VERSION 5.8 ;
BUSBITCHARS "[]" ;
DIVIDERCHAR "/" ;
UNITS
    DATABASE MICRONS 1000 ;
END UNITS

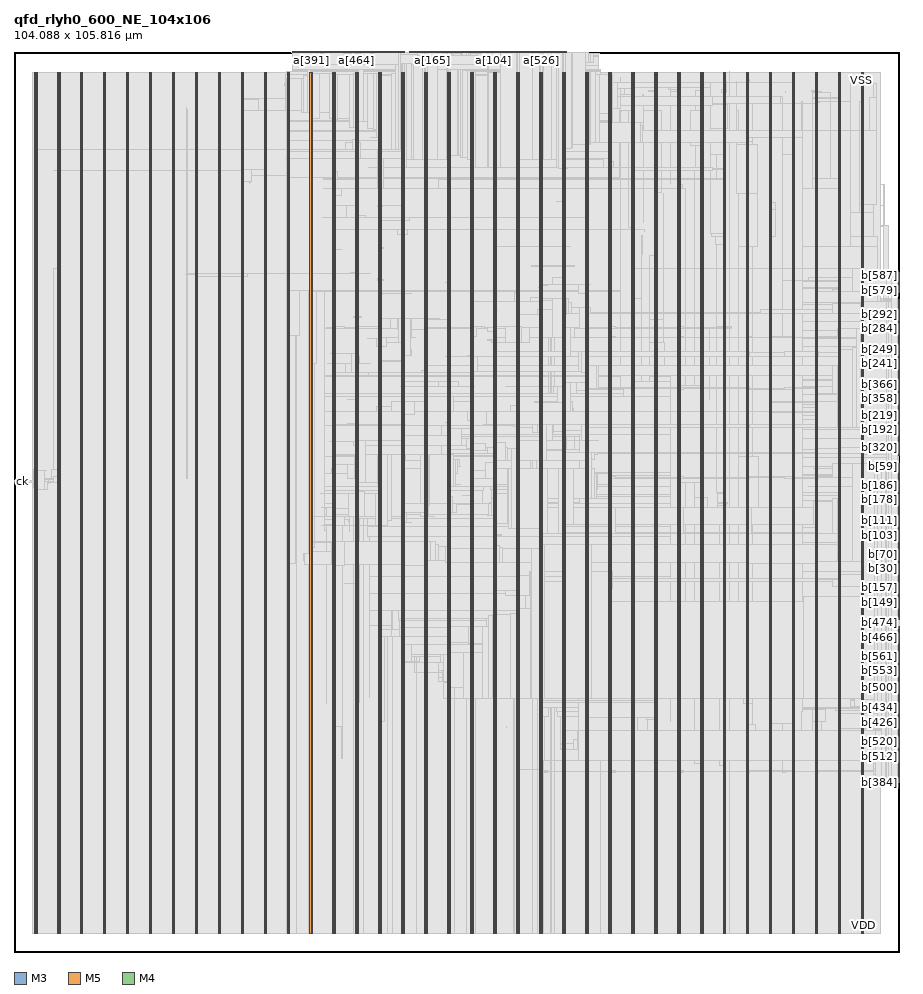
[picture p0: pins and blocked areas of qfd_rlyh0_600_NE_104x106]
MACRO qfd_rlyh0_600_NE_104x106
  FOREIGN qfd_rlyh0_600_NE_104x106 0 0 ;
  CLASS BLOCK ;
  SIZE 104.088 BY 105.816 ;
  PIN a[0]
    DIRECTION INPUT ;
    USE SIGNAL ;
    PORT
      LAYER M3 ;
        RECT  58.068 105.779 58.086 105.816 ;
    END
  END a[0]
  PIN a[100]
    DIRECTION INPUT ;
    USE SIGNAL ;
    PORT
      LAYER M3 ;
        RECT  56.052 105.779 56.07 105.816 ;
    END
  END a[100]
  PIN a[101]
    DIRECTION INPUT ;
    USE SIGNAL ;
    PORT
      LAYER M3 ;
        RECT  56.124 105.779 56.142 105.816 ;
    END
  END a[101]
  PIN a[102]
    DIRECTION INPUT ;
    USE SIGNAL ;
    PORT
      LAYER M3 ;
        RECT  56.196 105.779 56.214 105.816 ;
    END
  END a[102]
  PIN a[103]
    DIRECTION INPUT ;
    USE SIGNAL ;
    PORT
      LAYER M3 ;
        RECT  56.268 105.779 56.286 105.816 ;
    END
  END a[103]
  PIN a[104]
    DIRECTION INPUT ;
    USE SIGNAL ;
    PORT
      LAYER M3 ;
        RECT  56.34 105.779 56.358 105.816 ;
    END
  END a[104]
  PIN a[105]
    DIRECTION INPUT ;
    USE SIGNAL ;
    PORT
      LAYER M3 ;
        RECT  56.412 105.779 56.43 105.816 ;
    END
  END a[105]
  PIN a[106]
    DIRECTION INPUT ;
    USE SIGNAL ;
    PORT
      LAYER M3 ;
        RECT  56.484 105.779 56.502 105.816 ;
    END
  END a[106]
  PIN a[107]
    DIRECTION INPUT ;
    USE SIGNAL ;
    PORT
      LAYER M3 ;
        RECT  56.556 105.779 56.574 105.816 ;
    END
  END a[107]
  PIN a[108]
    DIRECTION INPUT ;
    USE SIGNAL ;
    PORT
      LAYER M3 ;
        RECT  56.628 105.779 56.646 105.816 ;
    END
  END a[108]
  PIN a[109]
    DIRECTION INPUT ;
    USE SIGNAL ;
    PORT
      LAYER M3 ;
        RECT  56.7 105.779 56.718 105.816 ;
    END
  END a[109]
  PIN a[10]
    DIRECTION INPUT ;
    USE SIGNAL ;
    PORT
      LAYER M3 ;
        RECT  58.788 105.779 58.806 105.816 ;
    END
  END a[10]
  PIN a[110]
    DIRECTION INPUT ;
    USE SIGNAL ;
    PORT
      LAYER M3 ;
        RECT  56.772 105.779 56.79 105.816 ;
    END
  END a[110]
  PIN a[111]
    DIRECTION INPUT ;
    USE SIGNAL ;
    PORT
      LAYER M3 ;
        RECT  56.844 105.779 56.862 105.816 ;
    END
  END a[111]
  PIN a[112]
    DIRECTION INPUT ;
    USE SIGNAL ;
    PORT
      LAYER M3 ;
        RECT  56.916 105.779 56.934 105.816 ;
    END
  END a[112]
  PIN a[113]
    DIRECTION INPUT ;
    USE SIGNAL ;
    PORT
      LAYER M3 ;
        RECT  56.988 105.779 57.006 105.816 ;
    END
  END a[113]
  PIN a[114]
    DIRECTION INPUT ;
    USE SIGNAL ;
    PORT
      LAYER M3 ;
        RECT  57.06 105.779 57.078 105.816 ;
    END
  END a[114]
  PIN a[115]
    DIRECTION INPUT ;
    USE SIGNAL ;
    PORT
      LAYER M3 ;
        RECT  57.132 105.779 57.15 105.816 ;
    END
  END a[115]
  PIN a[116]
    DIRECTION INPUT ;
    USE SIGNAL ;
    PORT
      LAYER M3 ;
        RECT  57.204 105.779 57.222 105.816 ;
    END
  END a[116]
  PIN a[117]
    DIRECTION INPUT ;
    USE SIGNAL ;
    PORT
      LAYER M3 ;
        RECT  57.276 105.779 57.294 105.816 ;
    END
  END a[117]
  PIN a[118]
    DIRECTION INPUT ;
    USE SIGNAL ;
    PORT
      LAYER M3 ;
        RECT  57.348 105.779 57.366 105.816 ;
    END
  END a[118]
  PIN a[119]
    DIRECTION INPUT ;
    USE SIGNAL ;
    PORT
      LAYER M3 ;
        RECT  57.42 105.779 57.438 105.816 ;
    END
  END a[119]
  PIN a[11]
    DIRECTION INPUT ;
    USE SIGNAL ;
    PORT
      LAYER M3 ;
        RECT  58.86 105.779 58.878 105.816 ;
    END
  END a[11]
  PIN a[120]
    DIRECTION INPUT ;
    USE SIGNAL ;
    PORT
      LAYER M3 ;
        RECT  57.492 105.779 57.51 105.816 ;
    END
  END a[120]
  PIN a[121]
    DIRECTION INPUT ;
    USE SIGNAL ;
    PORT
      LAYER M3 ;
        RECT  57.564 105.779 57.582 105.816 ;
    END
  END a[121]
  PIN a[122]
    DIRECTION INPUT ;
    USE SIGNAL ;
    PORT
      LAYER M3 ;
        RECT  57.636 105.779 57.654 105.816 ;
    END
  END a[122]
  PIN a[123]
    DIRECTION INPUT ;
    USE SIGNAL ;
    PORT
      LAYER M3 ;
        RECT  57.708 105.779 57.726 105.816 ;
    END
  END a[123]
  PIN a[124]
    DIRECTION INPUT ;
    USE SIGNAL ;
    PORT
      LAYER M3 ;
        RECT  57.78 105.779 57.798 105.816 ;
    END
  END a[124]
  PIN a[125]
    DIRECTION INPUT ;
    USE SIGNAL ;
    PORT
      LAYER M3 ;
        RECT  57.852 105.779 57.87 105.816 ;
    END
  END a[125]
  PIN a[126]
    DIRECTION INPUT ;
    USE SIGNAL ;
    PORT
      LAYER M3 ;
        RECT  57.924 105.779 57.942 105.816 ;
    END
  END a[126]
  PIN a[127]
    DIRECTION INPUT ;
    USE SIGNAL ;
    PORT
      LAYER M3 ;
        RECT  57.996 105.779 58.014 105.816 ;
    END
  END a[127]
  PIN a[128]
    DIRECTION INPUT ;
    USE SIGNAL ;
    PORT
      LAYER M3 ;
        RECT  53.46 105.779 53.478 105.816 ;
    END
  END a[128]
  PIN a[129]
    DIRECTION INPUT ;
    USE SIGNAL ;
    PORT
      LAYER M3 ;
        RECT  53.532 105.779 53.55 105.816 ;
    END
  END a[129]
  PIN a[12]
    DIRECTION INPUT ;
    USE SIGNAL ;
    PORT
      LAYER M3 ;
        RECT  58.932 105.779 58.95 105.816 ;
    END
  END a[12]
  PIN a[130]
    DIRECTION INPUT ;
    USE SIGNAL ;
    PORT
      LAYER M3 ;
        RECT  53.604 105.779 53.622 105.816 ;
    END
  END a[130]
  PIN a[131]
    DIRECTION INPUT ;
    USE SIGNAL ;
    PORT
      LAYER M3 ;
        RECT  53.676 105.779 53.694 105.816 ;
    END
  END a[131]
  PIN a[132]
    DIRECTION INPUT ;
    USE SIGNAL ;
    PORT
      LAYER M3 ;
        RECT  53.748 105.779 53.766 105.816 ;
    END
  END a[132]
  PIN a[133]
    DIRECTION INPUT ;
    USE SIGNAL ;
    PORT
      LAYER M3 ;
        RECT  53.82 105.779 53.838 105.816 ;
    END
  END a[133]
  PIN a[134]
    DIRECTION INPUT ;
    USE SIGNAL ;
    PORT
      LAYER M3 ;
        RECT  53.892 105.779 53.91 105.816 ;
    END
  END a[134]
  PIN a[135]
    DIRECTION INPUT ;
    USE SIGNAL ;
    PORT
      LAYER M3 ;
        RECT  53.964 105.779 53.982 105.816 ;
    END
  END a[135]
  PIN a[136]
    DIRECTION INPUT ;
    USE SIGNAL ;
    PORT
      LAYER M3 ;
        RECT  54.036 105.779 54.054 105.816 ;
    END
  END a[136]
  PIN a[137]
    DIRECTION INPUT ;
    USE SIGNAL ;
    PORT
      LAYER M3 ;
        RECT  54.108 105.779 54.126 105.816 ;
    END
  END a[137]
  PIN a[138]
    DIRECTION INPUT ;
    USE SIGNAL ;
    PORT
      LAYER M3 ;
        RECT  54.18 105.779 54.198 105.816 ;
    END
  END a[138]
  PIN a[139]
    DIRECTION INPUT ;
    USE SIGNAL ;
    PORT
      LAYER M3 ;
        RECT  54.252 105.779 54.27 105.816 ;
    END
  END a[139]
  PIN a[13]
    DIRECTION INPUT ;
    USE SIGNAL ;
    PORT
      LAYER M3 ;
        RECT  59.004 105.779 59.022 105.816 ;
    END
  END a[13]
  PIN a[140]
    DIRECTION INPUT ;
    USE SIGNAL ;
    PORT
      LAYER M3 ;
        RECT  54.324 105.779 54.342 105.816 ;
    END
  END a[140]
  PIN a[141]
    DIRECTION INPUT ;
    USE SIGNAL ;
    PORT
      LAYER M3 ;
        RECT  54.396 105.779 54.414 105.816 ;
    END
  END a[141]
  PIN a[142]
    DIRECTION INPUT ;
    USE SIGNAL ;
    PORT
      LAYER M3 ;
        RECT  54.468 105.779 54.486 105.816 ;
    END
  END a[142]
  PIN a[143]
    DIRECTION INPUT ;
    USE SIGNAL ;
    PORT
      LAYER M3 ;
        RECT  54.54 105.779 54.558 105.816 ;
    END
  END a[143]
  PIN a[144]
    DIRECTION INPUT ;
    USE SIGNAL ;
    PORT
      LAYER M3 ;
        RECT  54.612 105.779 54.63 105.816 ;
    END
  END a[144]
  PIN a[145]
    DIRECTION INPUT ;
    USE SIGNAL ;
    PORT
      LAYER M3 ;
        RECT  54.684 105.779 54.702 105.816 ;
    END
  END a[145]
  PIN a[146]
    DIRECTION INPUT ;
    USE SIGNAL ;
    PORT
      LAYER M3 ;
        RECT  54.756 105.779 54.774 105.816 ;
    END
  END a[146]
  PIN a[147]
    DIRECTION INPUT ;
    USE SIGNAL ;
    PORT
      LAYER M3 ;
        RECT  54.828 105.779 54.846 105.816 ;
    END
  END a[147]
  PIN a[148]
    DIRECTION INPUT ;
    USE SIGNAL ;
    PORT
      LAYER M3 ;
        RECT  54.9 105.779 54.918 105.816 ;
    END
  END a[148]
  PIN a[149]
    DIRECTION INPUT ;
    USE SIGNAL ;
    PORT
      LAYER M3 ;
        RECT  54.972 105.779 54.99 105.816 ;
    END
  END a[149]
  PIN a[14]
    DIRECTION INPUT ;
    USE SIGNAL ;
    PORT
      LAYER M3 ;
        RECT  59.076 105.779 59.094 105.816 ;
    END
  END a[14]
  PIN a[150]
    DIRECTION INPUT ;
    USE SIGNAL ;
    PORT
      LAYER M3 ;
        RECT  55.044 105.779 55.062 105.816 ;
    END
  END a[150]
  PIN a[151]
    DIRECTION INPUT ;
    USE SIGNAL ;
    PORT
      LAYER M3 ;
        RECT  55.116 105.779 55.134 105.816 ;
    END
  END a[151]
  PIN a[152]
    DIRECTION INPUT ;
    USE SIGNAL ;
    PORT
      LAYER M3 ;
        RECT  55.188 105.779 55.206 105.816 ;
    END
  END a[152]
  PIN a[153]
    DIRECTION INPUT ;
    USE SIGNAL ;
    PORT
      LAYER M3 ;
        RECT  55.26 105.779 55.278 105.816 ;
    END
  END a[153]
  PIN a[154]
    DIRECTION INPUT ;
    USE SIGNAL ;
    PORT
      LAYER M3 ;
        RECT  55.332 105.779 55.35 105.816 ;
    END
  END a[154]
  PIN a[155]
    DIRECTION INPUT ;
    USE SIGNAL ;
    PORT
      LAYER M3 ;
        RECT  55.404 105.779 55.422 105.816 ;
    END
  END a[155]
  PIN a[156]
    DIRECTION INPUT ;
    USE SIGNAL ;
    PORT
      LAYER M3 ;
        RECT  55.476 105.779 55.494 105.816 ;
    END
  END a[156]
  PIN a[157]
    DIRECTION INPUT ;
    USE SIGNAL ;
    PORT
      LAYER M3 ;
        RECT  55.548 105.779 55.566 105.816 ;
    END
  END a[157]
  PIN a[158]
    DIRECTION INPUT ;
    USE SIGNAL ;
    PORT
      LAYER M3 ;
        RECT  55.62 105.779 55.638 105.816 ;
    END
  END a[158]
  PIN a[159]
    DIRECTION INPUT ;
    USE SIGNAL ;
    PORT
      LAYER M3 ;
        RECT  55.692 105.779 55.71 105.816 ;
    END
  END a[159]
  PIN a[15]
    DIRECTION INPUT ;
    USE SIGNAL ;
    PORT
      LAYER M3 ;
        RECT  59.148 105.779 59.166 105.816 ;
    END
  END a[15]
  PIN a[160]
    DIRECTION INPUT ;
    USE SIGNAL ;
    PORT
      LAYER M3 ;
        RECT  48.852 105.779 48.87 105.816 ;
    END
  END a[160]
  PIN a[161]
    DIRECTION INPUT ;
    USE SIGNAL ;
    PORT
      LAYER M3 ;
        RECT  48.924 105.779 48.942 105.816 ;
    END
  END a[161]
  PIN a[162]
    DIRECTION INPUT ;
    USE SIGNAL ;
    PORT
      LAYER M3 ;
        RECT  48.996 105.779 49.014 105.816 ;
    END
  END a[162]
  PIN a[163]
    DIRECTION INPUT ;
    USE SIGNAL ;
    PORT
      LAYER M3 ;
        RECT  49.068 105.779 49.086 105.816 ;
    END
  END a[163]
  PIN a[164]
    DIRECTION INPUT ;
    USE SIGNAL ;
    PORT
      LAYER M3 ;
        RECT  49.14 105.779 49.158 105.816 ;
    END
  END a[164]
  PIN a[165]
    DIRECTION INPUT ;
    USE SIGNAL ;
    PORT
      LAYER M3 ;
        RECT  49.212 105.779 49.23 105.816 ;
    END
  END a[165]
  PIN a[166]
    DIRECTION INPUT ;
    USE SIGNAL ;
    PORT
      LAYER M3 ;
        RECT  49.284 105.779 49.302 105.816 ;
    END
  END a[166]
  PIN a[167]
    DIRECTION INPUT ;
    USE SIGNAL ;
    PORT
      LAYER M3 ;
        RECT  49.356 105.779 49.374 105.816 ;
    END
  END a[167]
  PIN a[168]
    DIRECTION INPUT ;
    USE SIGNAL ;
    PORT
      LAYER M3 ;
        RECT  49.428 105.779 49.446 105.816 ;
    END
  END a[168]
  PIN a[169]
    DIRECTION INPUT ;
    USE SIGNAL ;
    PORT
      LAYER M3 ;
        RECT  49.5 105.779 49.518 105.816 ;
    END
  END a[169]
  PIN a[16]
    DIRECTION INPUT ;
    USE SIGNAL ;
    PORT
      LAYER M3 ;
        RECT  59.22 105.779 59.238 105.816 ;
    END
  END a[16]
  PIN a[170]
    DIRECTION INPUT ;
    USE SIGNAL ;
    PORT
      LAYER M3 ;
        RECT  49.572 105.779 49.59 105.816 ;
    END
  END a[170]
  PIN a[171]
    DIRECTION INPUT ;
    USE SIGNAL ;
    PORT
      LAYER M3 ;
        RECT  49.644 105.779 49.662 105.816 ;
    END
  END a[171]
  PIN a[172]
    DIRECTION INPUT ;
    USE SIGNAL ;
    PORT
      LAYER M3 ;
        RECT  49.716 105.779 49.734 105.816 ;
    END
  END a[172]
  PIN a[173]
    DIRECTION INPUT ;
    USE SIGNAL ;
    PORT
      LAYER M3 ;
        RECT  49.788 105.779 49.806 105.816 ;
    END
  END a[173]
  PIN a[174]
    DIRECTION INPUT ;
    USE SIGNAL ;
    PORT
      LAYER M3 ;
        RECT  49.86 105.779 49.878 105.816 ;
    END
  END a[174]
  PIN a[175]
    DIRECTION INPUT ;
    USE SIGNAL ;
    PORT
      LAYER M3 ;
        RECT  49.932 105.779 49.95 105.816 ;
    END
  END a[175]
  PIN a[176]
    DIRECTION INPUT ;
    USE SIGNAL ;
    PORT
      LAYER M3 ;
        RECT  50.004 105.779 50.022 105.816 ;
    END
  END a[176]
  PIN a[177]
    DIRECTION INPUT ;
    USE SIGNAL ;
    PORT
      LAYER M3 ;
        RECT  50.076 105.779 50.094 105.816 ;
    END
  END a[177]
  PIN a[178]
    DIRECTION INPUT ;
    USE SIGNAL ;
    PORT
      LAYER M3 ;
        RECT  50.148 105.779 50.166 105.816 ;
    END
  END a[178]
  PIN a[179]
    DIRECTION INPUT ;
    USE SIGNAL ;
    PORT
      LAYER M3 ;
        RECT  50.22 105.779 50.238 105.816 ;
    END
  END a[179]
  PIN a[17]
    DIRECTION INPUT ;
    USE SIGNAL ;
    PORT
      LAYER M3 ;
        RECT  59.292 105.779 59.31 105.816 ;
    END
  END a[17]
  PIN a[180]
    DIRECTION INPUT ;
    USE SIGNAL ;
    PORT
      LAYER M3 ;
        RECT  50.292 105.779 50.31 105.816 ;
    END
  END a[180]
  PIN a[181]
    DIRECTION INPUT ;
    USE SIGNAL ;
    PORT
      LAYER M3 ;
        RECT  50.364 105.779 50.382 105.816 ;
    END
  END a[181]
  PIN a[182]
    DIRECTION INPUT ;
    USE SIGNAL ;
    PORT
      LAYER M3 ;
        RECT  50.436 105.779 50.454 105.816 ;
    END
  END a[182]
  PIN a[183]
    DIRECTION INPUT ;
    USE SIGNAL ;
    PORT
      LAYER M3 ;
        RECT  50.508 105.779 50.526 105.816 ;
    END
  END a[183]
  PIN a[184]
    DIRECTION INPUT ;
    USE SIGNAL ;
    PORT
      LAYER M3 ;
        RECT  50.58 105.779 50.598 105.816 ;
    END
  END a[184]
  PIN a[185]
    DIRECTION INPUT ;
    USE SIGNAL ;
    PORT
      LAYER M3 ;
        RECT  50.652 105.779 50.67 105.816 ;
    END
  END a[185]
  PIN a[186]
    DIRECTION INPUT ;
    USE SIGNAL ;
    PORT
      LAYER M3 ;
        RECT  50.724 105.779 50.742 105.816 ;
    END
  END a[186]
  PIN a[187]
    DIRECTION INPUT ;
    USE SIGNAL ;
    PORT
      LAYER M3 ;
        RECT  50.796 105.779 50.814 105.816 ;
    END
  END a[187]
  PIN a[188]
    DIRECTION INPUT ;
    USE SIGNAL ;
    PORT
      LAYER M3 ;
        RECT  50.868 105.779 50.886 105.816 ;
    END
  END a[188]
  PIN a[189]
    DIRECTION INPUT ;
    USE SIGNAL ;
    PORT
      LAYER M3 ;
        RECT  50.94 105.779 50.958 105.816 ;
    END
  END a[189]
  PIN a[18]
    DIRECTION INPUT ;
    USE SIGNAL ;
    PORT
      LAYER M3 ;
        RECT  59.364 105.779 59.382 105.816 ;
    END
  END a[18]
  PIN a[190]
    DIRECTION INPUT ;
    USE SIGNAL ;
    PORT
      LAYER M3 ;
        RECT  51.012 105.779 51.03 105.816 ;
    END
  END a[190]
  PIN a[191]
    DIRECTION INPUT ;
    USE SIGNAL ;
    PORT
      LAYER M3 ;
        RECT  51.084 105.779 51.102 105.816 ;
    END
  END a[191]
  PIN a[192]
    DIRECTION INPUT ;
    USE SIGNAL ;
    PORT
      LAYER M5 ;
        RECT  49.68 105.732 49.704 105.816 ;
    END
  END a[192]
  PIN a[193]
    DIRECTION INPUT ;
    USE SIGNAL ;
    PORT
      LAYER M5 ;
        RECT  49.776 105.732 49.8 105.816 ;
    END
  END a[193]
  PIN a[194]
    DIRECTION INPUT ;
    USE SIGNAL ;
    PORT
      LAYER M5 ;
        RECT  49.872 105.732 49.896 105.816 ;
    END
  END a[194]
  PIN a[195]
    DIRECTION INPUT ;
    USE SIGNAL ;
    PORT
      LAYER M5 ;
        RECT  49.968 105.732 49.992 105.816 ;
    END
  END a[195]
  PIN a[196]
    DIRECTION INPUT ;
    USE SIGNAL ;
    PORT
      LAYER M5 ;
        RECT  50.064 105.732 50.088 105.816 ;
    END
  END a[196]
  PIN a[197]
    DIRECTION INPUT ;
    USE SIGNAL ;
    PORT
      LAYER M5 ;
        RECT  50.16 105.732 50.184 105.816 ;
    END
  END a[197]
  PIN a[198]
    DIRECTION INPUT ;
    USE SIGNAL ;
    PORT
      LAYER M5 ;
        RECT  50.256 105.732 50.28 105.816 ;
    END
  END a[198]
  PIN a[199]
    DIRECTION INPUT ;
    USE SIGNAL ;
    PORT
      LAYER M5 ;
        RECT  50.352 105.732 50.376 105.816 ;
    END
  END a[199]
  PIN a[19]
    DIRECTION INPUT ;
    USE SIGNAL ;
    PORT
      LAYER M3 ;
        RECT  59.436 105.779 59.454 105.816 ;
    END
  END a[19]
  PIN a[1]
    DIRECTION INPUT ;
    USE SIGNAL ;
    PORT
      LAYER M3 ;
        RECT  58.14 105.779 58.158 105.816 ;
    END
  END a[1]
  PIN a[200]
    DIRECTION INPUT ;
    USE SIGNAL ;
    PORT
      LAYER M5 ;
        RECT  50.448 105.732 50.472 105.816 ;
    END
  END a[200]
  PIN a[201]
    DIRECTION INPUT ;
    USE SIGNAL ;
    PORT
      LAYER M5 ;
        RECT  50.544 105.732 50.568 105.816 ;
    END
  END a[201]
  PIN a[202]
    DIRECTION INPUT ;
    USE SIGNAL ;
    PORT
      LAYER M5 ;
        RECT  50.64 105.732 50.664 105.816 ;
    END
  END a[202]
  PIN a[203]
    DIRECTION INPUT ;
    USE SIGNAL ;
    PORT
      LAYER M5 ;
        RECT  50.736 105.732 50.76 105.816 ;
    END
  END a[203]
  PIN a[204]
    DIRECTION INPUT ;
    USE SIGNAL ;
    PORT
      LAYER M5 ;
        RECT  50.832 105.732 50.856 105.816 ;
    END
  END a[204]
  PIN a[205]
    DIRECTION INPUT ;
    USE SIGNAL ;
    PORT
      LAYER M5 ;
        RECT  50.928 105.732 50.952 105.816 ;
    END
  END a[205]
  PIN a[206]
    DIRECTION INPUT ;
    USE SIGNAL ;
    PORT
      LAYER M5 ;
        RECT  51.024 105.732 51.048 105.816 ;
    END
  END a[206]
  PIN a[207]
    DIRECTION INPUT ;
    USE SIGNAL ;
    PORT
      LAYER M5 ;
        RECT  51.12 105.732 51.144 105.816 ;
    END
  END a[207]
  PIN a[208]
    DIRECTION INPUT ;
    USE SIGNAL ;
    PORT
      LAYER M5 ;
        RECT  51.216 105.732 51.24 105.816 ;
    END
  END a[208]
  PIN a[209]
    DIRECTION INPUT ;
    USE SIGNAL ;
    PORT
      LAYER M5 ;
        RECT  51.312 105.732 51.336 105.816 ;
    END
  END a[209]
  PIN a[20]
    DIRECTION INPUT ;
    USE SIGNAL ;
    PORT
      LAYER M3 ;
        RECT  59.508 105.779 59.526 105.816 ;
    END
  END a[20]
  PIN a[210]
    DIRECTION INPUT ;
    USE SIGNAL ;
    PORT
      LAYER M5 ;
        RECT  51.408 105.732 51.432 105.816 ;
    END
  END a[210]
  PIN a[211]
    DIRECTION INPUT ;
    USE SIGNAL ;
    PORT
      LAYER M5 ;
        RECT  51.504 105.732 51.528 105.816 ;
    END
  END a[211]
  PIN a[212]
    DIRECTION INPUT ;
    USE SIGNAL ;
    PORT
      LAYER M5 ;
        RECT  51.6 105.732 51.624 105.816 ;
    END
  END a[212]
  PIN a[213]
    DIRECTION INPUT ;
    USE SIGNAL ;
    PORT
      LAYER M5 ;
        RECT  51.696 105.732 51.72 105.816 ;
    END
  END a[213]
  PIN a[214]
    DIRECTION INPUT ;
    USE SIGNAL ;
    PORT
      LAYER M5 ;
        RECT  51.792 105.732 51.816 105.816 ;
    END
  END a[214]
  PIN a[215]
    DIRECTION INPUT ;
    USE SIGNAL ;
    PORT
      LAYER M5 ;
        RECT  51.888 105.732 51.912 105.816 ;
    END
  END a[215]
  PIN a[216]
    DIRECTION INPUT ;
    USE SIGNAL ;
    PORT
      LAYER M5 ;
        RECT  51.984 105.732 52.008 105.816 ;
    END
  END a[216]
  PIN a[217]
    DIRECTION INPUT ;
    USE SIGNAL ;
    PORT
      LAYER M5 ;
        RECT  52.08 105.732 52.104 105.816 ;
    END
  END a[217]
  PIN a[218]
    DIRECTION INPUT ;
    USE SIGNAL ;
    PORT
      LAYER M5 ;
        RECT  52.176 105.732 52.2 105.816 ;
    END
  END a[218]
  PIN a[219]
    DIRECTION INPUT ;
    USE SIGNAL ;
    PORT
      LAYER M5 ;
        RECT  52.272 105.732 52.296 105.816 ;
    END
  END a[219]
  PIN a[21]
    DIRECTION INPUT ;
    USE SIGNAL ;
    PORT
      LAYER M3 ;
        RECT  59.58 105.779 59.598 105.816 ;
    END
  END a[21]
  PIN a[220]
    DIRECTION INPUT ;
    USE SIGNAL ;
    PORT
      LAYER M5 ;
        RECT  52.368 105.732 52.392 105.816 ;
    END
  END a[220]
  PIN a[221]
    DIRECTION INPUT ;
    USE SIGNAL ;
    PORT
      LAYER M5 ;
        RECT  52.464 105.732 52.488 105.816 ;
    END
  END a[221]
  PIN a[222]
    DIRECTION INPUT ;
    USE SIGNAL ;
    PORT
      LAYER M5 ;
        RECT  52.56 105.732 52.584 105.816 ;
    END
  END a[222]
  PIN a[223]
    DIRECTION INPUT ;
    USE SIGNAL ;
    PORT
      LAYER M5 ;
        RECT  52.656 105.732 52.68 105.816 ;
    END
  END a[223]
  PIN a[224]
    DIRECTION INPUT ;
    USE SIGNAL ;
    PORT
      LAYER M5 ;
        RECT  46.608 105.732 46.632 105.816 ;
    END
  END a[224]
  PIN a[225]
    DIRECTION INPUT ;
    USE SIGNAL ;
    PORT
      LAYER M5 ;
        RECT  46.704 105.732 46.728 105.816 ;
    END
  END a[225]
  PIN a[226]
    DIRECTION INPUT ;
    USE SIGNAL ;
    PORT
      LAYER M5 ;
        RECT  46.8 105.732 46.824 105.816 ;
    END
  END a[226]
  PIN a[227]
    DIRECTION INPUT ;
    USE SIGNAL ;
    PORT
      LAYER M5 ;
        RECT  46.896 105.732 46.92 105.816 ;
    END
  END a[227]
  PIN a[228]
    DIRECTION INPUT ;
    USE SIGNAL ;
    PORT
      LAYER M5 ;
        RECT  46.992 105.732 47.016 105.816 ;
    END
  END a[228]
  PIN a[229]
    DIRECTION INPUT ;
    USE SIGNAL ;
    PORT
      LAYER M5 ;
        RECT  47.088 105.732 47.112 105.816 ;
    END
  END a[229]
  PIN a[22]
    DIRECTION INPUT ;
    USE SIGNAL ;
    PORT
      LAYER M3 ;
        RECT  59.652 105.779 59.67 105.816 ;
    END
  END a[22]
  PIN a[230]
    DIRECTION INPUT ;
    USE SIGNAL ;
    PORT
      LAYER M5 ;
        RECT  47.184 105.732 47.208 105.816 ;
    END
  END a[230]
  PIN a[231]
    DIRECTION INPUT ;
    USE SIGNAL ;
    PORT
      LAYER M5 ;
        RECT  47.28 105.732 47.304 105.816 ;
    END
  END a[231]
  PIN a[232]
    DIRECTION INPUT ;
    USE SIGNAL ;
    PORT
      LAYER M5 ;
        RECT  47.376 105.732 47.4 105.816 ;
    END
  END a[232]
  PIN a[233]
    DIRECTION INPUT ;
    USE SIGNAL ;
    PORT
      LAYER M5 ;
        RECT  47.472 105.732 47.496 105.816 ;
    END
  END a[233]
  PIN a[234]
    DIRECTION INPUT ;
    USE SIGNAL ;
    PORT
      LAYER M5 ;
        RECT  47.568 105.732 47.592 105.816 ;
    END
  END a[234]
  PIN a[235]
    DIRECTION INPUT ;
    USE SIGNAL ;
    PORT
      LAYER M5 ;
        RECT  47.664 105.732 47.688 105.816 ;
    END
  END a[235]
  PIN a[236]
    DIRECTION INPUT ;
    USE SIGNAL ;
    PORT
      LAYER M5 ;
        RECT  47.76 105.732 47.784 105.816 ;
    END
  END a[236]
  PIN a[237]
    DIRECTION INPUT ;
    USE SIGNAL ;
    PORT
      LAYER M5 ;
        RECT  47.856 105.732 47.88 105.816 ;
    END
  END a[237]
  PIN a[238]
    DIRECTION INPUT ;
    USE SIGNAL ;
    PORT
      LAYER M5 ;
        RECT  47.952 105.732 47.976 105.816 ;
    END
  END a[238]
  PIN a[239]
    DIRECTION INPUT ;
    USE SIGNAL ;
    PORT
      LAYER M5 ;
        RECT  48.048 105.732 48.072 105.816 ;
    END
  END a[239]
  PIN a[23]
    DIRECTION INPUT ;
    USE SIGNAL ;
    PORT
      LAYER M3 ;
        RECT  59.724 105.779 59.742 105.816 ;
    END
  END a[23]
  PIN a[240]
    DIRECTION INPUT ;
    USE SIGNAL ;
    PORT
      LAYER M5 ;
        RECT  48.144 105.732 48.168 105.816 ;
    END
  END a[240]
  PIN a[241]
    DIRECTION INPUT ;
    USE SIGNAL ;
    PORT
      LAYER M5 ;
        RECT  48.24 105.732 48.264 105.816 ;
    END
  END a[241]
  PIN a[242]
    DIRECTION INPUT ;
    USE SIGNAL ;
    PORT
      LAYER M5 ;
        RECT  48.336 105.732 48.36 105.816 ;
    END
  END a[242]
  PIN a[243]
    DIRECTION INPUT ;
    USE SIGNAL ;
    PORT
      LAYER M5 ;
        RECT  48.432 105.732 48.456 105.816 ;
    END
  END a[243]
  PIN a[244]
    DIRECTION INPUT ;
    USE SIGNAL ;
    PORT
      LAYER M5 ;
        RECT  48.528 105.732 48.552 105.816 ;
    END
  END a[244]
  PIN a[245]
    DIRECTION INPUT ;
    USE SIGNAL ;
    PORT
      LAYER M5 ;
        RECT  48.624 105.732 48.648 105.816 ;
    END
  END a[245]
  PIN a[246]
    DIRECTION INPUT ;
    USE SIGNAL ;
    PORT
      LAYER M5 ;
        RECT  48.72 105.732 48.744 105.816 ;
    END
  END a[246]
  PIN a[247]
    DIRECTION INPUT ;
    USE SIGNAL ;
    PORT
      LAYER M5 ;
        RECT  48.816 105.732 48.84 105.816 ;
    END
  END a[247]
  PIN a[248]
    DIRECTION INPUT ;
    USE SIGNAL ;
    PORT
      LAYER M5 ;
        RECT  48.912 105.732 48.936 105.816 ;
    END
  END a[248]
  PIN a[249]
    DIRECTION INPUT ;
    USE SIGNAL ;
    PORT
      LAYER M5 ;
        RECT  49.008 105.732 49.032 105.816 ;
    END
  END a[249]
  PIN a[24]
    DIRECTION INPUT ;
    USE SIGNAL ;
    PORT
      LAYER M3 ;
        RECT  59.796 105.779 59.814 105.816 ;
    END
  END a[24]
  PIN a[250]
    DIRECTION INPUT ;
    USE SIGNAL ;
    PORT
      LAYER M5 ;
        RECT  49.104 105.732 49.128 105.816 ;
    END
  END a[250]
  PIN a[251]
    DIRECTION INPUT ;
    USE SIGNAL ;
    PORT
      LAYER M5 ;
        RECT  49.2 105.732 49.224 105.816 ;
    END
  END a[251]
  PIN a[252]
    DIRECTION INPUT ;
    USE SIGNAL ;
    PORT
      LAYER M5 ;
        RECT  49.296 105.732 49.32 105.816 ;
    END
  END a[252]
  PIN a[253]
    DIRECTION INPUT ;
    USE SIGNAL ;
    PORT
      LAYER M5 ;
        RECT  49.392 105.732 49.416 105.816 ;
    END
  END a[253]
  PIN a[254]
    DIRECTION INPUT ;
    USE SIGNAL ;
    PORT
      LAYER M5 ;
        RECT  49.488 105.732 49.512 105.816 ;
    END
  END a[254]
  PIN a[255]
    DIRECTION INPUT ;
    USE SIGNAL ;
    PORT
      LAYER M5 ;
        RECT  49.584 105.732 49.608 105.816 ;
    END
  END a[255]
  PIN a[256]
    DIRECTION INPUT ;
    USE SIGNAL ;
    PORT
      LAYER M5 ;
        RECT  52.752 105.732 52.776 105.816 ;
    END
  END a[256]
  PIN a[257]
    DIRECTION INPUT ;
    USE SIGNAL ;
    PORT
      LAYER M5 ;
        RECT  52.848 105.732 52.872 105.816 ;
    END
  END a[257]
  PIN a[258]
    DIRECTION INPUT ;
    USE SIGNAL ;
    PORT
      LAYER M5 ;
        RECT  52.944 105.732 52.968 105.816 ;
    END
  END a[258]
  PIN a[259]
    DIRECTION INPUT ;
    USE SIGNAL ;
    PORT
      LAYER M5 ;
        RECT  53.04 105.732 53.064 105.816 ;
    END
  END a[259]
  PIN a[25]
    DIRECTION INPUT ;
    USE SIGNAL ;
    PORT
      LAYER M3 ;
        RECT  59.868 105.779 59.886 105.816 ;
    END
  END a[25]
  PIN a[260]
    DIRECTION INPUT ;
    USE SIGNAL ;
    PORT
      LAYER M5 ;
        RECT  53.136 105.732 53.16 105.816 ;
    END
  END a[260]
  PIN a[261]
    DIRECTION INPUT ;
    USE SIGNAL ;
    PORT
      LAYER M5 ;
        RECT  53.232 105.732 53.256 105.816 ;
    END
  END a[261]
  PIN a[262]
    DIRECTION INPUT ;
    USE SIGNAL ;
    PORT
      LAYER M5 ;
        RECT  53.328 105.732 53.352 105.816 ;
    END
  END a[262]
  PIN a[263]
    DIRECTION INPUT ;
    USE SIGNAL ;
    PORT
      LAYER M5 ;
        RECT  53.424 105.732 53.448 105.816 ;
    END
  END a[263]
  PIN a[264]
    DIRECTION INPUT ;
    USE SIGNAL ;
    PORT
      LAYER M5 ;
        RECT  53.52 105.732 53.544 105.816 ;
    END
  END a[264]
  PIN a[265]
    DIRECTION INPUT ;
    USE SIGNAL ;
    PORT
      LAYER M5 ;
        RECT  53.616 105.732 53.64 105.816 ;
    END
  END a[265]
  PIN a[266]
    DIRECTION INPUT ;
    USE SIGNAL ;
    PORT
      LAYER M5 ;
        RECT  53.712 105.732 53.736 105.816 ;
    END
  END a[266]
  PIN a[267]
    DIRECTION INPUT ;
    USE SIGNAL ;
    PORT
      LAYER M5 ;
        RECT  53.808 105.732 53.832 105.816 ;
    END
  END a[267]
  PIN a[268]
    DIRECTION INPUT ;
    USE SIGNAL ;
    PORT
      LAYER M5 ;
        RECT  53.904 105.732 53.928 105.816 ;
    END
  END a[268]
  PIN a[269]
    DIRECTION INPUT ;
    USE SIGNAL ;
    PORT
      LAYER M5 ;
        RECT  54 105.732 54.024 105.816 ;
    END
  END a[269]
  PIN a[26]
    DIRECTION INPUT ;
    USE SIGNAL ;
    PORT
      LAYER M3 ;
        RECT  59.94 105.779 59.958 105.816 ;
    END
  END a[26]
  PIN a[270]
    DIRECTION INPUT ;
    USE SIGNAL ;
    PORT
      LAYER M5 ;
        RECT  54.096 105.732 54.12 105.816 ;
    END
  END a[270]
  PIN a[271]
    DIRECTION INPUT ;
    USE SIGNAL ;
    PORT
      LAYER M5 ;
        RECT  54.192 105.732 54.216 105.816 ;
    END
  END a[271]
  PIN a[272]
    DIRECTION INPUT ;
    USE SIGNAL ;
    PORT
      LAYER M5 ;
        RECT  54.288 105.732 54.312 105.816 ;
    END
  END a[272]
  PIN a[273]
    DIRECTION INPUT ;
    USE SIGNAL ;
    PORT
      LAYER M5 ;
        RECT  54.384 105.732 54.408 105.816 ;
    END
  END a[273]
  PIN a[274]
    DIRECTION INPUT ;
    USE SIGNAL ;
    PORT
      LAYER M5 ;
        RECT  54.48 105.732 54.504 105.816 ;
    END
  END a[274]
  PIN a[275]
    DIRECTION INPUT ;
    USE SIGNAL ;
    PORT
      LAYER M5 ;
        RECT  54.576 105.732 54.6 105.816 ;
    END
  END a[275]
  PIN a[276]
    DIRECTION INPUT ;
    USE SIGNAL ;
    PORT
      LAYER M5 ;
        RECT  54.672 105.732 54.696 105.816 ;
    END
  END a[276]
  PIN a[277]
    DIRECTION INPUT ;
    USE SIGNAL ;
    PORT
      LAYER M5 ;
        RECT  54.768 105.732 54.792 105.816 ;
    END
  END a[277]
  PIN a[278]
    DIRECTION INPUT ;
    USE SIGNAL ;
    PORT
      LAYER M5 ;
        RECT  54.864 105.732 54.888 105.816 ;
    END
  END a[278]
  PIN a[279]
    DIRECTION INPUT ;
    USE SIGNAL ;
    PORT
      LAYER M5 ;
        RECT  54.96 105.732 54.984 105.816 ;
    END
  END a[279]
  PIN a[27]
    DIRECTION INPUT ;
    USE SIGNAL ;
    PORT
      LAYER M3 ;
        RECT  60.012 105.779 60.03 105.816 ;
    END
  END a[27]
  PIN a[280]
    DIRECTION INPUT ;
    USE SIGNAL ;
    PORT
      LAYER M5 ;
        RECT  55.056 105.732 55.08 105.816 ;
    END
  END a[280]
  PIN a[281]
    DIRECTION INPUT ;
    USE SIGNAL ;
    PORT
      LAYER M5 ;
        RECT  55.152 105.732 55.176 105.816 ;
    END
  END a[281]
  PIN a[282]
    DIRECTION INPUT ;
    USE SIGNAL ;
    PORT
      LAYER M5 ;
        RECT  55.248 105.732 55.272 105.816 ;
    END
  END a[282]
  PIN a[283]
    DIRECTION INPUT ;
    USE SIGNAL ;
    PORT
      LAYER M5 ;
        RECT  55.344 105.732 55.368 105.816 ;
    END
  END a[283]
  PIN a[284]
    DIRECTION INPUT ;
    USE SIGNAL ;
    PORT
      LAYER M5 ;
        RECT  55.44 105.732 55.464 105.816 ;
    END
  END a[284]
  PIN a[285]
    DIRECTION INPUT ;
    USE SIGNAL ;
    PORT
      LAYER M5 ;
        RECT  55.536 105.732 55.56 105.816 ;
    END
  END a[285]
  PIN a[286]
    DIRECTION INPUT ;
    USE SIGNAL ;
    PORT
      LAYER M5 ;
        RECT  55.632 105.732 55.656 105.816 ;
    END
  END a[286]
  PIN a[287]
    DIRECTION INPUT ;
    USE SIGNAL ;
    PORT
      LAYER M5 ;
        RECT  55.728 105.732 55.752 105.816 ;
    END
  END a[287]
  PIN a[288]
    DIRECTION INPUT ;
    USE SIGNAL ;
    PORT
      LAYER M5 ;
        RECT  58.896 105.732 58.92 105.816 ;
    END
  END a[288]
  PIN a[289]
    DIRECTION INPUT ;
    USE SIGNAL ;
    PORT
      LAYER M5 ;
        RECT  58.992 105.732 59.016 105.816 ;
    END
  END a[289]
  PIN a[28]
    DIRECTION INPUT ;
    USE SIGNAL ;
    PORT
      LAYER M3 ;
        RECT  60.084 105.779 60.102 105.816 ;
    END
  END a[28]
  PIN a[290]
    DIRECTION INPUT ;
    USE SIGNAL ;
    PORT
      LAYER M5 ;
        RECT  59.088 105.732 59.112 105.816 ;
    END
  END a[290]
  PIN a[291]
    DIRECTION INPUT ;
    USE SIGNAL ;
    PORT
      LAYER M5 ;
        RECT  59.184 105.732 59.208 105.816 ;
    END
  END a[291]
  PIN a[292]
    DIRECTION INPUT ;
    USE SIGNAL ;
    PORT
      LAYER M5 ;
        RECT  59.28 105.732 59.304 105.816 ;
    END
  END a[292]
  PIN a[293]
    DIRECTION INPUT ;
    USE SIGNAL ;
    PORT
      LAYER M5 ;
        RECT  59.376 105.732 59.4 105.816 ;
    END
  END a[293]
  PIN a[294]
    DIRECTION INPUT ;
    USE SIGNAL ;
    PORT
      LAYER M5 ;
        RECT  59.472 105.732 59.496 105.816 ;
    END
  END a[294]
  PIN a[295]
    DIRECTION INPUT ;
    USE SIGNAL ;
    PORT
      LAYER M5 ;
        RECT  59.568 105.732 59.592 105.816 ;
    END
  END a[295]
  PIN a[296]
    DIRECTION INPUT ;
    USE SIGNAL ;
    PORT
      LAYER M5 ;
        RECT  59.664 105.732 59.688 105.816 ;
    END
  END a[296]
  PIN a[297]
    DIRECTION INPUT ;
    USE SIGNAL ;
    PORT
      LAYER M5 ;
        RECT  59.76 105.732 59.784 105.816 ;
    END
  END a[297]
  PIN a[298]
    DIRECTION INPUT ;
    USE SIGNAL ;
    PORT
      LAYER M5 ;
        RECT  59.856 105.732 59.88 105.816 ;
    END
  END a[298]
  PIN a[299]
    DIRECTION INPUT ;
    USE SIGNAL ;
    PORT
      LAYER M5 ;
        RECT  59.952 105.732 59.976 105.816 ;
    END
  END a[299]
  PIN a[29]
    DIRECTION INPUT ;
    USE SIGNAL ;
    PORT
      LAYER M3 ;
        RECT  60.156 105.779 60.174 105.816 ;
    END
  END a[29]
  PIN a[2]
    DIRECTION INPUT ;
    USE SIGNAL ;
    PORT
      LAYER M3 ;
        RECT  58.212 105.779 58.23 105.816 ;
    END
  END a[2]
  PIN a[300]
    DIRECTION INPUT ;
    USE SIGNAL ;
    PORT
      LAYER M5 ;
        RECT  60.048 105.732 60.072 105.816 ;
    END
  END a[300]
  PIN a[301]
    DIRECTION INPUT ;
    USE SIGNAL ;
    PORT
      LAYER M5 ;
        RECT  60.144 105.732 60.168 105.816 ;
    END
  END a[301]
  PIN a[302]
    DIRECTION INPUT ;
    USE SIGNAL ;
    PORT
      LAYER M5 ;
        RECT  60.24 105.732 60.264 105.816 ;
    END
  END a[302]
  PIN a[303]
    DIRECTION INPUT ;
    USE SIGNAL ;
    PORT
      LAYER M5 ;
        RECT  60.336 105.732 60.36 105.816 ;
    END
  END a[303]
  PIN a[304]
    DIRECTION INPUT ;
    USE SIGNAL ;
    PORT
      LAYER M5 ;
        RECT  60.432 105.732 60.456 105.816 ;
    END
  END a[304]
  PIN a[305]
    DIRECTION INPUT ;
    USE SIGNAL ;
    PORT
      LAYER M5 ;
        RECT  60.528 105.732 60.552 105.816 ;
    END
  END a[305]
  PIN a[306]
    DIRECTION INPUT ;
    USE SIGNAL ;
    PORT
      LAYER M5 ;
        RECT  60.624 105.732 60.648 105.816 ;
    END
  END a[306]
  PIN a[307]
    DIRECTION INPUT ;
    USE SIGNAL ;
    PORT
      LAYER M5 ;
        RECT  60.72 105.732 60.744 105.816 ;
    END
  END a[307]
  PIN a[308]
    DIRECTION INPUT ;
    USE SIGNAL ;
    PORT
      LAYER M5 ;
        RECT  60.816 105.732 60.84 105.816 ;
    END
  END a[308]
  PIN a[309]
    DIRECTION INPUT ;
    USE SIGNAL ;
    PORT
      LAYER M5 ;
        RECT  60.912 105.732 60.936 105.816 ;
    END
  END a[309]
  PIN a[30]
    DIRECTION INPUT ;
    USE SIGNAL ;
    PORT
      LAYER M3 ;
        RECT  60.228 105.779 60.246 105.816 ;
    END
  END a[30]
  PIN a[310]
    DIRECTION INPUT ;
    USE SIGNAL ;
    PORT
      LAYER M5 ;
        RECT  61.008 105.732 61.032 105.816 ;
    END
  END a[310]
  PIN a[311]
    DIRECTION INPUT ;
    USE SIGNAL ;
    PORT
      LAYER M5 ;
        RECT  61.104 105.732 61.128 105.816 ;
    END
  END a[311]
  PIN a[312]
    DIRECTION INPUT ;
    USE SIGNAL ;
    PORT
      LAYER M5 ;
        RECT  61.2 105.732 61.224 105.816 ;
    END
  END a[312]
  PIN a[313]
    DIRECTION INPUT ;
    USE SIGNAL ;
    PORT
      LAYER M5 ;
        RECT  61.296 105.732 61.32 105.816 ;
    END
  END a[313]
  PIN a[314]
    DIRECTION INPUT ;
    USE SIGNAL ;
    PORT
      LAYER M5 ;
        RECT  61.392 105.732 61.416 105.816 ;
    END
  END a[314]
  PIN a[315]
    DIRECTION INPUT ;
    USE SIGNAL ;
    PORT
      LAYER M5 ;
        RECT  61.488 105.732 61.512 105.816 ;
    END
  END a[315]
  PIN a[316]
    DIRECTION INPUT ;
    USE SIGNAL ;
    PORT
      LAYER M5 ;
        RECT  61.584 105.732 61.608 105.816 ;
    END
  END a[316]
  PIN a[317]
    DIRECTION INPUT ;
    USE SIGNAL ;
    PORT
      LAYER M5 ;
        RECT  61.68 105.732 61.704 105.816 ;
    END
  END a[317]
  PIN a[318]
    DIRECTION INPUT ;
    USE SIGNAL ;
    PORT
      LAYER M5 ;
        RECT  61.776 105.732 61.8 105.816 ;
    END
  END a[318]
  PIN a[319]
    DIRECTION INPUT ;
    USE SIGNAL ;
    PORT
      LAYER M5 ;
        RECT  61.872 105.732 61.896 105.816 ;
    END
  END a[319]
  PIN a[31]
    DIRECTION INPUT ;
    USE SIGNAL ;
    PORT
      LAYER M3 ;
        RECT  60.3 105.779 60.318 105.816 ;
    END
  END a[31]
  PIN a[320]
    DIRECTION INPUT ;
    USE SIGNAL ;
    PORT
      LAYER M5 ;
        RECT  55.824 105.732 55.848 105.816 ;
    END
  END a[320]
  PIN a[321]
    DIRECTION INPUT ;
    USE SIGNAL ;
    PORT
      LAYER M5 ;
        RECT  55.92 105.732 55.944 105.816 ;
    END
  END a[321]
  PIN a[322]
    DIRECTION INPUT ;
    USE SIGNAL ;
    PORT
      LAYER M5 ;
        RECT  56.016 105.732 56.04 105.816 ;
    END
  END a[322]
  PIN a[323]
    DIRECTION INPUT ;
    USE SIGNAL ;
    PORT
      LAYER M5 ;
        RECT  56.112 105.732 56.136 105.816 ;
    END
  END a[323]
  PIN a[324]
    DIRECTION INPUT ;
    USE SIGNAL ;
    PORT
      LAYER M5 ;
        RECT  56.208 105.732 56.232 105.816 ;
    END
  END a[324]
  PIN a[325]
    DIRECTION INPUT ;
    USE SIGNAL ;
    PORT
      LAYER M5 ;
        RECT  56.304 105.732 56.328 105.816 ;
    END
  END a[325]
  PIN a[326]
    DIRECTION INPUT ;
    USE SIGNAL ;
    PORT
      LAYER M5 ;
        RECT  56.4 105.732 56.424 105.816 ;
    END
  END a[326]
  PIN a[327]
    DIRECTION INPUT ;
    USE SIGNAL ;
    PORT
      LAYER M5 ;
        RECT  56.496 105.732 56.52 105.816 ;
    END
  END a[327]
  PIN a[328]
    DIRECTION INPUT ;
    USE SIGNAL ;
    PORT
      LAYER M5 ;
        RECT  56.592 105.732 56.616 105.816 ;
    END
  END a[328]
  PIN a[329]
    DIRECTION INPUT ;
    USE SIGNAL ;
    PORT
      LAYER M5 ;
        RECT  56.688 105.732 56.712 105.816 ;
    END
  END a[329]
  PIN a[32]
    DIRECTION INPUT ;
    USE SIGNAL ;
    PORT
      LAYER M3 ;
        RECT  51.156 105.779 51.174 105.816 ;
    END
  END a[32]
  PIN a[330]
    DIRECTION INPUT ;
    USE SIGNAL ;
    PORT
      LAYER M5 ;
        RECT  56.784 105.732 56.808 105.816 ;
    END
  END a[330]
  PIN a[331]
    DIRECTION INPUT ;
    USE SIGNAL ;
    PORT
      LAYER M5 ;
        RECT  56.88 105.732 56.904 105.816 ;
    END
  END a[331]
  PIN a[332]
    DIRECTION INPUT ;
    USE SIGNAL ;
    PORT
      LAYER M5 ;
        RECT  56.976 105.732 57 105.816 ;
    END
  END a[332]
  PIN a[333]
    DIRECTION INPUT ;
    USE SIGNAL ;
    PORT
      LAYER M5 ;
        RECT  57.072 105.732 57.096 105.816 ;
    END
  END a[333]
  PIN a[334]
    DIRECTION INPUT ;
    USE SIGNAL ;
    PORT
      LAYER M5 ;
        RECT  57.168 105.732 57.192 105.816 ;
    END
  END a[334]
  PIN a[335]
    DIRECTION INPUT ;
    USE SIGNAL ;
    PORT
      LAYER M5 ;
        RECT  57.264 105.732 57.288 105.816 ;
    END
  END a[335]
  PIN a[336]
    DIRECTION INPUT ;
    USE SIGNAL ;
    PORT
      LAYER M5 ;
        RECT  57.36 105.732 57.384 105.816 ;
    END
  END a[336]
  PIN a[337]
    DIRECTION INPUT ;
    USE SIGNAL ;
    PORT
      LAYER M5 ;
        RECT  57.456 105.732 57.48 105.816 ;
    END
  END a[337]
  PIN a[338]
    DIRECTION INPUT ;
    USE SIGNAL ;
    PORT
      LAYER M5 ;
        RECT  57.552 105.732 57.576 105.816 ;
    END
  END a[338]
  PIN a[339]
    DIRECTION INPUT ;
    USE SIGNAL ;
    PORT
      LAYER M5 ;
        RECT  57.648 105.732 57.672 105.816 ;
    END
  END a[339]
  PIN a[33]
    DIRECTION INPUT ;
    USE SIGNAL ;
    PORT
      LAYER M3 ;
        RECT  51.228 105.779 51.246 105.816 ;
    END
  END a[33]
  PIN a[340]
    DIRECTION INPUT ;
    USE SIGNAL ;
    PORT
      LAYER M5 ;
        RECT  57.744 105.732 57.768 105.816 ;
    END
  END a[340]
  PIN a[341]
    DIRECTION INPUT ;
    USE SIGNAL ;
    PORT
      LAYER M5 ;
        RECT  57.84 105.732 57.864 105.816 ;
    END
  END a[341]
  PIN a[342]
    DIRECTION INPUT ;
    USE SIGNAL ;
    PORT
      LAYER M5 ;
        RECT  57.936 105.732 57.96 105.816 ;
    END
  END a[342]
  PIN a[343]
    DIRECTION INPUT ;
    USE SIGNAL ;
    PORT
      LAYER M5 ;
        RECT  58.032 105.732 58.056 105.816 ;
    END
  END a[343]
  PIN a[344]
    DIRECTION INPUT ;
    USE SIGNAL ;
    PORT
      LAYER M5 ;
        RECT  58.128 105.732 58.152 105.816 ;
    END
  END a[344]
  PIN a[345]
    DIRECTION INPUT ;
    USE SIGNAL ;
    PORT
      LAYER M5 ;
        RECT  58.224 105.732 58.248 105.816 ;
    END
  END a[345]
  PIN a[346]
    DIRECTION INPUT ;
    USE SIGNAL ;
    PORT
      LAYER M5 ;
        RECT  58.32 105.732 58.344 105.816 ;
    END
  END a[346]
  PIN a[347]
    DIRECTION INPUT ;
    USE SIGNAL ;
    PORT
      LAYER M5 ;
        RECT  58.416 105.732 58.44 105.816 ;
    END
  END a[347]
  PIN a[348]
    DIRECTION INPUT ;
    USE SIGNAL ;
    PORT
      LAYER M5 ;
        RECT  58.512 105.732 58.536 105.816 ;
    END
  END a[348]
  PIN a[349]
    DIRECTION INPUT ;
    USE SIGNAL ;
    PORT
      LAYER M5 ;
        RECT  58.608 105.732 58.632 105.816 ;
    END
  END a[349]
  PIN a[34]
    DIRECTION INPUT ;
    USE SIGNAL ;
    PORT
      LAYER M3 ;
        RECT  51.3 105.779 51.318 105.816 ;
    END
  END a[34]
  PIN a[350]
    DIRECTION INPUT ;
    USE SIGNAL ;
    PORT
      LAYER M5 ;
        RECT  58.704 105.732 58.728 105.816 ;
    END
  END a[350]
  PIN a[351]
    DIRECTION INPUT ;
    USE SIGNAL ;
    PORT
      LAYER M5 ;
        RECT  58.8 105.732 58.824 105.816 ;
    END
  END a[351]
  PIN a[352]
    DIRECTION INPUT ;
    USE SIGNAL ;
    PORT
      LAYER M5 ;
        RECT  61.968 105.732 61.992 105.816 ;
    END
  END a[352]
  PIN a[353]
    DIRECTION INPUT ;
    USE SIGNAL ;
    PORT
      LAYER M5 ;
        RECT  62.064 105.732 62.088 105.816 ;
    END
  END a[353]
  PIN a[354]
    DIRECTION INPUT ;
    USE SIGNAL ;
    PORT
      LAYER M5 ;
        RECT  62.16 105.732 62.184 105.816 ;
    END
  END a[354]
  PIN a[355]
    DIRECTION INPUT ;
    USE SIGNAL ;
    PORT
      LAYER M5 ;
        RECT  62.256 105.732 62.28 105.816 ;
    END
  END a[355]
  PIN a[356]
    DIRECTION INPUT ;
    USE SIGNAL ;
    PORT
      LAYER M5 ;
        RECT  62.352 105.732 62.376 105.816 ;
    END
  END a[356]
  PIN a[357]
    DIRECTION INPUT ;
    USE SIGNAL ;
    PORT
      LAYER M5 ;
        RECT  62.448 105.732 62.472 105.816 ;
    END
  END a[357]
  PIN a[358]
    DIRECTION INPUT ;
    USE SIGNAL ;
    PORT
      LAYER M5 ;
        RECT  62.544 105.732 62.568 105.816 ;
    END
  END a[358]
  PIN a[359]
    DIRECTION INPUT ;
    USE SIGNAL ;
    PORT
      LAYER M5 ;
        RECT  62.64 105.732 62.664 105.816 ;
    END
  END a[359]
  PIN a[35]
    DIRECTION INPUT ;
    USE SIGNAL ;
    PORT
      LAYER M3 ;
        RECT  51.372 105.779 51.39 105.816 ;
    END
  END a[35]
  PIN a[360]
    DIRECTION INPUT ;
    USE SIGNAL ;
    PORT
      LAYER M5 ;
        RECT  62.736 105.732 62.76 105.816 ;
    END
  END a[360]
  PIN a[361]
    DIRECTION INPUT ;
    USE SIGNAL ;
    PORT
      LAYER M5 ;
        RECT  62.832 105.732 62.856 105.816 ;
    END
  END a[361]
  PIN a[362]
    DIRECTION INPUT ;
    USE SIGNAL ;
    PORT
      LAYER M5 ;
        RECT  62.928 105.732 62.952 105.816 ;
    END
  END a[362]
  PIN a[363]
    DIRECTION INPUT ;
    USE SIGNAL ;
    PORT
      LAYER M5 ;
        RECT  63.024 105.732 63.048 105.816 ;
    END
  END a[363]
  PIN a[364]
    DIRECTION INPUT ;
    USE SIGNAL ;
    PORT
      LAYER M5 ;
        RECT  63.12 105.732 63.144 105.816 ;
    END
  END a[364]
  PIN a[365]
    DIRECTION INPUT ;
    USE SIGNAL ;
    PORT
      LAYER M5 ;
        RECT  63.216 105.732 63.24 105.816 ;
    END
  END a[365]
  PIN a[366]
    DIRECTION INPUT ;
    USE SIGNAL ;
    PORT
      LAYER M5 ;
        RECT  63.312 105.732 63.336 105.816 ;
    END
  END a[366]
  PIN a[367]
    DIRECTION INPUT ;
    USE SIGNAL ;
    PORT
      LAYER M5 ;
        RECT  63.408 105.732 63.432 105.816 ;
    END
  END a[367]
  PIN a[368]
    DIRECTION INPUT ;
    USE SIGNAL ;
    PORT
      LAYER M5 ;
        RECT  63.504 105.732 63.528 105.816 ;
    END
  END a[368]
  PIN a[369]
    DIRECTION INPUT ;
    USE SIGNAL ;
    PORT
      LAYER M5 ;
        RECT  63.6 105.732 63.624 105.816 ;
    END
  END a[369]
  PIN a[36]
    DIRECTION INPUT ;
    USE SIGNAL ;
    PORT
      LAYER M3 ;
        RECT  51.444 105.779 51.462 105.816 ;
    END
  END a[36]
  PIN a[370]
    DIRECTION INPUT ;
    USE SIGNAL ;
    PORT
      LAYER M5 ;
        RECT  63.696 105.732 63.72 105.816 ;
    END
  END a[370]
  PIN a[371]
    DIRECTION INPUT ;
    USE SIGNAL ;
    PORT
      LAYER M5 ;
        RECT  63.792 105.732 63.816 105.816 ;
    END
  END a[371]
  PIN a[372]
    DIRECTION INPUT ;
    USE SIGNAL ;
    PORT
      LAYER M5 ;
        RECT  63.888 105.732 63.912 105.816 ;
    END
  END a[372]
  PIN a[373]
    DIRECTION INPUT ;
    USE SIGNAL ;
    PORT
      LAYER M5 ;
        RECT  63.984 105.732 64.008 105.816 ;
    END
  END a[373]
  PIN a[374]
    DIRECTION INPUT ;
    USE SIGNAL ;
    PORT
      LAYER M5 ;
        RECT  64.08 105.732 64.104 105.816 ;
    END
  END a[374]
  PIN a[375]
    DIRECTION INPUT ;
    USE SIGNAL ;
    PORT
      LAYER M5 ;
        RECT  64.176 105.732 64.2 105.816 ;
    END
  END a[375]
  PIN a[376]
    DIRECTION INPUT ;
    USE SIGNAL ;
    PORT
      LAYER M5 ;
        RECT  64.272 105.732 64.296 105.816 ;
    END
  END a[376]
  PIN a[377]
    DIRECTION INPUT ;
    USE SIGNAL ;
    PORT
      LAYER M5 ;
        RECT  64.368 105.732 64.392 105.816 ;
    END
  END a[377]
  PIN a[378]
    DIRECTION INPUT ;
    USE SIGNAL ;
    PORT
      LAYER M5 ;
        RECT  64.464 105.732 64.488 105.816 ;
    END
  END a[378]
  PIN a[379]
    DIRECTION INPUT ;
    USE SIGNAL ;
    PORT
      LAYER M5 ;
        RECT  64.56 105.732 64.584 105.816 ;
    END
  END a[379]
  PIN a[37]
    DIRECTION INPUT ;
    USE SIGNAL ;
    PORT
      LAYER M3 ;
        RECT  51.516 105.779 51.534 105.816 ;
    END
  END a[37]
  PIN a[380]
    DIRECTION INPUT ;
    USE SIGNAL ;
    PORT
      LAYER M5 ;
        RECT  64.656 105.732 64.68 105.816 ;
    END
  END a[380]
  PIN a[381]
    DIRECTION INPUT ;
    USE SIGNAL ;
    PORT
      LAYER M5 ;
        RECT  64.752 105.732 64.776 105.816 ;
    END
  END a[381]
  PIN a[382]
    DIRECTION INPUT ;
    USE SIGNAL ;
    PORT
      LAYER M5 ;
        RECT  64.848 105.732 64.872 105.816 ;
    END
  END a[382]
  PIN a[383]
    DIRECTION INPUT ;
    USE SIGNAL ;
    PORT
      LAYER M5 ;
        RECT  64.944 105.732 64.968 105.816 ;
    END
  END a[383]
  PIN a[384]
    DIRECTION INPUT ;
    USE SIGNAL ;
    PORT
      LAYER M3 ;
        RECT  34.452 105.779 34.47 105.816 ;
    END
  END a[384]
  PIN a[385]
    DIRECTION INPUT ;
    USE SIGNAL ;
    PORT
      LAYER M3 ;
        RECT  34.524 105.779 34.542 105.816 ;
    END
  END a[385]
  PIN a[386]
    DIRECTION INPUT ;
    USE SIGNAL ;
    PORT
      LAYER M3 ;
        RECT  34.596 105.779 34.614 105.816 ;
    END
  END a[386]
  PIN a[387]
    DIRECTION INPUT ;
    USE SIGNAL ;
    PORT
      LAYER M3 ;
        RECT  34.668 105.779 34.686 105.816 ;
    END
  END a[387]
  PIN a[388]
    DIRECTION INPUT ;
    USE SIGNAL ;
    PORT
      LAYER M3 ;
        RECT  34.74 105.779 34.758 105.816 ;
    END
  END a[388]
  PIN a[389]
    DIRECTION INPUT ;
    USE SIGNAL ;
    PORT
      LAYER M3 ;
        RECT  34.812 105.779 34.83 105.816 ;
    END
  END a[389]
  PIN a[38]
    DIRECTION INPUT ;
    USE SIGNAL ;
    PORT
      LAYER M3 ;
        RECT  51.588 105.779 51.606 105.816 ;
    END
  END a[38]
  PIN a[390]
    DIRECTION INPUT ;
    USE SIGNAL ;
    PORT
      LAYER M3 ;
        RECT  34.884 105.779 34.902 105.816 ;
    END
  END a[390]
  PIN a[391]
    DIRECTION INPUT ;
    USE SIGNAL ;
    PORT
      LAYER M3 ;
        RECT  34.956 105.779 34.974 105.816 ;
    END
  END a[391]
  PIN a[392]
    DIRECTION INPUT ;
    USE SIGNAL ;
    PORT
      LAYER M3 ;
        RECT  35.028 105.779 35.046 105.816 ;
    END
  END a[392]
  PIN a[393]
    DIRECTION INPUT ;
    USE SIGNAL ;
    PORT
      LAYER M3 ;
        RECT  35.1 105.779 35.118 105.816 ;
    END
  END a[393]
  PIN a[394]
    DIRECTION INPUT ;
    USE SIGNAL ;
    PORT
      LAYER M3 ;
        RECT  35.172 105.779 35.19 105.816 ;
    END
  END a[394]
  PIN a[395]
    DIRECTION INPUT ;
    USE SIGNAL ;
    PORT
      LAYER M3 ;
        RECT  35.244 105.779 35.262 105.816 ;
    END
  END a[395]
  PIN a[396]
    DIRECTION INPUT ;
    USE SIGNAL ;
    PORT
      LAYER M3 ;
        RECT  35.316 105.779 35.334 105.816 ;
    END
  END a[396]
  PIN a[397]
    DIRECTION INPUT ;
    USE SIGNAL ;
    PORT
      LAYER M3 ;
        RECT  35.388 105.779 35.406 105.816 ;
    END
  END a[397]
  PIN a[398]
    DIRECTION INPUT ;
    USE SIGNAL ;
    PORT
      LAYER M3 ;
        RECT  35.46 105.779 35.478 105.816 ;
    END
  END a[398]
  PIN a[399]
    DIRECTION INPUT ;
    USE SIGNAL ;
    PORT
      LAYER M3 ;
        RECT  35.532 105.779 35.55 105.816 ;
    END
  END a[399]
  PIN a[39]
    DIRECTION INPUT ;
    USE SIGNAL ;
    PORT
      LAYER M3 ;
        RECT  51.66 105.779 51.678 105.816 ;
    END
  END a[39]
  PIN a[3]
    DIRECTION INPUT ;
    USE SIGNAL ;
    PORT
      LAYER M3 ;
        RECT  58.284 105.779 58.302 105.816 ;
    END
  END a[3]
  PIN a[400]
    DIRECTION INPUT ;
    USE SIGNAL ;
    PORT
      LAYER M3 ;
        RECT  35.604 105.779 35.622 105.816 ;
    END
  END a[400]
  PIN a[401]
    DIRECTION INPUT ;
    USE SIGNAL ;
    PORT
      LAYER M3 ;
        RECT  35.676 105.779 35.694 105.816 ;
    END
  END a[401]
  PIN a[402]
    DIRECTION INPUT ;
    USE SIGNAL ;
    PORT
      LAYER M3 ;
        RECT  35.748 105.779 35.766 105.816 ;
    END
  END a[402]
  PIN a[403]
    DIRECTION INPUT ;
    USE SIGNAL ;
    PORT
      LAYER M3 ;
        RECT  35.82 105.779 35.838 105.816 ;
    END
  END a[403]
  PIN a[404]
    DIRECTION INPUT ;
    USE SIGNAL ;
    PORT
      LAYER M3 ;
        RECT  35.892 105.779 35.91 105.816 ;
    END
  END a[404]
  PIN a[405]
    DIRECTION INPUT ;
    USE SIGNAL ;
    PORT
      LAYER M3 ;
        RECT  35.964 105.779 35.982 105.816 ;
    END
  END a[405]
  PIN a[406]
    DIRECTION INPUT ;
    USE SIGNAL ;
    PORT
      LAYER M3 ;
        RECT  36.036 105.779 36.054 105.816 ;
    END
  END a[406]
  PIN a[407]
    DIRECTION INPUT ;
    USE SIGNAL ;
    PORT
      LAYER M3 ;
        RECT  36.108 105.779 36.126 105.816 ;
    END
  END a[407]
  PIN a[408]
    DIRECTION INPUT ;
    USE SIGNAL ;
    PORT
      LAYER M3 ;
        RECT  36.18 105.779 36.198 105.816 ;
    END
  END a[408]
  PIN a[409]
    DIRECTION INPUT ;
    USE SIGNAL ;
    PORT
      LAYER M3 ;
        RECT  36.252 105.779 36.27 105.816 ;
    END
  END a[409]
  PIN a[40]
    DIRECTION INPUT ;
    USE SIGNAL ;
    PORT
      LAYER M3 ;
        RECT  51.732 105.779 51.75 105.816 ;
    END
  END a[40]
  PIN a[410]
    DIRECTION INPUT ;
    USE SIGNAL ;
    PORT
      LAYER M3 ;
        RECT  36.324 105.779 36.342 105.816 ;
    END
  END a[410]
  PIN a[411]
    DIRECTION INPUT ;
    USE SIGNAL ;
    PORT
      LAYER M3 ;
        RECT  36.396 105.779 36.414 105.816 ;
    END
  END a[411]
  PIN a[412]
    DIRECTION INPUT ;
    USE SIGNAL ;
    PORT
      LAYER M3 ;
        RECT  36.468 105.779 36.486 105.816 ;
    END
  END a[412]
  PIN a[413]
    DIRECTION INPUT ;
    USE SIGNAL ;
    PORT
      LAYER M3 ;
        RECT  36.54 105.779 36.558 105.816 ;
    END
  END a[413]
  PIN a[414]
    DIRECTION INPUT ;
    USE SIGNAL ;
    PORT
      LAYER M3 ;
        RECT  36.612 105.779 36.63 105.816 ;
    END
  END a[414]
  PIN a[415]
    DIRECTION INPUT ;
    USE SIGNAL ;
    PORT
      LAYER M3 ;
        RECT  36.684 105.779 36.702 105.816 ;
    END
  END a[415]
  PIN a[416]
    DIRECTION INPUT ;
    USE SIGNAL ;
    PORT
      LAYER M3 ;
        RECT  36.756 105.779 36.774 105.816 ;
    END
  END a[416]
  PIN a[417]
    DIRECTION INPUT ;
    USE SIGNAL ;
    PORT
      LAYER M3 ;
        RECT  36.828 105.779 36.846 105.816 ;
    END
  END a[417]
  PIN a[418]
    DIRECTION INPUT ;
    USE SIGNAL ;
    PORT
      LAYER M3 ;
        RECT  36.9 105.779 36.918 105.816 ;
    END
  END a[418]
  PIN a[419]
    DIRECTION INPUT ;
    USE SIGNAL ;
    PORT
      LAYER M3 ;
        RECT  36.972 105.779 36.99 105.816 ;
    END
  END a[419]
  PIN a[41]
    DIRECTION INPUT ;
    USE SIGNAL ;
    PORT
      LAYER M3 ;
        RECT  51.804 105.779 51.822 105.816 ;
    END
  END a[41]
  PIN a[420]
    DIRECTION INPUT ;
    USE SIGNAL ;
    PORT
      LAYER M3 ;
        RECT  37.044 105.779 37.062 105.816 ;
    END
  END a[420]
  PIN a[421]
    DIRECTION INPUT ;
    USE SIGNAL ;
    PORT
      LAYER M3 ;
        RECT  37.116 105.779 37.134 105.816 ;
    END
  END a[421]
  PIN a[422]
    DIRECTION INPUT ;
    USE SIGNAL ;
    PORT
      LAYER M3 ;
        RECT  37.188 105.779 37.206 105.816 ;
    END
  END a[422]
  PIN a[423]
    DIRECTION INPUT ;
    USE SIGNAL ;
    PORT
      LAYER M3 ;
        RECT  37.26 105.779 37.278 105.816 ;
    END
  END a[423]
  PIN a[424]
    DIRECTION INPUT ;
    USE SIGNAL ;
    PORT
      LAYER M3 ;
        RECT  37.332 105.779 37.35 105.816 ;
    END
  END a[424]
  PIN a[425]
    DIRECTION INPUT ;
    USE SIGNAL ;
    PORT
      LAYER M3 ;
        RECT  37.404 105.779 37.422 105.816 ;
    END
  END a[425]
  PIN a[426]
    DIRECTION INPUT ;
    USE SIGNAL ;
    PORT
      LAYER M3 ;
        RECT  37.476 105.779 37.494 105.816 ;
    END
  END a[426]
  PIN a[427]
    DIRECTION INPUT ;
    USE SIGNAL ;
    PORT
      LAYER M3 ;
        RECT  37.548 105.779 37.566 105.816 ;
    END
  END a[427]
  PIN a[428]
    DIRECTION INPUT ;
    USE SIGNAL ;
    PORT
      LAYER M3 ;
        RECT  37.62 105.779 37.638 105.816 ;
    END
  END a[428]
  PIN a[429]
    DIRECTION INPUT ;
    USE SIGNAL ;
    PORT
      LAYER M3 ;
        RECT  37.692 105.779 37.71 105.816 ;
    END
  END a[429]
  PIN a[42]
    DIRECTION INPUT ;
    USE SIGNAL ;
    PORT
      LAYER M3 ;
        RECT  51.876 105.779 51.894 105.816 ;
    END
  END a[42]
  PIN a[430]
    DIRECTION INPUT ;
    USE SIGNAL ;
    PORT
      LAYER M3 ;
        RECT  37.764 105.779 37.782 105.816 ;
    END
  END a[430]
  PIN a[431]
    DIRECTION INPUT ;
    USE SIGNAL ;
    PORT
      LAYER M3 ;
        RECT  37.836 105.779 37.854 105.816 ;
    END
  END a[431]
  PIN a[432]
    DIRECTION INPUT ;
    USE SIGNAL ;
    PORT
      LAYER M3 ;
        RECT  37.908 105.779 37.926 105.816 ;
    END
  END a[432]
  PIN a[433]
    DIRECTION INPUT ;
    USE SIGNAL ;
    PORT
      LAYER M3 ;
        RECT  37.98 105.779 37.998 105.816 ;
    END
  END a[433]
  PIN a[434]
    DIRECTION INPUT ;
    USE SIGNAL ;
    PORT
      LAYER M3 ;
        RECT  38.052 105.779 38.07 105.816 ;
    END
  END a[434]
  PIN a[435]
    DIRECTION INPUT ;
    USE SIGNAL ;
    PORT
      LAYER M3 ;
        RECT  38.124 105.779 38.142 105.816 ;
    END
  END a[435]
  PIN a[436]
    DIRECTION INPUT ;
    USE SIGNAL ;
    PORT
      LAYER M3 ;
        RECT  38.196 105.779 38.214 105.816 ;
    END
  END a[436]
  PIN a[437]
    DIRECTION INPUT ;
    USE SIGNAL ;
    PORT
      LAYER M3 ;
        RECT  38.268 105.779 38.286 105.816 ;
    END
  END a[437]
  PIN a[438]
    DIRECTION INPUT ;
    USE SIGNAL ;
    PORT
      LAYER M3 ;
        RECT  38.34 105.779 38.358 105.816 ;
    END
  END a[438]
  PIN a[439]
    DIRECTION INPUT ;
    USE SIGNAL ;
    PORT
      LAYER M3 ;
        RECT  38.412 105.779 38.43 105.816 ;
    END
  END a[439]
  PIN a[43]
    DIRECTION INPUT ;
    USE SIGNAL ;
    PORT
      LAYER M3 ;
        RECT  51.948 105.779 51.966 105.816 ;
    END
  END a[43]
  PIN a[440]
    DIRECTION INPUT ;
    USE SIGNAL ;
    PORT
      LAYER M3 ;
        RECT  38.484 105.779 38.502 105.816 ;
    END
  END a[440]
  PIN a[441]
    DIRECTION INPUT ;
    USE SIGNAL ;
    PORT
      LAYER M3 ;
        RECT  38.556 105.779 38.574 105.816 ;
    END
  END a[441]
  PIN a[442]
    DIRECTION INPUT ;
    USE SIGNAL ;
    PORT
      LAYER M3 ;
        RECT  38.628 105.779 38.646 105.816 ;
    END
  END a[442]
  PIN a[443]
    DIRECTION INPUT ;
    USE SIGNAL ;
    PORT
      LAYER M3 ;
        RECT  38.7 105.779 38.718 105.816 ;
    END
  END a[443]
  PIN a[444]
    DIRECTION INPUT ;
    USE SIGNAL ;
    PORT
      LAYER M3 ;
        RECT  38.772 105.779 38.79 105.816 ;
    END
  END a[444]
  PIN a[445]
    DIRECTION INPUT ;
    USE SIGNAL ;
    PORT
      LAYER M3 ;
        RECT  38.844 105.779 38.862 105.816 ;
    END
  END a[445]
  PIN a[446]
    DIRECTION INPUT ;
    USE SIGNAL ;
    PORT
      LAYER M3 ;
        RECT  38.916 105.779 38.934 105.816 ;
    END
  END a[446]
  PIN a[447]
    DIRECTION INPUT ;
    USE SIGNAL ;
    PORT
      LAYER M3 ;
        RECT  38.988 105.779 39.006 105.816 ;
    END
  END a[447]
  PIN a[448]
    DIRECTION INPUT ;
    USE SIGNAL ;
    PORT
      LAYER M3 ;
        RECT  39.06 105.779 39.078 105.816 ;
    END
  END a[448]
  PIN a[449]
    DIRECTION INPUT ;
    USE SIGNAL ;
    PORT
      LAYER M3 ;
        RECT  39.132 105.779 39.15 105.816 ;
    END
  END a[449]
  PIN a[44]
    DIRECTION INPUT ;
    USE SIGNAL ;
    PORT
      LAYER M3 ;
        RECT  52.02 105.779 52.038 105.816 ;
    END
  END a[44]
  PIN a[450]
    DIRECTION INPUT ;
    USE SIGNAL ;
    PORT
      LAYER M3 ;
        RECT  39.204 105.779 39.222 105.816 ;
    END
  END a[450]
  PIN a[451]
    DIRECTION INPUT ;
    USE SIGNAL ;
    PORT
      LAYER M3 ;
        RECT  39.276 105.779 39.294 105.816 ;
    END
  END a[451]
  PIN a[452]
    DIRECTION INPUT ;
    USE SIGNAL ;
    PORT
      LAYER M3 ;
        RECT  39.348 105.779 39.366 105.816 ;
    END
  END a[452]
  PIN a[453]
    DIRECTION INPUT ;
    USE SIGNAL ;
    PORT
      LAYER M3 ;
        RECT  39.42 105.779 39.438 105.816 ;
    END
  END a[453]
  PIN a[454]
    DIRECTION INPUT ;
    USE SIGNAL ;
    PORT
      LAYER M3 ;
        RECT  39.492 105.779 39.51 105.816 ;
    END
  END a[454]
  PIN a[455]
    DIRECTION INPUT ;
    USE SIGNAL ;
    PORT
      LAYER M3 ;
        RECT  39.564 105.779 39.582 105.816 ;
    END
  END a[455]
  PIN a[456]
    DIRECTION INPUT ;
    USE SIGNAL ;
    PORT
      LAYER M3 ;
        RECT  39.636 105.779 39.654 105.816 ;
    END
  END a[456]
  PIN a[457]
    DIRECTION INPUT ;
    USE SIGNAL ;
    PORT
      LAYER M3 ;
        RECT  39.708 105.779 39.726 105.816 ;
    END
  END a[457]
  PIN a[458]
    DIRECTION INPUT ;
    USE SIGNAL ;
    PORT
      LAYER M3 ;
        RECT  39.78 105.779 39.798 105.816 ;
    END
  END a[458]
  PIN a[459]
    DIRECTION INPUT ;
    USE SIGNAL ;
    PORT
      LAYER M3 ;
        RECT  39.852 105.779 39.87 105.816 ;
    END
  END a[459]
  PIN a[45]
    DIRECTION INPUT ;
    USE SIGNAL ;
    PORT
      LAYER M3 ;
        RECT  52.092 105.779 52.11 105.816 ;
    END
  END a[45]
  PIN a[460]
    DIRECTION INPUT ;
    USE SIGNAL ;
    PORT
      LAYER M3 ;
        RECT  39.924 105.779 39.942 105.816 ;
    END
  END a[460]
  PIN a[461]
    DIRECTION INPUT ;
    USE SIGNAL ;
    PORT
      LAYER M3 ;
        RECT  39.996 105.779 40.014 105.816 ;
    END
  END a[461]
  PIN a[462]
    DIRECTION INPUT ;
    USE SIGNAL ;
    PORT
      LAYER M3 ;
        RECT  40.068 105.779 40.086 105.816 ;
    END
  END a[462]
  PIN a[463]
    DIRECTION INPUT ;
    USE SIGNAL ;
    PORT
      LAYER M3 ;
        RECT  40.14 105.779 40.158 105.816 ;
    END
  END a[463]
  PIN a[464]
    DIRECTION INPUT ;
    USE SIGNAL ;
    PORT
      LAYER M3 ;
        RECT  40.212 105.779 40.23 105.816 ;
    END
  END a[464]
  PIN a[465]
    DIRECTION INPUT ;
    USE SIGNAL ;
    PORT
      LAYER M3 ;
        RECT  40.284 105.779 40.302 105.816 ;
    END
  END a[465]
  PIN a[466]
    DIRECTION INPUT ;
    USE SIGNAL ;
    PORT
      LAYER M3 ;
        RECT  40.356 105.779 40.374 105.816 ;
    END
  END a[466]
  PIN a[467]
    DIRECTION INPUT ;
    USE SIGNAL ;
    PORT
      LAYER M3 ;
        RECT  40.428 105.779 40.446 105.816 ;
    END
  END a[467]
  PIN a[468]
    DIRECTION INPUT ;
    USE SIGNAL ;
    PORT
      LAYER M3 ;
        RECT  40.5 105.779 40.518 105.816 ;
    END
  END a[468]
  PIN a[469]
    DIRECTION INPUT ;
    USE SIGNAL ;
    PORT
      LAYER M3 ;
        RECT  40.572 105.779 40.59 105.816 ;
    END
  END a[469]
  PIN a[46]
    DIRECTION INPUT ;
    USE SIGNAL ;
    PORT
      LAYER M3 ;
        RECT  52.164 105.779 52.182 105.816 ;
    END
  END a[46]
  PIN a[470]
    DIRECTION INPUT ;
    USE SIGNAL ;
    PORT
      LAYER M3 ;
        RECT  40.644 105.779 40.662 105.816 ;
    END
  END a[470]
  PIN a[471]
    DIRECTION INPUT ;
    USE SIGNAL ;
    PORT
      LAYER M3 ;
        RECT  40.716 105.779 40.734 105.816 ;
    END
  END a[471]
  PIN a[472]
    DIRECTION INPUT ;
    USE SIGNAL ;
    PORT
      LAYER M3 ;
        RECT  40.788 105.779 40.806 105.816 ;
    END
  END a[472]
  PIN a[473]
    DIRECTION INPUT ;
    USE SIGNAL ;
    PORT
      LAYER M3 ;
        RECT  40.86 105.779 40.878 105.816 ;
    END
  END a[473]
  PIN a[474]
    DIRECTION INPUT ;
    USE SIGNAL ;
    PORT
      LAYER M3 ;
        RECT  40.932 105.779 40.95 105.816 ;
    END
  END a[474]
  PIN a[475]
    DIRECTION INPUT ;
    USE SIGNAL ;
    PORT
      LAYER M3 ;
        RECT  41.004 105.779 41.022 105.816 ;
    END
  END a[475]
  PIN a[476]
    DIRECTION INPUT ;
    USE SIGNAL ;
    PORT
      LAYER M3 ;
        RECT  41.076 105.779 41.094 105.816 ;
    END
  END a[476]
  PIN a[477]
    DIRECTION INPUT ;
    USE SIGNAL ;
    PORT
      LAYER M3 ;
        RECT  41.148 105.779 41.166 105.816 ;
    END
  END a[477]
  PIN a[478]
    DIRECTION INPUT ;
    USE SIGNAL ;
    PORT
      LAYER M3 ;
        RECT  41.22 105.779 41.238 105.816 ;
    END
  END a[478]
  PIN a[479]
    DIRECTION INPUT ;
    USE SIGNAL ;
    PORT
      LAYER M3 ;
        RECT  41.292 105.779 41.31 105.816 ;
    END
  END a[479]
  PIN a[47]
    DIRECTION INPUT ;
    USE SIGNAL ;
    PORT
      LAYER M3 ;
        RECT  52.236 105.779 52.254 105.816 ;
    END
  END a[47]
  PIN a[480]
    DIRECTION INPUT ;
    USE SIGNAL ;
    PORT
      LAYER M3 ;
        RECT  41.364 105.779 41.382 105.816 ;
    END
  END a[480]
  PIN a[481]
    DIRECTION INPUT ;
    USE SIGNAL ;
    PORT
      LAYER M3 ;
        RECT  41.436 105.779 41.454 105.816 ;
    END
  END a[481]
  PIN a[482]
    DIRECTION INPUT ;
    USE SIGNAL ;
    PORT
      LAYER M3 ;
        RECT  41.508 105.779 41.526 105.816 ;
    END
  END a[482]
  PIN a[483]
    DIRECTION INPUT ;
    USE SIGNAL ;
    PORT
      LAYER M3 ;
        RECT  41.58 105.779 41.598 105.816 ;
    END
  END a[483]
  PIN a[484]
    DIRECTION INPUT ;
    USE SIGNAL ;
    PORT
      LAYER M3 ;
        RECT  41.652 105.779 41.67 105.816 ;
    END
  END a[484]
  PIN a[485]
    DIRECTION INPUT ;
    USE SIGNAL ;
    PORT
      LAYER M3 ;
        RECT  41.724 105.779 41.742 105.816 ;
    END
  END a[485]
  PIN a[486]
    DIRECTION INPUT ;
    USE SIGNAL ;
    PORT
      LAYER M3 ;
        RECT  41.796 105.779 41.814 105.816 ;
    END
  END a[486]
  PIN a[487]
    DIRECTION INPUT ;
    USE SIGNAL ;
    PORT
      LAYER M3 ;
        RECT  41.868 105.779 41.886 105.816 ;
    END
  END a[487]
  PIN a[488]
    DIRECTION INPUT ;
    USE SIGNAL ;
    PORT
      LAYER M3 ;
        RECT  41.94 105.779 41.958 105.816 ;
    END
  END a[488]
  PIN a[489]
    DIRECTION INPUT ;
    USE SIGNAL ;
    PORT
      LAYER M3 ;
        RECT  42.012 105.779 42.03 105.816 ;
    END
  END a[489]
  PIN a[48]
    DIRECTION INPUT ;
    USE SIGNAL ;
    PORT
      LAYER M3 ;
        RECT  52.308 105.779 52.326 105.816 ;
    END
  END a[48]
  PIN a[490]
    DIRECTION INPUT ;
    USE SIGNAL ;
    PORT
      LAYER M3 ;
        RECT  42.084 105.779 42.102 105.816 ;
    END
  END a[490]
  PIN a[491]
    DIRECTION INPUT ;
    USE SIGNAL ;
    PORT
      LAYER M3 ;
        RECT  42.156 105.779 42.174 105.816 ;
    END
  END a[491]
  PIN a[492]
    DIRECTION INPUT ;
    USE SIGNAL ;
    PORT
      LAYER M3 ;
        RECT  42.228 105.779 42.246 105.816 ;
    END
  END a[492]
  PIN a[493]
    DIRECTION INPUT ;
    USE SIGNAL ;
    PORT
      LAYER M3 ;
        RECT  42.3 105.779 42.318 105.816 ;
    END
  END a[493]
  PIN a[494]
    DIRECTION INPUT ;
    USE SIGNAL ;
    PORT
      LAYER M3 ;
        RECT  42.372 105.779 42.39 105.816 ;
    END
  END a[494]
  PIN a[495]
    DIRECTION INPUT ;
    USE SIGNAL ;
    PORT
      LAYER M3 ;
        RECT  42.444 105.779 42.462 105.816 ;
    END
  END a[495]
  PIN a[496]
    DIRECTION INPUT ;
    USE SIGNAL ;
    PORT
      LAYER M3 ;
        RECT  42.516 105.779 42.534 105.816 ;
    END
  END a[496]
  PIN a[497]
    DIRECTION INPUT ;
    USE SIGNAL ;
    PORT
      LAYER M3 ;
        RECT  42.588 105.779 42.606 105.816 ;
    END
  END a[497]
  PIN a[498]
    DIRECTION INPUT ;
    USE SIGNAL ;
    PORT
      LAYER M3 ;
        RECT  42.66 105.779 42.678 105.816 ;
    END
  END a[498]
  PIN a[499]
    DIRECTION INPUT ;
    USE SIGNAL ;
    PORT
      LAYER M3 ;
        RECT  42.732 105.779 42.75 105.816 ;
    END
  END a[499]
  PIN a[49]
    DIRECTION INPUT ;
    USE SIGNAL ;
    PORT
      LAYER M3 ;
        RECT  52.38 105.779 52.398 105.816 ;
    END
  END a[49]
  PIN a[4]
    DIRECTION INPUT ;
    USE SIGNAL ;
    PORT
      LAYER M3 ;
        RECT  58.356 105.779 58.374 105.816 ;
    END
  END a[4]
  PIN a[500]
    DIRECTION INPUT ;
    USE SIGNAL ;
    PORT
      LAYER M3 ;
        RECT  42.804 105.779 42.822 105.816 ;
    END
  END a[500]
  PIN a[501]
    DIRECTION INPUT ;
    USE SIGNAL ;
    PORT
      LAYER M3 ;
        RECT  42.876 105.779 42.894 105.816 ;
    END
  END a[501]
  PIN a[502]
    DIRECTION INPUT ;
    USE SIGNAL ;
    PORT
      LAYER M3 ;
        RECT  42.948 105.779 42.966 105.816 ;
    END
  END a[502]
  PIN a[503]
    DIRECTION INPUT ;
    USE SIGNAL ;
    PORT
      LAYER M3 ;
        RECT  43.02 105.779 43.038 105.816 ;
    END
  END a[503]
  PIN a[504]
    DIRECTION INPUT ;
    USE SIGNAL ;
    PORT
      LAYER M3 ;
        RECT  43.092 105.779 43.11 105.816 ;
    END
  END a[504]
  PIN a[505]
    DIRECTION INPUT ;
    USE SIGNAL ;
    PORT
      LAYER M3 ;
        RECT  43.164 105.779 43.182 105.816 ;
    END
  END a[505]
  PIN a[506]
    DIRECTION INPUT ;
    USE SIGNAL ;
    PORT
      LAYER M3 ;
        RECT  43.236 105.779 43.254 105.816 ;
    END
  END a[506]
  PIN a[507]
    DIRECTION INPUT ;
    USE SIGNAL ;
    PORT
      LAYER M3 ;
        RECT  43.308 105.779 43.326 105.816 ;
    END
  END a[507]
  PIN a[508]
    DIRECTION INPUT ;
    USE SIGNAL ;
    PORT
      LAYER M3 ;
        RECT  43.38 105.779 43.398 105.816 ;
    END
  END a[508]
  PIN a[509]
    DIRECTION INPUT ;
    USE SIGNAL ;
    PORT
      LAYER M3 ;
        RECT  43.452 105.779 43.47 105.816 ;
    END
  END a[509]
  PIN a[50]
    DIRECTION INPUT ;
    USE SIGNAL ;
    PORT
      LAYER M3 ;
        RECT  52.452 105.779 52.47 105.816 ;
    END
  END a[50]
  PIN a[510]
    DIRECTION INPUT ;
    USE SIGNAL ;
    PORT
      LAYER M3 ;
        RECT  43.524 105.779 43.542 105.816 ;
    END
  END a[510]
  PIN a[511]
    DIRECTION INPUT ;
    USE SIGNAL ;
    PORT
      LAYER M3 ;
        RECT  43.596 105.779 43.614 105.816 ;
    END
  END a[511]
  PIN a[512]
    DIRECTION INPUT ;
    USE SIGNAL ;
    PORT
      LAYER M3 ;
        RECT  60.948 105.779 60.966 105.816 ;
    END
  END a[512]
  PIN a[513]
    DIRECTION INPUT ;
    USE SIGNAL ;
    PORT
      LAYER M3 ;
        RECT  61.02 105.779 61.038 105.816 ;
    END
  END a[513]
  PIN a[514]
    DIRECTION INPUT ;
    USE SIGNAL ;
    PORT
      LAYER M3 ;
        RECT  61.092 105.779 61.11 105.816 ;
    END
  END a[514]
  PIN a[515]
    DIRECTION INPUT ;
    USE SIGNAL ;
    PORT
      LAYER M3 ;
        RECT  61.164 105.779 61.182 105.816 ;
    END
  END a[515]
  PIN a[516]
    DIRECTION INPUT ;
    USE SIGNAL ;
    PORT
      LAYER M3 ;
        RECT  61.236 105.779 61.254 105.816 ;
    END
  END a[516]
  PIN a[517]
    DIRECTION INPUT ;
    USE SIGNAL ;
    PORT
      LAYER M3 ;
        RECT  61.308 105.779 61.326 105.816 ;
    END
  END a[517]
  PIN a[518]
    DIRECTION INPUT ;
    USE SIGNAL ;
    PORT
      LAYER M3 ;
        RECT  61.38 105.779 61.398 105.816 ;
    END
  END a[518]
  PIN a[519]
    DIRECTION INPUT ;
    USE SIGNAL ;
    PORT
      LAYER M3 ;
        RECT  61.452 105.779 61.47 105.816 ;
    END
  END a[519]
  PIN a[51]
    DIRECTION INPUT ;
    USE SIGNAL ;
    PORT
      LAYER M3 ;
        RECT  52.524 105.779 52.542 105.816 ;
    END
  END a[51]
  PIN a[520]
    DIRECTION INPUT ;
    USE SIGNAL ;
    PORT
      LAYER M3 ;
        RECT  61.524 105.779 61.542 105.816 ;
    END
  END a[520]
  PIN a[521]
    DIRECTION INPUT ;
    USE SIGNAL ;
    PORT
      LAYER M3 ;
        RECT  61.596 105.779 61.614 105.816 ;
    END
  END a[521]
  PIN a[522]
    DIRECTION INPUT ;
    USE SIGNAL ;
    PORT
      LAYER M3 ;
        RECT  61.668 105.779 61.686 105.816 ;
    END
  END a[522]
  PIN a[523]
    DIRECTION INPUT ;
    USE SIGNAL ;
    PORT
      LAYER M3 ;
        RECT  61.74 105.779 61.758 105.816 ;
    END
  END a[523]
  PIN a[524]
    DIRECTION INPUT ;
    USE SIGNAL ;
    PORT
      LAYER M3 ;
        RECT  61.812 105.779 61.83 105.816 ;
    END
  END a[524]
  PIN a[525]
    DIRECTION INPUT ;
    USE SIGNAL ;
    PORT
      LAYER M3 ;
        RECT  61.884 105.779 61.902 105.816 ;
    END
  END a[525]
  PIN a[526]
    DIRECTION INPUT ;
    USE SIGNAL ;
    PORT
      LAYER M3 ;
        RECT  61.956 105.779 61.974 105.816 ;
    END
  END a[526]
  PIN a[527]
    DIRECTION INPUT ;
    USE SIGNAL ;
    PORT
      LAYER M3 ;
        RECT  62.028 105.779 62.046 105.816 ;
    END
  END a[527]
  PIN a[528]
    DIRECTION INPUT ;
    USE SIGNAL ;
    PORT
      LAYER M3 ;
        RECT  62.1 105.779 62.118 105.816 ;
    END
  END a[528]
  PIN a[529]
    DIRECTION INPUT ;
    USE SIGNAL ;
    PORT
      LAYER M3 ;
        RECT  62.172 105.779 62.19 105.816 ;
    END
  END a[529]
  PIN a[52]
    DIRECTION INPUT ;
    USE SIGNAL ;
    PORT
      LAYER M3 ;
        RECT  52.596 105.779 52.614 105.816 ;
    END
  END a[52]
  PIN a[530]
    DIRECTION INPUT ;
    USE SIGNAL ;
    PORT
      LAYER M3 ;
        RECT  62.244 105.779 62.262 105.816 ;
    END
  END a[530]
  PIN a[531]
    DIRECTION INPUT ;
    USE SIGNAL ;
    PORT
      LAYER M3 ;
        RECT  62.316 105.779 62.334 105.816 ;
    END
  END a[531]
  PIN a[532]
    DIRECTION INPUT ;
    USE SIGNAL ;
    PORT
      LAYER M3 ;
        RECT  62.388 105.779 62.406 105.816 ;
    END
  END a[532]
  PIN a[533]
    DIRECTION INPUT ;
    USE SIGNAL ;
    PORT
      LAYER M3 ;
        RECT  62.46 105.779 62.478 105.816 ;
    END
  END a[533]
  PIN a[534]
    DIRECTION INPUT ;
    USE SIGNAL ;
    PORT
      LAYER M3 ;
        RECT  62.532 105.779 62.55 105.816 ;
    END
  END a[534]
  PIN a[535]
    DIRECTION INPUT ;
    USE SIGNAL ;
    PORT
      LAYER M3 ;
        RECT  62.604 105.779 62.622 105.816 ;
    END
  END a[535]
  PIN a[536]
    DIRECTION INPUT ;
    USE SIGNAL ;
    PORT
      LAYER M3 ;
        RECT  62.676 105.779 62.694 105.816 ;
    END
  END a[536]
  PIN a[537]
    DIRECTION INPUT ;
    USE SIGNAL ;
    PORT
      LAYER M3 ;
        RECT  62.748 105.779 62.766 105.816 ;
    END
  END a[537]
  PIN a[538]
    DIRECTION INPUT ;
    USE SIGNAL ;
    PORT
      LAYER M3 ;
        RECT  62.82 105.779 62.838 105.816 ;
    END
  END a[538]
  PIN a[539]
    DIRECTION INPUT ;
    USE SIGNAL ;
    PORT
      LAYER M3 ;
        RECT  62.892 105.779 62.91 105.816 ;
    END
  END a[539]
  PIN a[53]
    DIRECTION INPUT ;
    USE SIGNAL ;
    PORT
      LAYER M3 ;
        RECT  52.668 105.779 52.686 105.816 ;
    END
  END a[53]
  PIN a[540]
    DIRECTION INPUT ;
    USE SIGNAL ;
    PORT
      LAYER M3 ;
        RECT  62.964 105.779 62.982 105.816 ;
    END
  END a[540]
  PIN a[541]
    DIRECTION INPUT ;
    USE SIGNAL ;
    PORT
      LAYER M3 ;
        RECT  63.036 105.779 63.054 105.816 ;
    END
  END a[541]
  PIN a[542]
    DIRECTION INPUT ;
    USE SIGNAL ;
    PORT
      LAYER M3 ;
        RECT  63.108 105.779 63.126 105.816 ;
    END
  END a[542]
  PIN a[543]
    DIRECTION INPUT ;
    USE SIGNAL ;
    PORT
      LAYER M3 ;
        RECT  63.18 105.779 63.198 105.816 ;
    END
  END a[543]
  PIN a[544]
    DIRECTION INPUT ;
    USE SIGNAL ;
    PORT
      LAYER M3 ;
        RECT  43.668 105.779 43.686 105.816 ;
    END
  END a[544]
  PIN a[545]
    DIRECTION INPUT ;
    USE SIGNAL ;
    PORT
      LAYER M3 ;
        RECT  43.74 105.779 43.758 105.816 ;
    END
  END a[545]
  PIN a[546]
    DIRECTION INPUT ;
    USE SIGNAL ;
    PORT
      LAYER M3 ;
        RECT  43.812 105.779 43.83 105.816 ;
    END
  END a[546]
  PIN a[547]
    DIRECTION INPUT ;
    USE SIGNAL ;
    PORT
      LAYER M3 ;
        RECT  43.884 105.779 43.902 105.816 ;
    END
  END a[547]
  PIN a[548]
    DIRECTION INPUT ;
    USE SIGNAL ;
    PORT
      LAYER M3 ;
        RECT  43.956 105.779 43.974 105.816 ;
    END
  END a[548]
  PIN a[549]
    DIRECTION INPUT ;
    USE SIGNAL ;
    PORT
      LAYER M3 ;
        RECT  44.028 105.779 44.046 105.816 ;
    END
  END a[549]
  PIN a[54]
    DIRECTION INPUT ;
    USE SIGNAL ;
    PORT
      LAYER M3 ;
        RECT  52.74 105.779 52.758 105.816 ;
    END
  END a[54]
  PIN a[550]
    DIRECTION INPUT ;
    USE SIGNAL ;
    PORT
      LAYER M3 ;
        RECT  44.1 105.779 44.118 105.816 ;
    END
  END a[550]
  PIN a[551]
    DIRECTION INPUT ;
    USE SIGNAL ;
    PORT
      LAYER M3 ;
        RECT  44.172 105.779 44.19 105.816 ;
    END
  END a[551]
  PIN a[552]
    DIRECTION INPUT ;
    USE SIGNAL ;
    PORT
      LAYER M3 ;
        RECT  44.244 105.779 44.262 105.816 ;
    END
  END a[552]
  PIN a[553]
    DIRECTION INPUT ;
    USE SIGNAL ;
    PORT
      LAYER M3 ;
        RECT  44.316 105.779 44.334 105.816 ;
    END
  END a[553]
  PIN a[554]
    DIRECTION INPUT ;
    USE SIGNAL ;
    PORT
      LAYER M3 ;
        RECT  44.388 105.779 44.406 105.816 ;
    END
  END a[554]
  PIN a[555]
    DIRECTION INPUT ;
    USE SIGNAL ;
    PORT
      LAYER M3 ;
        RECT  44.46 105.779 44.478 105.816 ;
    END
  END a[555]
  PIN a[556]
    DIRECTION INPUT ;
    USE SIGNAL ;
    PORT
      LAYER M3 ;
        RECT  44.532 105.779 44.55 105.816 ;
    END
  END a[556]
  PIN a[557]
    DIRECTION INPUT ;
    USE SIGNAL ;
    PORT
      LAYER M3 ;
        RECT  44.604 105.779 44.622 105.816 ;
    END
  END a[557]
  PIN a[558]
    DIRECTION INPUT ;
    USE SIGNAL ;
    PORT
      LAYER M3 ;
        RECT  44.676 105.779 44.694 105.816 ;
    END
  END a[558]
  PIN a[559]
    DIRECTION INPUT ;
    USE SIGNAL ;
    PORT
      LAYER M3 ;
        RECT  44.748 105.779 44.766 105.816 ;
    END
  END a[559]
  PIN a[55]
    DIRECTION INPUT ;
    USE SIGNAL ;
    PORT
      LAYER M3 ;
        RECT  52.812 105.779 52.83 105.816 ;
    END
  END a[55]
  PIN a[560]
    DIRECTION INPUT ;
    USE SIGNAL ;
    PORT
      LAYER M3 ;
        RECT  44.82 105.779 44.838 105.816 ;
    END
  END a[560]
  PIN a[561]
    DIRECTION INPUT ;
    USE SIGNAL ;
    PORT
      LAYER M3 ;
        RECT  44.892 105.779 44.91 105.816 ;
    END
  END a[561]
  PIN a[562]
    DIRECTION INPUT ;
    USE SIGNAL ;
    PORT
      LAYER M3 ;
        RECT  44.964 105.779 44.982 105.816 ;
    END
  END a[562]
  PIN a[563]
    DIRECTION INPUT ;
    USE SIGNAL ;
    PORT
      LAYER M3 ;
        RECT  45.036 105.779 45.054 105.816 ;
    END
  END a[563]
  PIN a[564]
    DIRECTION INPUT ;
    USE SIGNAL ;
    PORT
      LAYER M3 ;
        RECT  45.108 105.779 45.126 105.816 ;
    END
  END a[564]
  PIN a[565]
    DIRECTION INPUT ;
    USE SIGNAL ;
    PORT
      LAYER M3 ;
        RECT  45.18 105.779 45.198 105.816 ;
    END
  END a[565]
  PIN a[566]
    DIRECTION INPUT ;
    USE SIGNAL ;
    PORT
      LAYER M3 ;
        RECT  45.252 105.779 45.27 105.816 ;
    END
  END a[566]
  PIN a[567]
    DIRECTION INPUT ;
    USE SIGNAL ;
    PORT
      LAYER M3 ;
        RECT  45.324 105.779 45.342 105.816 ;
    END
  END a[567]
  PIN a[568]
    DIRECTION INPUT ;
    USE SIGNAL ;
    PORT
      LAYER M3 ;
        RECT  45.396 105.779 45.414 105.816 ;
    END
  END a[568]
  PIN a[569]
    DIRECTION INPUT ;
    USE SIGNAL ;
    PORT
      LAYER M3 ;
        RECT  45.468 105.779 45.486 105.816 ;
    END
  END a[569]
  PIN a[56]
    DIRECTION INPUT ;
    USE SIGNAL ;
    PORT
      LAYER M3 ;
        RECT  52.884 105.779 52.902 105.816 ;
    END
  END a[56]
  PIN a[570]
    DIRECTION INPUT ;
    USE SIGNAL ;
    PORT
      LAYER M3 ;
        RECT  45.54 105.779 45.558 105.816 ;
    END
  END a[570]
  PIN a[571]
    DIRECTION INPUT ;
    USE SIGNAL ;
    PORT
      LAYER M3 ;
        RECT  45.612 105.779 45.63 105.816 ;
    END
  END a[571]
  PIN a[572]
    DIRECTION INPUT ;
    USE SIGNAL ;
    PORT
      LAYER M3 ;
        RECT  45.684 105.779 45.702 105.816 ;
    END
  END a[572]
  PIN a[573]
    DIRECTION INPUT ;
    USE SIGNAL ;
    PORT
      LAYER M3 ;
        RECT  45.756 105.779 45.774 105.816 ;
    END
  END a[573]
  PIN a[574]
    DIRECTION INPUT ;
    USE SIGNAL ;
    PORT
      LAYER M3 ;
        RECT  45.828 105.779 45.846 105.816 ;
    END
  END a[574]
  PIN a[575]
    DIRECTION INPUT ;
    USE SIGNAL ;
    PORT
      LAYER M3 ;
        RECT  45.9 105.779 45.918 105.816 ;
    END
  END a[575]
  PIN a[576]
    DIRECTION INPUT ;
    USE SIGNAL ;
    PORT
      LAYER M3 ;
        RECT  32.724 105.779 32.742 105.816 ;
    END
  END a[576]
  PIN a[577]
    DIRECTION INPUT ;
    USE SIGNAL ;
    PORT
      LAYER M3 ;
        RECT  32.796 105.779 32.814 105.816 ;
    END
  END a[577]
  PIN a[578]
    DIRECTION INPUT ;
    USE SIGNAL ;
    PORT
      LAYER M3 ;
        RECT  32.868 105.779 32.886 105.816 ;
    END
  END a[578]
  PIN a[579]
    DIRECTION INPUT ;
    USE SIGNAL ;
    PORT
      LAYER M3 ;
        RECT  32.94 105.779 32.958 105.816 ;
    END
  END a[579]
  PIN a[57]
    DIRECTION INPUT ;
    USE SIGNAL ;
    PORT
      LAYER M3 ;
        RECT  52.956 105.779 52.974 105.816 ;
    END
  END a[57]
  PIN a[580]
    DIRECTION INPUT ;
    USE SIGNAL ;
    PORT
      LAYER M3 ;
        RECT  33.012 105.779 33.03 105.816 ;
    END
  END a[580]
  PIN a[581]
    DIRECTION INPUT ;
    USE SIGNAL ;
    PORT
      LAYER M3 ;
        RECT  33.084 105.779 33.102 105.816 ;
    END
  END a[581]
  PIN a[582]
    DIRECTION INPUT ;
    USE SIGNAL ;
    PORT
      LAYER M3 ;
        RECT  33.156 105.779 33.174 105.816 ;
    END
  END a[582]
  PIN a[583]
    DIRECTION INPUT ;
    USE SIGNAL ;
    PORT
      LAYER M3 ;
        RECT  33.228 105.779 33.246 105.816 ;
    END
  END a[583]
  PIN a[584]
    DIRECTION INPUT ;
    USE SIGNAL ;
    PORT
      LAYER M3 ;
        RECT  33.3 105.779 33.318 105.816 ;
    END
  END a[584]
  PIN a[585]
    DIRECTION INPUT ;
    USE SIGNAL ;
    PORT
      LAYER M3 ;
        RECT  33.372 105.779 33.39 105.816 ;
    END
  END a[585]
  PIN a[586]
    DIRECTION INPUT ;
    USE SIGNAL ;
    PORT
      LAYER M3 ;
        RECT  33.444 105.779 33.462 105.816 ;
    END
  END a[586]
  PIN a[587]
    DIRECTION INPUT ;
    USE SIGNAL ;
    PORT
      LAYER M3 ;
        RECT  33.516 105.779 33.534 105.816 ;
    END
  END a[587]
  PIN a[588]
    DIRECTION INPUT ;
    USE SIGNAL ;
    PORT
      LAYER M3 ;
        RECT  33.588 105.779 33.606 105.816 ;
    END
  END a[588]
  PIN a[589]
    DIRECTION INPUT ;
    USE SIGNAL ;
    PORT
      LAYER M3 ;
        RECT  33.66 105.779 33.678 105.816 ;
    END
  END a[589]
  PIN a[58]
    DIRECTION INPUT ;
    USE SIGNAL ;
    PORT
      LAYER M3 ;
        RECT  53.028 105.779 53.046 105.816 ;
    END
  END a[58]
  PIN a[590]
    DIRECTION INPUT ;
    USE SIGNAL ;
    PORT
      LAYER M3 ;
        RECT  33.732 105.779 33.75 105.816 ;
    END
  END a[590]
  PIN a[591]
    DIRECTION INPUT ;
    USE SIGNAL ;
    PORT
      LAYER M3 ;
        RECT  33.804 105.779 33.822 105.816 ;
    END
  END a[591]
  PIN a[592]
    DIRECTION INPUT ;
    USE SIGNAL ;
    PORT
      LAYER M3 ;
        RECT  33.876 105.779 33.894 105.816 ;
    END
  END a[592]
  PIN a[593]
    DIRECTION INPUT ;
    USE SIGNAL ;
    PORT
      LAYER M3 ;
        RECT  33.948 105.779 33.966 105.816 ;
    END
  END a[593]
  PIN a[594]
    DIRECTION INPUT ;
    USE SIGNAL ;
    PORT
      LAYER M3 ;
        RECT  34.02 105.779 34.038 105.816 ;
    END
  END a[594]
  PIN a[595]
    DIRECTION INPUT ;
    USE SIGNAL ;
    PORT
      LAYER M3 ;
        RECT  34.092 105.779 34.11 105.816 ;
    END
  END a[595]
  PIN a[596]
    DIRECTION INPUT ;
    USE SIGNAL ;
    PORT
      LAYER M3 ;
        RECT  34.164 105.779 34.182 105.816 ;
    END
  END a[596]
  PIN a[597]
    DIRECTION INPUT ;
    USE SIGNAL ;
    PORT
      LAYER M3 ;
        RECT  34.236 105.779 34.254 105.816 ;
    END
  END a[597]
  PIN a[598]
    DIRECTION INPUT ;
    USE SIGNAL ;
    PORT
      LAYER M3 ;
        RECT  34.308 105.779 34.326 105.816 ;
    END
  END a[598]
  PIN a[599]
    DIRECTION INPUT ;
    USE SIGNAL ;
    PORT
      LAYER M3 ;
        RECT  34.38 105.779 34.398 105.816 ;
    END
  END a[599]
  PIN a[59]
    DIRECTION INPUT ;
    USE SIGNAL ;
    PORT
      LAYER M3 ;
        RECT  53.1 105.779 53.118 105.816 ;
    END
  END a[59]
  PIN a[5]
    DIRECTION INPUT ;
    USE SIGNAL ;
    PORT
      LAYER M3 ;
        RECT  58.428 105.779 58.446 105.816 ;
    END
  END a[5]
  PIN a[60]
    DIRECTION INPUT ;
    USE SIGNAL ;
    PORT
      LAYER M3 ;
        RECT  53.172 105.779 53.19 105.816 ;
    END
  END a[60]
  PIN a[61]
    DIRECTION INPUT ;
    USE SIGNAL ;
    PORT
      LAYER M3 ;
        RECT  53.244 105.779 53.262 105.816 ;
    END
  END a[61]
  PIN a[62]
    DIRECTION INPUT ;
    USE SIGNAL ;
    PORT
      LAYER M3 ;
        RECT  53.316 105.779 53.334 105.816 ;
    END
  END a[62]
  PIN a[63]
    DIRECTION INPUT ;
    USE SIGNAL ;
    PORT
      LAYER M3 ;
        RECT  53.388 105.779 53.406 105.816 ;
    END
  END a[63]
  PIN a[64]
    DIRECTION INPUT ;
    USE SIGNAL ;
    PORT
      LAYER M3 ;
        RECT  46.548 105.779 46.566 105.816 ;
    END
  END a[64]
  PIN a[65]
    DIRECTION INPUT ;
    USE SIGNAL ;
    PORT
      LAYER M3 ;
        RECT  46.62 105.779 46.638 105.816 ;
    END
  END a[65]
  PIN a[66]
    DIRECTION INPUT ;
    USE SIGNAL ;
    PORT
      LAYER M3 ;
        RECT  46.692 105.779 46.71 105.816 ;
    END
  END a[66]
  PIN a[67]
    DIRECTION INPUT ;
    USE SIGNAL ;
    PORT
      LAYER M3 ;
        RECT  46.764 105.779 46.782 105.816 ;
    END
  END a[67]
  PIN a[68]
    DIRECTION INPUT ;
    USE SIGNAL ;
    PORT
      LAYER M3 ;
        RECT  46.836 105.779 46.854 105.816 ;
    END
  END a[68]
  PIN a[69]
    DIRECTION INPUT ;
    USE SIGNAL ;
    PORT
      LAYER M3 ;
        RECT  46.908 105.779 46.926 105.816 ;
    END
  END a[69]
  PIN a[6]
    DIRECTION INPUT ;
    USE SIGNAL ;
    PORT
      LAYER M3 ;
        RECT  58.5 105.779 58.518 105.816 ;
    END
  END a[6]
  PIN a[70]
    DIRECTION INPUT ;
    USE SIGNAL ;
    PORT
      LAYER M3 ;
        RECT  46.98 105.779 46.998 105.816 ;
    END
  END a[70]
  PIN a[71]
    DIRECTION INPUT ;
    USE SIGNAL ;
    PORT
      LAYER M3 ;
        RECT  47.052 105.779 47.07 105.816 ;
    END
  END a[71]
  PIN a[72]
    DIRECTION INPUT ;
    USE SIGNAL ;
    PORT
      LAYER M3 ;
        RECT  47.124 105.779 47.142 105.816 ;
    END
  END a[72]
  PIN a[73]
    DIRECTION INPUT ;
    USE SIGNAL ;
    PORT
      LAYER M3 ;
        RECT  47.196 105.779 47.214 105.816 ;
    END
  END a[73]
  PIN a[74]
    DIRECTION INPUT ;
    USE SIGNAL ;
    PORT
      LAYER M3 ;
        RECT  47.268 105.779 47.286 105.816 ;
    END
  END a[74]
  PIN a[75]
    DIRECTION INPUT ;
    USE SIGNAL ;
    PORT
      LAYER M3 ;
        RECT  47.34 105.779 47.358 105.816 ;
    END
  END a[75]
  PIN a[76]
    DIRECTION INPUT ;
    USE SIGNAL ;
    PORT
      LAYER M3 ;
        RECT  47.412 105.779 47.43 105.816 ;
    END
  END a[76]
  PIN a[77]
    DIRECTION INPUT ;
    USE SIGNAL ;
    PORT
      LAYER M3 ;
        RECT  47.484 105.779 47.502 105.816 ;
    END
  END a[77]
  PIN a[78]
    DIRECTION INPUT ;
    USE SIGNAL ;
    PORT
      LAYER M3 ;
        RECT  47.556 105.779 47.574 105.816 ;
    END
  END a[78]
  PIN a[79]
    DIRECTION INPUT ;
    USE SIGNAL ;
    PORT
      LAYER M3 ;
        RECT  47.628 105.779 47.646 105.816 ;
    END
  END a[79]
  PIN a[7]
    DIRECTION INPUT ;
    USE SIGNAL ;
    PORT
      LAYER M3 ;
        RECT  58.572 105.779 58.59 105.816 ;
    END
  END a[7]
  PIN a[80]
    DIRECTION INPUT ;
    USE SIGNAL ;
    PORT
      LAYER M3 ;
        RECT  47.7 105.779 47.718 105.816 ;
    END
  END a[80]
  PIN a[81]
    DIRECTION INPUT ;
    USE SIGNAL ;
    PORT
      LAYER M3 ;
        RECT  47.772 105.779 47.79 105.816 ;
    END
  END a[81]
  PIN a[82]
    DIRECTION INPUT ;
    USE SIGNAL ;
    PORT
      LAYER M3 ;
        RECT  47.844 105.779 47.862 105.816 ;
    END
  END a[82]
  PIN a[83]
    DIRECTION INPUT ;
    USE SIGNAL ;
    PORT
      LAYER M3 ;
        RECT  47.916 105.779 47.934 105.816 ;
    END
  END a[83]
  PIN a[84]
    DIRECTION INPUT ;
    USE SIGNAL ;
    PORT
      LAYER M3 ;
        RECT  47.988 105.779 48.006 105.816 ;
    END
  END a[84]
  PIN a[85]
    DIRECTION INPUT ;
    USE SIGNAL ;
    PORT
      LAYER M3 ;
        RECT  48.06 105.779 48.078 105.816 ;
    END
  END a[85]
  PIN a[86]
    DIRECTION INPUT ;
    USE SIGNAL ;
    PORT
      LAYER M3 ;
        RECT  48.132 105.779 48.15 105.816 ;
    END
  END a[86]
  PIN a[87]
    DIRECTION INPUT ;
    USE SIGNAL ;
    PORT
      LAYER M3 ;
        RECT  48.204 105.779 48.222 105.816 ;
    END
  END a[87]
  PIN a[88]
    DIRECTION INPUT ;
    USE SIGNAL ;
    PORT
      LAYER M3 ;
        RECT  48.276 105.779 48.294 105.816 ;
    END
  END a[88]
  PIN a[89]
    DIRECTION INPUT ;
    USE SIGNAL ;
    PORT
      LAYER M3 ;
        RECT  48.348 105.779 48.366 105.816 ;
    END
  END a[89]
  PIN a[8]
    DIRECTION INPUT ;
    USE SIGNAL ;
    PORT
      LAYER M3 ;
        RECT  58.644 105.779 58.662 105.816 ;
    END
  END a[8]
  PIN a[90]
    DIRECTION INPUT ;
    USE SIGNAL ;
    PORT
      LAYER M3 ;
        RECT  48.42 105.779 48.438 105.816 ;
    END
  END a[90]
  PIN a[91]
    DIRECTION INPUT ;
    USE SIGNAL ;
    PORT
      LAYER M3 ;
        RECT  48.492 105.779 48.51 105.816 ;
    END
  END a[91]
  PIN a[92]
    DIRECTION INPUT ;
    USE SIGNAL ;
    PORT
      LAYER M3 ;
        RECT  48.564 105.779 48.582 105.816 ;
    END
  END a[92]
  PIN a[93]
    DIRECTION INPUT ;
    USE SIGNAL ;
    PORT
      LAYER M3 ;
        RECT  48.636 105.779 48.654 105.816 ;
    END
  END a[93]
  PIN a[94]
    DIRECTION INPUT ;
    USE SIGNAL ;
    PORT
      LAYER M3 ;
        RECT  48.708 105.779 48.726 105.816 ;
    END
  END a[94]
  PIN a[95]
    DIRECTION INPUT ;
    USE SIGNAL ;
    PORT
      LAYER M3 ;
        RECT  48.78 105.779 48.798 105.816 ;
    END
  END a[95]
  PIN a[96]
    DIRECTION INPUT ;
    USE SIGNAL ;
    PORT
      LAYER M3 ;
        RECT  55.764 105.779 55.782 105.816 ;
    END
  END a[96]
  PIN a[97]
    DIRECTION INPUT ;
    USE SIGNAL ;
    PORT
      LAYER M3 ;
        RECT  55.836 105.779 55.854 105.816 ;
    END
  END a[97]
  PIN a[98]
    DIRECTION INPUT ;
    USE SIGNAL ;
    PORT
      LAYER M3 ;
        RECT  55.908 105.779 55.926 105.816 ;
    END
  END a[98]
  PIN a[99]
    DIRECTION INPUT ;
    USE SIGNAL ;
    PORT
      LAYER M3 ;
        RECT  55.98 105.779 55.998 105.816 ;
    END
  END a[99]
  PIN a[9]
    DIRECTION INPUT ;
    USE SIGNAL ;
    PORT
      LAYER M3 ;
        RECT  58.716 105.779 58.734 105.816 ;
    END
  END a[9]
  PIN b[0]
    DIRECTION OUTPUT ;
    USE SIGNAL ;
    PORT
      LAYER M4 ;
        RECT  104.004 42.192 104.088 42.216 ;
    END
  END b[0]
  PIN b[100]
    DIRECTION OUTPUT ;
    USE SIGNAL ;
    PORT
      LAYER M4 ;
        RECT  104.004 48.72 104.088 48.744 ;
    END
  END b[100]
  PIN b[101]
    DIRECTION OUTPUT ;
    USE SIGNAL ;
    PORT
      LAYER M4 ;
        RECT  104.004 48.816 104.088 48.84 ;
    END
  END b[101]
  PIN b[102]
    DIRECTION OUTPUT ;
    USE SIGNAL ;
    PORT
      LAYER M4 ;
        RECT  104.004 48.912 104.088 48.936 ;
    END
  END b[102]
  PIN b[103]
    DIRECTION OUTPUT ;
    USE SIGNAL ;
    PORT
      LAYER M4 ;
        RECT  104.004 49.008 104.088 49.032 ;
    END
  END b[103]
  PIN b[104]
    DIRECTION OUTPUT ;
    USE SIGNAL ;
    PORT
      LAYER M4 ;
        RECT  104.004 49.104 104.088 49.128 ;
    END
  END b[104]
  PIN b[105]
    DIRECTION OUTPUT ;
    USE SIGNAL ;
    PORT
      LAYER M4 ;
        RECT  104.004 49.2 104.088 49.224 ;
    END
  END b[105]
  PIN b[106]
    DIRECTION OUTPUT ;
    USE SIGNAL ;
    PORT
      LAYER M4 ;
        RECT  104.004 49.296 104.088 49.32 ;
    END
  END b[106]
  PIN b[107]
    DIRECTION OUTPUT ;
    USE SIGNAL ;
    PORT
      LAYER M4 ;
        RECT  104.004 49.392 104.088 49.416 ;
    END
  END b[107]
  PIN b[108]
    DIRECTION OUTPUT ;
    USE SIGNAL ;
    PORT
      LAYER M4 ;
        RECT  104.004 49.488 104.088 49.512 ;
    END
  END b[108]
  PIN b[109]
    DIRECTION OUTPUT ;
    USE SIGNAL ;
    PORT
      LAYER M4 ;
        RECT  104.004 49.584 104.088 49.608 ;
    END
  END b[109]
  PIN b[10]
    DIRECTION OUTPUT ;
    USE SIGNAL ;
    PORT
      LAYER M4 ;
        RECT  104.004 43.152 104.088 43.176 ;
    END
  END b[10]
  PIN b[110]
    DIRECTION OUTPUT ;
    USE SIGNAL ;
    PORT
      LAYER M4 ;
        RECT  104.004 49.68 104.088 49.704 ;
    END
  END b[110]
  PIN b[111]
    DIRECTION OUTPUT ;
    USE SIGNAL ;
    PORT
      LAYER M4 ;
        RECT  104.004 49.776 104.088 49.8 ;
    END
  END b[111]
  PIN b[112]
    DIRECTION OUTPUT ;
    USE SIGNAL ;
    PORT
      LAYER M4 ;
        RECT  104.004 49.872 104.088 49.896 ;
    END
  END b[112]
  PIN b[113]
    DIRECTION OUTPUT ;
    USE SIGNAL ;
    PORT
      LAYER M4 ;
        RECT  104.004 49.968 104.088 49.992 ;
    END
  END b[113]
  PIN b[114]
    DIRECTION OUTPUT ;
    USE SIGNAL ;
    PORT
      LAYER M4 ;
        RECT  104.004 50.064 104.088 50.088 ;
    END
  END b[114]
  PIN b[115]
    DIRECTION OUTPUT ;
    USE SIGNAL ;
    PORT
      LAYER M4 ;
        RECT  104.004 50.16 104.088 50.184 ;
    END
  END b[115]
  PIN b[116]
    DIRECTION OUTPUT ;
    USE SIGNAL ;
    PORT
      LAYER M4 ;
        RECT  104.004 50.256 104.088 50.28 ;
    END
  END b[116]
  PIN b[117]
    DIRECTION OUTPUT ;
    USE SIGNAL ;
    PORT
      LAYER M4 ;
        RECT  104.004 50.352 104.088 50.376 ;
    END
  END b[117]
  PIN b[118]
    DIRECTION OUTPUT ;
    USE SIGNAL ;
    PORT
      LAYER M4 ;
        RECT  104.004 50.448 104.088 50.472 ;
    END
  END b[118]
  PIN b[119]
    DIRECTION OUTPUT ;
    USE SIGNAL ;
    PORT
      LAYER M4 ;
        RECT  104.004 50.544 104.088 50.568 ;
    END
  END b[119]
  PIN b[11]
    DIRECTION OUTPUT ;
    USE SIGNAL ;
    PORT
      LAYER M4 ;
        RECT  104.004 43.248 104.088 43.272 ;
    END
  END b[11]
  PIN b[120]
    DIRECTION OUTPUT ;
    USE SIGNAL ;
    PORT
      LAYER M4 ;
        RECT  104.004 50.64 104.088 50.664 ;
    END
  END b[120]
  PIN b[121]
    DIRECTION OUTPUT ;
    USE SIGNAL ;
    PORT
      LAYER M4 ;
        RECT  104.004 50.736 104.088 50.76 ;
    END
  END b[121]
  PIN b[122]
    DIRECTION OUTPUT ;
    USE SIGNAL ;
    PORT
      LAYER M4 ;
        RECT  104.004 50.832 104.088 50.856 ;
    END
  END b[122]
  PIN b[123]
    DIRECTION OUTPUT ;
    USE SIGNAL ;
    PORT
      LAYER M4 ;
        RECT  104.004 50.928 104.088 50.952 ;
    END
  END b[123]
  PIN b[124]
    DIRECTION OUTPUT ;
    USE SIGNAL ;
    PORT
      LAYER M4 ;
        RECT  104.004 51.024 104.088 51.048 ;
    END
  END b[124]
  PIN b[125]
    DIRECTION OUTPUT ;
    USE SIGNAL ;
    PORT
      LAYER M4 ;
        RECT  104.004 51.12 104.088 51.144 ;
    END
  END b[125]
  PIN b[126]
    DIRECTION OUTPUT ;
    USE SIGNAL ;
    PORT
      LAYER M4 ;
        RECT  104.004 51.216 104.088 51.24 ;
    END
  END b[126]
  PIN b[127]
    DIRECTION OUTPUT ;
    USE SIGNAL ;
    PORT
      LAYER M4 ;
        RECT  104.004 51.312 104.088 51.336 ;
    END
  END b[127]
  PIN b[128]
    DIRECTION OUTPUT ;
    USE SIGNAL ;
    PORT
      LAYER M4 ;
        RECT  104.004 39.12 104.088 39.144 ;
    END
  END b[128]
  PIN b[129]
    DIRECTION OUTPUT ;
    USE SIGNAL ;
    PORT
      LAYER M4 ;
        RECT  104.004 39.216 104.088 39.24 ;
    END
  END b[129]
  PIN b[12]
    DIRECTION OUTPUT ;
    USE SIGNAL ;
    PORT
      LAYER M4 ;
        RECT  104.004 43.344 104.088 43.368 ;
    END
  END b[12]
  PIN b[130]
    DIRECTION OUTPUT ;
    USE SIGNAL ;
    PORT
      LAYER M4 ;
        RECT  104.004 39.312 104.088 39.336 ;
    END
  END b[130]
  PIN b[131]
    DIRECTION OUTPUT ;
    USE SIGNAL ;
    PORT
      LAYER M4 ;
        RECT  104.004 39.408 104.088 39.432 ;
    END
  END b[131]
  PIN b[132]
    DIRECTION OUTPUT ;
    USE SIGNAL ;
    PORT
      LAYER M4 ;
        RECT  104.004 39.504 104.088 39.528 ;
    END
  END b[132]
  PIN b[133]
    DIRECTION OUTPUT ;
    USE SIGNAL ;
    PORT
      LAYER M4 ;
        RECT  104.004 39.6 104.088 39.624 ;
    END
  END b[133]
  PIN b[134]
    DIRECTION OUTPUT ;
    USE SIGNAL ;
    PORT
      LAYER M4 ;
        RECT  104.004 39.696 104.088 39.72 ;
    END
  END b[134]
  PIN b[135]
    DIRECTION OUTPUT ;
    USE SIGNAL ;
    PORT
      LAYER M4 ;
        RECT  104.004 39.792 104.088 39.816 ;
    END
  END b[135]
  PIN b[136]
    DIRECTION OUTPUT ;
    USE SIGNAL ;
    PORT
      LAYER M4 ;
        RECT  104.004 39.888 104.088 39.912 ;
    END
  END b[136]
  PIN b[137]
    DIRECTION OUTPUT ;
    USE SIGNAL ;
    PORT
      LAYER M4 ;
        RECT  104.004 39.984 104.088 40.008 ;
    END
  END b[137]
  PIN b[138]
    DIRECTION OUTPUT ;
    USE SIGNAL ;
    PORT
      LAYER M4 ;
        RECT  104.004 40.08 104.088 40.104 ;
    END
  END b[138]
  PIN b[139]
    DIRECTION OUTPUT ;
    USE SIGNAL ;
    PORT
      LAYER M4 ;
        RECT  104.004 40.176 104.088 40.2 ;
    END
  END b[139]
  PIN b[13]
    DIRECTION OUTPUT ;
    USE SIGNAL ;
    PORT
      LAYER M4 ;
        RECT  104.004 43.44 104.088 43.464 ;
    END
  END b[13]
  PIN b[140]
    DIRECTION OUTPUT ;
    USE SIGNAL ;
    PORT
      LAYER M4 ;
        RECT  104.004 40.272 104.088 40.296 ;
    END
  END b[140]
  PIN b[141]
    DIRECTION OUTPUT ;
    USE SIGNAL ;
    PORT
      LAYER M4 ;
        RECT  104.004 40.368 104.088 40.392 ;
    END
  END b[141]
  PIN b[142]
    DIRECTION OUTPUT ;
    USE SIGNAL ;
    PORT
      LAYER M4 ;
        RECT  104.004 40.464 104.088 40.488 ;
    END
  END b[142]
  PIN b[143]
    DIRECTION OUTPUT ;
    USE SIGNAL ;
    PORT
      LAYER M4 ;
        RECT  104.004 40.56 104.088 40.584 ;
    END
  END b[143]
  PIN b[144]
    DIRECTION OUTPUT ;
    USE SIGNAL ;
    PORT
      LAYER M4 ;
        RECT  104.004 40.656 104.088 40.68 ;
    END
  END b[144]
  PIN b[145]
    DIRECTION OUTPUT ;
    USE SIGNAL ;
    PORT
      LAYER M4 ;
        RECT  104.004 40.752 104.088 40.776 ;
    END
  END b[145]
  PIN b[146]
    DIRECTION OUTPUT ;
    USE SIGNAL ;
    PORT
      LAYER M4 ;
        RECT  104.004 40.848 104.088 40.872 ;
    END
  END b[146]
  PIN b[147]
    DIRECTION OUTPUT ;
    USE SIGNAL ;
    PORT
      LAYER M4 ;
        RECT  104.004 40.944 104.088 40.968 ;
    END
  END b[147]
  PIN b[148]
    DIRECTION OUTPUT ;
    USE SIGNAL ;
    PORT
      LAYER M4 ;
        RECT  104.004 41.04 104.088 41.064 ;
    END
  END b[148]
  PIN b[149]
    DIRECTION OUTPUT ;
    USE SIGNAL ;
    PORT
      LAYER M4 ;
        RECT  104.004 41.136 104.088 41.16 ;
    END
  END b[149]
  PIN b[14]
    DIRECTION OUTPUT ;
    USE SIGNAL ;
    PORT
      LAYER M4 ;
        RECT  104.004 43.536 104.088 43.56 ;
    END
  END b[14]
  PIN b[150]
    DIRECTION OUTPUT ;
    USE SIGNAL ;
    PORT
      LAYER M4 ;
        RECT  104.004 41.232 104.088 41.256 ;
    END
  END b[150]
  PIN b[151]
    DIRECTION OUTPUT ;
    USE SIGNAL ;
    PORT
      LAYER M4 ;
        RECT  104.004 41.328 104.088 41.352 ;
    END
  END b[151]
  PIN b[152]
    DIRECTION OUTPUT ;
    USE SIGNAL ;
    PORT
      LAYER M4 ;
        RECT  104.004 41.424 104.088 41.448 ;
    END
  END b[152]
  PIN b[153]
    DIRECTION OUTPUT ;
    USE SIGNAL ;
    PORT
      LAYER M4 ;
        RECT  104.004 41.52 104.088 41.544 ;
    END
  END b[153]
  PIN b[154]
    DIRECTION OUTPUT ;
    USE SIGNAL ;
    PORT
      LAYER M4 ;
        RECT  104.004 41.616 104.088 41.64 ;
    END
  END b[154]
  PIN b[155]
    DIRECTION OUTPUT ;
    USE SIGNAL ;
    PORT
      LAYER M4 ;
        RECT  104.004 41.712 104.088 41.736 ;
    END
  END b[155]
  PIN b[156]
    DIRECTION OUTPUT ;
    USE SIGNAL ;
    PORT
      LAYER M4 ;
        RECT  104.004 41.808 104.088 41.832 ;
    END
  END b[156]
  PIN b[157]
    DIRECTION OUTPUT ;
    USE SIGNAL ;
    PORT
      LAYER M4 ;
        RECT  104.004 41.904 104.088 41.928 ;
    END
  END b[157]
  PIN b[158]
    DIRECTION OUTPUT ;
    USE SIGNAL ;
    PORT
      LAYER M4 ;
        RECT  104.004 42 104.088 42.024 ;
    END
  END b[158]
  PIN b[159]
    DIRECTION OUTPUT ;
    USE SIGNAL ;
    PORT
      LAYER M4 ;
        RECT  104.004 42.096 104.088 42.12 ;
    END
  END b[159]
  PIN b[15]
    DIRECTION OUTPUT ;
    USE SIGNAL ;
    PORT
      LAYER M4 ;
        RECT  104.004 43.632 104.088 43.656 ;
    END
  END b[15]
  PIN b[160]
    DIRECTION OUTPUT ;
    USE SIGNAL ;
    PORT
      LAYER M4 ;
        RECT  104.004 51.408 104.088 51.432 ;
    END
  END b[160]
  PIN b[161]
    DIRECTION OUTPUT ;
    USE SIGNAL ;
    PORT
      LAYER M4 ;
        RECT  104.004 51.504 104.088 51.528 ;
    END
  END b[161]
  PIN b[162]
    DIRECTION OUTPUT ;
    USE SIGNAL ;
    PORT
      LAYER M4 ;
        RECT  104.004 51.6 104.088 51.624 ;
    END
  END b[162]
  PIN b[163]
    DIRECTION OUTPUT ;
    USE SIGNAL ;
    PORT
      LAYER M4 ;
        RECT  104.004 51.696 104.088 51.72 ;
    END
  END b[163]
  PIN b[164]
    DIRECTION OUTPUT ;
    USE SIGNAL ;
    PORT
      LAYER M4 ;
        RECT  104.004 51.792 104.088 51.816 ;
    END
  END b[164]
  PIN b[165]
    DIRECTION OUTPUT ;
    USE SIGNAL ;
    PORT
      LAYER M4 ;
        RECT  104.004 51.888 104.088 51.912 ;
    END
  END b[165]
  PIN b[166]
    DIRECTION OUTPUT ;
    USE SIGNAL ;
    PORT
      LAYER M4 ;
        RECT  104.004 51.984 104.088 52.008 ;
    END
  END b[166]
  PIN b[167]
    DIRECTION OUTPUT ;
    USE SIGNAL ;
    PORT
      LAYER M4 ;
        RECT  104.004 52.08 104.088 52.104 ;
    END
  END b[167]
  PIN b[168]
    DIRECTION OUTPUT ;
    USE SIGNAL ;
    PORT
      LAYER M4 ;
        RECT  104.004 52.176 104.088 52.2 ;
    END
  END b[168]
  PIN b[169]
    DIRECTION OUTPUT ;
    USE SIGNAL ;
    PORT
      LAYER M4 ;
        RECT  104.004 52.272 104.088 52.296 ;
    END
  END b[169]
  PIN b[16]
    DIRECTION OUTPUT ;
    USE SIGNAL ;
    PORT
      LAYER M4 ;
        RECT  104.004 43.728 104.088 43.752 ;
    END
  END b[16]
  PIN b[170]
    DIRECTION OUTPUT ;
    USE SIGNAL ;
    PORT
      LAYER M4 ;
        RECT  104.004 52.368 104.088 52.392 ;
    END
  END b[170]
  PIN b[171]
    DIRECTION OUTPUT ;
    USE SIGNAL ;
    PORT
      LAYER M4 ;
        RECT  104.004 52.464 104.088 52.488 ;
    END
  END b[171]
  PIN b[172]
    DIRECTION OUTPUT ;
    USE SIGNAL ;
    PORT
      LAYER M4 ;
        RECT  104.004 52.56 104.088 52.584 ;
    END
  END b[172]
  PIN b[173]
    DIRECTION OUTPUT ;
    USE SIGNAL ;
    PORT
      LAYER M4 ;
        RECT  104.004 52.656 104.088 52.68 ;
    END
  END b[173]
  PIN b[174]
    DIRECTION OUTPUT ;
    USE SIGNAL ;
    PORT
      LAYER M4 ;
        RECT  104.004 52.752 104.088 52.776 ;
    END
  END b[174]
  PIN b[175]
    DIRECTION OUTPUT ;
    USE SIGNAL ;
    PORT
      LAYER M4 ;
        RECT  104.004 52.848 104.088 52.872 ;
    END
  END b[175]
  PIN b[176]
    DIRECTION OUTPUT ;
    USE SIGNAL ;
    PORT
      LAYER M4 ;
        RECT  104.004 52.944 104.088 52.968 ;
    END
  END b[176]
  PIN b[177]
    DIRECTION OUTPUT ;
    USE SIGNAL ;
    PORT
      LAYER M4 ;
        RECT  104.004 53.04 104.088 53.064 ;
    END
  END b[177]
  PIN b[178]
    DIRECTION OUTPUT ;
    USE SIGNAL ;
    PORT
      LAYER M4 ;
        RECT  104.004 53.136 104.088 53.16 ;
    END
  END b[178]
  PIN b[179]
    DIRECTION OUTPUT ;
    USE SIGNAL ;
    PORT
      LAYER M4 ;
        RECT  104.004 53.232 104.088 53.256 ;
    END
  END b[179]
  PIN b[17]
    DIRECTION OUTPUT ;
    USE SIGNAL ;
    PORT
      LAYER M4 ;
        RECT  104.004 43.824 104.088 43.848 ;
    END
  END b[17]
  PIN b[180]
    DIRECTION OUTPUT ;
    USE SIGNAL ;
    PORT
      LAYER M4 ;
        RECT  104.004 53.328 104.088 53.352 ;
    END
  END b[180]
  PIN b[181]
    DIRECTION OUTPUT ;
    USE SIGNAL ;
    PORT
      LAYER M4 ;
        RECT  104.004 53.424 104.088 53.448 ;
    END
  END b[181]
  PIN b[182]
    DIRECTION OUTPUT ;
    USE SIGNAL ;
    PORT
      LAYER M4 ;
        RECT  104.004 53.52 104.088 53.544 ;
    END
  END b[182]
  PIN b[183]
    DIRECTION OUTPUT ;
    USE SIGNAL ;
    PORT
      LAYER M4 ;
        RECT  104.004 53.616 104.088 53.64 ;
    END
  END b[183]
  PIN b[184]
    DIRECTION OUTPUT ;
    USE SIGNAL ;
    PORT
      LAYER M4 ;
        RECT  104.004 53.712 104.088 53.736 ;
    END
  END b[184]
  PIN b[185]
    DIRECTION OUTPUT ;
    USE SIGNAL ;
    PORT
      LAYER M4 ;
        RECT  104.004 53.808 104.088 53.832 ;
    END
  END b[185]
  PIN b[186]
    DIRECTION OUTPUT ;
    USE SIGNAL ;
    PORT
      LAYER M4 ;
        RECT  104.004 53.904 104.088 53.928 ;
    END
  END b[186]
  PIN b[187]
    DIRECTION OUTPUT ;
    USE SIGNAL ;
    PORT
      LAYER M4 ;
        RECT  104.004 54 104.088 54.024 ;
    END
  END b[187]
  PIN b[188]
    DIRECTION OUTPUT ;
    USE SIGNAL ;
    PORT
      LAYER M4 ;
        RECT  104.004 54.096 104.088 54.12 ;
    END
  END b[188]
  PIN b[189]
    DIRECTION OUTPUT ;
    USE SIGNAL ;
    PORT
      LAYER M4 ;
        RECT  104.004 54.192 104.088 54.216 ;
    END
  END b[189]
  PIN b[18]
    DIRECTION OUTPUT ;
    USE SIGNAL ;
    PORT
      LAYER M4 ;
        RECT  104.004 43.92 104.088 43.944 ;
    END
  END b[18]
  PIN b[190]
    DIRECTION OUTPUT ;
    USE SIGNAL ;
    PORT
      LAYER M4 ;
        RECT  104.004 54.288 104.088 54.312 ;
    END
  END b[190]
  PIN b[191]
    DIRECTION OUTPUT ;
    USE SIGNAL ;
    PORT
      LAYER M4 ;
        RECT  104.004 54.384 104.088 54.408 ;
    END
  END b[191]
  PIN b[192]
    DIRECTION OUTPUT ;
    USE SIGNAL ;
    PORT
      LAYER M4 ;
        RECT  104.004 61.392 104.088 61.416 ;
    END
  END b[192]
  PIN b[193]
    DIRECTION OUTPUT ;
    USE SIGNAL ;
    PORT
      LAYER M4 ;
        RECT  104.004 61.488 104.088 61.512 ;
    END
  END b[193]
  PIN b[194]
    DIRECTION OUTPUT ;
    USE SIGNAL ;
    PORT
      LAYER M4 ;
        RECT  104.004 61.584 104.088 61.608 ;
    END
  END b[194]
  PIN b[195]
    DIRECTION OUTPUT ;
    USE SIGNAL ;
    PORT
      LAYER M4 ;
        RECT  104.004 61.68 104.088 61.704 ;
    END
  END b[195]
  PIN b[196]
    DIRECTION OUTPUT ;
    USE SIGNAL ;
    PORT
      LAYER M4 ;
        RECT  104.004 61.776 104.088 61.8 ;
    END
  END b[196]
  PIN b[197]
    DIRECTION OUTPUT ;
    USE SIGNAL ;
    PORT
      LAYER M4 ;
        RECT  104.004 61.872 104.088 61.896 ;
    END
  END b[197]
  PIN b[198]
    DIRECTION OUTPUT ;
    USE SIGNAL ;
    PORT
      LAYER M4 ;
        RECT  104.004 61.968 104.088 61.992 ;
    END
  END b[198]
  PIN b[199]
    DIRECTION OUTPUT ;
    USE SIGNAL ;
    PORT
      LAYER M4 ;
        RECT  104.004 62.064 104.088 62.088 ;
    END
  END b[199]
  PIN b[19]
    DIRECTION OUTPUT ;
    USE SIGNAL ;
    PORT
      LAYER M4 ;
        RECT  104.004 44.016 104.088 44.04 ;
    END
  END b[19]
  PIN b[1]
    DIRECTION OUTPUT ;
    USE SIGNAL ;
    PORT
      LAYER M4 ;
        RECT  104.004 42.288 104.088 42.312 ;
    END
  END b[1]
  PIN b[200]
    DIRECTION OUTPUT ;
    USE SIGNAL ;
    PORT
      LAYER M4 ;
        RECT  104.004 62.16 104.088 62.184 ;
    END
  END b[200]
  PIN b[201]
    DIRECTION OUTPUT ;
    USE SIGNAL ;
    PORT
      LAYER M4 ;
        RECT  104.004 62.256 104.088 62.28 ;
    END
  END b[201]
  PIN b[202]
    DIRECTION OUTPUT ;
    USE SIGNAL ;
    PORT
      LAYER M4 ;
        RECT  104.004 62.352 104.088 62.376 ;
    END
  END b[202]
  PIN b[203]
    DIRECTION OUTPUT ;
    USE SIGNAL ;
    PORT
      LAYER M4 ;
        RECT  104.004 62.448 104.088 62.472 ;
    END
  END b[203]
  PIN b[204]
    DIRECTION OUTPUT ;
    USE SIGNAL ;
    PORT
      LAYER M4 ;
        RECT  104.004 62.544 104.088 62.568 ;
    END
  END b[204]
  PIN b[205]
    DIRECTION OUTPUT ;
    USE SIGNAL ;
    PORT
      LAYER M4 ;
        RECT  104.004 62.64 104.088 62.664 ;
    END
  END b[205]
  PIN b[206]
    DIRECTION OUTPUT ;
    USE SIGNAL ;
    PORT
      LAYER M4 ;
        RECT  104.004 62.736 104.088 62.76 ;
    END
  END b[206]
  PIN b[207]
    DIRECTION OUTPUT ;
    USE SIGNAL ;
    PORT
      LAYER M4 ;
        RECT  104.004 62.832 104.088 62.856 ;
    END
  END b[207]
  PIN b[208]
    DIRECTION OUTPUT ;
    USE SIGNAL ;
    PORT
      LAYER M4 ;
        RECT  104.004 62.928 104.088 62.952 ;
    END
  END b[208]
  PIN b[209]
    DIRECTION OUTPUT ;
    USE SIGNAL ;
    PORT
      LAYER M4 ;
        RECT  104.004 63.024 104.088 63.048 ;
    END
  END b[209]
  PIN b[20]
    DIRECTION OUTPUT ;
    USE SIGNAL ;
    PORT
      LAYER M4 ;
        RECT  104.004 44.112 104.088 44.136 ;
    END
  END b[20]
  PIN b[210]
    DIRECTION OUTPUT ;
    USE SIGNAL ;
    PORT
      LAYER M4 ;
        RECT  104.004 63.12 104.088 63.144 ;
    END
  END b[210]
  PIN b[211]
    DIRECTION OUTPUT ;
    USE SIGNAL ;
    PORT
      LAYER M4 ;
        RECT  104.004 63.216 104.088 63.24 ;
    END
  END b[211]
  PIN b[212]
    DIRECTION OUTPUT ;
    USE SIGNAL ;
    PORT
      LAYER M4 ;
        RECT  104.004 63.312 104.088 63.336 ;
    END
  END b[212]
  PIN b[213]
    DIRECTION OUTPUT ;
    USE SIGNAL ;
    PORT
      LAYER M4 ;
        RECT  104.004 63.408 104.088 63.432 ;
    END
  END b[213]
  PIN b[214]
    DIRECTION OUTPUT ;
    USE SIGNAL ;
    PORT
      LAYER M4 ;
        RECT  104.004 63.504 104.088 63.528 ;
    END
  END b[214]
  PIN b[215]
    DIRECTION OUTPUT ;
    USE SIGNAL ;
    PORT
      LAYER M4 ;
        RECT  104.004 63.6 104.088 63.624 ;
    END
  END b[215]
  PIN b[216]
    DIRECTION OUTPUT ;
    USE SIGNAL ;
    PORT
      LAYER M4 ;
        RECT  104.004 63.696 104.088 63.72 ;
    END
  END b[216]
  PIN b[217]
    DIRECTION OUTPUT ;
    USE SIGNAL ;
    PORT
      LAYER M4 ;
        RECT  104.004 63.792 104.088 63.816 ;
    END
  END b[217]
  PIN b[218]
    DIRECTION OUTPUT ;
    USE SIGNAL ;
    PORT
      LAYER M4 ;
        RECT  104.004 63.888 104.088 63.912 ;
    END
  END b[218]
  PIN b[219]
    DIRECTION OUTPUT ;
    USE SIGNAL ;
    PORT
      LAYER M4 ;
        RECT  104.004 63.984 104.088 64.008 ;
    END
  END b[219]
  PIN b[21]
    DIRECTION OUTPUT ;
    USE SIGNAL ;
    PORT
      LAYER M4 ;
        RECT  104.004 44.208 104.088 44.232 ;
    END
  END b[21]
  PIN b[220]
    DIRECTION OUTPUT ;
    USE SIGNAL ;
    PORT
      LAYER M4 ;
        RECT  104.004 64.08 104.088 64.104 ;
    END
  END b[220]
  PIN b[221]
    DIRECTION OUTPUT ;
    USE SIGNAL ;
    PORT
      LAYER M4 ;
        RECT  104.004 64.176 104.088 64.2 ;
    END
  END b[221]
  PIN b[222]
    DIRECTION OUTPUT ;
    USE SIGNAL ;
    PORT
      LAYER M4 ;
        RECT  104.004 64.272 104.088 64.296 ;
    END
  END b[222]
  PIN b[223]
    DIRECTION OUTPUT ;
    USE SIGNAL ;
    PORT
      LAYER M4 ;
        RECT  104.004 64.368 104.088 64.392 ;
    END
  END b[223]
  PIN b[224]
    DIRECTION OUTPUT ;
    USE SIGNAL ;
    PORT
      LAYER M4 ;
        RECT  104.004 67.536 104.088 67.56 ;
    END
  END b[224]
  PIN b[225]
    DIRECTION OUTPUT ;
    USE SIGNAL ;
    PORT
      LAYER M4 ;
        RECT  104.004 67.632 104.088 67.656 ;
    END
  END b[225]
  PIN b[226]
    DIRECTION OUTPUT ;
    USE SIGNAL ;
    PORT
      LAYER M4 ;
        RECT  104.004 67.728 104.088 67.752 ;
    END
  END b[226]
  PIN b[227]
    DIRECTION OUTPUT ;
    USE SIGNAL ;
    PORT
      LAYER M4 ;
        RECT  104.004 67.824 104.088 67.848 ;
    END
  END b[227]
  PIN b[228]
    DIRECTION OUTPUT ;
    USE SIGNAL ;
    PORT
      LAYER M4 ;
        RECT  104.004 67.92 104.088 67.944 ;
    END
  END b[228]
  PIN b[229]
    DIRECTION OUTPUT ;
    USE SIGNAL ;
    PORT
      LAYER M4 ;
        RECT  104.004 68.016 104.088 68.04 ;
    END
  END b[229]
  PIN b[22]
    DIRECTION OUTPUT ;
    USE SIGNAL ;
    PORT
      LAYER M4 ;
        RECT  104.004 44.304 104.088 44.328 ;
    END
  END b[22]
  PIN b[230]
    DIRECTION OUTPUT ;
    USE SIGNAL ;
    PORT
      LAYER M4 ;
        RECT  104.004 68.112 104.088 68.136 ;
    END
  END b[230]
  PIN b[231]
    DIRECTION OUTPUT ;
    USE SIGNAL ;
    PORT
      LAYER M4 ;
        RECT  104.004 68.208 104.088 68.232 ;
    END
  END b[231]
  PIN b[232]
    DIRECTION OUTPUT ;
    USE SIGNAL ;
    PORT
      LAYER M4 ;
        RECT  104.004 68.304 104.088 68.328 ;
    END
  END b[232]
  PIN b[233]
    DIRECTION OUTPUT ;
    USE SIGNAL ;
    PORT
      LAYER M4 ;
        RECT  104.004 68.4 104.088 68.424 ;
    END
  END b[233]
  PIN b[234]
    DIRECTION OUTPUT ;
    USE SIGNAL ;
    PORT
      LAYER M4 ;
        RECT  104.004 68.496 104.088 68.52 ;
    END
  END b[234]
  PIN b[235]
    DIRECTION OUTPUT ;
    USE SIGNAL ;
    PORT
      LAYER M4 ;
        RECT  104.004 68.592 104.088 68.616 ;
    END
  END b[235]
  PIN b[236]
    DIRECTION OUTPUT ;
    USE SIGNAL ;
    PORT
      LAYER M4 ;
        RECT  104.004 68.688 104.088 68.712 ;
    END
  END b[236]
  PIN b[237]
    DIRECTION OUTPUT ;
    USE SIGNAL ;
    PORT
      LAYER M4 ;
        RECT  104.004 68.784 104.088 68.808 ;
    END
  END b[237]
  PIN b[238]
    DIRECTION OUTPUT ;
    USE SIGNAL ;
    PORT
      LAYER M4 ;
        RECT  104.004 68.88 104.088 68.904 ;
    END
  END b[238]
  PIN b[239]
    DIRECTION OUTPUT ;
    USE SIGNAL ;
    PORT
      LAYER M4 ;
        RECT  104.004 68.976 104.088 69 ;
    END
  END b[239]
  PIN b[23]
    DIRECTION OUTPUT ;
    USE SIGNAL ;
    PORT
      LAYER M4 ;
        RECT  104.004 44.4 104.088 44.424 ;
    END
  END b[23]
  PIN b[240]
    DIRECTION OUTPUT ;
    USE SIGNAL ;
    PORT
      LAYER M4 ;
        RECT  104.004 69.072 104.088 69.096 ;
    END
  END b[240]
  PIN b[241]
    DIRECTION OUTPUT ;
    USE SIGNAL ;
    PORT
      LAYER M4 ;
        RECT  104.004 69.168 104.088 69.192 ;
    END
  END b[241]
  PIN b[242]
    DIRECTION OUTPUT ;
    USE SIGNAL ;
    PORT
      LAYER M4 ;
        RECT  104.004 69.264 104.088 69.288 ;
    END
  END b[242]
  PIN b[243]
    DIRECTION OUTPUT ;
    USE SIGNAL ;
    PORT
      LAYER M4 ;
        RECT  104.004 69.36 104.088 69.384 ;
    END
  END b[243]
  PIN b[244]
    DIRECTION OUTPUT ;
    USE SIGNAL ;
    PORT
      LAYER M4 ;
        RECT  104.004 69.456 104.088 69.48 ;
    END
  END b[244]
  PIN b[245]
    DIRECTION OUTPUT ;
    USE SIGNAL ;
    PORT
      LAYER M4 ;
        RECT  104.004 69.552 104.088 69.576 ;
    END
  END b[245]
  PIN b[246]
    DIRECTION OUTPUT ;
    USE SIGNAL ;
    PORT
      LAYER M4 ;
        RECT  104.004 69.648 104.088 69.672 ;
    END
  END b[246]
  PIN b[247]
    DIRECTION OUTPUT ;
    USE SIGNAL ;
    PORT
      LAYER M4 ;
        RECT  104.004 69.744 104.088 69.768 ;
    END
  END b[247]
  PIN b[248]
    DIRECTION OUTPUT ;
    USE SIGNAL ;
    PORT
      LAYER M4 ;
        RECT  104.004 69.84 104.088 69.864 ;
    END
  END b[248]
  PIN b[249]
    DIRECTION OUTPUT ;
    USE SIGNAL ;
    PORT
      LAYER M4 ;
        RECT  104.004 69.936 104.088 69.96 ;
    END
  END b[249]
  PIN b[24]
    DIRECTION OUTPUT ;
    USE SIGNAL ;
    PORT
      LAYER M4 ;
        RECT  104.004 44.496 104.088 44.52 ;
    END
  END b[24]
  PIN b[250]
    DIRECTION OUTPUT ;
    USE SIGNAL ;
    PORT
      LAYER M4 ;
        RECT  104.004 70.032 104.088 70.056 ;
    END
  END b[250]
  PIN b[251]
    DIRECTION OUTPUT ;
    USE SIGNAL ;
    PORT
      LAYER M4 ;
        RECT  104.004 70.128 104.088 70.152 ;
    END
  END b[251]
  PIN b[252]
    DIRECTION OUTPUT ;
    USE SIGNAL ;
    PORT
      LAYER M4 ;
        RECT  104.004 70.224 104.088 70.248 ;
    END
  END b[252]
  PIN b[253]
    DIRECTION OUTPUT ;
    USE SIGNAL ;
    PORT
      LAYER M4 ;
        RECT  104.004 70.32 104.088 70.344 ;
    END
  END b[253]
  PIN b[254]
    DIRECTION OUTPUT ;
    USE SIGNAL ;
    PORT
      LAYER M4 ;
        RECT  104.004 70.416 104.088 70.44 ;
    END
  END b[254]
  PIN b[255]
    DIRECTION OUTPUT ;
    USE SIGNAL ;
    PORT
      LAYER M4 ;
        RECT  104.004 70.512 104.088 70.536 ;
    END
  END b[255]
  PIN b[256]
    DIRECTION OUTPUT ;
    USE SIGNAL ;
    PORT
      LAYER M4 ;
        RECT  104.004 70.608 104.088 70.632 ;
    END
  END b[256]
  PIN b[257]
    DIRECTION OUTPUT ;
    USE SIGNAL ;
    PORT
      LAYER M4 ;
        RECT  104.004 70.704 104.088 70.728 ;
    END
  END b[257]
  PIN b[258]
    DIRECTION OUTPUT ;
    USE SIGNAL ;
    PORT
      LAYER M4 ;
        RECT  104.004 70.8 104.088 70.824 ;
    END
  END b[258]
  PIN b[259]
    DIRECTION OUTPUT ;
    USE SIGNAL ;
    PORT
      LAYER M4 ;
        RECT  104.004 70.896 104.088 70.92 ;
    END
  END b[259]
  PIN b[25]
    DIRECTION OUTPUT ;
    USE SIGNAL ;
    PORT
      LAYER M4 ;
        RECT  104.004 44.592 104.088 44.616 ;
    END
  END b[25]
  PIN b[260]
    DIRECTION OUTPUT ;
    USE SIGNAL ;
    PORT
      LAYER M4 ;
        RECT  104.004 70.992 104.088 71.016 ;
    END
  END b[260]
  PIN b[261]
    DIRECTION OUTPUT ;
    USE SIGNAL ;
    PORT
      LAYER M4 ;
        RECT  104.004 71.088 104.088 71.112 ;
    END
  END b[261]
  PIN b[262]
    DIRECTION OUTPUT ;
    USE SIGNAL ;
    PORT
      LAYER M4 ;
        RECT  104.004 71.184 104.088 71.208 ;
    END
  END b[262]
  PIN b[263]
    DIRECTION OUTPUT ;
    USE SIGNAL ;
    PORT
      LAYER M4 ;
        RECT  104.004 71.28 104.088 71.304 ;
    END
  END b[263]
  PIN b[264]
    DIRECTION OUTPUT ;
    USE SIGNAL ;
    PORT
      LAYER M4 ;
        RECT  104.004 71.376 104.088 71.4 ;
    END
  END b[264]
  PIN b[265]
    DIRECTION OUTPUT ;
    USE SIGNAL ;
    PORT
      LAYER M4 ;
        RECT  104.004 71.472 104.088 71.496 ;
    END
  END b[265]
  PIN b[266]
    DIRECTION OUTPUT ;
    USE SIGNAL ;
    PORT
      LAYER M4 ;
        RECT  104.004 71.568 104.088 71.592 ;
    END
  END b[266]
  PIN b[267]
    DIRECTION OUTPUT ;
    USE SIGNAL ;
    PORT
      LAYER M4 ;
        RECT  104.004 71.664 104.088 71.688 ;
    END
  END b[267]
  PIN b[268]
    DIRECTION OUTPUT ;
    USE SIGNAL ;
    PORT
      LAYER M4 ;
        RECT  104.004 71.76 104.088 71.784 ;
    END
  END b[268]
  PIN b[269]
    DIRECTION OUTPUT ;
    USE SIGNAL ;
    PORT
      LAYER M4 ;
        RECT  104.004 71.856 104.088 71.88 ;
    END
  END b[269]
  PIN b[26]
    DIRECTION OUTPUT ;
    USE SIGNAL ;
    PORT
      LAYER M4 ;
        RECT  104.004 44.688 104.088 44.712 ;
    END
  END b[26]
  PIN b[270]
    DIRECTION OUTPUT ;
    USE SIGNAL ;
    PORT
      LAYER M4 ;
        RECT  104.004 71.952 104.088 71.976 ;
    END
  END b[270]
  PIN b[271]
    DIRECTION OUTPUT ;
    USE SIGNAL ;
    PORT
      LAYER M4 ;
        RECT  104.004 72.048 104.088 72.072 ;
    END
  END b[271]
  PIN b[272]
    DIRECTION OUTPUT ;
    USE SIGNAL ;
    PORT
      LAYER M4 ;
        RECT  104.004 72.144 104.088 72.168 ;
    END
  END b[272]
  PIN b[273]
    DIRECTION OUTPUT ;
    USE SIGNAL ;
    PORT
      LAYER M4 ;
        RECT  104.004 72.24 104.088 72.264 ;
    END
  END b[273]
  PIN b[274]
    DIRECTION OUTPUT ;
    USE SIGNAL ;
    PORT
      LAYER M4 ;
        RECT  104.004 72.336 104.088 72.36 ;
    END
  END b[274]
  PIN b[275]
    DIRECTION OUTPUT ;
    USE SIGNAL ;
    PORT
      LAYER M4 ;
        RECT  104.004 72.432 104.088 72.456 ;
    END
  END b[275]
  PIN b[276]
    DIRECTION OUTPUT ;
    USE SIGNAL ;
    PORT
      LAYER M4 ;
        RECT  104.004 72.528 104.088 72.552 ;
    END
  END b[276]
  PIN b[277]
    DIRECTION OUTPUT ;
    USE SIGNAL ;
    PORT
      LAYER M4 ;
        RECT  104.004 72.624 104.088 72.648 ;
    END
  END b[277]
  PIN b[278]
    DIRECTION OUTPUT ;
    USE SIGNAL ;
    PORT
      LAYER M4 ;
        RECT  104.004 72.72 104.088 72.744 ;
    END
  END b[278]
  PIN b[279]
    DIRECTION OUTPUT ;
    USE SIGNAL ;
    PORT
      LAYER M4 ;
        RECT  104.004 72.816 104.088 72.84 ;
    END
  END b[279]
  PIN b[27]
    DIRECTION OUTPUT ;
    USE SIGNAL ;
    PORT
      LAYER M4 ;
        RECT  104.004 44.784 104.088 44.808 ;
    END
  END b[27]
  PIN b[280]
    DIRECTION OUTPUT ;
    USE SIGNAL ;
    PORT
      LAYER M4 ;
        RECT  104.004 72.912 104.088 72.936 ;
    END
  END b[280]
  PIN b[281]
    DIRECTION OUTPUT ;
    USE SIGNAL ;
    PORT
      LAYER M4 ;
        RECT  104.004 73.008 104.088 73.032 ;
    END
  END b[281]
  PIN b[282]
    DIRECTION OUTPUT ;
    USE SIGNAL ;
    PORT
      LAYER M4 ;
        RECT  104.004 73.104 104.088 73.128 ;
    END
  END b[282]
  PIN b[283]
    DIRECTION OUTPUT ;
    USE SIGNAL ;
    PORT
      LAYER M4 ;
        RECT  104.004 73.2 104.088 73.224 ;
    END
  END b[283]
  PIN b[284]
    DIRECTION OUTPUT ;
    USE SIGNAL ;
    PORT
      LAYER M4 ;
        RECT  104.004 73.296 104.088 73.32 ;
    END
  END b[284]
  PIN b[285]
    DIRECTION OUTPUT ;
    USE SIGNAL ;
    PORT
      LAYER M4 ;
        RECT  104.004 73.392 104.088 73.416 ;
    END
  END b[285]
  PIN b[286]
    DIRECTION OUTPUT ;
    USE SIGNAL ;
    PORT
      LAYER M4 ;
        RECT  104.004 73.488 104.088 73.512 ;
    END
  END b[286]
  PIN b[287]
    DIRECTION OUTPUT ;
    USE SIGNAL ;
    PORT
      LAYER M4 ;
        RECT  104.004 73.584 104.088 73.608 ;
    END
  END b[287]
  PIN b[288]
    DIRECTION OUTPUT ;
    USE SIGNAL ;
    PORT
      LAYER M4 ;
        RECT  104.004 73.68 104.088 73.704 ;
    END
  END b[288]
  PIN b[289]
    DIRECTION OUTPUT ;
    USE SIGNAL ;
    PORT
      LAYER M4 ;
        RECT  104.004 73.776 104.088 73.8 ;
    END
  END b[289]
  PIN b[28]
    DIRECTION OUTPUT ;
    USE SIGNAL ;
    PORT
      LAYER M4 ;
        RECT  104.004 44.88 104.088 44.904 ;
    END
  END b[28]
  PIN b[290]
    DIRECTION OUTPUT ;
    USE SIGNAL ;
    PORT
      LAYER M4 ;
        RECT  104.004 73.872 104.088 73.896 ;
    END
  END b[290]
  PIN b[291]
    DIRECTION OUTPUT ;
    USE SIGNAL ;
    PORT
      LAYER M4 ;
        RECT  104.004 73.968 104.088 73.992 ;
    END
  END b[291]
  PIN b[292]
    DIRECTION OUTPUT ;
    USE SIGNAL ;
    PORT
      LAYER M4 ;
        RECT  104.004 74.064 104.088 74.088 ;
    END
  END b[292]
  PIN b[293]
    DIRECTION OUTPUT ;
    USE SIGNAL ;
    PORT
      LAYER M4 ;
        RECT  104.004 74.16 104.088 74.184 ;
    END
  END b[293]
  PIN b[294]
    DIRECTION OUTPUT ;
    USE SIGNAL ;
    PORT
      LAYER M4 ;
        RECT  104.004 74.256 104.088 74.28 ;
    END
  END b[294]
  PIN b[295]
    DIRECTION OUTPUT ;
    USE SIGNAL ;
    PORT
      LAYER M4 ;
        RECT  104.004 74.352 104.088 74.376 ;
    END
  END b[295]
  PIN b[296]
    DIRECTION OUTPUT ;
    USE SIGNAL ;
    PORT
      LAYER M4 ;
        RECT  104.004 74.448 104.088 74.472 ;
    END
  END b[296]
  PIN b[297]
    DIRECTION OUTPUT ;
    USE SIGNAL ;
    PORT
      LAYER M4 ;
        RECT  104.004 74.544 104.088 74.568 ;
    END
  END b[297]
  PIN b[298]
    DIRECTION OUTPUT ;
    USE SIGNAL ;
    PORT
      LAYER M4 ;
        RECT  104.004 74.64 104.088 74.664 ;
    END
  END b[298]
  PIN b[299]
    DIRECTION OUTPUT ;
    USE SIGNAL ;
    PORT
      LAYER M4 ;
        RECT  104.004 74.736 104.088 74.76 ;
    END
  END b[299]
  PIN b[29]
    DIRECTION OUTPUT ;
    USE SIGNAL ;
    PORT
      LAYER M4 ;
        RECT  104.004 44.976 104.088 45 ;
    END
  END b[29]
  PIN b[2]
    DIRECTION OUTPUT ;
    USE SIGNAL ;
    PORT
      LAYER M4 ;
        RECT  104.004 42.384 104.088 42.408 ;
    END
  END b[2]
  PIN b[300]
    DIRECTION OUTPUT ;
    USE SIGNAL ;
    PORT
      LAYER M4 ;
        RECT  104.004 74.832 104.088 74.856 ;
    END
  END b[300]
  PIN b[301]
    DIRECTION OUTPUT ;
    USE SIGNAL ;
    PORT
      LAYER M4 ;
        RECT  104.004 74.928 104.088 74.952 ;
    END
  END b[301]
  PIN b[302]
    DIRECTION OUTPUT ;
    USE SIGNAL ;
    PORT
      LAYER M4 ;
        RECT  104.004 75.024 104.088 75.048 ;
    END
  END b[302]
  PIN b[303]
    DIRECTION OUTPUT ;
    USE SIGNAL ;
    PORT
      LAYER M4 ;
        RECT  104.004 75.12 104.088 75.144 ;
    END
  END b[303]
  PIN b[304]
    DIRECTION OUTPUT ;
    USE SIGNAL ;
    PORT
      LAYER M4 ;
        RECT  104.004 75.216 104.088 75.24 ;
    END
  END b[304]
  PIN b[305]
    DIRECTION OUTPUT ;
    USE SIGNAL ;
    PORT
      LAYER M4 ;
        RECT  104.004 75.312 104.088 75.336 ;
    END
  END b[305]
  PIN b[306]
    DIRECTION OUTPUT ;
    USE SIGNAL ;
    PORT
      LAYER M4 ;
        RECT  104.004 75.408 104.088 75.432 ;
    END
  END b[306]
  PIN b[307]
    DIRECTION OUTPUT ;
    USE SIGNAL ;
    PORT
      LAYER M4 ;
        RECT  104.004 75.504 104.088 75.528 ;
    END
  END b[307]
  PIN b[308]
    DIRECTION OUTPUT ;
    USE SIGNAL ;
    PORT
      LAYER M4 ;
        RECT  104.004 75.6 104.088 75.624 ;
    END
  END b[308]
  PIN b[309]
    DIRECTION OUTPUT ;
    USE SIGNAL ;
    PORT
      LAYER M4 ;
        RECT  104.004 75.696 104.088 75.72 ;
    END
  END b[309]
  PIN b[30]
    DIRECTION OUTPUT ;
    USE SIGNAL ;
    PORT
      LAYER M4 ;
        RECT  104.004 45.072 104.088 45.096 ;
    END
  END b[30]
  PIN b[310]
    DIRECTION OUTPUT ;
    USE SIGNAL ;
    PORT
      LAYER M4 ;
        RECT  104.004 75.792 104.088 75.816 ;
    END
  END b[310]
  PIN b[311]
    DIRECTION OUTPUT ;
    USE SIGNAL ;
    PORT
      LAYER M4 ;
        RECT  104.004 75.888 104.088 75.912 ;
    END
  END b[311]
  PIN b[312]
    DIRECTION OUTPUT ;
    USE SIGNAL ;
    PORT
      LAYER M4 ;
        RECT  104.004 75.984 104.088 76.008 ;
    END
  END b[312]
  PIN b[313]
    DIRECTION OUTPUT ;
    USE SIGNAL ;
    PORT
      LAYER M4 ;
        RECT  104.004 76.08 104.088 76.104 ;
    END
  END b[313]
  PIN b[314]
    DIRECTION OUTPUT ;
    USE SIGNAL ;
    PORT
      LAYER M4 ;
        RECT  104.004 76.176 104.088 76.2 ;
    END
  END b[314]
  PIN b[315]
    DIRECTION OUTPUT ;
    USE SIGNAL ;
    PORT
      LAYER M4 ;
        RECT  104.004 76.272 104.088 76.296 ;
    END
  END b[315]
  PIN b[316]
    DIRECTION OUTPUT ;
    USE SIGNAL ;
    PORT
      LAYER M4 ;
        RECT  104.004 76.368 104.088 76.392 ;
    END
  END b[316]
  PIN b[317]
    DIRECTION OUTPUT ;
    USE SIGNAL ;
    PORT
      LAYER M4 ;
        RECT  104.004 76.464 104.088 76.488 ;
    END
  END b[317]
  PIN b[318]
    DIRECTION OUTPUT ;
    USE SIGNAL ;
    PORT
      LAYER M4 ;
        RECT  104.004 76.56 104.088 76.584 ;
    END
  END b[318]
  PIN b[319]
    DIRECTION OUTPUT ;
    USE SIGNAL ;
    PORT
      LAYER M4 ;
        RECT  104.004 76.656 104.088 76.68 ;
    END
  END b[319]
  PIN b[31]
    DIRECTION OUTPUT ;
    USE SIGNAL ;
    PORT
      LAYER M4 ;
        RECT  104.004 45.168 104.088 45.192 ;
    END
  END b[31]
  PIN b[320]
    DIRECTION OUTPUT ;
    USE SIGNAL ;
    PORT
      LAYER M4 ;
        RECT  104.004 58.32 104.088 58.344 ;
    END
  END b[320]
  PIN b[321]
    DIRECTION OUTPUT ;
    USE SIGNAL ;
    PORT
      LAYER M4 ;
        RECT  104.004 58.416 104.088 58.44 ;
    END
  END b[321]
  PIN b[322]
    DIRECTION OUTPUT ;
    USE SIGNAL ;
    PORT
      LAYER M4 ;
        RECT  104.004 58.512 104.088 58.536 ;
    END
  END b[322]
  PIN b[323]
    DIRECTION OUTPUT ;
    USE SIGNAL ;
    PORT
      LAYER M4 ;
        RECT  104.004 58.608 104.088 58.632 ;
    END
  END b[323]
  PIN b[324]
    DIRECTION OUTPUT ;
    USE SIGNAL ;
    PORT
      LAYER M4 ;
        RECT  104.004 58.704 104.088 58.728 ;
    END
  END b[324]
  PIN b[325]
    DIRECTION OUTPUT ;
    USE SIGNAL ;
    PORT
      LAYER M4 ;
        RECT  104.004 58.8 104.088 58.824 ;
    END
  END b[325]
  PIN b[326]
    DIRECTION OUTPUT ;
    USE SIGNAL ;
    PORT
      LAYER M4 ;
        RECT  104.004 58.896 104.088 58.92 ;
    END
  END b[326]
  PIN b[327]
    DIRECTION OUTPUT ;
    USE SIGNAL ;
    PORT
      LAYER M4 ;
        RECT  104.004 58.992 104.088 59.016 ;
    END
  END b[327]
  PIN b[328]
    DIRECTION OUTPUT ;
    USE SIGNAL ;
    PORT
      LAYER M4 ;
        RECT  104.004 59.088 104.088 59.112 ;
    END
  END b[328]
  PIN b[329]
    DIRECTION OUTPUT ;
    USE SIGNAL ;
    PORT
      LAYER M4 ;
        RECT  104.004 59.184 104.088 59.208 ;
    END
  END b[329]
  PIN b[32]
    DIRECTION OUTPUT ;
    USE SIGNAL ;
    PORT
      LAYER M4 ;
        RECT  104.004 54.48 104.088 54.504 ;
    END
  END b[32]
  PIN b[330]
    DIRECTION OUTPUT ;
    USE SIGNAL ;
    PORT
      LAYER M4 ;
        RECT  104.004 59.28 104.088 59.304 ;
    END
  END b[330]
  PIN b[331]
    DIRECTION OUTPUT ;
    USE SIGNAL ;
    PORT
      LAYER M4 ;
        RECT  104.004 59.376 104.088 59.4 ;
    END
  END b[331]
  PIN b[332]
    DIRECTION OUTPUT ;
    USE SIGNAL ;
    PORT
      LAYER M4 ;
        RECT  104.004 59.472 104.088 59.496 ;
    END
  END b[332]
  PIN b[333]
    DIRECTION OUTPUT ;
    USE SIGNAL ;
    PORT
      LAYER M4 ;
        RECT  104.004 59.568 104.088 59.592 ;
    END
  END b[333]
  PIN b[334]
    DIRECTION OUTPUT ;
    USE SIGNAL ;
    PORT
      LAYER M4 ;
        RECT  104.004 59.664 104.088 59.688 ;
    END
  END b[334]
  PIN b[335]
    DIRECTION OUTPUT ;
    USE SIGNAL ;
    PORT
      LAYER M4 ;
        RECT  104.004 59.76 104.088 59.784 ;
    END
  END b[335]
  PIN b[336]
    DIRECTION OUTPUT ;
    USE SIGNAL ;
    PORT
      LAYER M4 ;
        RECT  104.004 59.856 104.088 59.88 ;
    END
  END b[336]
  PIN b[337]
    DIRECTION OUTPUT ;
    USE SIGNAL ;
    PORT
      LAYER M4 ;
        RECT  104.004 59.952 104.088 59.976 ;
    END
  END b[337]
  PIN b[338]
    DIRECTION OUTPUT ;
    USE SIGNAL ;
    PORT
      LAYER M4 ;
        RECT  104.004 60.048 104.088 60.072 ;
    END
  END b[338]
  PIN b[339]
    DIRECTION OUTPUT ;
    USE SIGNAL ;
    PORT
      LAYER M4 ;
        RECT  104.004 60.144 104.088 60.168 ;
    END
  END b[339]
  PIN b[33]
    DIRECTION OUTPUT ;
    USE SIGNAL ;
    PORT
      LAYER M4 ;
        RECT  104.004 54.576 104.088 54.6 ;
    END
  END b[33]
  PIN b[340]
    DIRECTION OUTPUT ;
    USE SIGNAL ;
    PORT
      LAYER M4 ;
        RECT  104.004 60.24 104.088 60.264 ;
    END
  END b[340]
  PIN b[341]
    DIRECTION OUTPUT ;
    USE SIGNAL ;
    PORT
      LAYER M4 ;
        RECT  104.004 60.336 104.088 60.36 ;
    END
  END b[341]
  PIN b[342]
    DIRECTION OUTPUT ;
    USE SIGNAL ;
    PORT
      LAYER M4 ;
        RECT  104.004 60.432 104.088 60.456 ;
    END
  END b[342]
  PIN b[343]
    DIRECTION OUTPUT ;
    USE SIGNAL ;
    PORT
      LAYER M4 ;
        RECT  104.004 60.528 104.088 60.552 ;
    END
  END b[343]
  PIN b[344]
    DIRECTION OUTPUT ;
    USE SIGNAL ;
    PORT
      LAYER M4 ;
        RECT  104.004 60.624 104.088 60.648 ;
    END
  END b[344]
  PIN b[345]
    DIRECTION OUTPUT ;
    USE SIGNAL ;
    PORT
      LAYER M4 ;
        RECT  104.004 60.72 104.088 60.744 ;
    END
  END b[345]
  PIN b[346]
    DIRECTION OUTPUT ;
    USE SIGNAL ;
    PORT
      LAYER M4 ;
        RECT  104.004 60.816 104.088 60.84 ;
    END
  END b[346]
  PIN b[347]
    DIRECTION OUTPUT ;
    USE SIGNAL ;
    PORT
      LAYER M4 ;
        RECT  104.004 60.912 104.088 60.936 ;
    END
  END b[347]
  PIN b[348]
    DIRECTION OUTPUT ;
    USE SIGNAL ;
    PORT
      LAYER M4 ;
        RECT  104.004 61.008 104.088 61.032 ;
    END
  END b[348]
  PIN b[349]
    DIRECTION OUTPUT ;
    USE SIGNAL ;
    PORT
      LAYER M4 ;
        RECT  104.004 61.104 104.088 61.128 ;
    END
  END b[349]
  PIN b[34]
    DIRECTION OUTPUT ;
    USE SIGNAL ;
    PORT
      LAYER M4 ;
        RECT  104.004 54.672 104.088 54.696 ;
    END
  END b[34]
  PIN b[350]
    DIRECTION OUTPUT ;
    USE SIGNAL ;
    PORT
      LAYER M4 ;
        RECT  104.004 61.2 104.088 61.224 ;
    END
  END b[350]
  PIN b[351]
    DIRECTION OUTPUT ;
    USE SIGNAL ;
    PORT
      LAYER M4 ;
        RECT  104.004 61.296 104.088 61.32 ;
    END
  END b[351]
  PIN b[352]
    DIRECTION OUTPUT ;
    USE SIGNAL ;
    PORT
      LAYER M4 ;
        RECT  104.004 64.464 104.088 64.488 ;
    END
  END b[352]
  PIN b[353]
    DIRECTION OUTPUT ;
    USE SIGNAL ;
    PORT
      LAYER M4 ;
        RECT  104.004 64.56 104.088 64.584 ;
    END
  END b[353]
  PIN b[354]
    DIRECTION OUTPUT ;
    USE SIGNAL ;
    PORT
      LAYER M4 ;
        RECT  104.004 64.656 104.088 64.68 ;
    END
  END b[354]
  PIN b[355]
    DIRECTION OUTPUT ;
    USE SIGNAL ;
    PORT
      LAYER M4 ;
        RECT  104.004 64.752 104.088 64.776 ;
    END
  END b[355]
  PIN b[356]
    DIRECTION OUTPUT ;
    USE SIGNAL ;
    PORT
      LAYER M4 ;
        RECT  104.004 64.848 104.088 64.872 ;
    END
  END b[356]
  PIN b[357]
    DIRECTION OUTPUT ;
    USE SIGNAL ;
    PORT
      LAYER M4 ;
        RECT  104.004 64.944 104.088 64.968 ;
    END
  END b[357]
  PIN b[358]
    DIRECTION OUTPUT ;
    USE SIGNAL ;
    PORT
      LAYER M4 ;
        RECT  104.004 65.04 104.088 65.064 ;
    END
  END b[358]
  PIN b[359]
    DIRECTION OUTPUT ;
    USE SIGNAL ;
    PORT
      LAYER M4 ;
        RECT  104.004 65.136 104.088 65.16 ;
    END
  END b[359]
  PIN b[35]
    DIRECTION OUTPUT ;
    USE SIGNAL ;
    PORT
      LAYER M4 ;
        RECT  104.004 54.768 104.088 54.792 ;
    END
  END b[35]
  PIN b[360]
    DIRECTION OUTPUT ;
    USE SIGNAL ;
    PORT
      LAYER M4 ;
        RECT  104.004 65.232 104.088 65.256 ;
    END
  END b[360]
  PIN b[361]
    DIRECTION OUTPUT ;
    USE SIGNAL ;
    PORT
      LAYER M4 ;
        RECT  104.004 65.328 104.088 65.352 ;
    END
  END b[361]
  PIN b[362]
    DIRECTION OUTPUT ;
    USE SIGNAL ;
    PORT
      LAYER M4 ;
        RECT  104.004 65.424 104.088 65.448 ;
    END
  END b[362]
  PIN b[363]
    DIRECTION OUTPUT ;
    USE SIGNAL ;
    PORT
      LAYER M4 ;
        RECT  104.004 65.52 104.088 65.544 ;
    END
  END b[363]
  PIN b[364]
    DIRECTION OUTPUT ;
    USE SIGNAL ;
    PORT
      LAYER M4 ;
        RECT  104.004 65.616 104.088 65.64 ;
    END
  END b[364]
  PIN b[365]
    DIRECTION OUTPUT ;
    USE SIGNAL ;
    PORT
      LAYER M4 ;
        RECT  104.004 65.712 104.088 65.736 ;
    END
  END b[365]
  PIN b[366]
    DIRECTION OUTPUT ;
    USE SIGNAL ;
    PORT
      LAYER M4 ;
        RECT  104.004 65.808 104.088 65.832 ;
    END
  END b[366]
  PIN b[367]
    DIRECTION OUTPUT ;
    USE SIGNAL ;
    PORT
      LAYER M4 ;
        RECT  104.004 65.904 104.088 65.928 ;
    END
  END b[367]
  PIN b[368]
    DIRECTION OUTPUT ;
    USE SIGNAL ;
    PORT
      LAYER M4 ;
        RECT  104.004 66 104.088 66.024 ;
    END
  END b[368]
  PIN b[369]
    DIRECTION OUTPUT ;
    USE SIGNAL ;
    PORT
      LAYER M4 ;
        RECT  104.004 66.096 104.088 66.12 ;
    END
  END b[369]
  PIN b[36]
    DIRECTION OUTPUT ;
    USE SIGNAL ;
    PORT
      LAYER M4 ;
        RECT  104.004 54.864 104.088 54.888 ;
    END
  END b[36]
  PIN b[370]
    DIRECTION OUTPUT ;
    USE SIGNAL ;
    PORT
      LAYER M4 ;
        RECT  104.004 66.192 104.088 66.216 ;
    END
  END b[370]
  PIN b[371]
    DIRECTION OUTPUT ;
    USE SIGNAL ;
    PORT
      LAYER M4 ;
        RECT  104.004 66.288 104.088 66.312 ;
    END
  END b[371]
  PIN b[372]
    DIRECTION OUTPUT ;
    USE SIGNAL ;
    PORT
      LAYER M4 ;
        RECT  104.004 66.384 104.088 66.408 ;
    END
  END b[372]
  PIN b[373]
    DIRECTION OUTPUT ;
    USE SIGNAL ;
    PORT
      LAYER M4 ;
        RECT  104.004 66.48 104.088 66.504 ;
    END
  END b[373]
  PIN b[374]
    DIRECTION OUTPUT ;
    USE SIGNAL ;
    PORT
      LAYER M4 ;
        RECT  104.004 66.576 104.088 66.6 ;
    END
  END b[374]
  PIN b[375]
    DIRECTION OUTPUT ;
    USE SIGNAL ;
    PORT
      LAYER M4 ;
        RECT  104.004 66.672 104.088 66.696 ;
    END
  END b[375]
  PIN b[376]
    DIRECTION OUTPUT ;
    USE SIGNAL ;
    PORT
      LAYER M4 ;
        RECT  104.004 66.768 104.088 66.792 ;
    END
  END b[376]
  PIN b[377]
    DIRECTION OUTPUT ;
    USE SIGNAL ;
    PORT
      LAYER M4 ;
        RECT  104.004 66.864 104.088 66.888 ;
    END
  END b[377]
  PIN b[378]
    DIRECTION OUTPUT ;
    USE SIGNAL ;
    PORT
      LAYER M4 ;
        RECT  104.004 66.96 104.088 66.984 ;
    END
  END b[378]
  PIN b[379]
    DIRECTION OUTPUT ;
    USE SIGNAL ;
    PORT
      LAYER M4 ;
        RECT  104.004 67.056 104.088 67.08 ;
    END
  END b[379]
  PIN b[37]
    DIRECTION OUTPUT ;
    USE SIGNAL ;
    PORT
      LAYER M4 ;
        RECT  104.004 54.96 104.088 54.984 ;
    END
  END b[37]
  PIN b[380]
    DIRECTION OUTPUT ;
    USE SIGNAL ;
    PORT
      LAYER M4 ;
        RECT  104.004 67.152 104.088 67.176 ;
    END
  END b[380]
  PIN b[381]
    DIRECTION OUTPUT ;
    USE SIGNAL ;
    PORT
      LAYER M4 ;
        RECT  104.004 67.248 104.088 67.272 ;
    END
  END b[381]
  PIN b[382]
    DIRECTION OUTPUT ;
    USE SIGNAL ;
    PORT
      LAYER M4 ;
        RECT  104.004 67.344 104.088 67.368 ;
    END
  END b[382]
  PIN b[383]
    DIRECTION OUTPUT ;
    USE SIGNAL ;
    PORT
      LAYER M4 ;
        RECT  104.004 67.44 104.088 67.464 ;
    END
  END b[383]
  PIN b[384]
    DIRECTION OUTPUT ;
    USE SIGNAL ;
    PORT
      LAYER M4 ;
        RECT  104.004 19.92 104.088 19.944 ;
    END
  END b[384]
  PIN b[385]
    DIRECTION OUTPUT ;
    USE SIGNAL ;
    PORT
      LAYER M4 ;
        RECT  104.004 20.016 104.088 20.04 ;
    END
  END b[385]
  PIN b[386]
    DIRECTION OUTPUT ;
    USE SIGNAL ;
    PORT
      LAYER M4 ;
        RECT  104.004 20.112 104.088 20.136 ;
    END
  END b[386]
  PIN b[387]
    DIRECTION OUTPUT ;
    USE SIGNAL ;
    PORT
      LAYER M4 ;
        RECT  104.004 20.208 104.088 20.232 ;
    END
  END b[387]
  PIN b[388]
    DIRECTION OUTPUT ;
    USE SIGNAL ;
    PORT
      LAYER M4 ;
        RECT  104.004 20.304 104.088 20.328 ;
    END
  END b[388]
  PIN b[389]
    DIRECTION OUTPUT ;
    USE SIGNAL ;
    PORT
      LAYER M4 ;
        RECT  104.004 20.4 104.088 20.424 ;
    END
  END b[389]
  PIN b[38]
    DIRECTION OUTPUT ;
    USE SIGNAL ;
    PORT
      LAYER M4 ;
        RECT  104.004 55.056 104.088 55.08 ;
    END
  END b[38]
  PIN b[390]
    DIRECTION OUTPUT ;
    USE SIGNAL ;
    PORT
      LAYER M4 ;
        RECT  104.004 20.496 104.088 20.52 ;
    END
  END b[390]
  PIN b[391]
    DIRECTION OUTPUT ;
    USE SIGNAL ;
    PORT
      LAYER M4 ;
        RECT  104.004 20.592 104.088 20.616 ;
    END
  END b[391]
  PIN b[392]
    DIRECTION OUTPUT ;
    USE SIGNAL ;
    PORT
      LAYER M4 ;
        RECT  104.004 20.688 104.088 20.712 ;
    END
  END b[392]
  PIN b[393]
    DIRECTION OUTPUT ;
    USE SIGNAL ;
    PORT
      LAYER M4 ;
        RECT  104.004 20.784 104.088 20.808 ;
    END
  END b[393]
  PIN b[394]
    DIRECTION OUTPUT ;
    USE SIGNAL ;
    PORT
      LAYER M4 ;
        RECT  104.004 20.88 104.088 20.904 ;
    END
  END b[394]
  PIN b[395]
    DIRECTION OUTPUT ;
    USE SIGNAL ;
    PORT
      LAYER M4 ;
        RECT  104.004 20.976 104.088 21 ;
    END
  END b[395]
  PIN b[396]
    DIRECTION OUTPUT ;
    USE SIGNAL ;
    PORT
      LAYER M4 ;
        RECT  104.004 21.072 104.088 21.096 ;
    END
  END b[396]
  PIN b[397]
    DIRECTION OUTPUT ;
    USE SIGNAL ;
    PORT
      LAYER M4 ;
        RECT  104.004 21.168 104.088 21.192 ;
    END
  END b[397]
  PIN b[398]
    DIRECTION OUTPUT ;
    USE SIGNAL ;
    PORT
      LAYER M4 ;
        RECT  104.004 21.264 104.088 21.288 ;
    END
  END b[398]
  PIN b[399]
    DIRECTION OUTPUT ;
    USE SIGNAL ;
    PORT
      LAYER M4 ;
        RECT  104.004 21.36 104.088 21.384 ;
    END
  END b[399]
  PIN b[39]
    DIRECTION OUTPUT ;
    USE SIGNAL ;
    PORT
      LAYER M4 ;
        RECT  104.004 55.152 104.088 55.176 ;
    END
  END b[39]
  PIN b[3]
    DIRECTION OUTPUT ;
    USE SIGNAL ;
    PORT
      LAYER M4 ;
        RECT  104.004 42.48 104.088 42.504 ;
    END
  END b[3]
  PIN b[400]
    DIRECTION OUTPUT ;
    USE SIGNAL ;
    PORT
      LAYER M4 ;
        RECT  104.004 21.456 104.088 21.48 ;
    END
  END b[400]
  PIN b[401]
    DIRECTION OUTPUT ;
    USE SIGNAL ;
    PORT
      LAYER M4 ;
        RECT  104.004 21.552 104.088 21.576 ;
    END
  END b[401]
  PIN b[402]
    DIRECTION OUTPUT ;
    USE SIGNAL ;
    PORT
      LAYER M4 ;
        RECT  104.004 21.648 104.088 21.672 ;
    END
  END b[402]
  PIN b[403]
    DIRECTION OUTPUT ;
    USE SIGNAL ;
    PORT
      LAYER M4 ;
        RECT  104.004 21.744 104.088 21.768 ;
    END
  END b[403]
  PIN b[404]
    DIRECTION OUTPUT ;
    USE SIGNAL ;
    PORT
      LAYER M4 ;
        RECT  104.004 21.84 104.088 21.864 ;
    END
  END b[404]
  PIN b[405]
    DIRECTION OUTPUT ;
    USE SIGNAL ;
    PORT
      LAYER M4 ;
        RECT  104.004 21.936 104.088 21.96 ;
    END
  END b[405]
  PIN b[406]
    DIRECTION OUTPUT ;
    USE SIGNAL ;
    PORT
      LAYER M4 ;
        RECT  104.004 22.032 104.088 22.056 ;
    END
  END b[406]
  PIN b[407]
    DIRECTION OUTPUT ;
    USE SIGNAL ;
    PORT
      LAYER M4 ;
        RECT  104.004 22.128 104.088 22.152 ;
    END
  END b[407]
  PIN b[408]
    DIRECTION OUTPUT ;
    USE SIGNAL ;
    PORT
      LAYER M4 ;
        RECT  104.004 22.224 104.088 22.248 ;
    END
  END b[408]
  PIN b[409]
    DIRECTION OUTPUT ;
    USE SIGNAL ;
    PORT
      LAYER M4 ;
        RECT  104.004 22.32 104.088 22.344 ;
    END
  END b[409]
  PIN b[40]
    DIRECTION OUTPUT ;
    USE SIGNAL ;
    PORT
      LAYER M4 ;
        RECT  104.004 55.248 104.088 55.272 ;
    END
  END b[40]
  PIN b[410]
    DIRECTION OUTPUT ;
    USE SIGNAL ;
    PORT
      LAYER M4 ;
        RECT  104.004 22.416 104.088 22.44 ;
    END
  END b[410]
  PIN b[411]
    DIRECTION OUTPUT ;
    USE SIGNAL ;
    PORT
      LAYER M4 ;
        RECT  104.004 22.512 104.088 22.536 ;
    END
  END b[411]
  PIN b[412]
    DIRECTION OUTPUT ;
    USE SIGNAL ;
    PORT
      LAYER M4 ;
        RECT  104.004 22.608 104.088 22.632 ;
    END
  END b[412]
  PIN b[413]
    DIRECTION OUTPUT ;
    USE SIGNAL ;
    PORT
      LAYER M4 ;
        RECT  104.004 22.704 104.088 22.728 ;
    END
  END b[413]
  PIN b[414]
    DIRECTION OUTPUT ;
    USE SIGNAL ;
    PORT
      LAYER M4 ;
        RECT  104.004 22.8 104.088 22.824 ;
    END
  END b[414]
  PIN b[415]
    DIRECTION OUTPUT ;
    USE SIGNAL ;
    PORT
      LAYER M4 ;
        RECT  104.004 22.896 104.088 22.92 ;
    END
  END b[415]
  PIN b[416]
    DIRECTION OUTPUT ;
    USE SIGNAL ;
    PORT
      LAYER M4 ;
        RECT  104.004 26.064 104.088 26.088 ;
    END
  END b[416]
  PIN b[417]
    DIRECTION OUTPUT ;
    USE SIGNAL ;
    PORT
      LAYER M4 ;
        RECT  104.004 26.16 104.088 26.184 ;
    END
  END b[417]
  PIN b[418]
    DIRECTION OUTPUT ;
    USE SIGNAL ;
    PORT
      LAYER M4 ;
        RECT  104.004 26.256 104.088 26.28 ;
    END
  END b[418]
  PIN b[419]
    DIRECTION OUTPUT ;
    USE SIGNAL ;
    PORT
      LAYER M4 ;
        RECT  104.004 26.352 104.088 26.376 ;
    END
  END b[419]
  PIN b[41]
    DIRECTION OUTPUT ;
    USE SIGNAL ;
    PORT
      LAYER M4 ;
        RECT  104.004 55.344 104.088 55.368 ;
    END
  END b[41]
  PIN b[420]
    DIRECTION OUTPUT ;
    USE SIGNAL ;
    PORT
      LAYER M4 ;
        RECT  104.004 26.448 104.088 26.472 ;
    END
  END b[420]
  PIN b[421]
    DIRECTION OUTPUT ;
    USE SIGNAL ;
    PORT
      LAYER M4 ;
        RECT  104.004 26.544 104.088 26.568 ;
    END
  END b[421]
  PIN b[422]
    DIRECTION OUTPUT ;
    USE SIGNAL ;
    PORT
      LAYER M4 ;
        RECT  104.004 26.64 104.088 26.664 ;
    END
  END b[422]
  PIN b[423]
    DIRECTION OUTPUT ;
    USE SIGNAL ;
    PORT
      LAYER M4 ;
        RECT  104.004 26.736 104.088 26.76 ;
    END
  END b[423]
  PIN b[424]
    DIRECTION OUTPUT ;
    USE SIGNAL ;
    PORT
      LAYER M4 ;
        RECT  104.004 26.832 104.088 26.856 ;
    END
  END b[424]
  PIN b[425]
    DIRECTION OUTPUT ;
    USE SIGNAL ;
    PORT
      LAYER M4 ;
        RECT  104.004 26.928 104.088 26.952 ;
    END
  END b[425]
  PIN b[426]
    DIRECTION OUTPUT ;
    USE SIGNAL ;
    PORT
      LAYER M4 ;
        RECT  104.004 27.024 104.088 27.048 ;
    END
  END b[426]
  PIN b[427]
    DIRECTION OUTPUT ;
    USE SIGNAL ;
    PORT
      LAYER M4 ;
        RECT  104.004 27.12 104.088 27.144 ;
    END
  END b[427]
  PIN b[428]
    DIRECTION OUTPUT ;
    USE SIGNAL ;
    PORT
      LAYER M4 ;
        RECT  104.004 27.216 104.088 27.24 ;
    END
  END b[428]
  PIN b[429]
    DIRECTION OUTPUT ;
    USE SIGNAL ;
    PORT
      LAYER M4 ;
        RECT  104.004 27.312 104.088 27.336 ;
    END
  END b[429]
  PIN b[42]
    DIRECTION OUTPUT ;
    USE SIGNAL ;
    PORT
      LAYER M4 ;
        RECT  104.004 55.44 104.088 55.464 ;
    END
  END b[42]
  PIN b[430]
    DIRECTION OUTPUT ;
    USE SIGNAL ;
    PORT
      LAYER M4 ;
        RECT  104.004 27.408 104.088 27.432 ;
    END
  END b[430]
  PIN b[431]
    DIRECTION OUTPUT ;
    USE SIGNAL ;
    PORT
      LAYER M4 ;
        RECT  104.004 27.504 104.088 27.528 ;
    END
  END b[431]
  PIN b[432]
    DIRECTION OUTPUT ;
    USE SIGNAL ;
    PORT
      LAYER M4 ;
        RECT  104.004 27.6 104.088 27.624 ;
    END
  END b[432]
  PIN b[433]
    DIRECTION OUTPUT ;
    USE SIGNAL ;
    PORT
      LAYER M4 ;
        RECT  104.004 27.696 104.088 27.72 ;
    END
  END b[433]
  PIN b[434]
    DIRECTION OUTPUT ;
    USE SIGNAL ;
    PORT
      LAYER M4 ;
        RECT  104.004 27.792 104.088 27.816 ;
    END
  END b[434]
  PIN b[435]
    DIRECTION OUTPUT ;
    USE SIGNAL ;
    PORT
      LAYER M4 ;
        RECT  104.004 27.888 104.088 27.912 ;
    END
  END b[435]
  PIN b[436]
    DIRECTION OUTPUT ;
    USE SIGNAL ;
    PORT
      LAYER M4 ;
        RECT  104.004 27.984 104.088 28.008 ;
    END
  END b[436]
  PIN b[437]
    DIRECTION OUTPUT ;
    USE SIGNAL ;
    PORT
      LAYER M4 ;
        RECT  104.004 28.08 104.088 28.104 ;
    END
  END b[437]
  PIN b[438]
    DIRECTION OUTPUT ;
    USE SIGNAL ;
    PORT
      LAYER M4 ;
        RECT  104.004 28.176 104.088 28.2 ;
    END
  END b[438]
  PIN b[439]
    DIRECTION OUTPUT ;
    USE SIGNAL ;
    PORT
      LAYER M4 ;
        RECT  104.004 28.272 104.088 28.296 ;
    END
  END b[439]
  PIN b[43]
    DIRECTION OUTPUT ;
    USE SIGNAL ;
    PORT
      LAYER M4 ;
        RECT  104.004 55.536 104.088 55.56 ;
    END
  END b[43]
  PIN b[440]
    DIRECTION OUTPUT ;
    USE SIGNAL ;
    PORT
      LAYER M4 ;
        RECT  104.004 28.368 104.088 28.392 ;
    END
  END b[440]
  PIN b[441]
    DIRECTION OUTPUT ;
    USE SIGNAL ;
    PORT
      LAYER M4 ;
        RECT  104.004 28.464 104.088 28.488 ;
    END
  END b[441]
  PIN b[442]
    DIRECTION OUTPUT ;
    USE SIGNAL ;
    PORT
      LAYER M4 ;
        RECT  104.004 28.56 104.088 28.584 ;
    END
  END b[442]
  PIN b[443]
    DIRECTION OUTPUT ;
    USE SIGNAL ;
    PORT
      LAYER M4 ;
        RECT  104.004 28.656 104.088 28.68 ;
    END
  END b[443]
  PIN b[444]
    DIRECTION OUTPUT ;
    USE SIGNAL ;
    PORT
      LAYER M4 ;
        RECT  104.004 28.752 104.088 28.776 ;
    END
  END b[444]
  PIN b[445]
    DIRECTION OUTPUT ;
    USE SIGNAL ;
    PORT
      LAYER M4 ;
        RECT  104.004 28.848 104.088 28.872 ;
    END
  END b[445]
  PIN b[446]
    DIRECTION OUTPUT ;
    USE SIGNAL ;
    PORT
      LAYER M4 ;
        RECT  104.004 28.944 104.088 28.968 ;
    END
  END b[446]
  PIN b[447]
    DIRECTION OUTPUT ;
    USE SIGNAL ;
    PORT
      LAYER M4 ;
        RECT  104.004 29.04 104.088 29.064 ;
    END
  END b[447]
  PIN b[448]
    DIRECTION OUTPUT ;
    USE SIGNAL ;
    PORT
      LAYER M4 ;
        RECT  104.004 35.28 104.088 35.304 ;
    END
  END b[448]
  PIN b[449]
    DIRECTION OUTPUT ;
    USE SIGNAL ;
    PORT
      LAYER M4 ;
        RECT  104.004 35.376 104.088 35.4 ;
    END
  END b[449]
  PIN b[44]
    DIRECTION OUTPUT ;
    USE SIGNAL ;
    PORT
      LAYER M4 ;
        RECT  104.004 55.632 104.088 55.656 ;
    END
  END b[44]
  PIN b[450]
    DIRECTION OUTPUT ;
    USE SIGNAL ;
    PORT
      LAYER M4 ;
        RECT  104.004 35.472 104.088 35.496 ;
    END
  END b[450]
  PIN b[451]
    DIRECTION OUTPUT ;
    USE SIGNAL ;
    PORT
      LAYER M4 ;
        RECT  104.004 35.568 104.088 35.592 ;
    END
  END b[451]
  PIN b[452]
    DIRECTION OUTPUT ;
    USE SIGNAL ;
    PORT
      LAYER M4 ;
        RECT  104.004 35.664 104.088 35.688 ;
    END
  END b[452]
  PIN b[453]
    DIRECTION OUTPUT ;
    USE SIGNAL ;
    PORT
      LAYER M4 ;
        RECT  104.004 35.76 104.088 35.784 ;
    END
  END b[453]
  PIN b[454]
    DIRECTION OUTPUT ;
    USE SIGNAL ;
    PORT
      LAYER M4 ;
        RECT  104.004 35.856 104.088 35.88 ;
    END
  END b[454]
  PIN b[455]
    DIRECTION OUTPUT ;
    USE SIGNAL ;
    PORT
      LAYER M4 ;
        RECT  104.004 35.952 104.088 35.976 ;
    END
  END b[455]
  PIN b[456]
    DIRECTION OUTPUT ;
    USE SIGNAL ;
    PORT
      LAYER M4 ;
        RECT  104.004 36.048 104.088 36.072 ;
    END
  END b[456]
  PIN b[457]
    DIRECTION OUTPUT ;
    USE SIGNAL ;
    PORT
      LAYER M4 ;
        RECT  104.004 36.144 104.088 36.168 ;
    END
  END b[457]
  PIN b[458]
    DIRECTION OUTPUT ;
    USE SIGNAL ;
    PORT
      LAYER M4 ;
        RECT  104.004 36.24 104.088 36.264 ;
    END
  END b[458]
  PIN b[459]
    DIRECTION OUTPUT ;
    USE SIGNAL ;
    PORT
      LAYER M4 ;
        RECT  104.004 36.336 104.088 36.36 ;
    END
  END b[459]
  PIN b[45]
    DIRECTION OUTPUT ;
    USE SIGNAL ;
    PORT
      LAYER M4 ;
        RECT  104.004 55.728 104.088 55.752 ;
    END
  END b[45]
  PIN b[460]
    DIRECTION OUTPUT ;
    USE SIGNAL ;
    PORT
      LAYER M4 ;
        RECT  104.004 36.432 104.088 36.456 ;
    END
  END b[460]
  PIN b[461]
    DIRECTION OUTPUT ;
    USE SIGNAL ;
    PORT
      LAYER M4 ;
        RECT  104.004 36.528 104.088 36.552 ;
    END
  END b[461]
  PIN b[462]
    DIRECTION OUTPUT ;
    USE SIGNAL ;
    PORT
      LAYER M4 ;
        RECT  104.004 36.624 104.088 36.648 ;
    END
  END b[462]
  PIN b[463]
    DIRECTION OUTPUT ;
    USE SIGNAL ;
    PORT
      LAYER M4 ;
        RECT  104.004 36.72 104.088 36.744 ;
    END
  END b[463]
  PIN b[464]
    DIRECTION OUTPUT ;
    USE SIGNAL ;
    PORT
      LAYER M4 ;
        RECT  104.004 36.816 104.088 36.84 ;
    END
  END b[464]
  PIN b[465]
    DIRECTION OUTPUT ;
    USE SIGNAL ;
    PORT
      LAYER M4 ;
        RECT  104.004 36.912 104.088 36.936 ;
    END
  END b[465]
  PIN b[466]
    DIRECTION OUTPUT ;
    USE SIGNAL ;
    PORT
      LAYER M4 ;
        RECT  104.004 37.008 104.088 37.032 ;
    END
  END b[466]
  PIN b[467]
    DIRECTION OUTPUT ;
    USE SIGNAL ;
    PORT
      LAYER M4 ;
        RECT  104.004 37.104 104.088 37.128 ;
    END
  END b[467]
  PIN b[468]
    DIRECTION OUTPUT ;
    USE SIGNAL ;
    PORT
      LAYER M4 ;
        RECT  104.004 37.2 104.088 37.224 ;
    END
  END b[468]
  PIN b[469]
    DIRECTION OUTPUT ;
    USE SIGNAL ;
    PORT
      LAYER M4 ;
        RECT  104.004 37.296 104.088 37.32 ;
    END
  END b[469]
  PIN b[46]
    DIRECTION OUTPUT ;
    USE SIGNAL ;
    PORT
      LAYER M4 ;
        RECT  104.004 55.824 104.088 55.848 ;
    END
  END b[46]
  PIN b[470]
    DIRECTION OUTPUT ;
    USE SIGNAL ;
    PORT
      LAYER M4 ;
        RECT  104.004 37.392 104.088 37.416 ;
    END
  END b[470]
  PIN b[471]
    DIRECTION OUTPUT ;
    USE SIGNAL ;
    PORT
      LAYER M4 ;
        RECT  104.004 37.488 104.088 37.512 ;
    END
  END b[471]
  PIN b[472]
    DIRECTION OUTPUT ;
    USE SIGNAL ;
    PORT
      LAYER M4 ;
        RECT  104.004 37.584 104.088 37.608 ;
    END
  END b[472]
  PIN b[473]
    DIRECTION OUTPUT ;
    USE SIGNAL ;
    PORT
      LAYER M4 ;
        RECT  104.004 37.68 104.088 37.704 ;
    END
  END b[473]
  PIN b[474]
    DIRECTION OUTPUT ;
    USE SIGNAL ;
    PORT
      LAYER M4 ;
        RECT  104.004 37.776 104.088 37.8 ;
    END
  END b[474]
  PIN b[475]
    DIRECTION OUTPUT ;
    USE SIGNAL ;
    PORT
      LAYER M4 ;
        RECT  104.004 37.872 104.088 37.896 ;
    END
  END b[475]
  PIN b[476]
    DIRECTION OUTPUT ;
    USE SIGNAL ;
    PORT
      LAYER M4 ;
        RECT  104.004 37.968 104.088 37.992 ;
    END
  END b[476]
  PIN b[477]
    DIRECTION OUTPUT ;
    USE SIGNAL ;
    PORT
      LAYER M4 ;
        RECT  104.004 38.064 104.088 38.088 ;
    END
  END b[477]
  PIN b[478]
    DIRECTION OUTPUT ;
    USE SIGNAL ;
    PORT
      LAYER M4 ;
        RECT  104.004 38.16 104.088 38.184 ;
    END
  END b[478]
  PIN b[479]
    DIRECTION OUTPUT ;
    USE SIGNAL ;
    PORT
      LAYER M4 ;
        RECT  104.004 38.256 104.088 38.28 ;
    END
  END b[479]
  PIN b[47]
    DIRECTION OUTPUT ;
    USE SIGNAL ;
    PORT
      LAYER M4 ;
        RECT  104.004 55.92 104.088 55.944 ;
    END
  END b[47]
  PIN b[480]
    DIRECTION OUTPUT ;
    USE SIGNAL ;
    PORT
      LAYER M4 ;
        RECT  104.004 29.136 104.088 29.16 ;
    END
  END b[480]
  PIN b[481]
    DIRECTION OUTPUT ;
    USE SIGNAL ;
    PORT
      LAYER M4 ;
        RECT  104.004 29.232 104.088 29.256 ;
    END
  END b[481]
  PIN b[482]
    DIRECTION OUTPUT ;
    USE SIGNAL ;
    PORT
      LAYER M4 ;
        RECT  104.004 29.328 104.088 29.352 ;
    END
  END b[482]
  PIN b[483]
    DIRECTION OUTPUT ;
    USE SIGNAL ;
    PORT
      LAYER M4 ;
        RECT  104.004 29.424 104.088 29.448 ;
    END
  END b[483]
  PIN b[484]
    DIRECTION OUTPUT ;
    USE SIGNAL ;
    PORT
      LAYER M4 ;
        RECT  104.004 29.52 104.088 29.544 ;
    END
  END b[484]
  PIN b[485]
    DIRECTION OUTPUT ;
    USE SIGNAL ;
    PORT
      LAYER M4 ;
        RECT  104.004 29.616 104.088 29.64 ;
    END
  END b[485]
  PIN b[486]
    DIRECTION OUTPUT ;
    USE SIGNAL ;
    PORT
      LAYER M4 ;
        RECT  104.004 29.712 104.088 29.736 ;
    END
  END b[486]
  PIN b[487]
    DIRECTION OUTPUT ;
    USE SIGNAL ;
    PORT
      LAYER M4 ;
        RECT  104.004 29.808 104.088 29.832 ;
    END
  END b[487]
  PIN b[488]
    DIRECTION OUTPUT ;
    USE SIGNAL ;
    PORT
      LAYER M4 ;
        RECT  104.004 29.904 104.088 29.928 ;
    END
  END b[488]
  PIN b[489]
    DIRECTION OUTPUT ;
    USE SIGNAL ;
    PORT
      LAYER M4 ;
        RECT  104.004 30 104.088 30.024 ;
    END
  END b[489]
  PIN b[48]
    DIRECTION OUTPUT ;
    USE SIGNAL ;
    PORT
      LAYER M4 ;
        RECT  104.004 56.016 104.088 56.04 ;
    END
  END b[48]
  PIN b[490]
    DIRECTION OUTPUT ;
    USE SIGNAL ;
    PORT
      LAYER M4 ;
        RECT  104.004 30.096 104.088 30.12 ;
    END
  END b[490]
  PIN b[491]
    DIRECTION OUTPUT ;
    USE SIGNAL ;
    PORT
      LAYER M4 ;
        RECT  104.004 30.192 104.088 30.216 ;
    END
  END b[491]
  PIN b[492]
    DIRECTION OUTPUT ;
    USE SIGNAL ;
    PORT
      LAYER M4 ;
        RECT  104.004 30.288 104.088 30.312 ;
    END
  END b[492]
  PIN b[493]
    DIRECTION OUTPUT ;
    USE SIGNAL ;
    PORT
      LAYER M4 ;
        RECT  104.004 30.384 104.088 30.408 ;
    END
  END b[493]
  PIN b[494]
    DIRECTION OUTPUT ;
    USE SIGNAL ;
    PORT
      LAYER M4 ;
        RECT  104.004 30.48 104.088 30.504 ;
    END
  END b[494]
  PIN b[495]
    DIRECTION OUTPUT ;
    USE SIGNAL ;
    PORT
      LAYER M4 ;
        RECT  104.004 30.576 104.088 30.6 ;
    END
  END b[495]
  PIN b[496]
    DIRECTION OUTPUT ;
    USE SIGNAL ;
    PORT
      LAYER M4 ;
        RECT  104.004 30.672 104.088 30.696 ;
    END
  END b[496]
  PIN b[497]
    DIRECTION OUTPUT ;
    USE SIGNAL ;
    PORT
      LAYER M4 ;
        RECT  104.004 30.768 104.088 30.792 ;
    END
  END b[497]
  PIN b[498]
    DIRECTION OUTPUT ;
    USE SIGNAL ;
    PORT
      LAYER M4 ;
        RECT  104.004 30.864 104.088 30.888 ;
    END
  END b[498]
  PIN b[499]
    DIRECTION OUTPUT ;
    USE SIGNAL ;
    PORT
      LAYER M4 ;
        RECT  104.004 30.96 104.088 30.984 ;
    END
  END b[499]
  PIN b[49]
    DIRECTION OUTPUT ;
    USE SIGNAL ;
    PORT
      LAYER M4 ;
        RECT  104.004 56.112 104.088 56.136 ;
    END
  END b[49]
  PIN b[4]
    DIRECTION OUTPUT ;
    USE SIGNAL ;
    PORT
      LAYER M4 ;
        RECT  104.004 42.576 104.088 42.6 ;
    END
  END b[4]
  PIN b[500]
    DIRECTION OUTPUT ;
    USE SIGNAL ;
    PORT
      LAYER M4 ;
        RECT  104.004 31.056 104.088 31.08 ;
    END
  END b[500]
  PIN b[501]
    DIRECTION OUTPUT ;
    USE SIGNAL ;
    PORT
      LAYER M4 ;
        RECT  104.004 31.152 104.088 31.176 ;
    END
  END b[501]
  PIN b[502]
    DIRECTION OUTPUT ;
    USE SIGNAL ;
    PORT
      LAYER M4 ;
        RECT  104.004 31.248 104.088 31.272 ;
    END
  END b[502]
  PIN b[503]
    DIRECTION OUTPUT ;
    USE SIGNAL ;
    PORT
      LAYER M4 ;
        RECT  104.004 31.344 104.088 31.368 ;
    END
  END b[503]
  PIN b[504]
    DIRECTION OUTPUT ;
    USE SIGNAL ;
    PORT
      LAYER M4 ;
        RECT  104.004 31.44 104.088 31.464 ;
    END
  END b[504]
  PIN b[505]
    DIRECTION OUTPUT ;
    USE SIGNAL ;
    PORT
      LAYER M4 ;
        RECT  104.004 31.536 104.088 31.56 ;
    END
  END b[505]
  PIN b[506]
    DIRECTION OUTPUT ;
    USE SIGNAL ;
    PORT
      LAYER M4 ;
        RECT  104.004 31.632 104.088 31.656 ;
    END
  END b[506]
  PIN b[507]
    DIRECTION OUTPUT ;
    USE SIGNAL ;
    PORT
      LAYER M4 ;
        RECT  104.004 31.728 104.088 31.752 ;
    END
  END b[507]
  PIN b[508]
    DIRECTION OUTPUT ;
    USE SIGNAL ;
    PORT
      LAYER M4 ;
        RECT  104.004 31.824 104.088 31.848 ;
    END
  END b[508]
  PIN b[509]
    DIRECTION OUTPUT ;
    USE SIGNAL ;
    PORT
      LAYER M4 ;
        RECT  104.004 31.92 104.088 31.944 ;
    END
  END b[509]
  PIN b[50]
    DIRECTION OUTPUT ;
    USE SIGNAL ;
    PORT
      LAYER M4 ;
        RECT  104.004 56.208 104.088 56.232 ;
    END
  END b[50]
  PIN b[510]
    DIRECTION OUTPUT ;
    USE SIGNAL ;
    PORT
      LAYER M4 ;
        RECT  104.004 32.016 104.088 32.04 ;
    END
  END b[510]
  PIN b[511]
    DIRECTION OUTPUT ;
    USE SIGNAL ;
    PORT
      LAYER M4 ;
        RECT  104.004 32.112 104.088 32.136 ;
    END
  END b[511]
  PIN b[512]
    DIRECTION OUTPUT ;
    USE SIGNAL ;
    PORT
      LAYER M4 ;
        RECT  104.004 22.992 104.088 23.016 ;
    END
  END b[512]
  PIN b[513]
    DIRECTION OUTPUT ;
    USE SIGNAL ;
    PORT
      LAYER M4 ;
        RECT  104.004 23.088 104.088 23.112 ;
    END
  END b[513]
  PIN b[514]
    DIRECTION OUTPUT ;
    USE SIGNAL ;
    PORT
      LAYER M4 ;
        RECT  104.004 23.184 104.088 23.208 ;
    END
  END b[514]
  PIN b[515]
    DIRECTION OUTPUT ;
    USE SIGNAL ;
    PORT
      LAYER M4 ;
        RECT  104.004 23.28 104.088 23.304 ;
    END
  END b[515]
  PIN b[516]
    DIRECTION OUTPUT ;
    USE SIGNAL ;
    PORT
      LAYER M4 ;
        RECT  104.004 23.376 104.088 23.4 ;
    END
  END b[516]
  PIN b[517]
    DIRECTION OUTPUT ;
    USE SIGNAL ;
    PORT
      LAYER M4 ;
        RECT  104.004 23.472 104.088 23.496 ;
    END
  END b[517]
  PIN b[518]
    DIRECTION OUTPUT ;
    USE SIGNAL ;
    PORT
      LAYER M4 ;
        RECT  104.004 23.568 104.088 23.592 ;
    END
  END b[518]
  PIN b[519]
    DIRECTION OUTPUT ;
    USE SIGNAL ;
    PORT
      LAYER M4 ;
        RECT  104.004 23.664 104.088 23.688 ;
    END
  END b[519]
  PIN b[51]
    DIRECTION OUTPUT ;
    USE SIGNAL ;
    PORT
      LAYER M4 ;
        RECT  104.004 56.304 104.088 56.328 ;
    END
  END b[51]
  PIN b[520]
    DIRECTION OUTPUT ;
    USE SIGNAL ;
    PORT
      LAYER M4 ;
        RECT  104.004 23.76 104.088 23.784 ;
    END
  END b[520]
  PIN b[521]
    DIRECTION OUTPUT ;
    USE SIGNAL ;
    PORT
      LAYER M4 ;
        RECT  104.004 23.856 104.088 23.88 ;
    END
  END b[521]
  PIN b[522]
    DIRECTION OUTPUT ;
    USE SIGNAL ;
    PORT
      LAYER M4 ;
        RECT  104.004 23.952 104.088 23.976 ;
    END
  END b[522]
  PIN b[523]
    DIRECTION OUTPUT ;
    USE SIGNAL ;
    PORT
      LAYER M4 ;
        RECT  104.004 24.048 104.088 24.072 ;
    END
  END b[523]
  PIN b[524]
    DIRECTION OUTPUT ;
    USE SIGNAL ;
    PORT
      LAYER M4 ;
        RECT  104.004 24.144 104.088 24.168 ;
    END
  END b[524]
  PIN b[525]
    DIRECTION OUTPUT ;
    USE SIGNAL ;
    PORT
      LAYER M4 ;
        RECT  104.004 24.24 104.088 24.264 ;
    END
  END b[525]
  PIN b[526]
    DIRECTION OUTPUT ;
    USE SIGNAL ;
    PORT
      LAYER M4 ;
        RECT  104.004 24.336 104.088 24.36 ;
    END
  END b[526]
  PIN b[527]
    DIRECTION OUTPUT ;
    USE SIGNAL ;
    PORT
      LAYER M4 ;
        RECT  104.004 24.432 104.088 24.456 ;
    END
  END b[527]
  PIN b[528]
    DIRECTION OUTPUT ;
    USE SIGNAL ;
    PORT
      LAYER M4 ;
        RECT  104.004 24.528 104.088 24.552 ;
    END
  END b[528]
  PIN b[529]
    DIRECTION OUTPUT ;
    USE SIGNAL ;
    PORT
      LAYER M4 ;
        RECT  104.004 24.624 104.088 24.648 ;
    END
  END b[529]
  PIN b[52]
    DIRECTION OUTPUT ;
    USE SIGNAL ;
    PORT
      LAYER M4 ;
        RECT  104.004 56.4 104.088 56.424 ;
    END
  END b[52]
  PIN b[530]
    DIRECTION OUTPUT ;
    USE SIGNAL ;
    PORT
      LAYER M4 ;
        RECT  104.004 24.72 104.088 24.744 ;
    END
  END b[530]
  PIN b[531]
    DIRECTION OUTPUT ;
    USE SIGNAL ;
    PORT
      LAYER M4 ;
        RECT  104.004 24.816 104.088 24.84 ;
    END
  END b[531]
  PIN b[532]
    DIRECTION OUTPUT ;
    USE SIGNAL ;
    PORT
      LAYER M4 ;
        RECT  104.004 24.912 104.088 24.936 ;
    END
  END b[532]
  PIN b[533]
    DIRECTION OUTPUT ;
    USE SIGNAL ;
    PORT
      LAYER M4 ;
        RECT  104.004 25.008 104.088 25.032 ;
    END
  END b[533]
  PIN b[534]
    DIRECTION OUTPUT ;
    USE SIGNAL ;
    PORT
      LAYER M4 ;
        RECT  104.004 25.104 104.088 25.128 ;
    END
  END b[534]
  PIN b[535]
    DIRECTION OUTPUT ;
    USE SIGNAL ;
    PORT
      LAYER M4 ;
        RECT  104.004 25.2 104.088 25.224 ;
    END
  END b[535]
  PIN b[536]
    DIRECTION OUTPUT ;
    USE SIGNAL ;
    PORT
      LAYER M4 ;
        RECT  104.004 25.296 104.088 25.32 ;
    END
  END b[536]
  PIN b[537]
    DIRECTION OUTPUT ;
    USE SIGNAL ;
    PORT
      LAYER M4 ;
        RECT  104.004 25.392 104.088 25.416 ;
    END
  END b[537]
  PIN b[538]
    DIRECTION OUTPUT ;
    USE SIGNAL ;
    PORT
      LAYER M4 ;
        RECT  104.004 25.488 104.088 25.512 ;
    END
  END b[538]
  PIN b[539]
    DIRECTION OUTPUT ;
    USE SIGNAL ;
    PORT
      LAYER M4 ;
        RECT  104.004 25.584 104.088 25.608 ;
    END
  END b[539]
  PIN b[53]
    DIRECTION OUTPUT ;
    USE SIGNAL ;
    PORT
      LAYER M4 ;
        RECT  104.004 56.496 104.088 56.52 ;
    END
  END b[53]
  PIN b[540]
    DIRECTION OUTPUT ;
    USE SIGNAL ;
    PORT
      LAYER M4 ;
        RECT  104.004 25.68 104.088 25.704 ;
    END
  END b[540]
  PIN b[541]
    DIRECTION OUTPUT ;
    USE SIGNAL ;
    PORT
      LAYER M4 ;
        RECT  104.004 25.776 104.088 25.8 ;
    END
  END b[541]
  PIN b[542]
    DIRECTION OUTPUT ;
    USE SIGNAL ;
    PORT
      LAYER M4 ;
        RECT  104.004 25.872 104.088 25.896 ;
    END
  END b[542]
  PIN b[543]
    DIRECTION OUTPUT ;
    USE SIGNAL ;
    PORT
      LAYER M4 ;
        RECT  104.004 25.968 104.088 25.992 ;
    END
  END b[543]
  PIN b[544]
    DIRECTION OUTPUT ;
    USE SIGNAL ;
    PORT
      LAYER M4 ;
        RECT  104.004 32.208 104.088 32.232 ;
    END
  END b[544]
  PIN b[545]
    DIRECTION OUTPUT ;
    USE SIGNAL ;
    PORT
      LAYER M4 ;
        RECT  104.004 32.304 104.088 32.328 ;
    END
  END b[545]
  PIN b[546]
    DIRECTION OUTPUT ;
    USE SIGNAL ;
    PORT
      LAYER M4 ;
        RECT  104.004 32.4 104.088 32.424 ;
    END
  END b[546]
  PIN b[547]
    DIRECTION OUTPUT ;
    USE SIGNAL ;
    PORT
      LAYER M4 ;
        RECT  104.004 32.496 104.088 32.52 ;
    END
  END b[547]
  PIN b[548]
    DIRECTION OUTPUT ;
    USE SIGNAL ;
    PORT
      LAYER M4 ;
        RECT  104.004 32.592 104.088 32.616 ;
    END
  END b[548]
  PIN b[549]
    DIRECTION OUTPUT ;
    USE SIGNAL ;
    PORT
      LAYER M4 ;
        RECT  104.004 32.688 104.088 32.712 ;
    END
  END b[549]
  PIN b[54]
    DIRECTION OUTPUT ;
    USE SIGNAL ;
    PORT
      LAYER M4 ;
        RECT  104.004 56.592 104.088 56.616 ;
    END
  END b[54]
  PIN b[550]
    DIRECTION OUTPUT ;
    USE SIGNAL ;
    PORT
      LAYER M4 ;
        RECT  104.004 32.784 104.088 32.808 ;
    END
  END b[550]
  PIN b[551]
    DIRECTION OUTPUT ;
    USE SIGNAL ;
    PORT
      LAYER M4 ;
        RECT  104.004 32.88 104.088 32.904 ;
    END
  END b[551]
  PIN b[552]
    DIRECTION OUTPUT ;
    USE SIGNAL ;
    PORT
      LAYER M4 ;
        RECT  104.004 32.976 104.088 33 ;
    END
  END b[552]
  PIN b[553]
    DIRECTION OUTPUT ;
    USE SIGNAL ;
    PORT
      LAYER M4 ;
        RECT  104.004 33.072 104.088 33.096 ;
    END
  END b[553]
  PIN b[554]
    DIRECTION OUTPUT ;
    USE SIGNAL ;
    PORT
      LAYER M4 ;
        RECT  104.004 33.168 104.088 33.192 ;
    END
  END b[554]
  PIN b[555]
    DIRECTION OUTPUT ;
    USE SIGNAL ;
    PORT
      LAYER M4 ;
        RECT  104.004 33.264 104.088 33.288 ;
    END
  END b[555]
  PIN b[556]
    DIRECTION OUTPUT ;
    USE SIGNAL ;
    PORT
      LAYER M4 ;
        RECT  104.004 33.36 104.088 33.384 ;
    END
  END b[556]
  PIN b[557]
    DIRECTION OUTPUT ;
    USE SIGNAL ;
    PORT
      LAYER M4 ;
        RECT  104.004 33.456 104.088 33.48 ;
    END
  END b[557]
  PIN b[558]
    DIRECTION OUTPUT ;
    USE SIGNAL ;
    PORT
      LAYER M4 ;
        RECT  104.004 33.552 104.088 33.576 ;
    END
  END b[558]
  PIN b[559]
    DIRECTION OUTPUT ;
    USE SIGNAL ;
    PORT
      LAYER M4 ;
        RECT  104.004 33.648 104.088 33.672 ;
    END
  END b[559]
  PIN b[55]
    DIRECTION OUTPUT ;
    USE SIGNAL ;
    PORT
      LAYER M4 ;
        RECT  104.004 56.688 104.088 56.712 ;
    END
  END b[55]
  PIN b[560]
    DIRECTION OUTPUT ;
    USE SIGNAL ;
    PORT
      LAYER M4 ;
        RECT  104.004 33.744 104.088 33.768 ;
    END
  END b[560]
  PIN b[561]
    DIRECTION OUTPUT ;
    USE SIGNAL ;
    PORT
      LAYER M4 ;
        RECT  104.004 33.84 104.088 33.864 ;
    END
  END b[561]
  PIN b[562]
    DIRECTION OUTPUT ;
    USE SIGNAL ;
    PORT
      LAYER M4 ;
        RECT  104.004 33.936 104.088 33.96 ;
    END
  END b[562]
  PIN b[563]
    DIRECTION OUTPUT ;
    USE SIGNAL ;
    PORT
      LAYER M4 ;
        RECT  104.004 34.032 104.088 34.056 ;
    END
  END b[563]
  PIN b[564]
    DIRECTION OUTPUT ;
    USE SIGNAL ;
    PORT
      LAYER M4 ;
        RECT  104.004 34.128 104.088 34.152 ;
    END
  END b[564]
  PIN b[565]
    DIRECTION OUTPUT ;
    USE SIGNAL ;
    PORT
      LAYER M4 ;
        RECT  104.004 34.224 104.088 34.248 ;
    END
  END b[565]
  PIN b[566]
    DIRECTION OUTPUT ;
    USE SIGNAL ;
    PORT
      LAYER M4 ;
        RECT  104.004 34.32 104.088 34.344 ;
    END
  END b[566]
  PIN b[567]
    DIRECTION OUTPUT ;
    USE SIGNAL ;
    PORT
      LAYER M4 ;
        RECT  104.004 34.416 104.088 34.44 ;
    END
  END b[567]
  PIN b[568]
    DIRECTION OUTPUT ;
    USE SIGNAL ;
    PORT
      LAYER M4 ;
        RECT  104.004 34.512 104.088 34.536 ;
    END
  END b[568]
  PIN b[569]
    DIRECTION OUTPUT ;
    USE SIGNAL ;
    PORT
      LAYER M4 ;
        RECT  104.004 34.608 104.088 34.632 ;
    END
  END b[569]
  PIN b[56]
    DIRECTION OUTPUT ;
    USE SIGNAL ;
    PORT
      LAYER M4 ;
        RECT  104.004 56.784 104.088 56.808 ;
    END
  END b[56]
  PIN b[570]
    DIRECTION OUTPUT ;
    USE SIGNAL ;
    PORT
      LAYER M4 ;
        RECT  104.004 34.704 104.088 34.728 ;
    END
  END b[570]
  PIN b[571]
    DIRECTION OUTPUT ;
    USE SIGNAL ;
    PORT
      LAYER M4 ;
        RECT  104.004 34.8 104.088 34.824 ;
    END
  END b[571]
  PIN b[572]
    DIRECTION OUTPUT ;
    USE SIGNAL ;
    PORT
      LAYER M4 ;
        RECT  104.004 34.896 104.088 34.92 ;
    END
  END b[572]
  PIN b[573]
    DIRECTION OUTPUT ;
    USE SIGNAL ;
    PORT
      LAYER M4 ;
        RECT  104.004 34.992 104.088 35.016 ;
    END
  END b[573]
  PIN b[574]
    DIRECTION OUTPUT ;
    USE SIGNAL ;
    PORT
      LAYER M4 ;
        RECT  104.004 35.088 104.088 35.112 ;
    END
  END b[574]
  PIN b[575]
    DIRECTION OUTPUT ;
    USE SIGNAL ;
    PORT
      LAYER M4 ;
        RECT  104.004 35.184 104.088 35.208 ;
    END
  END b[575]
  PIN b[576]
    DIRECTION OUTPUT ;
    USE SIGNAL ;
    PORT
      LAYER M4 ;
        RECT  104.004 77.52 104.088 77.544 ;
    END
  END b[576]
  PIN b[577]
    DIRECTION OUTPUT ;
    USE SIGNAL ;
    PORT
      LAYER M4 ;
        RECT  104.004 77.616 104.088 77.64 ;
    END
  END b[577]
  PIN b[578]
    DIRECTION OUTPUT ;
    USE SIGNAL ;
    PORT
      LAYER M4 ;
        RECT  104.004 77.712 104.088 77.736 ;
    END
  END b[578]
  PIN b[579]
    DIRECTION OUTPUT ;
    USE SIGNAL ;
    PORT
      LAYER M4 ;
        RECT  104.004 77.808 104.088 77.832 ;
    END
  END b[579]
  PIN b[57]
    DIRECTION OUTPUT ;
    USE SIGNAL ;
    PORT
      LAYER M4 ;
        RECT  104.004 56.88 104.088 56.904 ;
    END
  END b[57]
  PIN b[580]
    DIRECTION OUTPUT ;
    USE SIGNAL ;
    PORT
      LAYER M4 ;
        RECT  104.004 77.904 104.088 77.928 ;
    END
  END b[580]
  PIN b[581]
    DIRECTION OUTPUT ;
    USE SIGNAL ;
    PORT
      LAYER M4 ;
        RECT  104.004 78 104.088 78.024 ;
    END
  END b[581]
  PIN b[582]
    DIRECTION OUTPUT ;
    USE SIGNAL ;
    PORT
      LAYER M4 ;
        RECT  104.004 78.096 104.088 78.12 ;
    END
  END b[582]
  PIN b[583]
    DIRECTION OUTPUT ;
    USE SIGNAL ;
    PORT
      LAYER M4 ;
        RECT  104.004 78.192 104.088 78.216 ;
    END
  END b[583]
  PIN b[584]
    DIRECTION OUTPUT ;
    USE SIGNAL ;
    PORT
      LAYER M4 ;
        RECT  104.004 78.288 104.088 78.312 ;
    END
  END b[584]
  PIN b[585]
    DIRECTION OUTPUT ;
    USE SIGNAL ;
    PORT
      LAYER M4 ;
        RECT  104.004 78.384 104.088 78.408 ;
    END
  END b[585]
  PIN b[586]
    DIRECTION OUTPUT ;
    USE SIGNAL ;
    PORT
      LAYER M4 ;
        RECT  104.004 78.48 104.088 78.504 ;
    END
  END b[586]
  PIN b[587]
    DIRECTION OUTPUT ;
    USE SIGNAL ;
    PORT
      LAYER M4 ;
        RECT  104.004 78.576 104.088 78.6 ;
    END
  END b[587]
  PIN b[588]
    DIRECTION OUTPUT ;
    USE SIGNAL ;
    PORT
      LAYER M4 ;
        RECT  104.004 78.672 104.088 78.696 ;
    END
  END b[588]
  PIN b[589]
    DIRECTION OUTPUT ;
    USE SIGNAL ;
    PORT
      LAYER M4 ;
        RECT  104.004 78.768 104.088 78.792 ;
    END
  END b[589]
  PIN b[58]
    DIRECTION OUTPUT ;
    USE SIGNAL ;
    PORT
      LAYER M4 ;
        RECT  104.004 56.976 104.088 57 ;
    END
  END b[58]
  PIN b[590]
    DIRECTION OUTPUT ;
    USE SIGNAL ;
    PORT
      LAYER M4 ;
        RECT  104.004 78.864 104.088 78.888 ;
    END
  END b[590]
  PIN b[591]
    DIRECTION OUTPUT ;
    USE SIGNAL ;
    PORT
      LAYER M4 ;
        RECT  104.004 78.96 104.088 78.984 ;
    END
  END b[591]
  PIN b[592]
    DIRECTION OUTPUT ;
    USE SIGNAL ;
    PORT
      LAYER M4 ;
        RECT  104.004 79.056 104.088 79.08 ;
    END
  END b[592]
  PIN b[593]
    DIRECTION OUTPUT ;
    USE SIGNAL ;
    PORT
      LAYER M4 ;
        RECT  104.004 79.152 104.088 79.176 ;
    END
  END b[593]
  PIN b[594]
    DIRECTION OUTPUT ;
    USE SIGNAL ;
    PORT
      LAYER M4 ;
        RECT  104.004 79.248 104.088 79.272 ;
    END
  END b[594]
  PIN b[595]
    DIRECTION OUTPUT ;
    USE SIGNAL ;
    PORT
      LAYER M4 ;
        RECT  104.004 79.344 104.088 79.368 ;
    END
  END b[595]
  PIN b[596]
    DIRECTION OUTPUT ;
    USE SIGNAL ;
    PORT
      LAYER M4 ;
        RECT  104.004 79.44 104.088 79.464 ;
    END
  END b[596]
  PIN b[597]
    DIRECTION OUTPUT ;
    USE SIGNAL ;
    PORT
      LAYER M4 ;
        RECT  104.004 79.536 104.088 79.56 ;
    END
  END b[597]
  PIN b[598]
    DIRECTION OUTPUT ;
    USE SIGNAL ;
    PORT
      LAYER M4 ;
        RECT  104.004 79.632 104.088 79.656 ;
    END
  END b[598]
  PIN b[599]
    DIRECTION OUTPUT ;
    USE SIGNAL ;
    PORT
      LAYER M4 ;
        RECT  104.004 79.728 104.088 79.752 ;
    END
  END b[599]
  PIN b[59]
    DIRECTION OUTPUT ;
    USE SIGNAL ;
    PORT
      LAYER M4 ;
        RECT  104.004 57.072 104.088 57.096 ;
    END
  END b[59]
  PIN b[5]
    DIRECTION OUTPUT ;
    USE SIGNAL ;
    PORT
      LAYER M4 ;
        RECT  104.004 42.672 104.088 42.696 ;
    END
  END b[5]
  PIN b[60]
    DIRECTION OUTPUT ;
    USE SIGNAL ;
    PORT
      LAYER M4 ;
        RECT  104.004 57.168 104.088 57.192 ;
    END
  END b[60]
  PIN b[61]
    DIRECTION OUTPUT ;
    USE SIGNAL ;
    PORT
      LAYER M4 ;
        RECT  104.004 57.264 104.088 57.288 ;
    END
  END b[61]
  PIN b[62]
    DIRECTION OUTPUT ;
    USE SIGNAL ;
    PORT
      LAYER M4 ;
        RECT  104.004 57.36 104.088 57.384 ;
    END
  END b[62]
  PIN b[63]
    DIRECTION OUTPUT ;
    USE SIGNAL ;
    PORT
      LAYER M4 ;
        RECT  104.004 57.456 104.088 57.48 ;
    END
  END b[63]
  PIN b[64]
    DIRECTION OUTPUT ;
    USE SIGNAL ;
    PORT
      LAYER M4 ;
        RECT  104.004 45.264 104.088 45.288 ;
    END
  END b[64]
  PIN b[65]
    DIRECTION OUTPUT ;
    USE SIGNAL ;
    PORT
      LAYER M4 ;
        RECT  104.004 45.36 104.088 45.384 ;
    END
  END b[65]
  PIN b[66]
    DIRECTION OUTPUT ;
    USE SIGNAL ;
    PORT
      LAYER M4 ;
        RECT  104.004 45.456 104.088 45.48 ;
    END
  END b[66]
  PIN b[67]
    DIRECTION OUTPUT ;
    USE SIGNAL ;
    PORT
      LAYER M4 ;
        RECT  104.004 45.552 104.088 45.576 ;
    END
  END b[67]
  PIN b[68]
    DIRECTION OUTPUT ;
    USE SIGNAL ;
    PORT
      LAYER M4 ;
        RECT  104.004 45.648 104.088 45.672 ;
    END
  END b[68]
  PIN b[69]
    DIRECTION OUTPUT ;
    USE SIGNAL ;
    PORT
      LAYER M4 ;
        RECT  104.004 45.744 104.088 45.768 ;
    END
  END b[69]
  PIN b[6]
    DIRECTION OUTPUT ;
    USE SIGNAL ;
    PORT
      LAYER M4 ;
        RECT  104.004 42.768 104.088 42.792 ;
    END
  END b[6]
  PIN b[70]
    DIRECTION OUTPUT ;
    USE SIGNAL ;
    PORT
      LAYER M4 ;
        RECT  104.004 45.84 104.088 45.864 ;
    END
  END b[70]
  PIN b[71]
    DIRECTION OUTPUT ;
    USE SIGNAL ;
    PORT
      LAYER M4 ;
        RECT  104.004 45.936 104.088 45.96 ;
    END
  END b[71]
  PIN b[72]
    DIRECTION OUTPUT ;
    USE SIGNAL ;
    PORT
      LAYER M4 ;
        RECT  104.004 46.032 104.088 46.056 ;
    END
  END b[72]
  PIN b[73]
    DIRECTION OUTPUT ;
    USE SIGNAL ;
    PORT
      LAYER M4 ;
        RECT  104.004 46.128 104.088 46.152 ;
    END
  END b[73]
  PIN b[74]
    DIRECTION OUTPUT ;
    USE SIGNAL ;
    PORT
      LAYER M4 ;
        RECT  104.004 46.224 104.088 46.248 ;
    END
  END b[74]
  PIN b[75]
    DIRECTION OUTPUT ;
    USE SIGNAL ;
    PORT
      LAYER M4 ;
        RECT  104.004 46.32 104.088 46.344 ;
    END
  END b[75]
  PIN b[76]
    DIRECTION OUTPUT ;
    USE SIGNAL ;
    PORT
      LAYER M4 ;
        RECT  104.004 46.416 104.088 46.44 ;
    END
  END b[76]
  PIN b[77]
    DIRECTION OUTPUT ;
    USE SIGNAL ;
    PORT
      LAYER M4 ;
        RECT  104.004 46.512 104.088 46.536 ;
    END
  END b[77]
  PIN b[78]
    DIRECTION OUTPUT ;
    USE SIGNAL ;
    PORT
      LAYER M4 ;
        RECT  104.004 46.608 104.088 46.632 ;
    END
  END b[78]
  PIN b[79]
    DIRECTION OUTPUT ;
    USE SIGNAL ;
    PORT
      LAYER M4 ;
        RECT  104.004 46.704 104.088 46.728 ;
    END
  END b[79]
  PIN b[7]
    DIRECTION OUTPUT ;
    USE SIGNAL ;
    PORT
      LAYER M4 ;
        RECT  104.004 42.864 104.088 42.888 ;
    END
  END b[7]
  PIN b[80]
    DIRECTION OUTPUT ;
    USE SIGNAL ;
    PORT
      LAYER M4 ;
        RECT  104.004 46.8 104.088 46.824 ;
    END
  END b[80]
  PIN b[81]
    DIRECTION OUTPUT ;
    USE SIGNAL ;
    PORT
      LAYER M4 ;
        RECT  104.004 46.896 104.088 46.92 ;
    END
  END b[81]
  PIN b[82]
    DIRECTION OUTPUT ;
    USE SIGNAL ;
    PORT
      LAYER M4 ;
        RECT  104.004 46.992 104.088 47.016 ;
    END
  END b[82]
  PIN b[83]
    DIRECTION OUTPUT ;
    USE SIGNAL ;
    PORT
      LAYER M4 ;
        RECT  104.004 47.088 104.088 47.112 ;
    END
  END b[83]
  PIN b[84]
    DIRECTION OUTPUT ;
    USE SIGNAL ;
    PORT
      LAYER M4 ;
        RECT  104.004 47.184 104.088 47.208 ;
    END
  END b[84]
  PIN b[85]
    DIRECTION OUTPUT ;
    USE SIGNAL ;
    PORT
      LAYER M4 ;
        RECT  104.004 47.28 104.088 47.304 ;
    END
  END b[85]
  PIN b[86]
    DIRECTION OUTPUT ;
    USE SIGNAL ;
    PORT
      LAYER M4 ;
        RECT  104.004 47.376 104.088 47.4 ;
    END
  END b[86]
  PIN b[87]
    DIRECTION OUTPUT ;
    USE SIGNAL ;
    PORT
      LAYER M4 ;
        RECT  104.004 47.472 104.088 47.496 ;
    END
  END b[87]
  PIN b[88]
    DIRECTION OUTPUT ;
    USE SIGNAL ;
    PORT
      LAYER M4 ;
        RECT  104.004 47.568 104.088 47.592 ;
    END
  END b[88]
  PIN b[89]
    DIRECTION OUTPUT ;
    USE SIGNAL ;
    PORT
      LAYER M4 ;
        RECT  104.004 47.664 104.088 47.688 ;
    END
  END b[89]
  PIN b[8]
    DIRECTION OUTPUT ;
    USE SIGNAL ;
    PORT
      LAYER M4 ;
        RECT  104.004 42.96 104.088 42.984 ;
    END
  END b[8]
  PIN b[90]
    DIRECTION OUTPUT ;
    USE SIGNAL ;
    PORT
      LAYER M4 ;
        RECT  104.004 47.76 104.088 47.784 ;
    END
  END b[90]
  PIN b[91]
    DIRECTION OUTPUT ;
    USE SIGNAL ;
    PORT
      LAYER M4 ;
        RECT  104.004 47.856 104.088 47.88 ;
    END
  END b[91]
  PIN b[92]
    DIRECTION OUTPUT ;
    USE SIGNAL ;
    PORT
      LAYER M4 ;
        RECT  104.004 47.952 104.088 47.976 ;
    END
  END b[92]
  PIN b[93]
    DIRECTION OUTPUT ;
    USE SIGNAL ;
    PORT
      LAYER M4 ;
        RECT  104.004 48.048 104.088 48.072 ;
    END
  END b[93]
  PIN b[94]
    DIRECTION OUTPUT ;
    USE SIGNAL ;
    PORT
      LAYER M4 ;
        RECT  104.004 48.144 104.088 48.168 ;
    END
  END b[94]
  PIN b[95]
    DIRECTION OUTPUT ;
    USE SIGNAL ;
    PORT
      LAYER M4 ;
        RECT  104.004 48.24 104.088 48.264 ;
    END
  END b[95]
  PIN b[96]
    DIRECTION OUTPUT ;
    USE SIGNAL ;
    PORT
      LAYER M4 ;
        RECT  104.004 48.336 104.088 48.36 ;
    END
  END b[96]
  PIN b[97]
    DIRECTION OUTPUT ;
    USE SIGNAL ;
    PORT
      LAYER M4 ;
        RECT  104.004 48.432 104.088 48.456 ;
    END
  END b[97]
  PIN b[98]
    DIRECTION OUTPUT ;
    USE SIGNAL ;
    PORT
      LAYER M4 ;
        RECT  104.004 48.528 104.088 48.552 ;
    END
  END b[98]
  PIN b[99]
    DIRECTION OUTPUT ;
    USE SIGNAL ;
    PORT
      LAYER M4 ;
        RECT  104.004 48.624 104.088 48.648 ;
    END
  END b[99]
  PIN b[9]
    DIRECTION OUTPUT ;
    USE SIGNAL ;
    PORT
      LAYER M4 ;
        RECT  104.004 43.056 104.088 43.08 ;
    END
  END b[9]
  PIN ck
    DIRECTION INPUT ;
    USE SIGNAL ;
    PORT
      LAYER M4 ;
        RECT  0 55.248 0.084 55.272 ;
    END
  END ck
  PIN ck_o
    DIRECTION OUTPUT ;
    USE SIGNAL ;
    PORT
      LAYER M4 ;
        RECT  0 55.344 0.084 55.368 ;
    END
  END ck_o
  PIN eb
    DIRECTION OUTPUT ;
    USE SIGNAL ;
    PORT
      LAYER M4 ;
        RECT  104.004 79.824 104.088 79.848 ;
    END
  END eb
  PIN en
    DIRECTION INPUT ;
    USE SIGNAL ;
    PORT
      LAYER M4 ;
        RECT  0 55.44 0.084 55.464 ;
    END
  END en
  PIN VDD
    DIRECTION INOUT ;
    USE POWER ;
    PORT
      LAYER M5 ;
        RECT  99.792 2.151 99.912 103.433 ;
        RECT  97.092 2.151 97.212 103.433 ;
        RECT  94.392 2.151 94.512 103.433 ;
        RECT  91.692 2.151 91.812 103.433 ;
        RECT  88.992 2.151 89.112 103.433 ;
        RECT  86.292 2.151 86.412 103.433 ;
        RECT  83.592 2.151 83.712 103.433 ;
        RECT  80.892 2.151 81.012 103.433 ;
        RECT  78.192 2.151 78.312 103.433 ;
        RECT  75.492 2.151 75.612 103.433 ;
        RECT  72.792 2.151 72.912 103.433 ;
        RECT  70.092 2.151 70.212 103.433 ;
        RECT  67.392 2.151 67.512 103.433 ;
        RECT  64.692 2.151 64.812 103.433 ;
        RECT  61.992 2.151 62.112 103.433 ;
        RECT  59.292 2.151 59.412 103.433 ;
        RECT  56.592 2.151 56.712 103.433 ;
        RECT  53.892 2.151 54.012 103.433 ;
        RECT  51.192 2.151 51.312 103.433 ;
        RECT  48.492 2.151 48.612 103.433 ;
        RECT  45.792 2.151 45.912 103.433 ;
        RECT  43.092 2.151 43.212 103.433 ;
        RECT  40.392 2.151 40.512 103.433 ;
        RECT  37.692 2.151 37.812 103.433 ;
        RECT  34.992 2.151 35.112 103.433 ;
        RECT  32.292 2.151 32.412 103.433 ;
        RECT  29.592 2.151 29.712 103.433 ;
        RECT  26.892 2.151 27.012 103.433 ;
        RECT  24.192 2.151 24.312 103.433 ;
        RECT  21.492 2.151 21.612 103.433 ;
        RECT  18.792 2.151 18.912 103.433 ;
        RECT  16.092 2.151 16.212 103.433 ;
        RECT  13.392 2.151 13.512 103.433 ;
        RECT  10.692 2.151 10.812 103.433 ;
        RECT  7.992 2.151 8.112 103.433 ;
        RECT  5.292 2.151 5.412 103.433 ;
        RECT  2.592 2.151 2.712 103.433 ;
    END
  END VDD
  PIN VSS
    DIRECTION INOUT ;
    USE GROUND ;
    PORT
      LAYER M5 ;
        RECT  99.6 2.137 99.72 103.419 ;
        RECT  96.9 2.137 97.02 103.419 ;
        RECT  94.2 2.137 94.32 103.419 ;
        RECT  91.5 2.137 91.62 103.419 ;
        RECT  88.8 2.137 88.92 103.419 ;
        RECT  86.1 2.137 86.22 103.419 ;
        RECT  83.4 2.137 83.52 103.419 ;
        RECT  80.7 2.137 80.82 103.419 ;
        RECT  78 2.137 78.12 103.419 ;
        RECT  75.3 2.137 75.42 103.419 ;
        RECT  72.6 2.137 72.72 103.419 ;
        RECT  69.9 2.137 70.02 103.419 ;
        RECT  67.2 2.137 67.32 103.419 ;
        RECT  64.5 2.137 64.62 103.419 ;
        RECT  61.8 2.137 61.92 103.419 ;
        RECT  59.1 2.137 59.22 103.419 ;
        RECT  56.4 2.137 56.52 103.419 ;
        RECT  53.7 2.137 53.82 103.419 ;
        RECT  51 2.137 51.12 103.419 ;
        RECT  48.3 2.137 48.42 103.419 ;
        RECT  45.6 2.137 45.72 103.419 ;
        RECT  42.9 2.137 43.02 103.419 ;
        RECT  40.2 2.137 40.32 103.419 ;
        RECT  37.5 2.137 37.62 103.419 ;
        RECT  34.8 2.137 34.92 103.419 ;
        RECT  32.1 2.137 32.22 103.419 ;
        RECT  29.4 2.137 29.52 103.419 ;
        RECT  26.7 2.137 26.82 103.419 ;
        RECT  24 2.137 24.12 103.419 ;
        RECT  21.3 2.137 21.42 103.419 ;
        RECT  18.6 2.137 18.72 103.419 ;
        RECT  15.9 2.137 16.02 103.419 ;
        RECT  13.2 2.137 13.32 103.419 ;
        RECT  10.5 2.137 10.62 103.419 ;
        RECT  7.8 2.137 7.92 103.419 ;
        RECT  5.1 2.137 5.22 103.419 ;
        RECT  2.4 2.137 2.52 103.419 ;
    END
  END VSS
  # OT_OBS_CLOSED layer=M5 d_um=1.536 added=48
  OBS
    LAYER RVTN ;
     RECT  2.16 2.16 101.898 2.295 ;
     RECT  2.16 2.565 101.898 2.835 ;
     RECT  2.16 3.105 101.898 3.375 ;
     RECT  2.16 3.645 101.898 3.915 ;
     RECT  2.16 4.185 101.898 4.455 ;
     RECT  2.16 4.725 101.898 4.995 ;
     RECT  2.16 5.265 101.898 5.535 ;
     RECT  2.16 5.805 101.898 6.075 ;
     RECT  2.16 6.345 101.898 6.615 ;
     RECT  2.16 6.885 101.898 7.155 ;
     RECT  2.16 7.425 101.898 7.695 ;
     RECT  2.16 7.965 101.898 8.235 ;
     RECT  2.16 8.505 101.898 8.775 ;
     RECT  2.16 9.045 101.898 9.315 ;
     RECT  2.16 9.585 101.898 9.855 ;
     RECT  2.16 10.125 101.898 10.395 ;
     RECT  2.16 10.665 101.898 10.935 ;
     RECT  2.16 11.205 101.898 11.475 ;
     RECT  2.16 11.745 101.898 12.015 ;
     RECT  2.16 12.285 101.898 12.555 ;
     RECT  2.16 12.825 101.898 13.095 ;
     RECT  2.16 13.365 101.898 13.635 ;
     RECT  2.16 13.905 101.898 14.175 ;
     RECT  2.16 14.445 101.898 14.715 ;
     RECT  2.16 14.985 101.898 15.255 ;
     RECT  2.16 15.525 101.898 15.795 ;
     RECT  2.16 16.065 101.898 16.335 ;
     RECT  2.16 16.605 101.898 16.875 ;
     RECT  2.16 17.145 101.898 17.415 ;
     RECT  2.16 17.685 101.898 17.955 ;
     RECT  2.16 18.225 101.898 18.495 ;
     RECT  2.16 18.765 101.898 19.035 ;
     RECT  2.16 19.305 101.898 19.575 ;
     RECT  2.16 19.845 101.898 20.115 ;
     RECT  2.16 20.385 101.898 20.655 ;
     RECT  2.16 20.925 101.898 21.195 ;
     RECT  2.16 21.465 101.898 21.735 ;
     RECT  2.16 22.005 101.898 22.275 ;
     RECT  2.16 22.545 101.898 22.815 ;
     RECT  2.16 23.085 101.898 23.355 ;
     RECT  2.16 23.625 101.898 23.895 ;
     RECT  2.16 24.165 101.898 24.435 ;
     RECT  2.16 24.705 101.898 24.975 ;
     RECT  2.16 25.245 101.898 25.515 ;
     RECT  2.16 25.785 101.898 26.055 ;
     RECT  2.16 26.325 101.898 26.595 ;
     RECT  2.16 26.865 101.898 27.135 ;
     RECT  2.16 27.405 101.898 27.675 ;
     RECT  2.16 27.945 101.898 28.215 ;
     RECT  2.16 28.485 101.898 28.755 ;
     RECT  2.16 29.025 101.898 29.295 ;
     RECT  2.16 29.565 101.898 29.835 ;
     RECT  2.16 30.105 101.898 30.375 ;
     RECT  2.16 30.645 101.898 30.915 ;
     RECT  2.16 31.185 101.898 31.455 ;
     RECT  2.16 31.725 101.898 31.995 ;
     RECT  2.16 32.265 101.898 32.535 ;
     RECT  2.16 32.805 101.898 33.075 ;
     RECT  2.16 33.345 101.898 33.615 ;
     RECT  2.16 33.885 101.898 34.155 ;
     RECT  2.16 34.425 101.898 34.695 ;
     RECT  2.16 34.965 101.898 35.235 ;
     RECT  2.16 35.505 101.898 35.775 ;
     RECT  2.16 36.045 101.898 36.315 ;
     RECT  2.16 36.585 101.898 36.855 ;
     RECT  2.16 37.125 101.898 37.395 ;
     RECT  2.16 37.665 101.898 37.935 ;
     RECT  2.16 38.205 101.898 38.475 ;
     RECT  2.16 38.745 101.898 39.015 ;
     RECT  2.16 39.285 101.898 39.555 ;
     RECT  2.16 39.825 101.898 40.095 ;
     RECT  2.16 40.365 101.898 40.635 ;
     RECT  2.16 40.905 101.898 41.175 ;
     RECT  2.16 41.445 101.898 41.715 ;
     RECT  2.16 41.985 101.898 42.255 ;
     RECT  2.16 42.525 101.898 42.795 ;
     RECT  2.16 43.065 101.898 43.335 ;
     RECT  2.16 43.605 101.898 43.875 ;
     RECT  2.16 44.145 101.898 44.415 ;
     RECT  2.16 44.685 101.898 44.955 ;
     RECT  2.16 45.225 101.898 45.495 ;
     RECT  2.16 45.765 101.898 46.035 ;
     RECT  2.16 46.305 101.898 46.575 ;
     RECT  2.16 46.845 101.898 47.115 ;
     RECT  2.16 47.385 101.898 47.655 ;
     RECT  2.16 47.925 101.898 48.195 ;
     RECT  2.16 48.465 101.898 48.735 ;
     RECT  2.16 49.005 101.898 49.275 ;
     RECT  2.16 49.545 101.898 49.815 ;
     RECT  2.16 50.085 101.898 50.355 ;
     RECT  2.16 50.625 101.898 50.895 ;
     RECT  2.16 51.165 101.898 51.435 ;
     RECT  2.16 51.705 101.898 51.975 ;
     RECT  2.16 52.245 101.898 52.515 ;
     RECT  2.16 52.785 101.898 53.055 ;
     RECT  2.16 53.325 101.898 53.595 ;
     RECT  2.16 53.865 101.898 54.135 ;
     RECT  2.16 54.405 101.898 54.675 ;
     RECT  2.16 54.945 101.898 55.215 ;
     RECT  2.16 55.485 101.898 55.755 ;
     RECT  2.16 56.025 101.898 56.295 ;
     RECT  2.16 56.565 101.898 56.835 ;
     RECT  2.16 57.105 101.898 57.375 ;
     RECT  2.16 57.645 101.898 57.915 ;
     RECT  2.16 58.185 101.898 58.455 ;
     RECT  2.16 58.725 101.898 58.995 ;
     RECT  2.16 59.265 101.898 59.535 ;
     RECT  2.16 59.805 101.898 60.075 ;
     RECT  2.16 60.345 101.898 60.615 ;
     RECT  2.16 60.885 101.898 61.155 ;
     RECT  2.16 61.425 101.898 61.695 ;
     RECT  2.16 61.965 101.898 62.235 ;
     RECT  2.16 62.505 101.898 62.775 ;
     RECT  2.16 63.045 101.898 63.315 ;
     RECT  2.16 63.585 101.898 63.855 ;
     RECT  2.16 64.125 101.898 64.395 ;
     RECT  2.16 64.665 101.898 64.935 ;
     RECT  2.16 65.205 101.898 65.475 ;
     RECT  2.16 65.745 101.898 66.015 ;
     RECT  2.16 66.285 101.898 66.555 ;
     RECT  2.16 66.825 101.898 67.095 ;
     RECT  2.16 67.365 101.898 67.635 ;
     RECT  2.16 67.905 101.898 68.175 ;
     RECT  2.16 68.445 101.898 68.715 ;
     RECT  2.16 68.985 101.898 69.255 ;
     RECT  2.16 69.525 101.898 69.795 ;
     RECT  2.16 70.065 101.898 70.335 ;
     RECT  2.16 70.605 101.898 70.875 ;
     RECT  2.16 71.145 101.898 71.415 ;
     RECT  2.16 71.685 101.898 71.955 ;
     RECT  2.16 72.225 101.898 72.495 ;
     RECT  2.16 72.765 101.898 73.035 ;
     RECT  2.16 73.305 101.898 73.575 ;
     RECT  2.16 73.845 101.898 74.115 ;
     RECT  2.16 74.385 101.898 74.655 ;
     RECT  2.16 74.925 101.898 75.195 ;
     RECT  2.16 75.465 101.898 75.735 ;
     RECT  2.16 76.005 101.898 76.275 ;
     RECT  2.16 76.545 101.898 76.815 ;
     RECT  2.16 77.085 101.898 77.355 ;
     RECT  2.16 77.625 101.898 77.895 ;
     RECT  2.16 78.165 101.898 78.435 ;
     RECT  2.16 78.705 101.898 78.975 ;
     RECT  2.16 79.245 101.898 79.515 ;
     RECT  2.16 79.785 101.898 80.055 ;
     RECT  2.16 80.325 101.898 80.595 ;
     RECT  2.16 80.865 101.898 81.135 ;
     RECT  2.16 81.405 101.898 81.675 ;
     RECT  2.16 81.945 101.898 82.215 ;
     RECT  2.16 82.485 101.898 82.755 ;
     RECT  2.16 83.025 101.898 83.295 ;
     RECT  2.16 83.565 101.898 83.835 ;
     RECT  2.16 84.105 101.898 84.375 ;
     RECT  2.16 84.645 101.898 84.915 ;
     RECT  2.16 85.185 101.898 85.455 ;
     RECT  2.16 85.725 101.898 85.995 ;
     RECT  2.16 86.265 101.898 86.535 ;
     RECT  2.16 86.805 101.898 87.075 ;
     RECT  2.16 87.345 101.898 87.615 ;
     RECT  2.16 87.885 101.898 88.155 ;
     RECT  2.16 88.425 101.898 88.695 ;
     RECT  2.16 88.965 101.898 89.235 ;
     RECT  2.16 89.505 101.898 89.775 ;
     RECT  2.16 90.045 101.898 90.315 ;
     RECT  2.16 90.585 101.898 90.855 ;
     RECT  2.16 91.125 101.898 91.395 ;
     RECT  2.16 91.665 101.898 91.935 ;
     RECT  2.16 92.205 101.898 92.475 ;
     RECT  2.16 92.745 101.898 93.015 ;
     RECT  2.16 93.285 101.898 93.555 ;
     RECT  2.16 93.825 101.898 94.095 ;
     RECT  2.16 94.365 101.898 94.635 ;
     RECT  2.16 94.905 101.898 95.175 ;
     RECT  2.16 95.445 101.898 95.715 ;
     RECT  2.16 95.985 101.898 96.255 ;
     RECT  2.16 96.525 101.898 96.795 ;
     RECT  2.16 97.065 101.898 97.335 ;
     RECT  2.16 97.605 101.898 97.875 ;
     RECT  2.16 98.145 101.898 98.415 ;
     RECT  2.16 98.685 101.898 98.955 ;
     RECT  2.16 99.225 101.898 99.495 ;
     RECT  2.16 99.765 101.898 100.035 ;
     RECT  2.16 100.305 101.898 100.575 ;
     RECT  2.16 100.845 101.898 101.115 ;
     RECT  2.16 101.385 101.898 101.655 ;
     RECT  2.16 101.925 101.898 102.195 ;
     RECT  2.16 102.465 101.898 102.735 ;
     RECT  2.16 103.005 101.898 103.275 ;
    LAYER RVTP ;
     RECT  2.16 2.295 101.898 2.565 ;
     RECT  2.16 2.835 101.898 3.105 ;
     RECT  2.16 3.375 101.898 3.645 ;
     RECT  2.16 3.915 101.898 4.185 ;
     RECT  2.16 4.455 101.898 4.725 ;
     RECT  2.16 4.995 101.898 5.265 ;
     RECT  2.16 5.535 101.898 5.805 ;
     RECT  2.16 6.075 101.898 6.345 ;
     RECT  2.16 6.615 101.898 6.885 ;
     RECT  2.16 7.155 101.898 7.425 ;
     RECT  2.16 7.695 101.898 7.965 ;
     RECT  2.16 8.235 101.898 8.505 ;
     RECT  2.16 8.775 101.898 9.045 ;
     RECT  2.16 9.315 101.898 9.585 ;
     RECT  2.16 9.855 101.898 10.125 ;
     RECT  2.16 10.395 101.898 10.665 ;
     RECT  2.16 10.935 101.898 11.205 ;
     RECT  2.16 11.475 101.898 11.745 ;
     RECT  2.16 12.015 101.898 12.285 ;
     RECT  2.16 12.555 101.898 12.825 ;
     RECT  2.16 13.095 101.898 13.365 ;
     RECT  2.16 13.635 101.898 13.905 ;
     RECT  2.16 14.175 101.898 14.445 ;
     RECT  2.16 14.715 101.898 14.985 ;
     RECT  2.16 15.255 101.898 15.525 ;
     RECT  2.16 15.795 101.898 16.065 ;
     RECT  2.16 16.335 101.898 16.605 ;
     RECT  2.16 16.875 101.898 17.145 ;
     RECT  2.16 17.415 101.898 17.685 ;
     RECT  2.16 17.955 101.898 18.225 ;
     RECT  2.16 18.495 101.898 18.765 ;
     RECT  2.16 19.035 101.898 19.305 ;
     RECT  2.16 19.575 101.898 19.845 ;
     RECT  2.16 20.115 101.898 20.385 ;
     RECT  2.16 20.655 101.898 20.925 ;
     RECT  2.16 21.195 101.898 21.465 ;
     RECT  2.16 21.735 101.898 22.005 ;
     RECT  2.16 22.275 101.898 22.545 ;
     RECT  2.16 22.815 101.898 23.085 ;
     RECT  2.16 23.355 101.898 23.625 ;
     RECT  2.16 23.895 101.898 24.165 ;
     RECT  2.16 24.435 101.898 24.705 ;
     RECT  2.16 24.975 101.898 25.245 ;
     RECT  2.16 25.515 101.898 25.785 ;
     RECT  2.16 26.055 101.898 26.325 ;
     RECT  2.16 26.595 101.898 26.865 ;
     RECT  2.16 27.135 101.898 27.405 ;
     RECT  2.16 27.675 101.898 27.945 ;
     RECT  2.16 28.215 101.898 28.485 ;
     RECT  2.16 28.755 101.898 29.025 ;
     RECT  2.16 29.295 101.898 29.565 ;
     RECT  2.16 29.835 101.898 30.105 ;
     RECT  2.16 30.375 101.898 30.645 ;
     RECT  2.16 30.915 101.898 31.185 ;
     RECT  2.16 31.455 101.898 31.725 ;
     RECT  2.16 31.995 101.898 32.265 ;
     RECT  2.16 32.535 101.898 32.805 ;
     RECT  2.16 33.075 101.898 33.345 ;
     RECT  2.16 33.615 101.898 33.885 ;
     RECT  2.16 34.155 101.898 34.425 ;
     RECT  2.16 34.695 101.898 34.965 ;
     RECT  2.16 35.235 101.898 35.505 ;
     RECT  2.16 35.775 101.898 36.045 ;
     RECT  2.16 36.315 101.898 36.585 ;
     RECT  2.16 36.855 101.898 37.125 ;
     RECT  2.16 37.395 101.898 37.665 ;
     RECT  2.16 37.935 101.898 38.205 ;
     RECT  2.16 38.475 101.898 38.745 ;
     RECT  2.16 39.015 101.898 39.285 ;
     RECT  2.16 39.555 101.898 39.825 ;
     RECT  2.16 40.095 101.898 40.365 ;
     RECT  2.16 40.635 101.898 40.905 ;
     RECT  2.16 41.175 101.898 41.445 ;
     RECT  2.16 41.715 101.898 41.985 ;
     RECT  2.16 42.255 101.898 42.525 ;
     RECT  2.16 42.795 101.898 43.065 ;
     RECT  2.16 43.335 101.898 43.605 ;
     RECT  2.16 43.875 101.898 44.145 ;
     RECT  2.16 44.415 101.898 44.685 ;
     RECT  2.16 44.955 101.898 45.225 ;
     RECT  2.16 45.495 101.898 45.765 ;
     RECT  2.16 46.035 101.898 46.305 ;
     RECT  2.16 46.575 101.898 46.845 ;
     RECT  2.16 47.115 101.898 47.385 ;
     RECT  2.16 47.655 101.898 47.925 ;
     RECT  2.16 48.195 101.898 48.465 ;
     RECT  2.16 48.735 101.898 49.005 ;
     RECT  2.16 49.275 101.898 49.545 ;
     RECT  2.16 49.815 101.898 50.085 ;
     RECT  2.16 50.355 101.898 50.625 ;
     RECT  2.16 50.895 101.898 51.165 ;
     RECT  2.16 51.435 101.898 51.705 ;
     RECT  2.16 51.975 101.898 52.245 ;
     RECT  2.16 52.515 101.898 52.785 ;
     RECT  2.16 53.055 101.898 53.325 ;
     RECT  2.16 53.595 101.898 53.865 ;
     RECT  2.16 54.135 101.898 54.405 ;
     RECT  2.16 54.675 101.898 54.945 ;
     RECT  2.16 55.215 101.898 55.485 ;
     RECT  2.16 55.755 101.898 56.025 ;
     RECT  2.16 56.295 101.898 56.565 ;
     RECT  2.16 56.835 101.898 57.105 ;
     RECT  2.16 57.375 101.898 57.645 ;
     RECT  2.16 57.915 101.898 58.185 ;
     RECT  2.16 58.455 101.898 58.725 ;
     RECT  2.16 58.995 101.898 59.265 ;
     RECT  2.16 59.535 101.898 59.805 ;
     RECT  2.16 60.075 101.898 60.345 ;
     RECT  2.16 60.615 101.898 60.885 ;
     RECT  2.16 61.155 101.898 61.425 ;
     RECT  2.16 61.695 101.898 61.965 ;
     RECT  2.16 62.235 101.898 62.505 ;
     RECT  2.16 62.775 101.898 63.045 ;
     RECT  2.16 63.315 101.898 63.585 ;
     RECT  2.16 63.855 101.898 64.125 ;
     RECT  2.16 64.395 101.898 64.665 ;
     RECT  2.16 64.935 101.898 65.205 ;
     RECT  2.16 65.475 101.898 65.745 ;
     RECT  2.16 66.015 101.898 66.285 ;
     RECT  2.16 66.555 101.898 66.825 ;
     RECT  2.16 67.095 101.898 67.365 ;
     RECT  2.16 67.635 101.898 67.905 ;
     RECT  2.16 68.175 101.898 68.445 ;
     RECT  2.16 68.715 101.898 68.985 ;
     RECT  2.16 69.255 101.898 69.525 ;
     RECT  2.16 69.795 101.898 70.065 ;
     RECT  2.16 70.335 101.898 70.605 ;
     RECT  2.16 70.875 101.898 71.145 ;
     RECT  2.16 71.415 101.898 71.685 ;
     RECT  2.16 71.955 101.898 72.225 ;
     RECT  2.16 72.495 101.898 72.765 ;
     RECT  2.16 73.035 101.898 73.305 ;
     RECT  2.16 73.575 101.898 73.845 ;
     RECT  2.16 74.115 101.898 74.385 ;
     RECT  2.16 74.655 101.898 74.925 ;
     RECT  2.16 75.195 101.898 75.465 ;
     RECT  2.16 75.735 101.898 76.005 ;
     RECT  2.16 76.275 101.898 76.545 ;
     RECT  2.16 76.815 101.898 77.085 ;
     RECT  2.16 77.355 101.898 77.625 ;
     RECT  2.16 77.895 101.898 78.165 ;
     RECT  2.16 78.435 101.898 78.705 ;
     RECT  2.16 78.975 101.898 79.245 ;
     RECT  2.16 79.515 101.898 79.785 ;
     RECT  2.16 80.055 101.898 80.325 ;
     RECT  2.16 80.595 101.898 80.865 ;
     RECT  2.16 81.135 101.898 81.405 ;
     RECT  2.16 81.675 101.898 81.945 ;
     RECT  2.16 82.215 101.898 82.485 ;
     RECT  2.16 82.755 101.898 83.025 ;
     RECT  2.16 83.295 101.898 83.565 ;
     RECT  2.16 83.835 101.898 84.105 ;
     RECT  2.16 84.375 101.898 84.645 ;
     RECT  2.16 84.915 101.898 85.185 ;
     RECT  2.16 85.455 101.898 85.725 ;
     RECT  2.16 85.995 101.898 86.265 ;
     RECT  2.16 86.535 101.898 86.805 ;
     RECT  2.16 87.075 101.898 87.345 ;
     RECT  2.16 87.615 101.898 87.885 ;
     RECT  2.16 88.155 101.898 88.425 ;
     RECT  2.16 88.695 101.898 88.965 ;
     RECT  2.16 89.235 101.898 89.505 ;
     RECT  2.16 89.775 101.898 90.045 ;
     RECT  2.16 90.315 101.898 90.585 ;
     RECT  2.16 90.855 101.898 91.125 ;
     RECT  2.16 91.395 101.898 91.665 ;
     RECT  2.16 91.935 101.898 92.205 ;
     RECT  2.16 92.475 101.898 92.745 ;
     RECT  2.16 93.015 101.898 93.285 ;
     RECT  2.16 93.555 101.898 93.825 ;
     RECT  2.16 94.095 101.898 94.365 ;
     RECT  2.16 94.635 101.898 94.905 ;
     RECT  2.16 95.175 101.898 95.445 ;
     RECT  2.16 95.715 101.898 95.985 ;
     RECT  2.16 96.255 101.898 96.525 ;
     RECT  2.16 96.795 101.898 97.065 ;
     RECT  2.16 97.335 101.898 97.605 ;
     RECT  2.16 97.875 101.898 98.145 ;
     RECT  2.16 98.415 101.898 98.685 ;
     RECT  2.16 98.955 101.898 99.225 ;
     RECT  2.16 99.495 101.898 99.765 ;
     RECT  2.16 100.035 101.898 100.305 ;
     RECT  2.16 100.575 101.898 100.845 ;
     RECT  2.16 101.115 101.898 101.385 ;
     RECT  2.16 101.655 101.898 101.925 ;
     RECT  2.16 102.195 101.898 102.465 ;
     RECT  2.16 102.735 101.898 103.005 ;
     RECT  2.16 103.275 101.898 103.41 ;
    LAYER M1 ;
     RECT  2.16 2.151 101.898 103.419 ;
    LAYER M2 ;
     RECT  2.16 2.151 31.999 103.419 ;
     RECT  31.999 2.151 33.187 103.464 ;
     RECT  32.683 105.75 34.015 105.768 ;
     RECT  34.015 105.561 34.115 105.768 ;
     RECT  33.187 2.151 34.591 103.536 ;
     RECT  34.591 2.151 34.691 103.734 ;
     RECT  34.807 104.796 34.843 104.814 ;
     RECT  34.843 104.796 34.979 104.886 ;
     RECT  34.115 105.678 35.563 105.768 ;
     RECT  35.563 105.516 36.283 105.768 ;
     RECT  36.283 104.868 36.319 105.768 ;
     RECT  36.319 104.796 37.283 105.768 ;
     RECT  37.283 104.868 37.355 105.768 ;
     RECT  37.355 105.516 38.803 105.768 ;
     RECT  38.803 104.796 39.155 105.768 ;
     RECT  39.155 105.444 39.299 105.768 ;
     RECT  34.691 2.151 39.911 103.536 ;
     RECT  39.811 104.292 40.171 104.31 ;
     RECT  39.299 105.516 40.171 105.768 ;
     RECT  39.911 2.151 41.035 103.464 ;
     RECT  40.171 104.292 41.387 105.768 ;
     RECT  41.387 104.292 41.747 104.886 ;
     RECT  41.747 104.796 42.115 104.886 ;
     RECT  41.387 105.678 42.115 105.768 ;
     RECT  42.115 104.796 42.835 105.768 ;
     RECT  41.035 2.151 43.087 103.5 ;
     RECT  43.087 2.151 43.195 103.536 ;
     RECT  42.835 104.706 43.835 105.768 ;
     RECT  43.835 104.751 43.871 105.768 ;
     RECT  43.195 2.151 43.951 103.608 ;
     RECT  43.951 2.151 44.483 103.77 ;
     RECT  43.871 104.796 45.491 105.768 ;
     RECT  45.491 105.642 45.959 105.768 ;
     RECT  45.491 104.796 46.031 104.886 ;
     RECT  46.031 104.868 46.103 104.886 ;
     RECT  45.959 105.678 46.831 105.768 ;
     RECT  46.831 105.606 46.903 105.768 ;
     RECT  46.903 104.4 47.003 104.418 ;
     RECT  46.903 105.561 47.011 105.768 ;
     RECT  44.483 2.151 47.299 103.572 ;
     RECT  47.011 104.868 48.091 105.768 ;
     RECT  48.091 104.796 48.235 105.768 ;
     RECT  48.235 104.751 48.335 105.768 ;
     RECT  48.335 104.868 49.019 105.768 ;
     RECT  49.019 105.561 49.523 105.768 ;
     RECT  49.523 105.606 50.287 105.768 ;
     RECT  50.287 105.516 51.367 105.768 ;
     RECT  51.367 104.868 51.655 105.768 ;
     RECT  47.299 2.151 51.755 103.644 ;
     RECT  51.655 104.796 51.763 105.768 ;
     RECT  51.763 104.751 51.899 105.768 ;
     RECT  51.899 104.796 52.663 104.814 ;
     RECT  51.899 105.606 52.663 105.768 ;
     RECT  52.663 104.796 52.691 105.768 ;
     RECT  52.691 104.868 52.799 105.768 ;
     RECT  51.755 2.151 53.231 103.608 ;
     RECT  53.231 2.151 53.959 103.464 ;
     RECT  52.799 105.48 53.959 105.768 ;
     RECT  53.959 104.868 54.031 105.768 ;
     RECT  54.031 104.796 54.131 105.768 ;
     RECT  53.959 2.151 54.283 103.5 ;
     RECT  54.131 105.516 54.419 105.768 ;
     RECT  54.419 105.561 55.327 105.768 ;
     RECT  55.327 104.868 55.607 105.768 ;
     RECT  55.607 105.561 56.111 105.768 ;
     RECT  56.111 105.642 56.975 105.768 ;
     RECT  57.631 104.796 57.703 104.814 ;
     RECT  56.975 105.678 57.919 105.768 ;
     RECT  57.703 104.796 57.991 104.886 ;
     RECT  57.919 105.642 57.991 105.768 ;
     RECT  57.991 104.796 58.127 105.768 ;
     RECT  54.283 2.151 58.711 103.644 ;
     RECT  58.127 104.796 58.711 104.886 ;
     RECT  58.711 2.151 58.811 104.886 ;
     RECT  58.811 104.67 58.999 104.886 ;
     RECT  58.127 105.714 58.999 105.768 ;
     RECT  58.999 104.67 59.099 105.768 ;
     RECT  59.099 104.706 59.675 105.768 ;
     RECT  59.675 104.751 60.143 105.768 ;
     RECT  60.143 104.751 60.871 105.696 ;
     RECT  58.811 2.151 60.979 103.689 ;
     RECT  60.871 104.751 61.439 105.768 ;
     RECT  60.979 2.151 61.591 103.734 ;
     RECT  61.591 2.151 62.239 104.616 ;
     RECT  61.439 105.516 62.239 105.768 ;
     RECT  62.239 2.151 63.131 105.768 ;
     RECT  63.131 2.151 63.239 104.886 ;
     RECT  63.131 105.75 63.239 105.768 ;
     RECT  63.239 2.151 63.563 104.688 ;
     RECT  63.563 104.598 66.811 104.688 ;
     RECT  66.811 104.598 66.947 104.886 ;
     RECT  66.947 104.598 67.847 104.616 ;
     RECT  63.563 2.151 68.963 103.734 ;
     RECT  68.963 2.151 68.999 103.689 ;
     RECT  68.999 2.151 84.119 103.464 ;
     RECT  84.119 2.151 101.898 103.419 ;
     RECT  101.898 41.346 102.011 76.842 ;
     RECT  101.898 90.216 102.299 90.234 ;
     RECT  101.898 87.786 102.335 87.804 ;
     RECT  101.898 21.906 102.443 23.004 ;
     RECT  101.898 34.596 102.515 35.604 ;
     RECT  102.515 35.136 102.551 35.604 ;
     RECT  102.011 44.046 102.551 60.876 ;
     RECT  101.898 32.436 102.587 32.454 ;
     RECT  102.551 44.046 102.587 57.06 ;
     RECT  102.551 57.888 102.587 60.876 ;
     RECT  102.011 63.594 102.587 76.842 ;
     RECT  101.898 20.322 102.623 20.34 ;
     RECT  101.898 21.096 102.623 21.114 ;
     RECT  102.443 21.906 102.623 21.924 ;
     RECT  101.898 26.298 102.623 30.402 ;
     RECT  102.011 41.346 102.623 43.164 ;
     RECT  102.587 44.046 102.623 47.61 ;
     RECT  102.587 48.546 102.623 52.578 ;
     RECT  102.587 57.888 102.623 60.804 ;
     RECT  102.011 61.668 102.623 62.694 ;
     RECT  102.587 63.594 102.623 75.15 ;
     RECT  101.898 77.634 102.623 80.082 ;
     RECT  102.623 26.298 102.659 28.242 ;
     RECT  102.623 48.816 102.659 50.418 ;
     RECT  102.623 57.888 102.659 58.644 ;
     RECT  102.623 63.666 102.659 65.934 ;
     RECT  102.623 78.336 102.659 79.2 ;
     RECT  102.623 79.956 102.659 79.974 ;
     RECT  102.623 41.382 102.695 43.164 ;
     RECT  102.659 26.298 102.875 27.234 ;
     RECT  101.898 85.356 102.875 85.374 ;
     RECT  102.623 66.726 102.947 74.988 ;
     RECT  102.659 57.888 102.983 58.14 ;
     RECT  102.659 48.816 103.019 50.274 ;
     RECT  102.623 51.336 103.091 52.578 ;
     RECT  103.091 51.336 103.127 51.696 ;
     RECT  102.443 22.986 103.163 23.004 ;
     RECT  103.091 52.56 103.163 52.578 ;
     RECT  102.947 66.726 103.163 71.136 ;
     RECT  102.875 26.298 103.199 26.388 ;
     RECT  102.875 27.216 103.199 27.234 ;
     RECT  102.659 28.026 103.199 28.242 ;
     RECT  102.623 29.106 103.199 30.402 ;
     RECT  101.898 38.448 103.199 39.312 ;
     RECT  102.695 41.616 103.199 43.164 ;
     RECT  102.623 44.046 103.199 46.098 ;
     RECT  102.623 46.854 103.199 46.908 ;
     RECT  103.019 48.816 103.199 49.914 ;
     RECT  103.127 51.444 103.199 51.696 ;
     RECT  102.587 53.334 103.199 56.016 ;
     RECT  102.623 59.436 103.199 60.372 ;
     RECT  102.623 61.668 103.199 61.794 ;
     RECT  102.623 62.676 103.199 62.694 ;
     RECT  102.659 63.666 103.199 65.574 ;
     RECT  103.163 66.762 103.199 71.136 ;
     RECT  102.947 72.036 103.199 74.988 ;
     RECT  102.587 76.446 103.199 76.842 ;
     RECT  102.659 78.336 103.199 78.462 ;
     RECT  103.199 26.298 103.235 26.316 ;
     RECT  103.199 29.106 103.235 29.484 ;
     RECT  103.199 30.276 103.235 30.294 ;
     RECT  103.199 38.448 103.235 38.466 ;
     RECT  103.199 39.294 103.235 39.312 ;
     RECT  103.199 41.616 103.235 41.634 ;
     RECT  103.199 43.146 103.235 43.164 ;
     RECT  103.199 45.126 103.235 45.288 ;
     RECT  103.199 46.044 103.235 46.098 ;
     RECT  103.199 49.626 103.235 49.914 ;
     RECT  103.199 51.678 103.235 51.696 ;
     RECT  103.199 55.116 103.235 55.512 ;
     RECT  102.587 57.006 103.235 57.024 ;
     RECT  103.199 64.296 103.235 64.314 ;
     RECT  103.199 67.446 103.235 67.554 ;
     RECT  103.199 68.616 103.235 68.634 ;
     RECT  103.199 69.84 103.235 69.858 ;
     RECT  103.199 70.614 103.235 70.632 ;
     RECT  103.199 72.702 103.235 72.72 ;
     RECT  103.199 76.626 103.235 76.644 ;
     RECT  103.199 78.336 103.235 78.354 ;
     RECT  103.235 29.304 103.271 29.322 ;
     RECT  102.551 35.316 103.271 35.604 ;
     RECT  103.199 46.89 103.271 46.908 ;
     RECT  103.235 49.896 103.271 49.914 ;
     RECT  103.235 67.536 103.271 67.554 ;
     RECT  103.235 46.08 103.307 46.098 ;
     RECT  103.235 55.116 103.883 55.242 ;
     RECT  103.199 28.026 103.919 28.044 ;
     RECT  103.883 55.116 103.919 55.134 ;
     RECT  103.855 43.92 103.927 43.938 ;
     RECT  101.898 36.486 103.955 36.504 ;
     RECT  102.983 57.888 103.955 57.906 ;
     RECT  103.891 24.984 103.963 25.002 ;
     RECT  103.855 40.914 103.963 41.004 ;
     RECT  103.927 43.848 103.963 43.938 ;
     RECT  103.199 53.874 103.963 53.964 ;
     RECT  103.963 40.914 103.991 41.094 ;
     RECT  103.963 43.731 103.991 43.938 ;
     RECT  103.963 53.874 103.991 54.054 ;
     RECT  103.963 24.984 104.027 25.074 ;
     RECT  103.235 45.126 104.027 45.144 ;
     RECT  103.891 48.051 104.027 48.069 ;
     RECT  103.855 23.796 104.063 23.814 ;
     RECT  104.027 25.056 104.063 25.074 ;
     RECT  103.991 40.986 104.063 41.094 ;
     RECT  103.991 43.731 104.063 43.866 ;
     RECT  103.991 53.946 104.063 54.054 ;
     RECT  103.963 56.07 104.063 56.088 ;
     RECT  103.963 57.312 104.063 57.33 ;
     RECT  103.963 59.346 104.063 59.364 ;
     RECT  103.963 62.046 104.063 62.334 ;
     RECT  103.963 63.666 104.063 63.684 ;
     RECT  103.963 66.996 104.063 67.014 ;
     RECT  103.963 68.346 104.063 69.048 ;
     RECT  103.963 72.306 104.063 72.324 ;
     RECT  103.963 73.35 104.063 73.368 ;
     RECT  103.963 77.67 104.063 78.309 ;
     RECT  103.963 79.326 104.063 79.344 ;
    LAYER M3 ;
     RECT  2.415 2.143 2.505 2.413 ;
     RECT  5.115 2.143 5.205 2.413 ;
     RECT  7.815 2.143 7.905 2.413 ;
     RECT  10.515 2.143 10.605 2.413 ;
     RECT  13.215 2.143 13.305 2.413 ;
     RECT  15.915 2.143 16.005 2.413 ;
     RECT  18.615 2.143 18.705 2.413 ;
     RECT  21.315 2.143 21.405 2.413 ;
     RECT  24.015 2.143 24.105 2.413 ;
     RECT  26.715 2.143 26.805 2.413 ;
     RECT  29.415 2.143 29.505 2.413 ;
     RECT  32.115 2.143 32.205 2.413 ;
     RECT  34.815 2.143 34.905 2.413 ;
     RECT  37.515 2.143 37.605 2.413 ;
     RECT  40.215 2.143 40.305 2.413 ;
     RECT  42.915 2.143 43.005 2.413 ;
     RECT  45.615 2.143 45.705 2.413 ;
     RECT  48.315 2.143 48.405 2.413 ;
     RECT  51.015 2.143 51.105 2.413 ;
     RECT  53.715 2.143 53.805 2.413 ;
     RECT  56.415 2.143 56.505 2.413 ;
     RECT  59.115 2.143 59.205 2.413 ;
     RECT  61.815 2.143 61.905 2.413 ;
     RECT  64.515 2.143 64.605 2.413 ;
     RECT  67.215 2.143 67.305 2.413 ;
     RECT  69.915 2.143 70.005 2.413 ;
     RECT  72.615 2.143 72.705 2.413 ;
     RECT  75.315 2.143 75.405 2.413 ;
     RECT  78.015 2.143 78.105 2.413 ;
     RECT  80.715 2.143 80.805 2.413 ;
     RECT  83.415 2.143 83.505 2.413 ;
     RECT  86.115 2.143 86.205 2.413 ;
     RECT  88.815 2.143 88.905 2.413 ;
     RECT  91.515 2.143 91.605 2.413 ;
     RECT  94.215 2.143 94.305 2.413 ;
     RECT  96.915 2.143 97.005 2.413 ;
     RECT  99.615 2.143 99.705 2.413 ;
     RECT  102.852 20.011 102.87 20.107 ;
     RECT  101.268 20.203 101.286 20.395 ;
     RECT  102.456 20.107 102.87 20.395 ;
     RECT  101.268 20.395 102.87 20.875 ;
     RECT  61.815 2.413 62.097 21.163 ;
     RECT  69.915 2.413 70.197 21.163 ;
     RECT  78.015 2.413 78.297 21.163 ;
     RECT  86.115 2.413 86.397 21.163 ;
     RECT  90.36 21.127 90.378 21.163 ;
     RECT  94.215 2.413 94.497 21.163 ;
     RECT  61.815 21.163 62.73 21.293 ;
     RECT  69.915 21.163 70.722 21.293 ;
     RECT  78.015 21.163 78.678 21.293 ;
     RECT  86.115 21.163 86.49 21.293 ;
     RECT  90.36 21.163 90.666 21.293 ;
     RECT  94.215 21.163 94.59 21.293 ;
     RECT  59.115 2.413 59.397 21.403 ;
     RECT  61.815 21.293 62.19 21.437 ;
     RECT  101.052 20.875 102.87 21.547 ;
     RECT  103.932 19.915 103.95 21.739 ;
     RECT  83.415 2.413 83.697 21.937 ;
     RECT  101.052 21.547 102.906 22.123 ;
     RECT  80.715 2.413 80.997 22.207 ;
     RECT  101.052 22.123 102.942 22.219 ;
     RECT  103.896 21.739 103.95 22.315 ;
     RECT  75.315 2.413 75.597 22.477 ;
     RECT  61.815 21.437 62.097 22.507 ;
     RECT  101.052 22.219 102.978 22.603 ;
     RECT  101.052 22.603 103.158 22.699 ;
     RECT  100.908 22.699 103.158 22.739 ;
     RECT  101.052 22.739 103.158 23.009 ;
     RECT  88.815 2.413 89.097 23.017 ;
     RECT  90.36 21.293 90.378 23.017 ;
     RECT  94.215 21.293 94.497 23.053 ;
     RECT  98.676 23.017 98.694 23.083 ;
     RECT  99.615 2.413 99.897 23.275 ;
     RECT  72.615 2.413 72.897 23.287 ;
     RECT  72.615 23.287 73.242 23.323 ;
     RECT  96.915 2.413 97.197 23.371 ;
     RECT  98.316 23.083 98.694 23.371 ;
     RECT  99.615 23.275 99.918 23.467 ;
     RECT  96.915 23.371 98.694 23.563 ;
     RECT  67.215 2.413 67.497 23.659 ;
     RECT  103.896 22.315 103.986 23.755 ;
     RECT  96.915 23.563 98.874 23.791 ;
     RECT  99.615 23.467 99.99 23.791 ;
     RECT  103.86 23.755 103.986 23.791 ;
     RECT  69.915 21.293 70.197 23.803 ;
     RECT  78.015 21.293 78.297 23.803 ;
     RECT  86.115 21.293 86.397 23.803 ;
     RECT  103.86 23.791 104.058 23.837 ;
     RECT  64.515 2.413 64.797 23.851 ;
     RECT  64.26 23.851 64.797 23.899 ;
     RECT  86.115 23.803 86.67 23.933 ;
     RECT  82.908 21.937 83.697 24.091 ;
     RECT  96.804 23.791 99.99 24.125 ;
     RECT  66.384 23.275 66.402 24.139 ;
     RECT  69.915 23.803 70.722 24.187 ;
     RECT  93.852 23.053 94.497 24.187 ;
     RECT  78.015 23.803 78.678 24.331 ;
     RECT  88.815 23.017 90.378 24.331 ;
     RECT  88.704 24.331 90.738 24.368 ;
     RECT  96.804 24.125 99.897 24.368 ;
     RECT  64.26 23.899 64.998 24.427 ;
     RECT  65.808 24.139 66.402 24.427 ;
     RECT  69.915 24.187 71.046 24.461 ;
     RECT  78.015 24.331 78.786 24.461 ;
     RECT  86.115 23.933 86.418 24.461 ;
     RECT  88.815 24.368 90.738 24.461 ;
     RECT  93.852 24.187 94.59 24.461 ;
     RECT  64.26 24.427 66.402 24.475 ;
     RECT  103.86 23.837 103.986 24.523 ;
     RECT  99.615 24.368 99.897 24.907 ;
     RECT  68.976 24.619 68.994 24.955 ;
     RECT  69.915 24.461 70.197 24.955 ;
     RECT  103.824 24.523 103.986 24.979 ;
     RECT  71.028 24.461 71.046 25.003 ;
     RECT  103.824 24.979 104.022 25.051 ;
     RECT  103.824 25.051 104.058 25.085 ;
     RECT  96.915 24.368 98.874 25.195 ;
     RECT  99.615 24.907 99.918 25.195 ;
     RECT  74.7 22.477 75.597 25.291 ;
     RECT  78.015 24.461 78.297 25.291 ;
     RECT  86.115 24.461 86.397 25.291 ;
     RECT  87.192 24.379 87.21 25.291 ;
     RECT  88.815 24.461 90.378 25.291 ;
     RECT  93.852 24.461 94.497 25.291 ;
     RECT  71.028 25.003 71.55 25.435 ;
     RECT  68.976 24.955 70.197 25.483 ;
     RECT  70.992 25.435 71.55 25.483 ;
     RECT  74.664 25.291 75.597 25.483 ;
     RECT  88.815 25.291 90.666 25.613 ;
     RECT  96.915 25.195 99.918 25.675 ;
     RECT  68.976 25.483 71.55 25.723 ;
     RECT  72.615 23.323 73.278 25.723 ;
     RECT  96.915 25.675 99.99 25.951 ;
     RECT  96.804 25.951 99.99 25.997 ;
     RECT  67.215 23.659 68.094 26.011 ;
     RECT  68.976 25.723 73.278 26.011 ;
     RECT  78.015 25.291 78.678 26.093 ;
     RECT  101.052 23.009 102.978 26.155 ;
     RECT  103.896 25.085 104.058 26.155 ;
     RECT  96.915 25.997 99.99 26.293 ;
     RECT  101.052 26.155 104.058 26.293 ;
     RECT  57.888 26.365 57.906 26.519 ;
     RECT  37.515 2.413 37.797 26.527 ;
     RECT  38.556 22.747 38.574 26.527 ;
     RECT  86.115 25.291 87.21 26.699 ;
     RECT  88.815 25.613 90.378 26.833 ;
     RECT  91.515 2.413 91.797 26.833 ;
     RECT  42.915 2.413 43.197 27.067 ;
     RECT  93.852 25.291 94.986 27.067 ;
     RECT  74.448 25.483 75.597 27.337 ;
     RECT  67.215 26.011 73.278 27.607 ;
     RECT  74.376 27.337 75.597 27.607 ;
     RECT  61.815 22.507 62.406 27.679 ;
     RECT  64.224 24.475 66.402 27.715 ;
     RECT  96.915 26.293 104.058 28.049 ;
     RECT  63.9 27.715 66.402 28.219 ;
     RECT  92.592 23.611 92.61 28.283 ;
     RECT  96.915 28.049 103.194 28.417 ;
     RECT  92.736 28.291 92.754 28.453 ;
     RECT  93.852 27.067 95.454 28.453 ;
     RECT  92.736 28.453 95.454 28.687 ;
     RECT  96.624 28.417 103.194 28.687 ;
     RECT  61.815 27.679 62.838 28.759 ;
     RECT  63.756 28.219 66.402 28.759 ;
     RECT  92.736 28.687 103.194 28.787 ;
     RECT  98.388 28.787 103.194 28.823 ;
     RECT  99.615 28.823 103.194 28.939 ;
     RECT  103.932 28.049 104.058 28.939 ;
     RECT  86.115 26.699 86.814 29.263 ;
     RECT  40.215 2.413 40.497 29.299 ;
     RECT  61.815 28.759 66.402 29.335 ;
     RECT  67.215 27.607 75.597 29.335 ;
     RECT  61.815 29.335 75.597 29.561 ;
     RECT  98.388 28.823 98.766 29.605 ;
     RECT  98.316 29.605 98.766 29.633 ;
     RECT  92.736 28.787 97.197 29.755 ;
     RECT  98.316 29.633 98.334 29.755 ;
     RECT  51.015 2.413 51.297 29.803 ;
     RECT  82.908 24.091 84.078 29.939 ;
     RECT  60.984 29.569 61.002 30.091 ;
     RECT  61.815 29.561 66.402 30.091 ;
     RECT  99.615 28.939 104.058 30.299 ;
     RECT  60.984 30.091 66.402 30.379 ;
     RECT  99.615 30.299 103.194 30.407 ;
     RECT  92.736 29.755 98.334 30.415 ;
     RECT  92.736 30.415 98.874 30.571 ;
     RECT  99.615 30.407 103.05 30.571 ;
     RECT  85.752 29.263 86.814 30.577 ;
     RECT  78.015 26.093 78.297 30.811 ;
     RECT  60.732 30.379 66.402 30.859 ;
     RECT  52.848 30.571 52.866 31.099 ;
     RECT  53.715 2.413 53.997 31.099 ;
     RECT  54.972 30.907 54.99 31.099 ;
     RECT  52.848 31.099 53.997 31.147 ;
     RECT  52.128 31.147 53.997 31.387 ;
     RECT  54.72 31.099 54.99 31.387 ;
     RECT  92.736 30.571 103.05 31.435 ;
     RECT  78.015 30.811 78.678 31.627 ;
     RECT  50.508 29.803 51.297 31.723 ;
     RECT  52.128 31.387 54.99 31.723 ;
     RECT  50.508 31.723 54.99 31.771 ;
     RECT  92.736 31.435 103.122 31.915 ;
     RECT  60.156 30.859 66.402 32.011 ;
     RECT  49.896 31.771 54.99 32.299 ;
     RECT  59.04 21.403 59.397 32.431 ;
     RECT  60.12 32.011 66.402 32.431 ;
     RECT  67.215 29.561 75.597 32.431 ;
     RECT  77.22 27.103 77.238 32.431 ;
     RECT  78.015 31.627 78.786 32.431 ;
     RECT  88.815 26.833 91.797 32.431 ;
     RECT  56.415 2.413 56.697 32.443 ;
     RECT  57.816 30.955 57.834 32.443 ;
     RECT  77.22 32.431 78.786 32.467 ;
     RECT  60.12 32.431 75.597 32.477 ;
     RECT  77.22 32.467 79.002 32.477 ;
     RECT  67.215 32.477 75.597 32.731 ;
     RECT  56.415 32.443 57.834 32.779 ;
     RECT  59.004 32.431 59.397 32.779 ;
     RECT  88.704 32.431 91.797 33.008 ;
     RECT  67.215 32.731 76.086 33.835 ;
     RECT  47.124 32.827 47.142 34.075 ;
     RECT  48.315 2.413 48.597 34.459 ;
     RECT  49.896 32.299 55.566 34.459 ;
     RECT  46.692 34.075 47.142 34.699 ;
     RECT  48.315 34.459 55.566 34.699 ;
     RECT  46.692 34.699 55.566 34.939 ;
     RECT  92.736 31.915 103.194 35.311 ;
     RECT  103.932 30.299 104.058 35.311 ;
     RECT  45.615 2.413 45.897 36.211 ;
     RECT  46.692 34.939 55.602 36.211 ;
     RECT  92.736 35.311 104.058 36.509 ;
     RECT  67.215 33.835 76.122 36.517 ;
     RECT  77.22 32.477 77.238 36.517 ;
     RECT  42.915 27.067 43.614 37.099 ;
     RECT  42.915 37.099 43.938 37.867 ;
     RECT  42.915 37.867 44.118 37.915 ;
     RECT  45.615 36.211 55.602 37.963 ;
     RECT  56.415 32.779 59.397 38.101 ;
     RECT  60.12 32.477 66.402 38.101 ;
     RECT  80.064 22.207 80.997 38.101 ;
     RECT  88.815 33.008 91.797 38.101 ;
     RECT  56.415 38.101 66.402 38.141 ;
     RECT  80.064 38.101 81.09 38.141 ;
     RECT  88.815 38.101 91.89 38.141 ;
     RECT  41.796 29.911 41.814 38.443 ;
     RECT  42.915 37.915 44.406 38.443 ;
     RECT  92.736 36.509 103.23 38.471 ;
     RECT  45.288 37.963 55.602 39.019 ;
     RECT  45.18 39.019 55.602 39.211 ;
     RECT  56.415 38.141 59.397 39.211 ;
     RECT  92.736 38.471 103.194 39.289 ;
     RECT  92.736 39.289 103.23 39.917 ;
     RECT  41.796 38.443 44.406 40.171 ;
     RECT  45.18 39.211 59.397 40.171 ;
     RECT  92.736 39.917 103.158 40.909 ;
     RECT  103.968 36.509 104.058 40.909 ;
     RECT  92.736 40.909 104.058 41.117 ;
     RECT  41.796 40.171 59.397 42.139 ;
     RECT  60.12 38.141 66.402 42.139 ;
     RECT  92.736 41.117 104.022 43.726 ;
     RECT  92.736 43.726 104.058 43.943 ;
     RECT  41.796 42.139 66.402 44.149 ;
     RECT  67.215 36.517 77.238 44.149 ;
     RECT  92.736 43.943 103.194 44.779 ;
     RECT  103.932 43.943 104.058 44.779 ;
     RECT  37.515 26.527 38.574 45.403 ;
     RECT  32.115 2.413 32.397 45.697 ;
     RECT  92.736 44.779 104.058 46.103 ;
     RECT  92.736 46.103 103.194 46.885 ;
     RECT  103.932 46.103 104.058 46.885 ;
     RECT  92.736 46.885 104.058 47.021 ;
     RECT  37.515 45.403 38.79 47.213 ;
     RECT  34.815 2.413 35.097 47.551 ;
     RECT  103.932 47.021 104.058 48.04 ;
     RECT  103.896 48.04 104.058 48.077 ;
     RECT  37.515 47.213 38.574 48.091 ;
     RECT  92.736 47.021 103.158 48.139 ;
     RECT  37.515 48.091 38.79 48.221 ;
     RECT  41.796 44.149 77.238 48.811 ;
     RECT  92.736 48.139 103.194 49.291 ;
     RECT  103.932 48.077 104.058 49.291 ;
     RECT  36.72 29.263 36.738 49.549 ;
     RECT  92.736 49.291 104.058 49.919 ;
     RECT  41.58 48.811 77.238 50.053 ;
     RECT  36.468 49.549 36.738 50.251 ;
     RECT  37.515 48.221 38.574 50.251 ;
     RECT  39.42 49.477 39.438 50.629 ;
     RECT  92.736 49.919 103.158 50.827 ;
     RECT  36.468 50.251 38.574 50.899 ;
     RECT  39.312 50.629 39.438 50.899 ;
     RECT  92.736 50.827 103.194 50.923 ;
     RECT  103.932 49.919 104.058 50.923 ;
     RECT  40.215 29.299 40.626 50.971 ;
     RECT  41.544 50.053 77.238 50.971 ;
     RECT  36.468 50.899 39.438 51.475 ;
     RECT  40.215 50.971 77.238 51.475 ;
     RECT  85.176 30.577 86.814 51.475 ;
     RECT  92.736 50.923 104.058 51.701 ;
     RECT  82.908 29.939 83.697 51.871 ;
     RECT  88.815 38.141 91.797 51.871 ;
     RECT  78.015 32.477 79.002 51.907 ;
     RECT  80.064 38.141 80.997 51.907 ;
     RECT  82.728 51.871 83.697 51.907 ;
     RECT  88.668 51.871 91.797 52.169 ;
     RECT  88.74 52.169 91.797 52.277 ;
     RECT  78.015 51.907 79.326 52.313 ;
     RECT  82.656 51.907 83.697 52.519 ;
     RECT  82.656 52.519 83.79 52.717 ;
     RECT  36.468 51.475 77.238 52.733 ;
     RECT  55.872 52.733 77.238 52.745 ;
     RECT  82.656 52.717 83.862 52.817 ;
     RECT  55.872 52.745 66.438 52.853 ;
     RECT  92.736 51.701 103.158 53.131 ;
     RECT  56.124 52.853 66.438 53.309 ;
     RECT  56.16 53.309 66.438 53.357 ;
     RECT  80.064 51.907 81.522 53.429 ;
     RECT  61.488 53.357 66.438 53.599 ;
     RECT  67.176 52.745 77.238 53.599 ;
     RECT  92.736 53.131 103.194 53.707 ;
     RECT  103.932 51.701 104.058 53.707 ;
     RECT  61.488 53.599 77.238 53.789 ;
     RECT  82.764 52.817 83.697 53.941 ;
     RECT  82.692 53.941 83.697 54.031 ;
     RECT  92.736 53.707 104.058 54.077 ;
     RECT  36.468 52.733 55.134 54.211 ;
     RECT  56.16 53.357 60.714 54.409 ;
     RECT  2.415 2.413 2.697 54.571 ;
     RECT  36.468 54.211 55.17 54.715 ;
     RECT  56.052 54.409 60.714 54.715 ;
     RECT  67.176 53.789 77.238 54.749 ;
     RECT  2.304 54.571 2.697 55.049 ;
     RECT  3.852 54.427 3.87 55.111 ;
     RECT  78.015 52.313 79.002 55.219 ;
     RECT  80.064 53.429 80.997 55.219 ;
     RECT  5.115 2.413 5.397 55.243 ;
     RECT  3.852 55.111 4.014 55.255 ;
     RECT  2.34 55.049 2.697 55.435 ;
     RECT  2.34 55.435 2.79 55.525 ;
     RECT  3.636 55.255 4.014 55.525 ;
     RECT  2.34 55.525 4.014 55.561 ;
     RECT  4.752 55.243 5.397 55.561 ;
     RECT  2.34 55.561 5.397 55.679 ;
     RECT  2.34 55.679 3.474 55.963 ;
     RECT  92.736 54.077 103.95 56.056 ;
     RECT  61.488 53.789 66.438 56.065 ;
     RECT  67.215 54.749 77.238 56.065 ;
     RECT  92.736 56.056 104.058 56.093 ;
     RECT  92.736 56.093 103.986 56.141 ;
     RECT  2.304 55.963 3.474 56.219 ;
     RECT  61.488 56.065 77.238 56.429 ;
     RECT  2.304 56.219 3.366 56.525 ;
     RECT  20.34 55.651 20.358 56.731 ;
     RECT  2.304 56.525 2.754 56.759 ;
     RECT  4.356 55.679 5.397 56.759 ;
     RECT  2.415 56.759 2.754 57.029 ;
     RECT  92.736 56.141 103.95 57.029 ;
     RECT  103.932 57.029 103.95 57.259 ;
     RECT  103.932 57.259 103.986 57.307 ;
     RECT  103.932 57.307 104.058 57.344 ;
     RECT  103.932 57.344 103.95 57.911 ;
     RECT  61.488 56.429 66.438 57.917 ;
     RECT  92.736 57.029 102.978 58.145 ;
     RECT  36.468 54.715 60.714 58.253 ;
     RECT  85.176 51.475 87.498 58.253 ;
     RECT  51.015 58.253 60.714 58.423 ;
     RECT  61.488 57.917 64.926 58.423 ;
     RECT  51.015 58.423 64.926 58.651 ;
     RECT  65.88 57.917 66.438 58.651 ;
     RECT  92.736 58.145 102.942 59.063 ;
     RECT  51.015 58.651 66.438 59.099 ;
     RECT  100.728 59.063 102.942 59.275 ;
     RECT  104.04 59.323 104.058 59.341 ;
     RECT  103.968 59.341 104.058 59.369 ;
     RECT  103.968 59.369 103.986 59.405 ;
     RECT  92.736 59.063 99.897 60.331 ;
     RECT  100.728 59.275 103.194 60.331 ;
     RECT  92.736 60.331 103.194 60.377 ;
     RECT  51.015 59.099 64.998 60.619 ;
     RECT  65.88 59.099 66.438 60.619 ;
     RECT  51.015 60.619 66.438 60.889 ;
     RECT  67.215 56.429 77.238 60.889 ;
     RECT  92.736 60.377 102.942 61.483 ;
     RECT  36.468 58.253 50.238 61.861 ;
     RECT  51.015 60.889 77.238 61.861 ;
     RECT  92.736 61.483 103.194 61.901 ;
     RECT  104.04 62.011 104.058 62.041 ;
     RECT  103.968 62.041 104.058 62.339 ;
     RECT  103.968 62.339 103.986 62.381 ;
     RECT  92.736 61.901 102.942 62.635 ;
     RECT  88.815 52.277 91.797 63.481 ;
     RECT  92.736 62.635 103.194 63.481 ;
     RECT  88.815 63.481 103.194 63.533 ;
     RECT  104.04 63.643 104.058 63.661 ;
     RECT  103.968 63.661 104.058 63.689 ;
     RECT  103.968 63.689 103.986 63.725 ;
     RECT  92.736 63.533 103.194 64.075 ;
     RECT  92.736 64.075 103.23 64.319 ;
     RECT  88.815 63.533 91.797 64.597 ;
     RECT  92.736 64.319 103.194 64.597 ;
     RECT  88.815 64.597 103.194 64.685 ;
     RECT  36.468 61.861 77.238 65.273 ;
     RECT  92.736 64.685 103.194 65.579 ;
     RECT  36.468 65.273 71.622 65.693 ;
     RECT  63.54 65.693 71.622 66.083 ;
     RECT  63.54 66.083 71.514 66.389 ;
     RECT  92.736 65.579 102.942 66.475 ;
     RECT  78.015 55.219 80.997 66.587 ;
     RECT  103.968 66.955 103.986 66.991 ;
     RECT  103.968 66.991 104.058 67.019 ;
     RECT  104.04 67.019 104.058 67.037 ;
     RECT  72.615 65.273 77.238 67.091 ;
     RECT  92.736 66.475 103.194 67.147 ;
     RECT  92.736 67.147 103.266 67.289 ;
     RECT  102.276 67.289 103.266 67.559 ;
     RECT  74.7 67.091 77.238 67.631 ;
     RECT  102.276 67.559 103.23 67.661 ;
     RECT  36.468 65.693 62.802 67.711 ;
     RECT  63.54 66.389 71.334 67.711 ;
     RECT  36.468 67.711 71.334 67.829 ;
     RECT  74.7 67.631 76.662 68.279 ;
     RECT  103.968 68.299 103.986 68.341 ;
     RECT  102.276 67.661 103.194 68.611 ;
     RECT  102.276 68.611 103.23 68.717 ;
     RECT  103.968 68.341 104.058 69.053 ;
     RECT  103.968 69.053 103.986 69.101 ;
     RECT  34.815 47.551 35.37 69.223 ;
     RECT  102.276 68.717 103.194 69.739 ;
     RECT  102.276 69.739 103.23 70.637 ;
     RECT  92.736 67.289 101.466 71.179 ;
     RECT  102.276 70.637 103.194 71.179 ;
     RECT  74.7 68.279 76.482 71.609 ;
     RECT  92.736 71.179 103.194 72.185 ;
     RECT  104.04 72.283 104.058 72.301 ;
     RECT  103.968 72.301 104.058 72.329 ;
     RECT  103.968 72.329 103.986 72.365 ;
     RECT  88.815 64.685 91.797 72.419 ;
     RECT  32.115 45.697 33.066 72.499 ;
     RECT  102.276 72.185 103.194 72.619 ;
     RECT  102.276 72.619 103.23 72.725 ;
     RECT  92.736 72.185 101.466 73.039 ;
     RECT  102.276 72.725 103.194 73.039 ;
     RECT  81.756 64.939 81.774 73.139 ;
     RECT  36.468 67.829 62.802 73.309 ;
     RECT  63.54 67.829 71.334 73.309 ;
     RECT  82.548 54.031 83.697 73.339 ;
     RECT  104.04 73.336 104.058 73.345 ;
     RECT  103.968 73.345 104.058 73.373 ;
     RECT  103.968 73.373 103.986 73.421 ;
     RECT  82.548 73.339 84.402 73.499 ;
     RECT  92.736 73.039 103.194 74.075 ;
     RECT  74.7 71.609 76.41 74.381 ;
     RECT  102.276 74.075 103.194 74.993 ;
     RECT  87.768 75.499 87.786 75.569 ;
     RECT  92.736 74.075 101.466 76.072 ;
     RECT  102.276 74.993 102.906 76.072 ;
     RECT  92.736 76.072 102.906 76.363 ;
     RECT  92.736 76.363 103.194 76.379 ;
     RECT  102.276 76.379 103.194 76.621 ;
     RECT  102.276 76.621 103.23 76.685 ;
     RECT  72.615 67.091 73.818 76.811 ;
     RECT  102.276 76.685 103.194 76.847 ;
     RECT  34.815 69.223 35.514 77.665 ;
     RECT  36.468 73.309 71.334 77.665 ;
     RECT  104.04 77.656 104.058 77.665 ;
     RECT  32.115 72.499 33.534 77.827 ;
     RECT  34.815 77.665 71.334 77.827 ;
     RECT  92.736 76.379 101.466 78.061 ;
     RECT  92.736 78.061 101.502 78.125 ;
     RECT  102.276 76.847 102.87 78.187 ;
     RECT  103.968 77.665 104.058 78.314 ;
     RECT  103.968 78.314 103.986 78.317 ;
     RECT  102.276 78.187 103.194 78.331 ;
     RECT  102.276 78.331 103.23 78.413 ;
     RECT  102.276 78.413 103.194 78.467 ;
     RECT  92.736 78.125 101.466 78.859 ;
     RECT  92.736 78.859 101.502 78.899 ;
     RECT  90.36 72.419 91.797 78.901 ;
     RECT  92.736 78.899 101.466 78.901 ;
     RECT  90.36 78.901 101.466 78.941 ;
     RECT  104.04 79.291 104.058 79.321 ;
     RECT  103.968 79.321 104.058 79.349 ;
     RECT  103.968 79.349 103.986 79.373 ;
     RECT  21.315 2.413 21.597 79.435 ;
     RECT  21.315 79.435 21.798 79.475 ;
     RECT  20.268 56.731 20.358 79.591 ;
     RECT  21.315 79.475 21.597 79.627 ;
     RECT  20.232 79.591 20.358 79.661 ;
     RECT  20.268 79.661 20.358 79.753 ;
     RECT  21.132 79.627 21.597 79.753 ;
     RECT  20.268 79.753 21.597 79.805 ;
     RECT  4.644 56.759 5.397 80.321 ;
     RECT  74.7 74.381 75.597 81.869 ;
     RECT  73.8 76.811 73.818 81.985 ;
     RECT  73.8 81.985 73.854 82.715 ;
     RECT  85.176 58.253 86.814 82.921 ;
     RECT  92.736 78.941 101.466 82.949 ;
     RECT  82.548 73.499 83.697 83.191 ;
     RECT  88.815 72.419 89.097 84.073 ;
     RECT  98.316 82.949 101.466 84.101 ;
     RECT  82.476 83.191 83.697 84.181 ;
     RECT  73.836 82.715 73.854 84.299 ;
     RECT  81.972 84.181 83.697 84.451 ;
     RECT  74.088 84.721 74.106 84.941 ;
     RECT  72.615 76.811 72.897 85.189 ;
     RECT  102.276 78.467 102.87 85.379 ;
     RECT  98.316 84.101 101.034 86.909 ;
     RECT  88.815 84.073 89.55 87.269 ;
     RECT  102.276 85.379 102.33 87.809 ;
     RECT  99.432 86.909 101.034 87.925 ;
     RECT  88.815 87.269 89.478 88.079 ;
     RECT  85.176 82.921 87.426 89.203 ;
     RECT  76.392 74.381 76.41 89.231 ;
     RECT  75.315 81.869 75.597 89.239 ;
     RECT  92.736 82.949 97.197 89.771 ;
     RECT  78.015 66.587 78.93 89.789 ;
     RECT  78.015 89.789 78.642 90.239 ;
     RECT  102.276 87.809 102.294 90.239 ;
     RECT  98.316 86.909 98.334 90.247 ;
     RECT  27.72 90.391 27.738 90.481 ;
     RECT  26.715 2.413 26.997 90.571 ;
     RECT  27.72 90.481 27.846 90.571 ;
     RECT  26.715 90.571 27.846 90.605 ;
     RECT  81.9 84.451 83.697 90.893 ;
     RECT  93.852 89.771 97.197 90.923 ;
     RECT  32.115 77.827 71.334 91.049 ;
     RECT  29.415 2.413 29.697 91.291 ;
     RECT  26.715 90.605 27.738 91.325 ;
     RECT  28.944 91.291 29.697 91.723 ;
     RECT  28.764 91.723 29.697 91.769 ;
     RECT  81.9 90.893 82.566 92.011 ;
     RECT  83.415 90.893 83.697 92.011 ;
     RECT  26.715 91.325 27.486 92.045 ;
     RECT  81.792 92.011 83.697 92.048 ;
     RECT  80.064 66.587 80.997 92.129 ;
     RECT  81.9 92.048 83.697 92.129 ;
     RECT  78.015 90.239 78.297 92.137 ;
     RECT  78.015 92.137 78.75 92.273 ;
     RECT  81.9 92.129 82.566 93.757 ;
     RECT  83.415 92.129 83.697 93.757 ;
     RECT  90.36 78.941 91.797 93.785 ;
     RECT  32.115 91.049 70.254 94.063 ;
     RECT  80.136 92.129 80.997 94.873 ;
     RECT  84.888 89.203 87.426 94.901 ;
     RECT  84.888 94.901 86.814 95.261 ;
     RECT  32.115 94.063 70.29 95.419 ;
     RECT  92.736 89.771 92.754 95.707 ;
     RECT  72.216 85.189 72.897 95.755 ;
     RECT  32.115 95.419 70.326 96.427 ;
     RECT  32.115 96.427 70.362 96.557 ;
     RECT  72.216 95.755 73.098 96.601 ;
     RECT  73.98 85.765 73.998 96.601 ;
     RECT  99.432 87.925 101.394 96.605 ;
     RECT  81.9 93.757 83.697 96.871 ;
     RECT  72.216 96.601 73.998 96.989 ;
     RECT  73.62 96.989 73.998 97.565 ;
     RECT  98.316 90.247 98.37 97.565 ;
     RECT  32.115 96.557 70.326 97.645 ;
     RECT  32.115 97.645 70.362 97.799 ;
     RECT  71.244 91.049 71.334 98.851 ;
     RECT  73.98 97.565 73.998 98.887 ;
     RECT  75.315 89.239 76.086 98.887 ;
     RECT  84.888 95.261 85.194 98.915 ;
     RECT  79.488 94.873 80.997 98.951 ;
     RECT  71.244 98.851 71.37 98.959 ;
     RECT  72.216 96.989 72.897 98.959 ;
     RECT  73.98 98.887 76.086 98.987 ;
     RECT  20.268 79.805 20.358 99.059 ;
     RECT  20.268 99.059 20.286 99.257 ;
     RECT  81.9 96.871 83.862 99.689 ;
     RECT  32.115 97.799 70.326 99.739 ;
     RECT  71.244 98.959 72.897 99.739 ;
     RECT  78.015 92.273 78.297 99.739 ;
     RECT  32.115 99.739 72.897 99.869 ;
     RECT  78.015 99.739 78.678 99.869 ;
     RECT  86.115 95.261 86.814 99.959 ;
     RECT  92.628 95.707 92.754 99.959 ;
     RECT  99.432 96.605 99.897 99.959 ;
     RECT  96.915 90.923 97.197 99.967 ;
     RECT  98.352 97.565 98.37 99.967 ;
     RECT  73.98 98.987 75.597 100.013 ;
     RECT  96.915 99.967 98.37 100.013 ;
     RECT  32.115 99.869 70.29 100.229 ;
     RECT  81.9 99.689 83.697 100.229 ;
     RECT  32.115 100.229 70.254 100.315 ;
     RECT  93.852 90.923 96.03 100.381 ;
     RECT  96.915 100.013 97.197 100.381 ;
     RECT  71.244 99.869 72.897 100.409 ;
     RECT  81.9 100.229 82.098 100.409 ;
     RECT  32.076 100.315 70.254 100.499 ;
     RECT  93.852 100.381 97.197 100.499 ;
     RECT  100.62 96.605 101.394 100.499 ;
     RECT  90.36 93.785 90.378 100.543 ;
     RECT  90.144 100.543 90.378 100.589 ;
     RECT  73.98 100.013 73.998 100.651 ;
     RECT  71.316 100.409 72.897 100.769 ;
     RECT  73.908 100.651 73.998 100.769 ;
     RECT  83.415 100.229 83.697 101.011 ;
     RECT  93.852 100.499 96.03 101.039 ;
     RECT  93.852 101.039 95.526 101.075 ;
     RECT  83.196 101.011 83.697 101.083 ;
     RECT  77.22 90.391 77.238 101.119 ;
     RECT  78.015 99.869 78.297 101.119 ;
     RECT  93.852 101.075 94.914 101.147 ;
     RECT  75.315 100.013 75.597 101.155 ;
     RECT  90.684 101.047 90.702 101.183 ;
     RECT  93.852 101.147 94.497 101.191 ;
     RECT  72.615 100.769 72.897 101.281 ;
     RECT  74.628 101.155 75.597 101.309 ;
     RECT  80.136 98.951 80.997 101.309 ;
     RECT  93.78 101.191 94.497 101.309 ;
     RECT  77.22 101.119 78.297 101.353 ;
     RECT  76.968 101.353 78.297 101.381 ;
     RECT  83.196 101.083 83.826 101.453 ;
     RECT  32.115 100.499 70.254 101.461 ;
     RECT  32.04 101.461 70.254 101.467 ;
     RECT  71.316 100.769 71.802 101.563 ;
     RECT  72.615 101.281 72.99 101.563 ;
     RECT  32.04 101.467 70.506 101.587 ;
     RECT  81.9 100.409 81.918 101.693 ;
     RECT  71.316 101.563 72.99 101.741 ;
     RECT  31.896 101.587 70.506 101.849 ;
     RECT  31.896 101.849 70.47 101.929 ;
     RECT  76.968 101.381 77.238 101.957 ;
     RECT  31.824 101.929 70.47 101.993 ;
     RECT  72.615 101.741 72.99 101.993 ;
     RECT  31.824 101.993 70.197 102.119 ;
     RECT  77.22 101.957 77.238 102.119 ;
     RECT  101.016 100.499 101.394 102.155 ;
     RECT  91.515 93.785 91.797 102.187 ;
     RECT  101.016 102.155 101.034 102.191 ;
     RECT  91.224 102.187 91.797 102.227 ;
     RECT  86.115 99.959 86.397 102.271 ;
     RECT  83.415 101.453 83.826 102.389 ;
     RECT  84.888 98.915 84.906 102.389 ;
     RECT  86.115 102.271 86.454 102.569 ;
     RECT  31.896 102.119 70.197 102.659 ;
     RECT  71.316 101.741 71.334 102.839 ;
     RECT  2.415 57.029 2.697 103.157 ;
     RECT  5.115 80.321 5.397 103.157 ;
     RECT  7.815 2.413 8.097 103.157 ;
     RECT  10.515 2.413 10.797 103.157 ;
     RECT  13.215 2.413 13.497 103.157 ;
     RECT  15.915 2.413 16.197 103.157 ;
     RECT  18.615 2.413 18.897 103.157 ;
     RECT  21.315 79.805 21.597 103.157 ;
     RECT  24.015 2.413 24.297 103.157 ;
     RECT  26.715 92.045 26.997 103.157 ;
     RECT  29.415 91.769 29.697 103.157 ;
     RECT  69.915 102.659 70.197 103.157 ;
     RECT  72.615 101.993 72.897 103.157 ;
     RECT  75.315 101.309 75.597 103.157 ;
     RECT  78.015 101.381 78.297 103.157 ;
     RECT  80.715 101.309 80.997 103.157 ;
     RECT  83.415 102.389 83.697 103.157 ;
     RECT  86.115 102.569 86.397 103.157 ;
     RECT  88.815 88.079 89.097 103.157 ;
     RECT  91.515 102.227 91.797 103.157 ;
     RECT  94.215 101.309 94.497 103.157 ;
     RECT  96.915 100.499 97.197 103.157 ;
     RECT  99.615 99.959 99.897 103.157 ;
     RECT  31.896 102.659 68.994 103.199 ;
     RECT  98.352 100.013 98.37 103.199 ;
     RECT  83.607 103.157 83.697 103.351 ;
     RECT  2.607 103.157 2.697 103.427 ;
     RECT  5.307 103.157 5.397 103.427 ;
     RECT  8.007 103.157 8.097 103.427 ;
     RECT  10.707 103.157 10.797 103.427 ;
     RECT  13.407 103.157 13.497 103.427 ;
     RECT  16.107 103.157 16.197 103.427 ;
     RECT  18.807 103.157 18.897 103.427 ;
     RECT  21.507 103.157 21.597 103.427 ;
     RECT  24.207 103.157 24.297 103.427 ;
     RECT  26.907 103.157 26.997 103.427 ;
     RECT  29.607 103.157 29.697 103.427 ;
     RECT  70.107 103.157 70.197 103.427 ;
     RECT  72.807 103.157 72.897 103.427 ;
     RECT  75.507 103.157 75.597 103.427 ;
     RECT  78.207 103.157 78.297 103.427 ;
     RECT  80.907 103.157 80.997 103.427 ;
     RECT  83.607 103.351 84.114 103.427 ;
     RECT  86.307 103.157 86.397 103.427 ;
     RECT  89.007 103.157 89.097 103.427 ;
     RECT  91.707 103.157 91.797 103.427 ;
     RECT  94.407 103.157 94.497 103.427 ;
     RECT  97.107 103.157 97.197 103.427 ;
     RECT  99.807 103.157 99.897 103.427 ;
     RECT  32.004 103.199 68.994 103.469 ;
     RECT  84.096 103.427 84.114 103.469 ;
     RECT  32.688 103.469 68.994 103.694 ;
     RECT  32.688 103.694 68.958 103.739 ;
     RECT  32.688 103.739 68.778 103.805 ;
     RECT  65.412 103.805 68.778 104.285 ;
     RECT  32.688 103.805 64.566 104.315 ;
     RECT  65.88 104.285 68.778 105.341 ;
     RECT  66.384 105.341 68.778 105.389 ;
     RECT  66.384 105.389 66.834 105.437 ;
     RECT  66.492 105.437 66.834 105.485 ;
     RECT  66.492 105.485 66.51 105.533 ;
     RECT  67.572 105.389 68.778 105.581 ;
     RECT  68.76 105.581 68.778 105.629 ;
     RECT  64.116 104.315 64.566 105.677 ;
     RECT  64.548 105.677 64.566 105.725 ;
     RECT  67.572 105.581 67.59 105.725 ;
     RECT  32.688 104.315 63.234 105.773 ;
     RECT  32.724 105.773 63.234 105.779 ;
     RECT  32.742 105.779 32.796 105.78 ;
     RECT  32.814 105.779 32.868 105.78 ;
     RECT  32.886 105.779 32.94 105.78 ;
     RECT  32.958 105.779 33.012 105.78 ;
     RECT  33.03 105.779 33.084 105.78 ;
     RECT  33.102 105.779 33.156 105.78 ;
     RECT  33.174 105.779 33.228 105.78 ;
     RECT  33.246 105.779 33.3 105.78 ;
     RECT  33.318 105.779 33.372 105.78 ;
     RECT  33.39 105.779 33.444 105.78 ;
     RECT  33.462 105.779 33.516 105.78 ;
     RECT  33.534 105.779 33.588 105.78 ;
     RECT  33.606 105.779 33.66 105.78 ;
     RECT  33.678 105.779 33.732 105.78 ;
     RECT  33.75 105.779 33.804 105.78 ;
     RECT  33.822 105.779 33.876 105.78 ;
     RECT  33.894 105.779 33.948 105.78 ;
     RECT  33.966 105.779 34.02 105.78 ;
     RECT  34.038 105.779 34.092 105.78 ;
     RECT  34.11 105.779 34.164 105.78 ;
     RECT  34.182 105.779 34.236 105.78 ;
     RECT  34.254 105.779 34.308 105.78 ;
     RECT  34.326 105.779 34.38 105.78 ;
     RECT  34.398 105.779 34.452 105.78 ;
     RECT  34.47 105.779 34.524 105.78 ;
     RECT  34.542 105.779 34.596 105.78 ;
     RECT  34.614 105.779 34.668 105.78 ;
     RECT  34.686 105.779 34.74 105.78 ;
     RECT  34.758 105.779 34.812 105.78 ;
     RECT  34.83 105.779 34.884 105.78 ;
     RECT  34.902 105.779 34.956 105.78 ;
     RECT  34.974 105.779 35.028 105.78 ;
     RECT  35.046 105.779 35.1 105.78 ;
     RECT  35.118 105.779 35.172 105.78 ;
     RECT  35.19 105.779 35.244 105.78 ;
     RECT  35.262 105.779 35.316 105.78 ;
     RECT  35.334 105.779 35.388 105.78 ;
     RECT  35.406 105.779 35.46 105.78 ;
     RECT  35.478 105.779 35.532 105.78 ;
     RECT  35.55 105.779 35.604 105.78 ;
     RECT  35.622 105.779 35.676 105.78 ;
     RECT  35.694 105.779 35.748 105.78 ;
     RECT  35.766 105.779 35.82 105.78 ;
     RECT  35.838 105.779 35.892 105.78 ;
     RECT  35.91 105.779 35.964 105.78 ;
     RECT  35.982 105.779 36.036 105.78 ;
     RECT  36.054 105.779 36.108 105.78 ;
     RECT  36.126 105.779 36.18 105.78 ;
     RECT  36.198 105.779 36.252 105.78 ;
     RECT  36.27 105.779 36.324 105.78 ;
     RECT  36.342 105.779 36.396 105.78 ;
     RECT  36.414 105.779 36.468 105.78 ;
     RECT  36.486 105.779 36.54 105.78 ;
     RECT  36.558 105.779 36.612 105.78 ;
     RECT  36.63 105.779 36.684 105.78 ;
     RECT  36.702 105.779 36.756 105.78 ;
     RECT  36.774 105.779 36.828 105.78 ;
     RECT  36.846 105.779 36.9 105.78 ;
     RECT  36.918 105.779 36.972 105.78 ;
     RECT  36.99 105.779 37.044 105.78 ;
     RECT  37.062 105.779 37.116 105.78 ;
     RECT  37.134 105.779 37.188 105.78 ;
     RECT  37.206 105.779 37.26 105.78 ;
     RECT  37.278 105.779 37.332 105.78 ;
     RECT  37.35 105.779 37.404 105.78 ;
     RECT  37.422 105.779 37.476 105.78 ;
     RECT  37.494 105.779 37.548 105.78 ;
     RECT  37.566 105.779 37.62 105.78 ;
     RECT  37.638 105.779 37.692 105.78 ;
     RECT  37.71 105.779 37.764 105.78 ;
     RECT  37.782 105.779 37.836 105.78 ;
     RECT  37.854 105.779 37.908 105.78 ;
     RECT  37.926 105.779 37.98 105.78 ;
     RECT  37.998 105.779 38.052 105.78 ;
     RECT  38.07 105.779 38.124 105.78 ;
     RECT  38.142 105.779 38.196 105.78 ;
     RECT  38.214 105.779 38.268 105.78 ;
     RECT  38.286 105.779 38.34 105.78 ;
     RECT  38.358 105.779 38.412 105.78 ;
     RECT  38.43 105.779 38.484 105.78 ;
     RECT  38.502 105.779 38.556 105.78 ;
     RECT  38.574 105.779 38.628 105.78 ;
     RECT  38.646 105.779 38.7 105.78 ;
     RECT  38.718 105.779 38.772 105.78 ;
     RECT  38.79 105.779 38.844 105.78 ;
     RECT  38.862 105.779 38.916 105.78 ;
     RECT  38.934 105.779 38.988 105.78 ;
     RECT  39.006 105.779 39.06 105.78 ;
     RECT  39.078 105.779 39.132 105.78 ;
     RECT  39.15 105.779 39.204 105.78 ;
     RECT  39.222 105.779 39.276 105.78 ;
     RECT  39.294 105.779 39.348 105.78 ;
     RECT  39.366 105.779 39.42 105.78 ;
     RECT  39.438 105.779 39.492 105.78 ;
     RECT  39.51 105.779 39.564 105.78 ;
     RECT  39.582 105.779 39.636 105.78 ;
     RECT  39.654 105.779 39.708 105.78 ;
     RECT  39.726 105.779 39.78 105.78 ;
     RECT  39.798 105.779 39.852 105.78 ;
     RECT  39.87 105.779 39.924 105.78 ;
     RECT  39.942 105.779 39.996 105.78 ;
     RECT  40.014 105.779 40.068 105.78 ;
     RECT  40.086 105.779 40.14 105.78 ;
     RECT  40.158 105.779 40.212 105.78 ;
     RECT  40.23 105.779 40.284 105.78 ;
     RECT  40.302 105.779 40.356 105.78 ;
     RECT  40.374 105.779 40.428 105.78 ;
     RECT  40.446 105.779 40.5 105.78 ;
     RECT  40.518 105.779 40.572 105.78 ;
     RECT  40.59 105.779 40.644 105.78 ;
     RECT  40.662 105.779 40.716 105.78 ;
     RECT  40.734 105.779 40.788 105.78 ;
     RECT  40.806 105.779 40.86 105.78 ;
     RECT  40.878 105.779 40.932 105.78 ;
     RECT  40.95 105.779 41.004 105.78 ;
     RECT  41.022 105.779 41.076 105.78 ;
     RECT  41.094 105.779 41.148 105.78 ;
     RECT  41.166 105.779 41.22 105.78 ;
     RECT  41.238 105.779 41.292 105.78 ;
     RECT  41.31 105.779 41.364 105.78 ;
     RECT  41.382 105.779 41.436 105.78 ;
     RECT  41.454 105.779 41.508 105.78 ;
     RECT  41.526 105.779 41.58 105.78 ;
     RECT  41.598 105.779 41.652 105.78 ;
     RECT  41.67 105.779 41.724 105.78 ;
     RECT  41.742 105.779 41.796 105.78 ;
     RECT  41.814 105.779 41.868 105.78 ;
     RECT  41.886 105.779 41.94 105.78 ;
     RECT  41.958 105.779 42.012 105.78 ;
     RECT  42.03 105.779 42.084 105.78 ;
     RECT  42.102 105.779 42.156 105.78 ;
     RECT  42.174 105.779 42.228 105.78 ;
     RECT  42.246 105.779 42.3 105.78 ;
     RECT  42.318 105.779 42.372 105.78 ;
     RECT  42.39 105.779 42.444 105.78 ;
     RECT  42.462 105.779 42.516 105.78 ;
     RECT  42.534 105.779 42.588 105.78 ;
     RECT  42.606 105.779 42.66 105.78 ;
     RECT  42.678 105.779 42.732 105.78 ;
     RECT  42.75 105.779 42.804 105.78 ;
     RECT  42.822 105.779 42.876 105.78 ;
     RECT  42.894 105.779 42.948 105.78 ;
     RECT  42.966 105.779 43.02 105.78 ;
     RECT  43.038 105.779 43.092 105.78 ;
     RECT  43.11 105.779 43.164 105.78 ;
     RECT  43.182 105.779 43.236 105.78 ;
     RECT  43.254 105.779 43.308 105.78 ;
     RECT  43.326 105.779 43.38 105.78 ;
     RECT  43.398 105.779 43.452 105.78 ;
     RECT  43.47 105.779 43.524 105.78 ;
     RECT  43.542 105.779 43.596 105.78 ;
     RECT  43.614 105.779 43.668 105.78 ;
     RECT  43.686 105.779 43.74 105.78 ;
     RECT  43.758 105.779 43.812 105.78 ;
     RECT  43.83 105.779 43.884 105.78 ;
     RECT  43.902 105.779 43.956 105.78 ;
     RECT  43.974 105.779 44.028 105.78 ;
     RECT  44.046 105.779 44.1 105.78 ;
     RECT  44.118 105.779 44.172 105.78 ;
     RECT  44.19 105.779 44.244 105.78 ;
     RECT  44.262 105.779 44.316 105.78 ;
     RECT  44.334 105.779 44.388 105.78 ;
     RECT  44.406 105.779 44.46 105.78 ;
     RECT  44.478 105.779 44.532 105.78 ;
     RECT  44.55 105.779 44.604 105.78 ;
     RECT  44.622 105.779 44.676 105.78 ;
     RECT  44.694 105.779 44.748 105.78 ;
     RECT  44.766 105.779 44.82 105.78 ;
     RECT  44.838 105.779 44.892 105.78 ;
     RECT  44.91 105.779 44.964 105.78 ;
     RECT  44.982 105.779 45.036 105.78 ;
     RECT  45.054 105.779 45.108 105.78 ;
     RECT  45.126 105.779 45.18 105.78 ;
     RECT  45.198 105.779 45.252 105.78 ;
     RECT  45.27 105.779 45.324 105.78 ;
     RECT  45.342 105.779 45.396 105.78 ;
     RECT  45.414 105.779 45.468 105.78 ;
     RECT  45.486 105.779 45.54 105.78 ;
     RECT  45.558 105.779 45.612 105.78 ;
     RECT  45.63 105.779 45.684 105.78 ;
     RECT  45.702 105.779 45.756 105.78 ;
     RECT  45.774 105.779 45.828 105.78 ;
     RECT  45.846 105.779 45.9 105.78 ;
     RECT  45.918 105.779 46.548 105.78 ;
     RECT  46.566 105.779 46.62 105.78 ;
     RECT  46.638 105.779 46.692 105.78 ;
     RECT  46.71 105.779 46.764 105.78 ;
     RECT  46.782 105.779 46.836 105.78 ;
     RECT  46.854 105.779 46.908 105.78 ;
     RECT  46.926 105.779 46.98 105.78 ;
     RECT  46.998 105.779 47.052 105.78 ;
     RECT  47.07 105.779 47.124 105.78 ;
     RECT  47.142 105.779 47.196 105.78 ;
     RECT  47.214 105.779 47.268 105.78 ;
     RECT  47.286 105.779 47.34 105.78 ;
     RECT  47.358 105.779 47.412 105.78 ;
     RECT  47.43 105.779 47.484 105.78 ;
     RECT  47.502 105.779 47.556 105.78 ;
     RECT  47.574 105.779 47.628 105.78 ;
     RECT  47.646 105.779 47.7 105.78 ;
     RECT  47.718 105.779 47.772 105.78 ;
     RECT  47.79 105.779 47.844 105.78 ;
     RECT  47.862 105.779 47.916 105.78 ;
     RECT  47.934 105.779 47.988 105.78 ;
     RECT  48.006 105.779 48.06 105.78 ;
     RECT  48.078 105.779 48.132 105.78 ;
     RECT  48.15 105.779 48.204 105.78 ;
     RECT  48.222 105.779 48.276 105.78 ;
     RECT  48.294 105.779 48.348 105.78 ;
     RECT  48.366 105.779 48.42 105.78 ;
     RECT  48.438 105.779 48.492 105.78 ;
     RECT  48.51 105.779 48.564 105.78 ;
     RECT  48.582 105.779 48.636 105.78 ;
     RECT  48.654 105.779 48.708 105.78 ;
     RECT  48.726 105.779 48.78 105.78 ;
     RECT  48.798 105.779 48.852 105.78 ;
     RECT  48.87 105.779 48.924 105.78 ;
     RECT  48.942 105.779 48.996 105.78 ;
     RECT  49.014 105.779 49.068 105.78 ;
     RECT  49.086 105.779 49.14 105.78 ;
     RECT  49.158 105.779 49.212 105.78 ;
     RECT  49.23 105.779 49.284 105.78 ;
     RECT  49.302 105.779 49.356 105.78 ;
     RECT  49.374 105.779 49.428 105.78 ;
     RECT  49.446 105.779 49.5 105.78 ;
     RECT  49.518 105.779 49.572 105.78 ;
     RECT  49.59 105.779 49.644 105.78 ;
     RECT  49.662 105.779 49.716 105.78 ;
     RECT  49.734 105.779 49.788 105.78 ;
     RECT  49.806 105.779 49.86 105.78 ;
     RECT  49.878 105.779 49.932 105.78 ;
     RECT  49.95 105.779 50.004 105.78 ;
     RECT  50.022 105.779 50.076 105.78 ;
     RECT  50.094 105.779 50.148 105.78 ;
     RECT  50.166 105.779 50.22 105.78 ;
     RECT  50.238 105.779 50.292 105.78 ;
     RECT  50.31 105.779 50.364 105.78 ;
     RECT  50.382 105.779 50.436 105.78 ;
     RECT  50.454 105.779 50.508 105.78 ;
     RECT  50.526 105.779 50.58 105.78 ;
     RECT  50.598 105.779 50.652 105.78 ;
     RECT  50.67 105.779 50.724 105.78 ;
     RECT  50.742 105.779 50.796 105.78 ;
     RECT  50.814 105.779 50.868 105.78 ;
     RECT  50.886 105.779 50.94 105.78 ;
     RECT  50.958 105.779 51.012 105.78 ;
     RECT  51.03 105.779 51.084 105.78 ;
     RECT  51.102 105.779 51.156 105.78 ;
     RECT  51.174 105.779 51.228 105.78 ;
     RECT  51.246 105.779 51.3 105.78 ;
     RECT  51.318 105.779 51.372 105.78 ;
     RECT  51.39 105.779 51.444 105.78 ;
     RECT  51.462 105.779 51.516 105.78 ;
     RECT  51.534 105.779 51.588 105.78 ;
     RECT  51.606 105.779 51.66 105.78 ;
     RECT  51.678 105.779 51.732 105.78 ;
     RECT  51.75 105.779 51.804 105.78 ;
     RECT  51.822 105.779 51.876 105.78 ;
     RECT  51.894 105.779 51.948 105.78 ;
     RECT  51.966 105.779 52.02 105.78 ;
     RECT  52.038 105.779 52.092 105.78 ;
     RECT  52.11 105.779 52.164 105.78 ;
     RECT  52.182 105.779 52.236 105.78 ;
     RECT  52.254 105.779 52.308 105.78 ;
     RECT  52.326 105.779 52.38 105.78 ;
     RECT  52.398 105.779 52.452 105.78 ;
     RECT  52.47 105.779 52.524 105.78 ;
     RECT  52.542 105.779 52.596 105.78 ;
     RECT  52.614 105.779 52.668 105.78 ;
     RECT  52.686 105.779 52.74 105.78 ;
     RECT  52.758 105.779 52.812 105.78 ;
     RECT  52.83 105.779 52.884 105.78 ;
     RECT  52.902 105.779 52.956 105.78 ;
     RECT  52.974 105.779 53.028 105.78 ;
     RECT  53.046 105.779 53.1 105.78 ;
     RECT  53.118 105.779 53.172 105.78 ;
     RECT  53.19 105.779 53.244 105.78 ;
     RECT  53.262 105.779 53.316 105.78 ;
     RECT  53.334 105.779 53.388 105.78 ;
     RECT  53.406 105.779 53.46 105.78 ;
     RECT  53.478 105.779 53.532 105.78 ;
     RECT  53.55 105.779 53.604 105.78 ;
     RECT  53.622 105.779 53.676 105.78 ;
     RECT  53.694 105.779 53.748 105.78 ;
     RECT  53.766 105.779 53.82 105.78 ;
     RECT  53.838 105.779 53.892 105.78 ;
     RECT  53.91 105.779 53.964 105.78 ;
     RECT  53.982 105.779 54.036 105.78 ;
     RECT  54.054 105.779 54.108 105.78 ;
     RECT  54.126 105.779 54.18 105.78 ;
     RECT  54.198 105.779 54.252 105.78 ;
     RECT  54.27 105.779 54.324 105.78 ;
     RECT  54.342 105.779 54.396 105.78 ;
     RECT  54.414 105.779 54.468 105.78 ;
     RECT  54.486 105.779 54.54 105.78 ;
     RECT  54.558 105.779 54.612 105.78 ;
     RECT  54.63 105.779 54.684 105.78 ;
     RECT  54.702 105.779 54.756 105.78 ;
     RECT  54.774 105.779 54.828 105.78 ;
     RECT  54.846 105.779 54.9 105.78 ;
     RECT  54.918 105.779 54.972 105.78 ;
     RECT  54.99 105.779 55.044 105.78 ;
     RECT  55.062 105.779 55.116 105.78 ;
     RECT  55.134 105.779 55.188 105.78 ;
     RECT  55.206 105.779 55.26 105.78 ;
     RECT  55.278 105.779 55.332 105.78 ;
     RECT  55.35 105.779 55.404 105.78 ;
     RECT  55.422 105.779 55.476 105.78 ;
     RECT  55.494 105.779 55.548 105.78 ;
     RECT  55.566 105.779 55.62 105.78 ;
     RECT  55.638 105.779 55.692 105.78 ;
     RECT  55.71 105.779 55.764 105.78 ;
     RECT  55.782 105.779 55.836 105.78 ;
     RECT  55.854 105.779 55.908 105.78 ;
     RECT  55.926 105.779 55.98 105.78 ;
     RECT  55.998 105.779 56.052 105.78 ;
     RECT  56.07 105.779 56.124 105.78 ;
     RECT  56.142 105.779 56.196 105.78 ;
     RECT  56.214 105.779 56.268 105.78 ;
     RECT  56.286 105.779 56.34 105.78 ;
     RECT  56.358 105.779 56.412 105.78 ;
     RECT  56.43 105.779 56.484 105.78 ;
     RECT  56.502 105.779 56.556 105.78 ;
     RECT  56.574 105.779 56.628 105.78 ;
     RECT  56.646 105.779 56.7 105.78 ;
     RECT  56.718 105.779 56.772 105.78 ;
     RECT  56.79 105.779 56.844 105.78 ;
     RECT  56.862 105.779 56.916 105.78 ;
     RECT  56.934 105.779 56.988 105.78 ;
     RECT  57.006 105.779 57.06 105.78 ;
     RECT  57.078 105.779 57.132 105.78 ;
     RECT  57.15 105.779 57.204 105.78 ;
     RECT  57.222 105.779 57.276 105.78 ;
     RECT  57.294 105.779 57.348 105.78 ;
     RECT  57.366 105.779 57.42 105.78 ;
     RECT  57.438 105.779 57.492 105.78 ;
     RECT  57.51 105.779 57.564 105.78 ;
     RECT  57.582 105.779 57.636 105.78 ;
     RECT  57.654 105.779 57.708 105.78 ;
     RECT  57.726 105.779 57.78 105.78 ;
     RECT  57.798 105.779 57.852 105.78 ;
     RECT  57.87 105.779 57.924 105.78 ;
     RECT  57.942 105.779 57.996 105.78 ;
     RECT  58.014 105.779 58.068 105.78 ;
     RECT  58.086 105.779 58.14 105.78 ;
     RECT  58.158 105.779 58.212 105.78 ;
     RECT  58.23 105.779 58.284 105.78 ;
     RECT  58.302 105.779 58.356 105.78 ;
     RECT  58.374 105.779 58.428 105.78 ;
     RECT  58.446 105.779 58.5 105.78 ;
     RECT  58.518 105.779 58.572 105.78 ;
     RECT  58.59 105.779 58.644 105.78 ;
     RECT  58.662 105.779 58.716 105.78 ;
     RECT  58.734 105.779 58.788 105.78 ;
     RECT  58.806 105.779 58.86 105.78 ;
     RECT  58.878 105.779 58.932 105.78 ;
     RECT  58.95 105.779 59.004 105.78 ;
     RECT  59.022 105.779 59.076 105.78 ;
     RECT  59.094 105.779 59.148 105.78 ;
     RECT  59.166 105.779 59.22 105.78 ;
     RECT  59.238 105.779 59.292 105.78 ;
     RECT  59.31 105.779 59.364 105.78 ;
     RECT  59.382 105.779 59.436 105.78 ;
     RECT  59.454 105.779 59.508 105.78 ;
     RECT  59.526 105.779 59.58 105.78 ;
     RECT  59.598 105.779 59.652 105.78 ;
     RECT  59.67 105.779 59.724 105.78 ;
     RECT  59.742 105.779 59.796 105.78 ;
     RECT  59.814 105.779 59.868 105.78 ;
     RECT  59.886 105.779 59.94 105.78 ;
     RECT  59.958 105.779 60.012 105.78 ;
     RECT  60.03 105.779 60.084 105.78 ;
     RECT  60.102 105.779 60.156 105.78 ;
     RECT  60.174 105.779 60.228 105.78 ;
     RECT  60.246 105.779 60.3 105.78 ;
     RECT  60.318 105.779 60.948 105.78 ;
     RECT  60.966 105.779 61.02 105.78 ;
     RECT  61.038 105.779 61.092 105.78 ;
     RECT  61.11 105.779 61.164 105.78 ;
     RECT  61.182 105.779 61.236 105.78 ;
     RECT  61.254 105.779 61.308 105.78 ;
     RECT  61.326 105.779 61.38 105.78 ;
     RECT  61.398 105.779 61.452 105.78 ;
     RECT  61.47 105.779 61.524 105.78 ;
     RECT  61.542 105.779 61.596 105.78 ;
     RECT  61.614 105.779 61.668 105.78 ;
     RECT  61.686 105.779 61.74 105.78 ;
     RECT  61.758 105.779 61.812 105.78 ;
     RECT  61.83 105.779 61.884 105.78 ;
     RECT  61.902 105.779 61.956 105.78 ;
     RECT  61.974 105.779 62.028 105.78 ;
     RECT  62.046 105.779 62.1 105.78 ;
     RECT  62.118 105.779 62.172 105.78 ;
     RECT  62.19 105.779 62.244 105.78 ;
     RECT  62.262 105.779 62.316 105.78 ;
     RECT  62.334 105.779 62.388 105.78 ;
     RECT  62.406 105.779 62.46 105.78 ;
     RECT  62.478 105.779 62.532 105.78 ;
     RECT  62.55 105.779 62.604 105.78 ;
     RECT  62.622 105.779 62.676 105.78 ;
     RECT  62.694 105.779 62.748 105.78 ;
     RECT  62.766 105.779 62.82 105.78 ;
     RECT  62.838 105.779 62.892 105.78 ;
     RECT  62.91 105.779 62.964 105.78 ;
     RECT  62.982 105.779 63.036 105.78 ;
     RECT  63.054 105.779 63.108 105.78 ;
     RECT  63.126 105.779 63.18 105.78 ;
     RECT  63.198 105.779 63.234 105.78 ;
     RECT  32.742 105.78 32.796 105.804 ;
     RECT  32.814 105.78 32.868 105.804 ;
     RECT  32.886 105.78 32.94 105.804 ;
     RECT  32.958 105.78 33.012 105.804 ;
     RECT  33.03 105.78 33.084 105.804 ;
     RECT  33.102 105.78 33.156 105.804 ;
     RECT  33.174 105.78 33.228 105.804 ;
     RECT  33.246 105.78 33.3 105.804 ;
     RECT  33.318 105.78 33.372 105.804 ;
     RECT  33.39 105.78 33.444 105.804 ;
     RECT  33.462 105.78 33.516 105.804 ;
     RECT  33.534 105.78 33.588 105.804 ;
     RECT  33.606 105.78 33.66 105.804 ;
     RECT  33.678 105.78 33.732 105.804 ;
     RECT  33.75 105.78 33.804 105.804 ;
     RECT  33.822 105.78 33.876 105.804 ;
     RECT  33.894 105.78 33.948 105.804 ;
     RECT  33.966 105.78 34.02 105.804 ;
     RECT  34.038 105.78 34.092 105.804 ;
     RECT  34.11 105.78 34.164 105.804 ;
     RECT  34.182 105.78 34.236 105.804 ;
     RECT  34.254 105.78 34.308 105.804 ;
     RECT  34.326 105.78 34.38 105.804 ;
     RECT  34.398 105.78 34.452 105.804 ;
     RECT  34.47 105.78 34.524 105.804 ;
     RECT  34.542 105.78 34.596 105.804 ;
     RECT  34.614 105.78 34.668 105.804 ;
     RECT  34.686 105.78 34.74 105.804 ;
     RECT  34.758 105.78 34.812 105.804 ;
     RECT  34.83 105.78 34.884 105.804 ;
     RECT  34.902 105.78 34.956 105.804 ;
     RECT  34.974 105.78 35.028 105.804 ;
     RECT  35.046 105.78 35.1 105.804 ;
     RECT  35.118 105.78 35.172 105.804 ;
     RECT  35.19 105.78 35.244 105.804 ;
     RECT  35.262 105.78 35.316 105.804 ;
     RECT  35.334 105.78 35.388 105.804 ;
     RECT  35.406 105.78 35.46 105.804 ;
     RECT  35.478 105.78 35.532 105.804 ;
     RECT  35.55 105.78 35.604 105.804 ;
     RECT  35.622 105.78 35.676 105.804 ;
     RECT  35.694 105.78 35.748 105.804 ;
     RECT  35.766 105.78 35.82 105.804 ;
     RECT  35.838 105.78 35.892 105.804 ;
     RECT  35.91 105.78 35.964 105.804 ;
     RECT  35.982 105.78 36.036 105.804 ;
     RECT  36.054 105.78 36.108 105.804 ;
     RECT  36.126 105.78 36.18 105.804 ;
     RECT  36.198 105.78 36.252 105.804 ;
     RECT  36.27 105.78 36.324 105.804 ;
     RECT  36.342 105.78 36.396 105.804 ;
     RECT  36.414 105.78 36.468 105.804 ;
     RECT  36.486 105.78 36.54 105.804 ;
     RECT  36.558 105.78 36.612 105.804 ;
     RECT  36.63 105.78 36.684 105.804 ;
     RECT  36.702 105.78 36.756 105.804 ;
     RECT  36.774 105.78 36.828 105.804 ;
     RECT  36.846 105.78 36.9 105.804 ;
     RECT  36.918 105.78 36.972 105.804 ;
     RECT  36.99 105.78 37.044 105.804 ;
     RECT  37.062 105.78 37.116 105.804 ;
     RECT  37.134 105.78 37.188 105.804 ;
     RECT  37.206 105.78 37.26 105.804 ;
     RECT  37.278 105.78 37.332 105.804 ;
     RECT  37.35 105.78 37.404 105.804 ;
     RECT  37.422 105.78 37.476 105.804 ;
     RECT  37.494 105.78 37.548 105.804 ;
     RECT  37.566 105.78 37.62 105.804 ;
     RECT  37.638 105.78 37.692 105.804 ;
     RECT  37.71 105.78 37.764 105.804 ;
     RECT  37.782 105.78 37.836 105.804 ;
     RECT  37.854 105.78 37.908 105.804 ;
     RECT  37.926 105.78 37.98 105.804 ;
     RECT  37.998 105.78 38.052 105.804 ;
     RECT  38.07 105.78 38.124 105.804 ;
     RECT  38.142 105.78 38.196 105.804 ;
     RECT  38.214 105.78 38.268 105.804 ;
     RECT  38.286 105.78 38.34 105.804 ;
     RECT  38.358 105.78 38.412 105.804 ;
     RECT  38.43 105.78 38.484 105.804 ;
     RECT  38.502 105.78 38.556 105.804 ;
     RECT  38.574 105.78 38.628 105.804 ;
     RECT  38.646 105.78 38.7 105.804 ;
     RECT  38.718 105.78 38.772 105.804 ;
     RECT  38.79 105.78 38.844 105.804 ;
     RECT  38.862 105.78 38.916 105.804 ;
     RECT  38.934 105.78 38.988 105.804 ;
     RECT  39.006 105.78 39.06 105.804 ;
     RECT  39.078 105.78 39.132 105.804 ;
     RECT  39.15 105.78 39.204 105.804 ;
     RECT  39.222 105.78 39.276 105.804 ;
     RECT  39.294 105.78 39.348 105.804 ;
     RECT  39.366 105.78 39.42 105.804 ;
     RECT  39.438 105.78 39.492 105.804 ;
     RECT  39.51 105.78 39.564 105.804 ;
     RECT  39.582 105.78 39.636 105.804 ;
     RECT  39.654 105.78 39.708 105.804 ;
     RECT  39.726 105.78 39.78 105.804 ;
     RECT  39.798 105.78 39.852 105.804 ;
     RECT  39.87 105.78 39.924 105.804 ;
     RECT  39.942 105.78 39.996 105.804 ;
     RECT  40.014 105.78 40.068 105.804 ;
     RECT  40.086 105.78 40.14 105.804 ;
     RECT  40.158 105.78 40.212 105.804 ;
     RECT  40.23 105.78 40.284 105.804 ;
     RECT  40.302 105.78 40.356 105.804 ;
     RECT  40.374 105.78 40.428 105.804 ;
     RECT  40.446 105.78 40.5 105.804 ;
     RECT  40.518 105.78 40.572 105.804 ;
     RECT  40.59 105.78 40.644 105.804 ;
     RECT  40.662 105.78 40.716 105.804 ;
     RECT  40.734 105.78 40.788 105.804 ;
     RECT  40.806 105.78 40.86 105.804 ;
     RECT  40.878 105.78 40.932 105.804 ;
     RECT  40.95 105.78 41.004 105.804 ;
     RECT  41.022 105.78 41.076 105.804 ;
     RECT  41.094 105.78 41.148 105.804 ;
     RECT  41.166 105.78 41.22 105.804 ;
     RECT  41.238 105.78 41.292 105.804 ;
     RECT  41.31 105.78 41.364 105.804 ;
     RECT  41.382 105.78 41.436 105.804 ;
     RECT  41.454 105.78 41.508 105.804 ;
     RECT  41.526 105.78 41.58 105.804 ;
     RECT  41.598 105.78 41.652 105.804 ;
     RECT  41.67 105.78 41.724 105.804 ;
     RECT  41.742 105.78 41.796 105.804 ;
     RECT  41.814 105.78 41.868 105.804 ;
     RECT  41.886 105.78 41.94 105.804 ;
     RECT  41.958 105.78 42.012 105.804 ;
     RECT  42.03 105.78 42.084 105.804 ;
     RECT  42.102 105.78 42.156 105.804 ;
     RECT  42.174 105.78 42.228 105.804 ;
     RECT  42.246 105.78 42.3 105.804 ;
     RECT  42.318 105.78 42.372 105.804 ;
     RECT  42.39 105.78 42.444 105.804 ;
     RECT  42.462 105.78 42.516 105.804 ;
     RECT  42.534 105.78 42.588 105.804 ;
     RECT  42.606 105.78 42.66 105.804 ;
     RECT  42.678 105.78 42.732 105.804 ;
     RECT  42.75 105.78 42.804 105.804 ;
     RECT  42.822 105.78 42.876 105.804 ;
     RECT  42.894 105.78 42.948 105.804 ;
     RECT  42.966 105.78 43.02 105.804 ;
     RECT  43.038 105.78 43.092 105.804 ;
     RECT  43.11 105.78 43.164 105.804 ;
     RECT  43.182 105.78 43.236 105.804 ;
     RECT  43.254 105.78 43.308 105.804 ;
     RECT  43.326 105.78 43.38 105.804 ;
     RECT  43.398 105.78 43.452 105.804 ;
     RECT  43.47 105.78 43.524 105.804 ;
     RECT  43.542 105.78 43.596 105.804 ;
     RECT  43.614 105.78 43.668 105.804 ;
     RECT  43.686 105.78 43.74 105.804 ;
     RECT  43.758 105.78 43.812 105.804 ;
     RECT  43.83 105.78 43.884 105.804 ;
     RECT  43.902 105.78 43.956 105.804 ;
     RECT  43.974 105.78 44.028 105.804 ;
     RECT  44.046 105.78 44.1 105.804 ;
     RECT  44.118 105.78 44.172 105.804 ;
     RECT  44.19 105.78 44.244 105.804 ;
     RECT  44.262 105.78 44.316 105.804 ;
     RECT  44.334 105.78 44.388 105.804 ;
     RECT  44.406 105.78 44.46 105.804 ;
     RECT  44.478 105.78 44.532 105.804 ;
     RECT  44.55 105.78 44.604 105.804 ;
     RECT  44.622 105.78 44.676 105.804 ;
     RECT  44.694 105.78 44.748 105.804 ;
     RECT  44.766 105.78 44.82 105.804 ;
     RECT  44.838 105.78 44.892 105.804 ;
     RECT  44.91 105.78 44.964 105.804 ;
     RECT  44.982 105.78 45.036 105.804 ;
     RECT  45.054 105.78 45.108 105.804 ;
     RECT  45.126 105.78 45.18 105.804 ;
     RECT  45.198 105.78 45.252 105.804 ;
     RECT  45.27 105.78 45.324 105.804 ;
     RECT  45.342 105.78 45.396 105.804 ;
     RECT  45.414 105.78 45.468 105.804 ;
     RECT  45.486 105.78 45.54 105.804 ;
     RECT  45.558 105.78 45.612 105.804 ;
     RECT  45.63 105.78 45.684 105.804 ;
     RECT  45.702 105.78 45.756 105.804 ;
     RECT  45.774 105.78 45.828 105.804 ;
     RECT  45.846 105.78 45.9 105.804 ;
     RECT  45.918 105.78 46.548 105.804 ;
     RECT  46.566 105.78 46.62 105.804 ;
     RECT  46.638 105.78 46.692 105.804 ;
     RECT  46.71 105.78 46.764 105.804 ;
     RECT  46.782 105.78 46.836 105.804 ;
     RECT  46.854 105.78 46.908 105.804 ;
     RECT  46.926 105.78 46.98 105.804 ;
     RECT  46.998 105.78 47.052 105.804 ;
     RECT  47.07 105.78 47.124 105.804 ;
     RECT  47.142 105.78 47.196 105.804 ;
     RECT  47.214 105.78 47.268 105.804 ;
     RECT  47.286 105.78 47.34 105.804 ;
     RECT  47.358 105.78 47.412 105.804 ;
     RECT  47.43 105.78 47.484 105.804 ;
     RECT  47.502 105.78 47.556 105.804 ;
     RECT  47.574 105.78 47.628 105.804 ;
     RECT  47.646 105.78 47.7 105.804 ;
     RECT  47.718 105.78 47.772 105.804 ;
     RECT  47.79 105.78 47.844 105.804 ;
     RECT  47.862 105.78 47.916 105.804 ;
     RECT  47.934 105.78 47.988 105.804 ;
     RECT  48.006 105.78 48.06 105.804 ;
     RECT  48.078 105.78 48.132 105.804 ;
     RECT  48.15 105.78 48.204 105.804 ;
     RECT  48.222 105.78 48.276 105.804 ;
     RECT  48.294 105.78 48.348 105.804 ;
     RECT  48.366 105.78 48.42 105.804 ;
     RECT  48.438 105.78 48.492 105.804 ;
     RECT  48.51 105.78 48.564 105.804 ;
     RECT  48.582 105.78 48.636 105.804 ;
     RECT  48.654 105.78 48.708 105.804 ;
     RECT  48.726 105.78 48.78 105.804 ;
     RECT  48.798 105.78 48.852 105.804 ;
     RECT  48.87 105.78 48.924 105.804 ;
     RECT  48.942 105.78 48.996 105.804 ;
     RECT  49.014 105.78 49.068 105.804 ;
     RECT  49.086 105.78 49.14 105.804 ;
     RECT  49.158 105.78 49.212 105.804 ;
     RECT  49.23 105.78 49.284 105.804 ;
     RECT  49.302 105.78 49.356 105.804 ;
     RECT  49.374 105.78 49.428 105.804 ;
     RECT  49.446 105.78 49.5 105.804 ;
     RECT  49.518 105.78 49.572 105.804 ;
     RECT  49.59 105.78 49.644 105.804 ;
     RECT  49.662 105.78 49.716 105.804 ;
     RECT  49.734 105.78 49.788 105.804 ;
     RECT  49.806 105.78 49.86 105.804 ;
     RECT  49.878 105.78 49.932 105.804 ;
     RECT  49.95 105.78 50.004 105.804 ;
     RECT  50.022 105.78 50.076 105.804 ;
     RECT  50.094 105.78 50.148 105.804 ;
     RECT  50.166 105.78 50.22 105.804 ;
     RECT  50.238 105.78 50.292 105.804 ;
     RECT  50.31 105.78 50.364 105.804 ;
     RECT  50.382 105.78 50.436 105.804 ;
     RECT  50.454 105.78 50.508 105.804 ;
     RECT  50.526 105.78 50.58 105.804 ;
     RECT  50.598 105.78 50.652 105.804 ;
     RECT  50.67 105.78 50.724 105.804 ;
     RECT  50.742 105.78 50.796 105.804 ;
     RECT  50.814 105.78 50.868 105.804 ;
     RECT  50.886 105.78 50.94 105.804 ;
     RECT  50.958 105.78 51.012 105.804 ;
     RECT  51.03 105.78 51.084 105.804 ;
     RECT  51.102 105.78 51.156 105.804 ;
     RECT  51.174 105.78 51.228 105.804 ;
     RECT  51.246 105.78 51.3 105.804 ;
     RECT  51.318 105.78 51.372 105.804 ;
     RECT  51.39 105.78 51.444 105.804 ;
     RECT  51.462 105.78 51.516 105.804 ;
     RECT  51.534 105.78 51.588 105.804 ;
     RECT  51.606 105.78 51.66 105.804 ;
     RECT  51.678 105.78 51.732 105.804 ;
     RECT  51.75 105.78 51.804 105.804 ;
     RECT  51.822 105.78 51.876 105.804 ;
     RECT  51.894 105.78 51.948 105.804 ;
     RECT  51.966 105.78 52.02 105.804 ;
     RECT  52.038 105.78 52.092 105.804 ;
     RECT  52.11 105.78 52.164 105.804 ;
     RECT  52.182 105.78 52.236 105.804 ;
     RECT  52.254 105.78 52.308 105.804 ;
     RECT  52.326 105.78 52.38 105.804 ;
     RECT  52.398 105.78 52.452 105.804 ;
     RECT  52.47 105.78 52.524 105.804 ;
     RECT  52.542 105.78 52.596 105.804 ;
     RECT  52.614 105.78 52.668 105.804 ;
     RECT  52.686 105.78 52.74 105.804 ;
     RECT  52.758 105.78 52.812 105.804 ;
     RECT  52.83 105.78 52.884 105.804 ;
     RECT  52.902 105.78 52.956 105.804 ;
     RECT  52.974 105.78 53.028 105.804 ;
     RECT  53.046 105.78 53.1 105.804 ;
     RECT  53.118 105.78 53.172 105.804 ;
     RECT  53.19 105.78 53.244 105.804 ;
     RECT  53.262 105.78 53.316 105.804 ;
     RECT  53.334 105.78 53.388 105.804 ;
     RECT  53.406 105.78 53.46 105.804 ;
     RECT  53.478 105.78 53.532 105.804 ;
     RECT  53.55 105.78 53.604 105.804 ;
     RECT  53.622 105.78 53.676 105.804 ;
     RECT  53.694 105.78 53.748 105.804 ;
     RECT  53.766 105.78 53.82 105.804 ;
     RECT  53.838 105.78 53.892 105.804 ;
     RECT  53.91 105.78 53.964 105.804 ;
     RECT  53.982 105.78 54.036 105.804 ;
     RECT  54.054 105.78 54.108 105.804 ;
     RECT  54.126 105.78 54.18 105.804 ;
     RECT  54.198 105.78 54.252 105.804 ;
     RECT  54.27 105.78 54.324 105.804 ;
     RECT  54.342 105.78 54.396 105.804 ;
     RECT  54.414 105.78 54.468 105.804 ;
     RECT  54.486 105.78 54.54 105.804 ;
     RECT  54.558 105.78 54.612 105.804 ;
     RECT  54.63 105.78 54.684 105.804 ;
     RECT  54.702 105.78 54.756 105.804 ;
     RECT  54.774 105.78 54.828 105.804 ;
     RECT  54.846 105.78 54.9 105.804 ;
     RECT  54.918 105.78 54.972 105.804 ;
     RECT  54.99 105.78 55.044 105.804 ;
     RECT  55.062 105.78 55.116 105.804 ;
     RECT  55.134 105.78 55.188 105.804 ;
     RECT  55.206 105.78 55.26 105.804 ;
     RECT  55.278 105.78 55.332 105.804 ;
     RECT  55.35 105.78 55.404 105.804 ;
     RECT  55.422 105.78 55.476 105.804 ;
     RECT  55.494 105.78 55.548 105.804 ;
     RECT  55.566 105.78 55.62 105.804 ;
     RECT  55.638 105.78 55.692 105.804 ;
     RECT  55.71 105.78 55.764 105.804 ;
     RECT  55.782 105.78 55.836 105.804 ;
     RECT  55.854 105.78 55.908 105.804 ;
     RECT  55.926 105.78 55.98 105.804 ;
     RECT  55.998 105.78 56.052 105.804 ;
     RECT  56.07 105.78 56.124 105.804 ;
     RECT  56.142 105.78 56.196 105.804 ;
     RECT  56.214 105.78 56.268 105.804 ;
     RECT  56.286 105.78 56.34 105.804 ;
     RECT  56.358 105.78 56.412 105.804 ;
     RECT  56.43 105.78 56.484 105.804 ;
     RECT  56.502 105.78 56.556 105.804 ;
     RECT  56.574 105.78 56.628 105.804 ;
     RECT  56.646 105.78 56.7 105.804 ;
     RECT  56.718 105.78 56.772 105.804 ;
     RECT  56.79 105.78 56.844 105.804 ;
     RECT  56.862 105.78 56.916 105.804 ;
     RECT  56.934 105.78 56.988 105.804 ;
     RECT  57.006 105.78 57.06 105.804 ;
     RECT  57.078 105.78 57.132 105.804 ;
     RECT  57.15 105.78 57.204 105.804 ;
     RECT  57.222 105.78 57.276 105.804 ;
     RECT  57.294 105.78 57.348 105.804 ;
     RECT  57.366 105.78 57.42 105.804 ;
     RECT  57.438 105.78 57.492 105.804 ;
     RECT  57.51 105.78 57.564 105.804 ;
     RECT  57.582 105.78 57.636 105.804 ;
     RECT  57.654 105.78 57.708 105.804 ;
     RECT  57.726 105.78 57.78 105.804 ;
     RECT  57.798 105.78 57.852 105.804 ;
     RECT  57.87 105.78 57.924 105.804 ;
     RECT  57.942 105.78 57.996 105.804 ;
     RECT  58.014 105.78 58.068 105.804 ;
     RECT  58.086 105.78 58.14 105.804 ;
     RECT  58.158 105.78 58.212 105.804 ;
     RECT  58.23 105.78 58.284 105.804 ;
     RECT  58.302 105.78 58.356 105.804 ;
     RECT  58.374 105.78 58.428 105.804 ;
     RECT  58.446 105.78 58.5 105.804 ;
     RECT  58.518 105.78 58.572 105.804 ;
     RECT  58.59 105.78 58.644 105.804 ;
     RECT  58.662 105.78 58.716 105.804 ;
     RECT  58.734 105.78 58.788 105.804 ;
     RECT  58.806 105.78 58.86 105.804 ;
     RECT  58.878 105.78 58.932 105.804 ;
     RECT  58.95 105.78 59.004 105.804 ;
     RECT  59.022 105.78 59.076 105.804 ;
     RECT  59.094 105.78 59.148 105.804 ;
     RECT  59.166 105.78 59.22 105.804 ;
     RECT  59.238 105.78 59.292 105.804 ;
     RECT  59.31 105.78 59.364 105.804 ;
     RECT  59.382 105.78 59.436 105.804 ;
     RECT  59.454 105.78 59.508 105.804 ;
     RECT  59.526 105.78 59.58 105.804 ;
     RECT  59.598 105.78 59.652 105.804 ;
     RECT  59.67 105.78 59.724 105.804 ;
     RECT  59.742 105.78 59.796 105.804 ;
     RECT  59.814 105.78 59.868 105.804 ;
     RECT  59.886 105.78 59.94 105.804 ;
     RECT  59.958 105.78 60.012 105.804 ;
     RECT  60.03 105.78 60.084 105.804 ;
     RECT  60.102 105.78 60.156 105.804 ;
     RECT  60.174 105.78 60.228 105.804 ;
     RECT  60.246 105.78 60.3 105.804 ;
     RECT  60.318 105.78 60.948 105.804 ;
     RECT  60.966 105.78 61.02 105.804 ;
     RECT  61.038 105.78 61.092 105.804 ;
     RECT  61.11 105.78 61.164 105.804 ;
     RECT  61.182 105.78 61.236 105.804 ;
     RECT  61.254 105.78 61.308 105.804 ;
     RECT  61.326 105.78 61.38 105.804 ;
     RECT  61.398 105.78 61.452 105.804 ;
     RECT  61.47 105.78 61.524 105.804 ;
     RECT  61.542 105.78 61.596 105.804 ;
     RECT  61.614 105.78 61.668 105.804 ;
     RECT  61.686 105.78 61.74 105.804 ;
     RECT  61.758 105.78 61.812 105.804 ;
     RECT  61.83 105.78 61.884 105.804 ;
     RECT  61.902 105.78 61.956 105.804 ;
     RECT  61.974 105.78 62.028 105.804 ;
     RECT  62.046 105.78 62.1 105.804 ;
     RECT  62.118 105.78 62.172 105.804 ;
     RECT  62.19 105.78 62.244 105.804 ;
     RECT  62.262 105.78 62.316 105.804 ;
     RECT  62.334 105.78 62.388 105.804 ;
     RECT  62.406 105.78 62.46 105.804 ;
     RECT  62.478 105.78 62.532 105.804 ;
     RECT  62.55 105.78 62.604 105.804 ;
     RECT  62.622 105.78 62.676 105.804 ;
     RECT  62.694 105.78 62.748 105.804 ;
     RECT  62.766 105.78 62.82 105.804 ;
     RECT  62.838 105.78 62.892 105.804 ;
     RECT  62.91 105.78 62.964 105.804 ;
     RECT  62.982 105.78 63.036 105.804 ;
     RECT  63.054 105.78 63.108 105.804 ;
     RECT  63.126 105.78 63.18 105.804 ;
    LAYER M4 ;
     RECT  0.084 55.248 0.133 55.272 ;
     RECT  0.06 55.272 0.133 55.344 ;
     RECT  0.084 55.344 0.133 55.368 ;
     RECT  0.06 55.368 0.133 55.44 ;
     RECT  0.084 55.44 0.133 55.464 ;
     RECT  0.133 55.152 2.252 55.464 ;
     RECT  2.252 54.72 2.293 55.464 ;
     RECT  2.293 54.72 2.408 56.616 ;
     RECT  2.408 2.148 2.512 103.152 ;
     RECT  2.512 2.418 2.6 103.152 ;
     RECT  2.6 2.418 2.704 103.422 ;
     RECT  2.704 54.432 3.529 56.616 ;
     RECT  3.529 56.592 3.875 56.616 ;
     RECT  3.529 54.432 3.881 55.272 ;
     RECT  3.881 55.008 3.916 55.272 ;
     RECT  3.916 55.152 4.025 55.272 ;
     RECT  4.025 55.248 4.669 55.272 ;
     RECT  4.669 55.248 5.108 55.848 ;
     RECT  4.693 91.872 5.108 91.896 ;
     RECT  2.704 94.368 5.108 94.392 ;
     RECT  5.108 2.148 5.212 103.152 ;
     RECT  5.212 2.418 5.3 103.152 ;
     RECT  5.3 2.418 5.404 103.422 ;
     RECT  5.404 91.872 7.808 91.896 ;
     RECT  5.404 94.368 7.808 94.392 ;
     RECT  7.808 2.148 7.912 103.152 ;
     RECT  7.912 2.418 8 103.152 ;
     RECT  8 2.418 8.104 103.422 ;
     RECT  8.104 91.872 10.508 91.896 ;
     RECT  8.104 94.368 10.508 94.392 ;
     RECT  10.508 2.148 10.612 103.152 ;
     RECT  10.612 2.418 10.7 103.152 ;
     RECT  10.7 2.418 10.804 103.422 ;
     RECT  10.804 91.872 13.208 91.896 ;
     RECT  10.804 94.368 13.208 94.392 ;
     RECT  13.208 2.148 13.312 103.152 ;
     RECT  13.312 2.418 13.4 103.152 ;
     RECT  13.4 2.418 13.504 103.422 ;
     RECT  13.504 91.872 15.908 91.896 ;
     RECT  13.504 94.368 15.908 94.392 ;
     RECT  15.908 2.148 16.012 103.152 ;
     RECT  16.012 2.418 16.1 103.152 ;
     RECT  16.1 2.418 16.204 103.422 ;
     RECT  16.204 91.872 18.608 91.896 ;
     RECT  16.204 94.368 18.608 94.392 ;
     RECT  18.608 2.148 18.712 103.152 ;
     RECT  18.712 2.418 18.8 103.152 ;
     RECT  18.8 2.418 18.904 103.422 ;
     RECT  20.221 79.632 20.941 79.656 ;
     RECT  20.941 79.632 21.308 79.8 ;
     RECT  18.904 91.872 21.308 91.896 ;
     RECT  18.904 94.368 21.308 94.392 ;
     RECT  21.308 2.148 21.412 103.152 ;
     RECT  21.412 2.418 21.5 103.152 ;
     RECT  21.5 2.418 21.604 103.422 ;
     RECT  21.604 79.44 24.008 79.8 ;
     RECT  21.604 91.872 24.008 91.896 ;
     RECT  21.604 94.368 24.008 94.392 ;
     RECT  24.008 2.148 24.112 103.152 ;
     RECT  24.112 2.418 24.2 103.152 ;
     RECT  24.2 2.418 24.304 103.422 ;
     RECT  24.304 79.44 26.708 79.8 ;
     RECT  24.304 91.872 26.708 91.896 ;
     RECT  24.304 94.368 26.708 94.392 ;
     RECT  26.708 2.148 26.812 103.152 ;
     RECT  26.812 2.418 26.9 103.152 ;
     RECT  26.9 2.418 27.004 103.422 ;
     RECT  27.004 79.44 27.395 79.8 ;
     RECT  27.004 90.576 27.901 92.04 ;
     RECT  27.004 98.928 28.741 98.952 ;
     RECT  27.004 100.272 28.741 100.296 ;
     RECT  27.395 79.776 29.408 79.8 ;
     RECT  27.901 91.296 29.408 92.04 ;
     RECT  27.004 94.368 29.408 94.392 ;
     RECT  28.741 98.928 29.408 100.296 ;
     RECT  29.408 2.148 29.512 103.152 ;
     RECT  29.512 2.418 29.6 103.152 ;
     RECT  29.6 2.418 29.704 103.422 ;
     RECT  29.704 98.928 31.909 100.296 ;
     RECT  31.885 101.616 31.909 101.64 ;
     RECT  31.909 98.928 32.065 101.64 ;
     RECT  31.993 102.672 32.065 102.696 ;
     RECT  29.704 79.776 32.108 79.8 ;
     RECT  29.704 91.296 32.108 91.32 ;
     RECT  31.909 93.264 32.108 93.288 ;
     RECT  29.704 94.368 32.108 94.392 ;
     RECT  32.065 98.928 32.108 102.696 ;
     RECT  32.108 2.148 32.212 103.152 ;
     RECT  32.212 2.418 32.3 103.152 ;
     RECT  32.3 2.418 32.404 103.422 ;
     RECT  32.404 98.88 33.788 102.696 ;
     RECT  33.788 98.736 34.021 102.696 ;
     RECT  34.021 46.848 34.069 46.872 ;
     RECT  34.069 46.032 34.117 46.872 ;
     RECT  33.973 105.744 34.193 105.768 ;
     RECT  34.021 98.736 34.549 103.08 ;
     RECT  34.117 45.504 34.808 46.872 ;
     RECT  32.404 79.776 34.808 79.8 ;
     RECT  32.404 93.264 34.808 93.288 ;
     RECT  32.404 94.368 34.808 94.392 ;
     RECT  34.549 98.736 34.808 103.752 ;
     RECT  34.808 2.148 34.877 103.752 ;
     RECT  34.877 2.148 34.912 103.422 ;
     RECT  34.912 2.418 35.104 103.422 ;
     RECT  35.161 105.744 35.309 105.768 ;
     RECT  35.104 97.968 35.932 103.32 ;
     RECT  36.025 105.696 36.133 105.72 ;
     RECT  36.133 105.648 36.245 105.72 ;
     RECT  36.245 105.648 36.425 105.672 ;
     RECT  36.133 52.224 36.469 52.248 ;
     RECT  36.469 52.176 36.613 52.248 ;
     RECT  35.104 51.168 36.757 51.192 ;
     RECT  36.613 52.176 36.757 52.296 ;
     RECT  35.932 98.688 37.093 103.32 ;
     RECT  36.517 56.256 37.333 56.28 ;
     RECT  35.104 45.504 37.381 47.112 ;
     RECT  35.104 48.192 37.381 48.216 ;
     RECT  37.381 45.504 37.508 48.216 ;
     RECT  36.181 50.112 37.508 50.136 ;
     RECT  36.757 51.168 37.508 52.296 ;
     RECT  36.085 53.856 37.508 53.88 ;
     RECT  37.333 56.256 37.508 56.808 ;
     RECT  37.141 60 37.508 60.024 ;
     RECT  36.661 63.504 37.508 63.528 ;
     RECT  36.805 69.216 37.508 69.24 ;
     RECT  37.189 70.368 37.508 70.392 ;
     RECT  36.709 73.344 37.508 73.368 ;
     RECT  35.104 79.776 37.508 79.8 ;
     RECT  36.277 86.304 37.508 86.328 ;
     RECT  36.421 89.76 37.508 89.784 ;
     RECT  36.373 90.864 37.508 90.888 ;
     RECT  35.104 93.264 37.508 93.288 ;
     RECT  35.104 94.368 37.508 94.392 ;
     RECT  37.093 97.968 37.508 103.32 ;
     RECT  37.508 2.148 37.612 103.32 ;
     RECT  37.612 2.418 37.7 103.32 ;
     RECT  37.7 2.418 37.804 103.422 ;
     RECT  37.804 97.92 38.003 103.224 ;
     RECT  37.804 90.864 38.051 91.752 ;
     RECT  37.804 88.944 38.513 89.784 ;
     RECT  37.804 82.608 38.531 82.632 ;
     RECT  37.897 105.744 38.693 105.768 ;
     RECT  37.804 45.408 38.801 48.216 ;
     RECT  37.804 50.112 38.801 51.192 ;
     RECT  37.804 58.368 38.801 58.488 ;
     RECT  37.804 61.872 38.801 61.992 ;
     RECT  37.804 73.344 38.801 73.512 ;
     RECT  37.804 94.368 38.965 94.392 ;
     RECT  37.804 68.112 39.013 68.136 ;
     RECT  37.804 69.216 39.013 69.24 ;
     RECT  37.804 86.304 39.061 86.328 ;
     RECT  37.804 87.744 39.061 87.768 ;
     RECT  38.801 61.968 39.205 61.992 ;
     RECT  37.804 56.208 39.253 57.336 ;
     RECT  38.801 51.168 39.349 51.192 ;
     RECT  37.804 52.176 39.349 53.88 ;
     RECT  38.003 98.016 39.397 103.224 ;
     RECT  39.397 97.44 39.481 103.224 ;
     RECT  37.804 79.776 39.548 79.8 ;
     RECT  39.013 68.112 39.637 69.24 ;
     RECT  37.804 70.368 39.637 70.392 ;
     RECT  38.797 105.6 39.737 105.624 ;
     RECT  38.965 94.368 39.829 95.16 ;
     RECT  39.481 96.912 39.949 103.224 ;
     RECT  37.804 60 39.973 60.024 ;
     RECT  39.253 55.728 40.021 57.336 ;
     RECT  38.801 58.416 40.021 58.488 ;
     RECT  38.869 43.296 40.208 43.32 ;
     RECT  38.801 45.504 40.208 48.216 ;
     RECT  38.801 50.112 40.208 50.136 ;
     RECT  39.349 51.168 40.208 53.88 ;
     RECT  40.021 55.728 40.208 58.488 ;
     RECT  39.973 59.52 40.208 60.024 ;
     RECT  39.205 61.968 40.208 62.136 ;
     RECT  37.804 63.504 40.208 63.528 ;
     RECT  39.157 64.944 40.208 64.968 ;
     RECT  39.637 68.112 40.208 70.392 ;
     RECT  38.801 73.344 40.208 73.368 ;
     RECT  39.925 74.64 40.208 74.664 ;
     RECT  39.548 79.776 40.208 79.848 ;
     RECT  37.804 84.912 40.208 84.936 ;
     RECT  39.061 86.304 40.208 87.768 ;
     RECT  38.513 89.76 40.208 89.784 ;
     RECT  38.051 90.864 40.208 90.888 ;
     RECT  37.804 93.264 40.208 93.288 ;
     RECT  39.829 94.368 40.208 95.496 ;
     RECT  39.949 96.912 40.208 103.272 ;
     RECT  40.208 2.148 40.312 103.272 ;
     RECT  40.312 2.418 40.4 103.272 ;
     RECT  40.4 2.418 40.417 103.422 ;
     RECT  40.417 2.418 40.504 103.752 ;
     RECT  40.504 69.216 40.673 70.008 ;
     RECT  40.504 93.264 40.781 95.16 ;
     RECT  40.504 74.64 40.817 74.664 ;
     RECT  39.985 105.696 40.817 105.768 ;
     RECT  40.817 105.744 40.835 105.768 ;
     RECT  40.504 97.632 41.123 103.752 ;
     RECT  40.504 51.168 41.249 54.168 ;
     RECT  40.504 86.304 41.357 86.616 ;
     RECT  40.504 55.152 41.363 60.12 ;
     RECT  41.123 97.632 41.564 103.272 ;
     RECT  41.564 97.056 41.605 103.272 ;
     RECT  40.504 67.776 41.681 68.136 ;
     RECT  40.504 79.776 41.891 79.8 ;
     RECT  40.673 69.216 41.897 69.24 ;
     RECT  41.605 96.864 42.325 103.272 ;
     RECT  41.965 105.648 42.401 105.672 ;
     RECT  40.504 50.112 42.469 50.136 ;
     RECT  41.249 51.168 42.469 53.88 ;
     RECT  41.893 95.712 42.565 95.736 ;
     RECT  42.325 96.72 42.565 103.272 ;
     RECT  40.504 63.504 42.613 63.528 ;
     RECT  41.509 72.144 42.661 72.168 ;
     RECT  40.504 89.76 42.696 90.888 ;
     RECT  41.653 92.208 42.696 92.232 ;
     RECT  42.696 89.76 42.721 92.232 ;
     RECT  40.781 93.264 42.721 94.392 ;
     RECT  41.363 55.152 42.757 58.488 ;
     RECT  42.696 87.792 42.793 87.816 ;
     RECT  41.357 86.304 42.865 86.328 ;
     RECT  40.504 45.504 42.908 48.216 ;
     RECT  42.469 50.112 42.908 53.88 ;
     RECT  42.757 54.912 42.908 58.488 ;
     RECT  41.363 59.52 42.908 60.12 ;
     RECT  40.504 61.968 42.908 61.992 ;
     RECT  42.613 63.504 42.908 64.152 ;
     RECT  41.681 68.112 42.908 68.136 ;
     RECT  42.661 71.184 42.908 72.168 ;
     RECT  40.504 73.344 42.908 73.56 ;
     RECT  42.757 79.008 42.908 79.224 ;
     RECT  40.504 84.912 42.908 84.936 ;
     RECT  42.865 86.304 42.908 86.664 ;
     RECT  42.793 87.648 42.908 87.816 ;
     RECT  42.721 89.76 42.908 94.392 ;
     RECT  42.565 95.712 42.908 103.272 ;
     RECT  42.908 2.148 43.012 103.272 ;
     RECT  43.012 2.418 43.1 103.272 ;
     RECT  43.1 2.418 43.204 103.422 ;
     RECT  43.204 87.648 43.331 87.816 ;
     RECT  43.204 77.28 43.373 77.4 ;
     RECT  43.204 79.008 43.427 79.032 ;
     RECT  43.204 82.656 43.427 82.776 ;
     RECT  43.331 87.744 43.427 87.816 ;
     RECT  43.204 89.76 43.427 93.336 ;
     RECT  43.427 92.208 43.445 93.336 ;
     RECT  43.427 82.656 43.468 82.68 ;
     RECT  43.204 71.184 43.805 72.264 ;
     RECT  43.585 105.744 43.805 105.768 ;
     RECT  43.204 50.112 43.913 58.488 ;
     RECT  43.441 104.304 43.957 104.328 ;
     RECT  43.204 73.344 44.245 74.424 ;
     RECT  43.204 63.504 44.341 64.152 ;
     RECT  43.913 50.688 44.345 58.488 ;
     RECT  43.204 37.104 44.377 37.896 ;
     RECT  43.204 94.368 44.389 103.08 ;
     RECT  44.389 94.368 44.881 103.32 ;
     RECT  43.957 104.304 44.881 104.376 ;
     RECT  44.245 73.296 45.061 74.424 ;
     RECT  43.204 84.912 45.109 84.936 ;
     RECT  44.881 94.368 45.169 104.376 ;
     RECT  44.965 105.744 45.169 105.768 ;
     RECT  43.805 71.664 45.205 72.264 ;
     RECT  45.061 73.248 45.205 74.424 ;
     RECT  44.377 37.104 45.277 37.944 ;
     RECT  45.277 37.104 45.313 37.992 ;
     RECT  45.169 94.368 45.461 105.768 ;
     RECT  45.313 37.104 45.608 38.184 ;
     RECT  43.204 45.504 45.608 48.216 ;
     RECT  44.345 51.168 45.608 58.488 ;
     RECT  43.204 59.52 45.608 60.12 ;
     RECT  43.204 61.968 45.608 61.992 ;
     RECT  44.341 63.504 45.608 64.728 ;
     RECT  45.397 66.48 45.608 66.504 ;
     RECT  43.204 68.112 45.608 68.136 ;
     RECT  43.204 69.408 45.608 69.528 ;
     RECT  45.205 71.664 45.608 74.424 ;
     RECT  43.373 77.376 45.608 77.4 ;
     RECT  45.109 84.336 45.608 84.936 ;
     RECT  43.204 86.016 45.608 86.328 ;
     RECT  43.427 87.792 45.608 87.816 ;
     RECT  43.427 89.76 45.608 90.888 ;
     RECT  43.445 92.208 45.608 92.232 ;
     RECT  43.445 93.264 45.608 93.336 ;
     RECT  45.461 94.368 45.608 104.424 ;
     RECT  45.608 2.148 45.712 104.424 ;
     RECT  45.712 2.418 45.904 104.424 ;
     RECT  45.904 57.84 46.037 58.488 ;
     RECT  45.904 61.968 46.073 61.992 ;
     RECT  45.904 50.496 46.181 51.672 ;
     RECT  45.904 92.208 46.181 104.424 ;
     RECT  45.904 84.336 46.253 84.936 ;
     RECT  45.904 86.016 46.469 86.328 ;
     RECT  45.904 70.128 46.649 74.424 ;
     RECT  46.181 50.496 46.721 50.52 ;
     RECT  46.649 70.128 46.739 70.824 ;
     RECT  46.649 72.24 46.739 74.424 ;
     RECT  46.739 70.128 46.757 70.152 ;
     RECT  45.904 77.376 46.757 77.4 ;
     RECT  46.181 93.216 46.793 104.424 ;
     RECT  46.793 93.216 46.931 104.376 ;
     RECT  45.904 63.216 47.081 64.728 ;
     RECT  46.739 72.24 47.153 72.264 ;
     RECT  45.461 105.552 47.413 105.768 ;
     RECT  45.904 34.08 47.725 34.104 ;
     RECT  45.904 52.704 47.749 56.856 ;
     RECT  46.037 57.84 47.749 58.44 ;
     RECT  46.181 51.648 47.797 51.672 ;
     RECT  45.904 68.112 47.905 68.136 ;
     RECT  46.931 93.216 48.013 104.328 ;
     RECT  47.413 105.408 48.013 105.768 ;
     RECT  47.113 32.832 48.308 32.856 ;
     RECT  47.725 34.08 48.308 34.728 ;
     RECT  45.904 37.104 48.308 38.184 ;
     RECT  45.904 45.408 48.308 48.216 ;
     RECT  47.797 51.216 48.308 51.672 ;
     RECT  47.749 52.704 48.308 58.44 ;
     RECT  45.904 59.52 48.308 60.696 ;
     RECT  47.081 63.504 48.308 64.728 ;
     RECT  45.904 66.48 48.308 67.08 ;
     RECT  47.905 68.112 48.308 68.424 ;
     RECT  46.739 73.248 48.308 74.424 ;
     RECT  46.253 84.912 48.308 84.936 ;
     RECT  46.469 86.304 48.308 86.328 ;
     RECT  45.904 89.76 48.308 90.888 ;
     RECT  46.181 92.208 48.308 92.232 ;
     RECT  48.013 93.216 48.308 105.768 ;
     RECT  48.308 2.148 48.412 105.768 ;
     RECT  48.412 2.418 48.604 105.768 ;
     RECT  48.604 51.216 48.737 58.44 ;
     RECT  48.737 52.464 48.881 58.44 ;
     RECT  48.604 45.984 48.917 48.216 ;
     RECT  48.737 51.216 49.493 51.24 ;
     RECT  48.917 46.032 49.529 48.216 ;
     RECT  48.604 93.216 49.763 105.768 ;
     RECT  48.604 66.48 49.861 67.08 ;
     RECT  49.529 46.032 49.889 47.88 ;
     RECT  48.604 32.832 49.921 32.856 ;
     RECT  48.604 89.76 49.925 90.888 ;
     RECT  48.604 74.352 49.997 74.424 ;
     RECT  48.604 34.08 50.101 34.728 ;
     RECT  49.885 31.776 50.425 31.8 ;
     RECT  49.921 32.832 50.425 33.048 ;
     RECT  50.425 31.776 50.461 33.048 ;
     RECT  50.101 34.08 50.461 35.016 ;
     RECT  49.763 104.88 50.537 105.768 ;
     RECT  49.889 46.032 50.749 47.688 ;
     RECT  49.763 93.216 50.821 103.8 ;
     RECT  50.537 104.88 50.821 105.72 ;
     RECT  50.497 29.808 51.008 29.832 ;
     RECT  50.461 31.776 51.008 35.016 ;
     RECT  48.604 37.104 51.008 38.184 ;
     RECT  50.749 45.792 51.008 47.688 ;
     RECT  48.881 52.704 51.008 58.44 ;
     RECT  48.604 59.52 51.008 60.696 ;
     RECT  50.713 62.208 51.008 62.232 ;
     RECT  48.604 63.504 51.008 65.256 ;
     RECT  49.861 66.48 51.008 67.128 ;
     RECT  48.604 68.112 51.008 68.952 ;
     RECT  50.677 69.984 51.008 70.008 ;
     RECT  48.604 73.344 51.008 73.368 ;
     RECT  49.997 74.352 51.008 74.376 ;
     RECT  50.713 78.672 51.008 78.696 ;
     RECT  48.604 84.912 51.008 84.936 ;
     RECT  48.604 86.304 51.008 86.328 ;
     RECT  49.925 89.76 51.008 89.784 ;
     RECT  49.925 90.864 51.008 90.888 ;
     RECT  48.604 92.208 51.008 92.232 ;
     RECT  50.821 93.216 51.008 105.72 ;
     RECT  51.008 2.148 51.011 105.72 ;
     RECT  51.011 2.148 51.112 103.752 ;
     RECT  51.112 2.418 51.304 103.752 ;
     RECT  51.011 104.88 51.329 105.72 ;
     RECT  51.329 105.456 51.481 105.72 ;
     RECT  51.304 51.696 51.587 53.592 ;
     RECT  51.481 105.456 51.683 105.672 ;
     RECT  51.304 54.672 51.689 58.44 ;
     RECT  51.304 63.504 51.725 65.256 ;
     RECT  51.689 54.672 51.869 57.864 ;
     RECT  51.869 54.96 51.941 57.864 ;
     RECT  51.587 51.696 52.049 52.728 ;
     RECT  51.304 93.6 52.145 103.752 ;
     RECT  51.941 56.304 52.157 57.864 ;
     RECT  52.145 93.6 52.229 103.8 ;
     RECT  51.304 66.48 52.301 67.128 ;
     RECT  52.157 57.024 52.373 57.864 ;
     RECT  52.049 52.56 52.445 52.728 ;
     RECT  51.941 54.96 52.445 54.984 ;
     RECT  52.373 57.024 52.445 57.048 ;
     RECT  52.229 93.6 52.513 103.752 ;
     RECT  51.683 105.456 52.513 105.624 ;
     RECT  52.513 105.36 52.643 105.624 ;
     RECT  51.304 59.52 52.661 61.56 ;
     RECT  52.643 105.456 52.693 105.624 ;
     RECT  52.513 93.36 52.739 103.752 ;
     RECT  51.304 29.808 52.837 29.832 ;
     RECT  51.304 31.152 52.837 35.208 ;
     RECT  52.661 59.52 53.173 60.408 ;
     RECT  52.693 105.456 53.197 105.72 ;
     RECT  52.739 93.36 53.269 103.608 ;
     RECT  53.269 93.264 53.305 103.608 ;
     RECT  51.304 69.984 53.365 70.056 ;
     RECT  51.725 63.504 53.377 63.528 ;
     RECT  51.304 36.336 53.413 38.28 ;
     RECT  53.197 105.456 53.417 105.768 ;
     RECT  53.417 105.456 53.701 105.672 ;
     RECT  52.837 29.808 53.708 35.208 ;
     RECT  53.413 36.24 53.708 38.28 ;
     RECT  51.304 45.792 53.708 47.4 ;
     RECT  52.445 52.56 53.708 52.584 ;
     RECT  52.729 53.664 53.708 53.688 ;
     RECT  53.173 59.232 53.708 60.408 ;
     RECT  52.661 61.536 53.708 61.56 ;
     RECT  53.377 62.544 53.708 63.528 ;
     RECT  51.725 64.704 53.708 65.256 ;
     RECT  52.301 66.48 53.708 66.504 ;
     RECT  51.304 68.112 53.708 68.952 ;
     RECT  53.365 69.984 53.708 70.104 ;
     RECT  51.304 73.344 53.708 73.368 ;
     RECT  51.304 84.912 53.708 84.936 ;
     RECT  51.304 86.304 53.708 86.328 ;
     RECT  51.304 89.76 53.708 89.784 ;
     RECT  51.304 90.864 53.708 90.888 ;
     RECT  51.304 92.208 53.708 92.232 ;
     RECT  53.305 93.216 53.708 103.608 ;
     RECT  53.708 2.148 53.812 103.608 ;
     RECT  53.812 2.418 53.939 103.608 ;
     RECT  53.939 2.418 54.004 103.56 ;
     RECT  54.004 68.208 54.065 70.104 ;
     RECT  54.004 66.48 54.137 66.504 ;
     RECT  54.004 92.208 54.209 103.56 ;
     RECT  54.004 72.384 54.425 73.512 ;
     RECT  54.065 68.208 54.497 70.008 ;
     RECT  53.701 105.36 54.529 105.672 ;
     RECT  54.425 73.344 54.997 73.512 ;
     RECT  54.529 104.544 54.997 105.672 ;
     RECT  54.004 29.808 55.033 35.208 ;
     RECT  54.004 36.24 55.033 38.28 ;
     RECT  54.997 73.344 55.289 73.56 ;
     RECT  54.004 58.944 55.379 59.832 ;
     RECT  54.004 55.728 55.477 56.664 ;
     RECT  55.249 61.968 55.501 61.992 ;
     RECT  54.004 63.504 55.501 63.528 ;
     RECT  55.379 58.944 55.645 59.304 ;
     RECT  54.209 92.208 55.645 103.032 ;
     RECT  55.249 51.456 55.681 51.48 ;
     RECT  55.289 73.344 55.681 73.368 ;
     RECT  54.997 104.544 55.681 105.72 ;
     RECT  55.645 92.208 55.717 103.224 ;
     RECT  55.681 104.544 55.717 105.768 ;
     RECT  55.681 51.36 55.753 51.48 ;
     RECT  55.033 29.808 55.789 38.28 ;
     RECT  55.753 39.504 55.789 39.528 ;
     RECT  55.717 92.208 55.811 105.768 ;
     RECT  55.753 51.36 55.825 52.296 ;
     RECT  55.825 51.36 56.113 52.728 ;
     RECT  55.681 71.952 56.113 71.976 ;
     RECT  55.811 104.448 56.117 105.768 ;
     RECT  55.789 29.808 56.221 39.528 ;
     RECT  56.221 29.808 56.408 39.624 ;
     RECT  54.004 45.792 56.408 47.4 ;
     RECT  56.113 51.36 56.408 53.304 ;
     RECT  55.477 55.728 56.408 57.576 ;
     RECT  55.645 58.656 56.408 59.304 ;
     RECT  55.501 61.968 56.408 63.528 ;
     RECT  54.497 68.208 56.408 68.952 ;
     RECT  54.497 69.984 56.408 70.008 ;
     RECT  56.113 71.616 56.408 71.976 ;
     RECT  55.681 72.96 56.408 73.368 ;
     RECT  54.004 76.464 56.408 76.488 ;
     RECT  54.004 84.912 56.408 84.936 ;
     RECT  54.004 86.304 56.408 86.328 ;
     RECT  54.004 89.76 56.408 89.784 ;
     RECT  54.004 90.864 56.408 90.888 ;
     RECT  55.811 92.208 56.408 103.422 ;
     RECT  56.408 2.148 56.512 103.422 ;
     RECT  56.512 2.418 56.704 103.422 ;
     RECT  56.704 75.408 56.819 75.432 ;
     RECT  56.704 45.792 57.089 47.736 ;
     RECT  56.704 92.208 57.164 103.422 ;
     RECT  56.117 104.448 57.164 105.72 ;
     RECT  56.704 76.464 57.338 76.536 ;
     RECT  56.704 49.008 57.349 49.032 ;
     RECT  57.089 45.792 57.377 47.592 ;
     RECT  56.704 57.84 57.731 59.88 ;
     RECT  56.704 42.144 57.733 42.552 ;
     RECT  56.704 71.616 57.805 72.264 ;
     RECT  56.704 73.344 57.805 73.56 ;
     RECT  57.731 57.84 57.971 59.304 ;
     RECT  56.704 50.4 58.021 53.88 ;
     RECT  56.704 54.96 58.021 56.808 ;
     RECT  58.021 50.4 58.093 56.808 ;
     RECT  56.704 29.808 58.417 39.624 ;
     RECT  56.704 63.504 58.417 63.528 ;
     RECT  58.093 49.824 58.453 56.808 ;
     RECT  57.971 57.84 58.453 59.256 ;
     RECT  56.704 61.968 58.705 61.992 ;
     RECT  57.338 76.512 58.885 76.536 ;
     RECT  59.029 21.408 59.108 21.432 ;
     RECT  58.417 29.808 59.108 39.768 ;
     RECT  57.733 41.952 59.108 42.552 ;
     RECT  57.377 45.792 59.108 47.4 ;
     RECT  58.453 49.824 59.108 59.256 ;
     RECT  58.705 61.728 59.108 61.992 ;
     RECT  58.417 63.504 59.108 64.2 ;
     RECT  57.841 66.48 59.108 66.504 ;
     RECT  56.704 68.208 59.108 68.952 ;
     RECT  56.704 69.984 59.108 70.632 ;
     RECT  57.805 71.616 59.108 73.56 ;
     RECT  58.885 76.512 59.108 77.496 ;
     RECT  56.704 82.944 59.108 82.968 ;
     RECT  56.704 84.912 59.108 84.936 ;
     RECT  56.704 86.304 59.108 86.328 ;
     RECT  56.704 89.76 59.108 89.784 ;
     RECT  56.704 90.864 59.108 90.888 ;
     RECT  57.164 92.208 59.108 105.72 ;
     RECT  59.108 2.148 59.212 105.72 ;
     RECT  59.212 2.418 59.389 105.72 ;
     RECT  59.389 2.418 59.404 105.768 ;
     RECT  59.404 71.616 59.699 73.56 ;
     RECT  59.699 71.616 60.563 73.368 ;
     RECT  59.404 41.952 60.649 44.28 ;
     RECT  59.404 76.512 60.709 76.536 ;
     RECT  59.404 29.808 60.757 40.392 ;
     RECT  60.649 41.952 60.757 44.712 ;
     RECT  60.757 29.808 60.829 44.712 ;
     RECT  59.404 45.792 60.829 47.4 ;
     RECT  59.404 61.68 60.997 61.992 ;
     RECT  59.404 93.216 61.013 105.768 ;
     RECT  60.997 61.104 61.513 61.992 ;
     RECT  59.404 74.928 61.549 74.952 ;
     RECT  59.404 21.408 61.808 21.432 ;
     RECT  60.829 29.808 61.808 47.4 ;
     RECT  59.404 49.824 61.808 56.808 ;
     RECT  59.404 57.84 61.808 60.12 ;
     RECT  61.513 61.104 61.808 62.04 ;
     RECT  59.404 63.504 61.808 63.528 ;
     RECT  61.237 64.656 61.808 64.68 ;
     RECT  59.404 66.48 61.808 66.504 ;
     RECT  59.404 68.208 61.808 68.952 ;
     RECT  59.404 69.984 61.808 70.632 ;
     RECT  60.563 72.192 61.808 73.368 ;
     RECT  61.549 74.928 61.808 75.528 ;
     RECT  60.709 76.512 61.808 76.92 ;
     RECT  61.621 78.096 61.808 78.12 ;
     RECT  60.793 80.64 61.808 80.664 ;
     RECT  59.404 82.944 61.808 82.968 ;
     RECT  59.404 84.912 61.808 84.936 ;
     RECT  59.404 86.304 61.808 86.328 ;
     RECT  59.404 89.76 61.808 89.784 ;
     RECT  59.404 90.864 61.808 90.888 ;
     RECT  59.404 92.208 61.808 92.232 ;
     RECT  61.013 93.216 61.808 105.72 ;
     RECT  61.808 2.148 61.912 105.72 ;
     RECT  61.912 2.418 62.104 105.72 ;
     RECT  62.104 21.168 62.201 21.432 ;
     RECT  62.104 93.216 62.269 105.72 ;
     RECT  62.104 29.808 62.417 47.88 ;
     RECT  62.104 57.84 62.633 62.04 ;
     RECT  62.201 21.168 62.741 21.288 ;
     RECT  62.104 49.248 62.741 56.856 ;
     RECT  62.104 78.336 62.741 78.456 ;
     RECT  62.269 93.216 63.137 105.768 ;
     RECT  62.741 78.432 63.313 78.456 ;
     RECT  62.104 72.192 63.349 75.528 ;
     RECT  62.104 76.608 63.349 76.776 ;
     RECT  62.633 60.096 63.353 62.04 ;
     RECT  63.353 61.104 63.395 62.04 ;
     RECT  62.104 66.48 63.421 66.504 ;
     RECT  62.104 92.208 63.745 92.232 ;
     RECT  63.137 93.216 63.745 105.72 ;
     RECT  62.104 64.656 63.853 64.68 ;
     RECT  63.421 65.664 63.853 66.504 ;
     RECT  62.741 49.248 63.961 52.296 ;
     RECT  62.741 53.28 63.961 56.856 ;
     RECT  63.745 92.208 63.997 105.72 ;
     RECT  62.741 21.168 64.508 21.192 ;
     RECT  62.104 22.512 64.508 22.536 ;
     RECT  64.249 23.856 64.508 23.88 ;
     RECT  62.417 29.808 64.508 43.608 ;
     RECT  62.417 44.688 64.508 47.88 ;
     RECT  63.961 49.248 64.508 56.856 ;
     RECT  62.633 57.84 64.508 58.968 ;
     RECT  63.353 60.096 64.508 60.12 ;
     RECT  63.395 61.152 64.508 62.04 ;
     RECT  62.104 63.504 64.508 63.528 ;
     RECT  63.853 64.656 64.508 66.504 ;
     RECT  62.104 68.208 64.508 68.952 ;
     RECT  62.104 69.984 64.508 70.632 ;
     RECT  63.349 72.192 64.508 76.776 ;
     RECT  63.313 78.432 64.508 79.272 ;
     RECT  62.104 80.64 64.508 80.664 ;
     RECT  62.104 82.944 64.508 82.968 ;
     RECT  62.104 84.912 64.508 84.936 ;
     RECT  62.104 86.304 64.508 86.328 ;
     RECT  63.829 88.272 64.508 88.296 ;
     RECT  62.104 89.76 64.508 89.784 ;
     RECT  62.104 90.864 64.508 90.888 ;
     RECT  63.997 92.16 64.508 105.72 ;
     RECT  64.508 2.148 64.612 105.72 ;
     RECT  64.612 2.418 64.804 105.72 ;
     RECT  64.804 74.928 64.979 76.776 ;
     RECT  64.804 92.16 65.117 92.232 ;
     RECT  64.979 75.12 65.219 76.776 ;
     RECT  64.804 69.984 65.411 73.368 ;
     RECT  64.804 82.944 65.459 82.968 ;
     RECT  64.804 63.504 65.477 66.936 ;
     RECT  65.219 75.12 65.549 76.344 ;
     RECT  64.804 94.416 65.555 105.72 ;
     RECT  65.555 94.608 65.651 105.72 ;
     RECT  65.477 63.504 65.657 64.68 ;
     RECT  64.804 50.304 65.788 56.856 ;
     RECT  65.657 63.504 65.795 63.864 ;
     RECT  64.804 23.856 65.833 24.456 ;
     RECT  65.411 72.192 65.891 73.368 ;
     RECT  64.804 80.64 65.939 80.664 ;
     RECT  65.477 65.664 66.131 66.936 ;
     RECT  65.833 23.856 66.265 24.936 ;
     RECT  64.804 26.064 66.265 26.088 ;
     RECT  64.804 68.208 66.337 68.952 ;
     RECT  65.411 69.984 66.337 70.632 ;
     RECT  64.804 22.512 66.373 22.536 ;
     RECT  66.265 23.856 66.373 26.088 ;
     RECT  64.804 78.432 66.421 78.456 ;
     RECT  65.891 73.344 66.445 73.368 ;
     RECT  65.549 75.12 66.445 75.768 ;
     RECT  64.804 60.096 66.697 60.12 ;
     RECT  64.804 61.344 66.697 62.04 ;
     RECT  66.337 68.208 66.697 70.632 ;
     RECT  65.651 94.896 67.205 105.72 ;
     RECT  64.804 21.168 67.208 21.192 ;
     RECT  66.373 22.512 67.208 26.088 ;
     RECT  64.804 29.808 67.208 47.88 ;
     RECT  64.804 49.248 67.208 49.272 ;
     RECT  65.788 50.304 67.208 52.296 ;
     RECT  65.788 53.28 67.208 56.856 ;
     RECT  64.804 57.84 67.208 58.68 ;
     RECT  66.697 60.096 67.208 62.04 ;
     RECT  65.795 63.504 67.208 63.528 ;
     RECT  66.131 66.048 67.208 66.936 ;
     RECT  66.697 68.112 67.208 70.632 ;
     RECT  65.891 72.192 67.208 72.264 ;
     RECT  66.445 73.344 67.208 75.768 ;
     RECT  66.421 77.472 67.208 78.456 ;
     RECT  64.804 84.912 67.208 84.936 ;
     RECT  64.804 86.304 67.208 86.328 ;
     RECT  64.804 89.76 67.208 89.784 ;
     RECT  64.804 90.864 67.208 90.888 ;
     RECT  65.117 92.208 67.208 92.232 ;
     RECT  64.804 93.216 67.208 93.288 ;
     RECT  67.205 94.896 67.208 103.56 ;
     RECT  67.208 2.148 67.312 103.56 ;
     RECT  67.312 2.418 67.504 103.56 ;
     RECT  67.504 66.048 67.529 69 ;
     RECT  67.205 104.592 67.601 105.72 ;
     RECT  67.504 94.896 67.637 103.56 ;
     RECT  67.504 75.12 67.763 75.768 ;
     RECT  67.601 104.592 67.781 105.624 ;
     RECT  67.504 78.432 67.811 78.456 ;
     RECT  67.637 94.896 67.817 103.512 ;
     RECT  67.504 29.808 67.859 47.88 ;
     RECT  67.504 53.28 67.897 58.68 ;
     RECT  67.781 104.64 68.141 105.624 ;
     RECT  67.897 57.888 68.243 58.68 ;
     RECT  67.897 53.28 68.291 56.856 ;
     RECT  67.817 95.232 68.393 103.512 ;
     RECT  67.529 66.288 68.465 69 ;
     RECT  68.291 53.28 68.531 56.28 ;
     RECT  68.531 54.384 68.579 56.28 ;
     RECT  68.243 58.464 68.627 58.68 ;
     RECT  67.504 60.096 68.675 60.12 ;
     RECT  68.465 66.288 68.723 68.952 ;
     RECT  68.393 95.232 68.789 103.224 ;
     RECT  68.141 105.6 68.789 105.624 ;
     RECT  67.504 92.208 69.325 92.232 ;
     RECT  67.504 93.216 69.325 93.288 ;
     RECT  67.504 21.168 69.908 21.192 ;
     RECT  67.504 22.512 69.908 26.088 ;
     RECT  67.859 29.808 69.908 44.712 ;
     RECT  67.859 45.792 69.908 47.88 ;
     RECT  67.504 49.248 69.908 49.272 ;
     RECT  67.504 50.304 69.908 52.296 ;
     RECT  68.531 53.28 69.908 53.304 ;
     RECT  68.579 54.96 69.908 56.28 ;
     RECT  68.627 58.656 69.908 58.68 ;
     RECT  67.504 61.68 69.908 62.04 ;
     RECT  67.504 63.504 69.908 63.528 ;
     RECT  68.723 66.288 69.908 66.312 ;
     RECT  68.723 67.824 69.908 68.952 ;
     RECT  67.504 69.984 69.908 70.632 ;
     RECT  67.504 72.192 69.908 72.264 ;
     RECT  67.504 73.344 69.908 73.368 ;
     RECT  67.763 75.12 69.908 75.144 ;
     RECT  67.504 84.912 69.908 84.936 ;
     RECT  67.504 89.76 69.908 89.784 ;
     RECT  67.504 90.864 69.908 90.888 ;
     RECT  69.325 92.208 69.908 93.288 ;
     RECT  68.789 95.232 69.908 97.56 ;
     RECT  68.789 98.64 69.908 103.224 ;
     RECT  69.908 2.148 70.012 103.224 ;
     RECT  70.012 2.418 70.1 103.224 ;
     RECT  70.1 2.418 70.204 103.422 ;
     RECT  70.204 42.72 70.355 44.712 ;
     RECT  70.204 99.216 70.355 103.224 ;
     RECT  70.355 43.584 70.403 44.712 ;
     RECT  70.355 99.216 70.403 102.696 ;
     RECT  70.204 92.208 70.451 93 ;
     RECT  70.204 21.168 70.733 21.288 ;
     RECT  70.204 49.248 70.733 52.296 ;
     RECT  70.204 55.728 70.733 55.848 ;
     RECT  70.204 72.192 70.733 72.312 ;
     RECT  70.204 73.344 70.733 73.512 ;
     RECT  70.403 99.216 70.979 102.216 ;
     RECT  70.979 99.216 71.309 100.584 ;
     RECT  70.733 21.168 72.608 21.192 ;
     RECT  70.204 22.512 72.608 26.088 ;
     RECT  70.204 29.808 72.608 41.208 ;
     RECT  70.403 43.584 72.608 43.896 ;
     RECT  70.204 45.792 72.608 47.88 ;
     RECT  70.733 49.248 72.608 49.272 ;
     RECT  70.733 50.304 72.608 52.296 ;
     RECT  70.733 55.728 72.608 55.752 ;
     RECT  70.204 58.656 72.608 58.68 ;
     RECT  70.204 61.632 72.608 62.04 ;
     RECT  70.204 63.504 72.608 63.528 ;
     RECT  70.204 66.288 72.608 66.312 ;
     RECT  70.204 67.824 72.608 68.952 ;
     RECT  70.204 69.984 72.608 70.632 ;
     RECT  70.733 72.192 72.608 72.264 ;
     RECT  70.733 73.344 72.608 73.368 ;
     RECT  70.204 75.12 72.608 75.144 ;
     RECT  70.204 84.912 72.608 84.936 ;
     RECT  70.204 89.76 72.608 89.784 ;
     RECT  70.204 90.864 72.608 90.888 ;
     RECT  70.451 92.208 72.608 92.232 ;
     RECT  70.204 95.232 72.608 97.56 ;
     RECT  71.309 99.552 72.608 100.584 ;
     RECT  70.979 101.568 72.608 102.216 ;
     RECT  72.608 2.148 72.712 103.152 ;
     RECT  72.712 2.418 72.8 103.152 ;
     RECT  72.8 2.418 72.904 103.422 ;
     RECT  72.904 95.232 73.649 97.56 ;
     RECT  73.649 95.232 73.865 97.176 ;
     RECT  72.904 84.912 74.117 84.936 ;
     RECT  72.904 21.168 75.308 21.192 ;
     RECT  72.904 22.512 75.308 26.088 ;
     RECT  72.904 29.808 75.308 41.208 ;
     RECT  72.904 43.584 75.308 43.896 ;
     RECT  72.904 45.792 75.308 47.88 ;
     RECT  72.904 49.248 75.308 49.272 ;
     RECT  72.904 50.304 75.308 52.296 ;
     RECT  72.904 55.728 75.308 55.752 ;
     RECT  72.904 58.656 75.308 58.68 ;
     RECT  72.904 61.632 75.308 62.04 ;
     RECT  72.904 63.504 75.308 63.528 ;
     RECT  72.904 66.288 75.308 66.312 ;
     RECT  72.904 67.824 75.308 68.952 ;
     RECT  72.904 69.984 75.308 70.632 ;
     RECT  72.904 72.192 75.308 72.264 ;
     RECT  72.904 73.344 75.308 73.368 ;
     RECT  72.904 75.12 75.308 75.144 ;
     RECT  72.904 80.304 75.308 80.328 ;
     RECT  72.904 89.76 75.308 89.784 ;
     RECT  72.904 90.864 75.308 90.888 ;
     RECT  72.904 91.872 75.308 92.232 ;
     RECT  73.865 95.232 75.308 96.6 ;
     RECT  72.904 99.552 75.308 100.584 ;
     RECT  72.904 101.664 75.308 102.216 ;
     RECT  75.308 2.148 75.412 103.152 ;
     RECT  75.412 2.418 75.5 103.152 ;
     RECT  75.5 2.418 75.604 103.422 ;
     RECT  75.604 21.168 78.008 21.192 ;
     RECT  75.604 22.512 78.008 26.088 ;
     RECT  75.604 29.808 78.008 41.208 ;
     RECT  75.604 43.584 78.008 43.896 ;
     RECT  75.604 45.792 78.008 47.88 ;
     RECT  75.604 49.248 78.008 49.272 ;
     RECT  75.604 50.304 78.008 52.296 ;
     RECT  75.604 55.728 78.008 55.752 ;
     RECT  75.604 58.656 78.008 58.68 ;
     RECT  75.604 61.632 78.008 62.04 ;
     RECT  75.604 63.504 78.008 63.528 ;
     RECT  75.604 66.288 78.008 66.312 ;
     RECT  75.604 67.824 78.008 68.952 ;
     RECT  75.604 69.984 78.008 70.632 ;
     RECT  75.604 72.192 78.008 72.264 ;
     RECT  75.604 73.344 78.008 73.368 ;
     RECT  75.604 75.12 78.008 75.144 ;
     RECT  75.604 80.304 78.008 80.328 ;
     RECT  75.604 89.76 78.008 89.784 ;
     RECT  75.604 90.864 78.008 90.888 ;
     RECT  75.604 91.872 78.008 92.232 ;
     RECT  75.604 95.232 78.008 96.6 ;
     RECT  75.604 99.552 78.008 100.584 ;
     RECT  75.604 101.664 78.008 102.216 ;
     RECT  78.008 2.148 78.112 103.152 ;
     RECT  78.112 2.418 78.2 103.152 ;
     RECT  78.2 2.418 78.304 103.422 ;
     RECT  78.304 21.168 78.689 21.288 ;
     RECT  78.304 49.248 78.689 52.296 ;
     RECT  78.304 55.728 78.689 55.848 ;
     RECT  78.304 66.192 78.689 66.312 ;
     RECT  78.304 72.192 78.689 72.312 ;
     RECT  78.304 73.344 78.689 73.512 ;
     RECT  78.304 89.76 78.941 89.784 ;
     RECT  78.689 21.168 80.708 21.192 ;
     RECT  78.304 22.512 80.708 26.088 ;
     RECT  78.304 29.808 80.708 41.208 ;
     RECT  78.304 43.584 80.708 43.896 ;
     RECT  78.304 45.792 80.708 47.88 ;
     RECT  78.689 49.248 80.708 49.272 ;
     RECT  78.689 50.304 80.708 52.296 ;
     RECT  78.689 55.728 80.708 55.752 ;
     RECT  78.304 58.656 80.708 58.68 ;
     RECT  78.304 61.632 80.708 62.04 ;
     RECT  78.304 63.504 80.708 63.528 ;
     RECT  78.689 66.288 80.708 66.312 ;
     RECT  78.304 67.824 80.708 68.952 ;
     RECT  78.304 69.984 80.708 70.632 ;
     RECT  78.689 72.192 80.708 72.264 ;
     RECT  78.689 73.344 80.708 73.368 ;
     RECT  78.304 75.12 80.708 75.144 ;
     RECT  78.304 80.304 80.708 80.328 ;
     RECT  78.304 90.864 80.708 90.888 ;
     RECT  78.304 91.872 80.708 92.232 ;
     RECT  78.304 95.232 80.708 96.6 ;
     RECT  78.304 99.552 80.708 100.584 ;
     RECT  78.304 101.664 80.708 102.216 ;
     RECT  80.708 2.148 80.812 103.152 ;
     RECT  80.812 2.418 80.9 103.152 ;
     RECT  80.9 2.418 81.004 103.422 ;
     RECT  81.004 101.664 81.929 102.216 ;
     RECT  81.004 91.872 82.109 92.232 ;
     RECT  81.004 99.552 82.109 100.584 ;
     RECT  81.004 21.168 83.408 21.192 ;
     RECT  81.004 22.512 83.408 26.088 ;
     RECT  81.004 29.808 83.408 41.208 ;
     RECT  81.004 43.584 83.408 43.896 ;
     RECT  81.004 45.792 83.408 47.88 ;
     RECT  81.004 49.248 83.408 49.272 ;
     RECT  81.004 50.304 83.408 52.296 ;
     RECT  81.004 55.728 83.408 55.752 ;
     RECT  81.004 58.656 83.408 58.68 ;
     RECT  81.004 61.632 83.408 62.04 ;
     RECT  81.004 63.504 83.408 63.528 ;
     RECT  81.004 66.288 83.408 66.312 ;
     RECT  81.004 67.824 83.408 68.952 ;
     RECT  81.004 69.984 83.408 70.632 ;
     RECT  81.004 72.192 83.408 72.264 ;
     RECT  81.004 73.344 83.408 73.368 ;
     RECT  81.004 75.12 83.408 75.144 ;
     RECT  81.004 80.304 83.408 80.328 ;
     RECT  81.004 90.864 83.408 90.888 ;
     RECT  82.109 92.016 83.408 92.04 ;
     RECT  81.004 95.232 83.408 96.6 ;
     RECT  82.109 99.744 83.408 100.584 ;
     RECT  81.929 102.192 83.408 102.216 ;
     RECT  83.408 2.148 83.512 103.152 ;
     RECT  83.512 2.418 83.6 103.152 ;
     RECT  83.6 2.418 83.704 103.422 ;
     RECT  83.704 73.344 84.413 73.368 ;
     RECT  83.704 21.168 86.108 21.192 ;
     RECT  83.704 22.512 86.108 26.088 ;
     RECT  83.704 29.808 86.108 41.208 ;
     RECT  83.704 43.584 86.108 43.896 ;
     RECT  83.704 45.792 86.108 47.88 ;
     RECT  83.704 49.248 86.108 49.272 ;
     RECT  83.704 50.304 86.108 52.296 ;
     RECT  83.704 55.728 86.108 55.752 ;
     RECT  83.704 58.656 86.108 58.68 ;
     RECT  83.704 61.632 86.108 62.04 ;
     RECT  83.704 63.504 86.108 63.528 ;
     RECT  83.704 66.288 86.108 66.312 ;
     RECT  83.704 67.824 86.108 68.952 ;
     RECT  83.704 69.984 86.108 70.632 ;
     RECT  83.704 72.192 86.108 72.264 ;
     RECT  83.704 75.12 86.108 75.144 ;
     RECT  83.704 80.304 86.108 80.328 ;
     RECT  83.704 95.232 86.108 96.6 ;
     RECT  83.704 99.744 86.108 100.584 ;
     RECT  83.704 102.192 86.108 102.216 ;
     RECT  86.108 2.148 86.212 103.152 ;
     RECT  86.212 2.418 86.3 103.152 ;
     RECT  86.3 2.418 86.404 103.422 ;
     RECT  86.404 21.168 86.501 21.288 ;
     RECT  86.404 55.728 86.501 55.848 ;
     RECT  86.404 61.632 86.501 62.04 ;
     RECT  86.404 66.192 86.501 66.312 ;
     RECT  86.404 69.984 86.501 70.632 ;
     RECT  86.404 49.248 86.681 52.296 ;
     RECT  86.404 72.192 86.681 72.312 ;
     RECT  86.404 75.12 87.757 75.144 ;
     RECT  86.501 21.264 88.808 21.288 ;
     RECT  86.404 22.512 88.808 26.088 ;
     RECT  86.404 29.808 88.808 41.208 ;
     RECT  86.404 43.584 88.808 43.896 ;
     RECT  86.404 45.696 88.808 47.88 ;
     RECT  86.681 49.248 88.808 49.272 ;
     RECT  86.681 50.304 88.808 52.296 ;
     RECT  86.501 55.824 88.808 55.848 ;
     RECT  86.404 58.656 88.808 58.68 ;
     RECT  86.501 61.68 88.808 62.04 ;
     RECT  86.404 63.504 88.808 63.528 ;
     RECT  86.501 66.192 88.808 66.216 ;
     RECT  86.404 67.824 88.808 68.952 ;
     RECT  86.501 69.984 88.808 70.536 ;
     RECT  86.681 72.192 88.808 72.264 ;
     RECT  87.757 75.12 88.808 75.528 ;
     RECT  86.404 80.304 88.808 80.328 ;
     RECT  86.404 95.712 88.808 96.6 ;
     RECT  86.404 99.744 88.808 100.584 ;
     RECT  86.404 102.192 88.808 102.216 ;
     RECT  88.808 2.148 88.912 103.152 ;
     RECT  88.912 2.418 89 103.152 ;
     RECT  89 2.418 89.104 103.422 ;
     RECT  89.104 99.744 90.173 100.584 ;
     RECT  89.104 21.264 90.637 21.288 ;
     RECT  89.104 55.824 90.637 55.848 ;
     RECT  89.104 66.192 90.637 66.216 ;
     RECT  89.104 69.984 90.637 70.536 ;
     RECT  90.637 21.168 91.508 21.288 ;
     RECT  89.104 22.512 91.508 26.088 ;
     RECT  89.104 29.808 91.508 41.208 ;
     RECT  89.104 43.584 91.508 43.896 ;
     RECT  89.104 45.696 91.508 47.88 ;
     RECT  89.104 49.248 91.508 49.272 ;
     RECT  89.104 50.304 91.508 52.296 ;
     RECT  90.637 55.728 91.508 55.848 ;
     RECT  89.104 58.656 91.508 58.68 ;
     RECT  89.104 61.68 91.508 62.04 ;
     RECT  89.104 63.504 91.508 63.528 ;
     RECT  90.637 66.192 91.508 66.312 ;
     RECT  89.104 67.824 91.508 69 ;
     RECT  90.637 69.984 91.508 70.632 ;
     RECT  89.104 72.192 91.508 72.264 ;
     RECT  89.104 75.12 91.508 75.528 ;
     RECT  89.104 80.304 91.508 80.328 ;
     RECT  89.104 95.712 91.508 96.6 ;
     RECT  90.173 99.744 91.508 99.768 ;
     RECT  89.104 102.192 91.508 102.216 ;
     RECT  91.508 2.148 91.612 103.152 ;
     RECT  91.612 2.418 91.7 103.152 ;
     RECT  91.7 2.418 91.804 103.422 ;
     RECT  91.804 63.504 92.405 63.528 ;
     RECT  91.804 95.712 92.657 96.6 ;
     RECT  91.804 29.808 92.869 41.208 ;
     RECT  91.804 78.912 93.445 78.936 ;
     RECT  91.804 50.304 94.021 52.296 ;
     RECT  91.804 21.168 94.208 21.192 ;
     RECT  91.804 22.512 94.208 26.088 ;
     RECT  92.869 29.808 94.208 41.784 ;
     RECT  91.804 43.584 94.208 43.896 ;
     RECT  91.804 45.696 94.208 47.88 ;
     RECT  91.804 49.248 94.208 49.272 ;
     RECT  94.021 50.304 94.208 53.016 ;
     RECT  93.445 54.672 94.208 54.696 ;
     RECT  91.804 55.728 94.208 55.752 ;
     RECT  94.021 56.88 94.208 56.904 ;
     RECT  91.804 58.656 94.208 58.68 ;
     RECT  91.804 61.68 94.208 62.04 ;
     RECT  92.869 63.024 94.208 63.048 ;
     RECT  91.804 64.656 94.208 64.68 ;
     RECT  91.804 66.288 94.208 66.312 ;
     RECT  91.804 67.824 94.208 69 ;
     RECT  91.804 69.984 94.208 70.632 ;
     RECT  91.804 72.192 94.208 72.264 ;
     RECT  91.804 75.12 94.208 75.528 ;
     RECT  93.445 78.912 94.208 79.32 ;
     RECT  91.804 80.304 94.208 80.328 ;
     RECT  92.657 96.576 94.208 96.6 ;
     RECT  91.804 99.744 94.208 99.768 ;
     RECT  94.208 2.148 94.312 103.152 ;
     RECT  94.312 2.418 94.4 103.152 ;
     RECT  94.4 2.418 94.504 103.422 ;
     RECT  94.504 21.168 94.601 21.288 ;
     RECT  94.504 55.728 94.601 55.848 ;
     RECT  94.504 69.984 94.601 70.632 ;
     RECT  94.504 99.84 94.673 100.008 ;
     RECT  94.504 72.24 95.713 72.312 ;
     RECT  94.504 43.584 96.289 43.8 ;
     RECT  94.504 49.248 96.289 53.016 ;
     RECT  94.601 55.824 96.289 55.848 ;
     RECT  94.504 56.88 96.289 56.904 ;
     RECT  94.504 65.712 96.289 66.504 ;
     RECT  94.504 67.824 96.289 69 ;
     RECT  94.504 75.12 96.289 75.528 ;
     RECT  94.504 77.616 96.289 77.688 ;
     RECT  94.504 45.936 96.865 47.88 ;
     RECT  96.289 49.248 96.865 53.352 ;
     RECT  94.504 61.68 96.865 64.68 ;
     RECT  96.289 65.712 96.865 69 ;
     RECT  95.713 72.192 96.865 72.312 ;
     RECT  96.865 45.936 96.901 53.352 ;
     RECT  94.504 54.672 96.901 54.696 ;
     RECT  94.601 21.264 96.908 21.288 ;
     RECT  94.504 22.512 96.908 26.04 ;
     RECT  94.504 29.808 96.908 41.784 ;
     RECT  96.289 43.008 96.908 43.8 ;
     RECT  96.901 45.936 96.908 54.696 ;
     RECT  96.289 55.824 96.908 57.432 ;
     RECT  94.504 58.656 96.908 59.208 ;
     RECT  96.865 61.68 96.908 69 ;
     RECT  94.601 69.984 96.908 70.536 ;
     RECT  96.865 72.192 96.908 73.272 ;
     RECT  96.289 75.12 96.908 76.296 ;
     RECT  96.289 77.616 96.908 77.928 ;
     RECT  94.504 78.912 96.908 79.32 ;
     RECT  94.504 80.304 96.908 80.328 ;
     RECT  94.504 96.576 96.908 96.6 ;
     RECT  94.673 99.984 96.908 100.008 ;
     RECT  96.908 2.148 97.012 103.152 ;
     RECT  97.012 2.418 97.1 103.152 ;
     RECT  97.1 2.418 97.204 103.422 ;
     RECT  97.204 99.984 97.841 100.008 ;
     RECT  97.204 45.936 98.557 54.696 ;
     RECT  97.204 55.824 98.557 57.432 ;
     RECT  97.204 77.616 98.557 79.32 ;
     RECT  97.204 80.304 98.557 80.328 ;
     RECT  97.204 61.68 98.593 70.824 ;
     RECT  98.593 61.68 98.629 70.92 ;
     RECT  98.629 61.68 99.097 71.112 ;
     RECT  97.204 72.192 99.097 73.272 ;
     RECT  99.097 61.68 99.565 73.272 ;
     RECT  97.204 75.12 99.565 76.296 ;
     RECT  97.204 21.264 99.608 21.288 ;
     RECT  97.204 22.512 99.608 26.04 ;
     RECT  97.204 29.76 99.608 41.784 ;
     RECT  97.204 43.008 99.608 44.376 ;
     RECT  98.557 45.936 99.608 57.432 ;
     RECT  97.204 58.656 99.608 59.352 ;
     RECT  99.565 61.392 99.608 76.296 ;
     RECT  98.557 77.616 99.608 80.328 ;
     RECT  97.204 96.576 99.608 96.6 ;
     RECT  99.608 2.148 99.712 103.152 ;
     RECT  99.712 2.418 99.8 103.152 ;
     RECT  99.8 2.418 99.904 103.422 ;
     RECT  99.904 96.576 100.541 96.6 ;
     RECT  99.904 21.264 101.041 21.288 ;
     RECT  99.904 29.712 101.149 57.48 ;
     RECT  101.041 20.88 101.257 21.288 ;
     RECT  101.257 20.208 101.293 21.288 ;
     RECT  101.293 20.208 101.329 21.48 ;
     RECT  99.904 22.512 101.329 25.992 ;
     RECT  99.904 27.216 101.473 27.24 ;
     RECT  101.149 28.752 101.473 57.48 ;
     RECT  101.329 20.208 102.013 25.992 ;
     RECT  101.473 27.216 102.013 57.48 ;
     RECT  102.013 20.208 102.445 57.48 ;
     RECT  102.445 20.112 102.589 57.48 ;
     RECT  99.904 58.512 102.589 76.488 ;
     RECT  99.904 77.616 102.589 79.56 ;
     RECT  102.589 77.52 102.625 79.752 ;
     RECT  102.589 20.112 102.841 76.488 ;
     RECT  102.841 20.016 103.165 76.488 ;
     RECT  102.625 77.52 103.165 79.848 ;
     RECT  103.165 20.016 103.921 79.848 ;
     RECT  103.921 19.92 104.004 19.944 ;
     RECT  103.921 19.944 104.028 20.016 ;
     RECT  103.921 20.016 104.004 20.04 ;
     RECT  103.921 20.04 104.028 20.112 ;
     RECT  103.921 20.112 104.004 20.136 ;
     RECT  103.921 20.136 104.028 20.208 ;
     RECT  103.921 20.208 104.004 20.232 ;
     RECT  103.921 20.232 104.028 20.304 ;
     RECT  103.921 20.304 104.004 20.328 ;
     RECT  103.921 20.328 104.028 20.4 ;
     RECT  103.921 20.4 104.004 20.424 ;
     RECT  103.921 20.424 104.028 20.496 ;
     RECT  103.921 20.496 104.004 20.52 ;
     RECT  103.921 20.52 104.028 20.592 ;
     RECT  103.921 20.592 104.004 20.616 ;
     RECT  103.921 20.616 104.028 20.688 ;
     RECT  103.921 20.688 104.004 20.712 ;
     RECT  103.921 20.712 104.028 20.784 ;
     RECT  103.921 20.784 104.004 20.808 ;
     RECT  103.921 20.808 104.028 20.88 ;
     RECT  103.921 20.88 104.004 20.904 ;
     RECT  103.921 20.904 104.028 20.976 ;
     RECT  103.921 20.976 104.004 21 ;
     RECT  103.921 21 104.028 21.072 ;
     RECT  103.921 21.072 104.004 21.096 ;
     RECT  103.921 21.096 104.028 21.168 ;
     RECT  103.921 21.168 104.004 21.192 ;
     RECT  103.921 21.192 104.028 21.264 ;
     RECT  103.921 21.264 104.004 21.288 ;
     RECT  103.921 21.288 104.028 21.36 ;
     RECT  103.921 21.36 104.004 21.384 ;
     RECT  103.921 21.384 104.028 21.456 ;
     RECT  103.921 21.456 104.004 21.48 ;
     RECT  103.921 21.48 104.028 21.552 ;
     RECT  103.921 21.552 104.004 21.576 ;
     RECT  103.921 21.576 104.028 21.648 ;
     RECT  103.921 21.648 104.004 21.672 ;
     RECT  103.921 21.672 104.028 21.744 ;
     RECT  103.921 21.744 104.004 21.768 ;
     RECT  103.921 21.768 104.028 21.84 ;
     RECT  103.921 21.84 104.004 21.864 ;
     RECT  103.921 21.864 104.028 21.936 ;
     RECT  103.921 21.936 104.004 21.96 ;
     RECT  103.921 21.96 104.028 22.032 ;
     RECT  103.921 22.032 104.004 22.056 ;
     RECT  103.921 22.056 104.028 22.128 ;
     RECT  103.921 22.128 104.004 22.152 ;
     RECT  103.921 22.152 104.028 22.224 ;
     RECT  103.921 22.224 104.004 22.248 ;
     RECT  103.921 22.248 104.028 22.32 ;
     RECT  103.921 22.32 104.004 22.344 ;
     RECT  103.921 22.344 104.028 22.416 ;
     RECT  103.921 22.416 104.004 22.44 ;
     RECT  103.921 22.44 104.028 22.512 ;
     RECT  103.921 22.512 104.004 22.536 ;
     RECT  103.921 22.536 104.028 22.608 ;
     RECT  103.921 22.608 104.004 22.632 ;
     RECT  103.921 22.632 104.028 22.704 ;
     RECT  103.921 22.704 104.004 22.728 ;
     RECT  103.921 22.728 104.028 22.8 ;
     RECT  103.921 22.8 104.004 22.824 ;
     RECT  103.921 22.824 104.028 22.896 ;
     RECT  103.921 22.896 104.004 22.92 ;
     RECT  103.921 22.92 104.028 22.992 ;
     RECT  103.921 22.992 104.004 23.016 ;
     RECT  103.921 23.016 104.028 23.088 ;
     RECT  103.921 23.088 104.004 23.112 ;
     RECT  103.921 23.112 104.028 23.184 ;
     RECT  103.921 23.184 104.004 23.208 ;
     RECT  103.921 23.208 104.028 23.28 ;
     RECT  103.921 23.28 104.004 23.304 ;
     RECT  103.921 23.304 104.028 23.376 ;
     RECT  103.921 23.376 104.004 23.4 ;
     RECT  103.921 23.4 104.028 23.472 ;
     RECT  103.921 23.472 104.004 23.496 ;
     RECT  103.921 23.496 104.028 23.568 ;
     RECT  103.921 23.568 104.004 23.592 ;
     RECT  103.921 23.592 104.028 23.664 ;
     RECT  103.921 23.664 104.004 23.688 ;
     RECT  103.921 23.688 104.028 23.76 ;
     RECT  103.921 23.76 104.004 23.784 ;
     RECT  103.921 23.784 104.028 23.856 ;
     RECT  103.921 23.856 104.004 23.88 ;
     RECT  103.921 23.88 104.028 23.952 ;
     RECT  103.921 23.952 104.004 23.976 ;
     RECT  103.921 23.976 104.028 24.048 ;
     RECT  103.921 24.048 104.004 24.072 ;
     RECT  103.921 24.072 104.028 24.144 ;
     RECT  103.921 24.144 104.004 24.168 ;
     RECT  103.921 24.168 104.028 24.24 ;
     RECT  103.921 24.24 104.004 24.264 ;
     RECT  103.921 24.264 104.028 24.336 ;
     RECT  103.921 24.336 104.004 24.36 ;
     RECT  103.921 24.36 104.028 24.432 ;
     RECT  103.921 24.432 104.004 24.456 ;
     RECT  103.921 24.456 104.028 24.528 ;
     RECT  103.921 24.528 104.004 24.552 ;
     RECT  103.921 24.552 104.028 24.624 ;
     RECT  103.921 24.624 104.004 24.648 ;
     RECT  103.921 24.648 104.028 24.72 ;
     RECT  103.921 24.72 104.004 24.744 ;
     RECT  103.921 24.744 104.028 24.816 ;
     RECT  103.921 24.816 104.004 24.84 ;
     RECT  103.921 24.84 104.028 24.912 ;
     RECT  103.921 24.912 104.004 24.936 ;
     RECT  103.921 24.936 104.028 25.008 ;
     RECT  103.921 25.008 104.004 25.032 ;
     RECT  103.921 25.032 104.028 25.104 ;
     RECT  103.921 25.104 104.004 25.128 ;
     RECT  103.921 25.128 104.028 25.2 ;
     RECT  103.921 25.2 104.004 25.224 ;
     RECT  103.921 25.224 104.028 25.296 ;
     RECT  103.921 25.296 104.004 25.32 ;
     RECT  103.921 25.32 104.028 25.392 ;
     RECT  103.921 25.392 104.004 25.416 ;
     RECT  103.921 25.416 104.028 25.488 ;
     RECT  103.921 25.488 104.004 25.512 ;
     RECT  103.921 25.512 104.028 25.584 ;
     RECT  103.921 25.584 104.004 25.608 ;
     RECT  103.921 25.608 104.028 25.68 ;
     RECT  103.921 25.68 104.004 25.704 ;
     RECT  103.921 25.704 104.028 25.776 ;
     RECT  103.921 25.776 104.004 25.8 ;
     RECT  103.921 25.8 104.028 25.872 ;
     RECT  103.921 25.872 104.004 25.896 ;
     RECT  103.921 25.896 104.028 25.968 ;
     RECT  103.921 25.968 104.004 25.992 ;
     RECT  103.921 25.992 104.028 26.064 ;
     RECT  103.921 26.064 104.004 26.088 ;
     RECT  103.921 26.088 104.028 26.16 ;
     RECT  103.921 26.16 104.004 26.184 ;
     RECT  103.921 26.184 104.028 26.256 ;
     RECT  103.921 26.256 104.004 26.28 ;
     RECT  103.921 26.28 104.028 26.352 ;
     RECT  103.921 26.352 104.004 26.376 ;
     RECT  103.921 26.376 104.028 26.448 ;
     RECT  103.921 26.448 104.004 26.472 ;
     RECT  103.921 26.472 104.028 26.544 ;
     RECT  103.921 26.544 104.004 26.568 ;
     RECT  103.921 26.568 104.028 26.64 ;
     RECT  103.921 26.64 104.004 26.664 ;
     RECT  103.921 26.664 104.028 26.736 ;
     RECT  103.921 26.736 104.004 26.76 ;
     RECT  103.921 26.76 104.028 26.832 ;
     RECT  103.921 26.832 104.004 26.856 ;
     RECT  103.921 26.856 104.028 26.928 ;
     RECT  103.921 26.928 104.004 26.952 ;
     RECT  103.921 26.952 104.028 27.024 ;
     RECT  103.921 27.024 104.004 27.048 ;
     RECT  103.921 27.048 104.028 27.12 ;
     RECT  103.921 27.12 104.004 27.144 ;
     RECT  103.921 27.144 104.028 27.216 ;
     RECT  103.921 27.216 104.004 27.24 ;
     RECT  103.921 27.24 104.028 27.312 ;
     RECT  103.921 27.312 104.004 27.336 ;
     RECT  103.921 27.336 104.028 27.408 ;
     RECT  103.921 27.408 104.004 27.432 ;
     RECT  103.921 27.432 104.028 27.504 ;
     RECT  103.921 27.504 104.004 27.528 ;
     RECT  103.921 27.528 104.028 27.6 ;
     RECT  103.921 27.6 104.004 27.624 ;
     RECT  103.921 27.624 104.028 27.696 ;
     RECT  103.921 27.696 104.004 27.72 ;
     RECT  103.921 27.72 104.028 27.792 ;
     RECT  103.921 27.792 104.004 27.816 ;
     RECT  103.921 27.816 104.028 27.888 ;
     RECT  103.921 27.888 104.004 27.912 ;
     RECT  103.921 27.912 104.028 27.984 ;
     RECT  103.921 27.984 104.004 28.008 ;
     RECT  103.921 28.008 104.028 28.08 ;
     RECT  103.921 28.08 104.004 28.104 ;
     RECT  103.921 28.104 104.028 28.176 ;
     RECT  103.921 28.176 104.004 28.2 ;
     RECT  103.921 28.2 104.028 28.272 ;
     RECT  103.921 28.272 104.004 28.296 ;
     RECT  103.921 28.296 104.028 28.368 ;
     RECT  103.921 28.368 104.004 28.392 ;
     RECT  103.921 28.392 104.028 28.464 ;
     RECT  103.921 28.464 104.004 28.488 ;
     RECT  103.921 28.488 104.028 28.56 ;
     RECT  103.921 28.56 104.004 28.584 ;
     RECT  103.921 28.584 104.028 28.656 ;
     RECT  103.921 28.656 104.004 28.68 ;
     RECT  103.921 28.68 104.028 28.752 ;
     RECT  103.921 28.752 104.004 28.776 ;
     RECT  103.921 28.776 104.028 28.848 ;
     RECT  103.921 28.848 104.004 28.872 ;
     RECT  103.921 28.872 104.028 28.944 ;
     RECT  103.921 28.944 104.004 28.968 ;
     RECT  103.921 28.968 104.028 29.04 ;
     RECT  103.921 29.04 104.004 29.064 ;
     RECT  103.921 29.064 104.028 29.136 ;
     RECT  103.921 29.136 104.004 29.16 ;
     RECT  103.921 29.16 104.028 29.232 ;
     RECT  103.921 29.232 104.004 29.256 ;
     RECT  103.921 29.256 104.028 29.328 ;
     RECT  103.921 29.328 104.004 29.352 ;
     RECT  103.921 29.352 104.028 29.424 ;
     RECT  103.921 29.424 104.004 29.448 ;
     RECT  103.921 29.448 104.028 29.52 ;
     RECT  103.921 29.52 104.004 29.544 ;
     RECT  103.921 29.544 104.028 29.616 ;
     RECT  103.921 29.616 104.004 29.64 ;
     RECT  103.921 29.64 104.028 29.712 ;
     RECT  103.921 29.712 104.004 29.736 ;
     RECT  103.921 29.736 104.028 29.808 ;
     RECT  103.921 29.808 104.004 29.832 ;
     RECT  103.921 29.832 104.028 29.904 ;
     RECT  103.921 29.904 104.004 29.928 ;
     RECT  103.921 29.928 104.028 30 ;
     RECT  103.921 30 104.004 30.024 ;
     RECT  103.921 30.024 104.028 30.096 ;
     RECT  103.921 30.096 104.004 30.12 ;
     RECT  103.921 30.12 104.028 30.192 ;
     RECT  103.921 30.192 104.004 30.216 ;
     RECT  103.921 30.216 104.028 30.288 ;
     RECT  103.921 30.288 104.004 30.312 ;
     RECT  103.921 30.312 104.028 30.384 ;
     RECT  103.921 30.384 104.004 30.408 ;
     RECT  103.921 30.408 104.028 30.48 ;
     RECT  103.921 30.48 104.004 30.504 ;
     RECT  103.921 30.504 104.028 30.576 ;
     RECT  103.921 30.576 104.004 30.6 ;
     RECT  103.921 30.6 104.028 30.672 ;
     RECT  103.921 30.672 104.004 30.696 ;
     RECT  103.921 30.696 104.028 30.768 ;
     RECT  103.921 30.768 104.004 30.792 ;
     RECT  103.921 30.792 104.028 30.864 ;
     RECT  103.921 30.864 104.004 30.888 ;
     RECT  103.921 30.888 104.028 30.96 ;
     RECT  103.921 30.96 104.004 30.984 ;
     RECT  103.921 30.984 104.028 31.056 ;
     RECT  103.921 31.056 104.004 31.08 ;
     RECT  103.921 31.08 104.028 31.152 ;
     RECT  103.921 31.152 104.004 31.176 ;
     RECT  103.921 31.176 104.028 31.248 ;
     RECT  103.921 31.248 104.004 31.272 ;
     RECT  103.921 31.272 104.028 31.344 ;
     RECT  103.921 31.344 104.004 31.368 ;
     RECT  103.921 31.368 104.028 31.44 ;
     RECT  103.921 31.44 104.004 31.464 ;
     RECT  103.921 31.464 104.028 31.536 ;
     RECT  103.921 31.536 104.004 31.56 ;
     RECT  103.921 31.56 104.028 31.632 ;
     RECT  103.921 31.632 104.004 31.656 ;
     RECT  103.921 31.656 104.028 31.728 ;
     RECT  103.921 31.728 104.004 31.752 ;
     RECT  103.921 31.752 104.028 31.824 ;
     RECT  103.921 31.824 104.004 31.848 ;
     RECT  103.921 31.848 104.028 31.92 ;
     RECT  103.921 31.92 104.004 31.944 ;
     RECT  103.921 31.944 104.028 32.016 ;
     RECT  103.921 32.016 104.004 32.04 ;
     RECT  103.921 32.04 104.028 32.112 ;
     RECT  103.921 32.112 104.004 32.136 ;
     RECT  103.921 32.136 104.028 32.208 ;
     RECT  103.921 32.208 104.004 32.232 ;
     RECT  103.921 32.232 104.028 32.304 ;
     RECT  103.921 32.304 104.004 32.328 ;
     RECT  103.921 32.328 104.028 32.4 ;
     RECT  103.921 32.4 104.004 32.424 ;
     RECT  103.921 32.424 104.028 32.496 ;
     RECT  103.921 32.496 104.004 32.52 ;
     RECT  103.921 32.52 104.028 32.592 ;
     RECT  103.921 32.592 104.004 32.616 ;
     RECT  103.921 32.616 104.028 32.688 ;
     RECT  103.921 32.688 104.004 32.712 ;
     RECT  103.921 32.712 104.028 32.784 ;
     RECT  103.921 32.784 104.004 32.808 ;
     RECT  103.921 32.808 104.028 32.88 ;
     RECT  103.921 32.88 104.004 32.904 ;
     RECT  103.921 32.904 104.028 32.976 ;
     RECT  103.921 32.976 104.004 33 ;
     RECT  103.921 33 104.028 33.072 ;
     RECT  103.921 33.072 104.004 33.096 ;
     RECT  103.921 33.096 104.028 33.168 ;
     RECT  103.921 33.168 104.004 33.192 ;
     RECT  103.921 33.192 104.028 33.264 ;
     RECT  103.921 33.264 104.004 33.288 ;
     RECT  103.921 33.288 104.028 33.36 ;
     RECT  103.921 33.36 104.004 33.384 ;
     RECT  103.921 33.384 104.028 33.456 ;
     RECT  103.921 33.456 104.004 33.48 ;
     RECT  103.921 33.48 104.028 33.552 ;
     RECT  103.921 33.552 104.004 33.576 ;
     RECT  103.921 33.576 104.028 33.648 ;
     RECT  103.921 33.648 104.004 33.672 ;
     RECT  103.921 33.672 104.028 33.744 ;
     RECT  103.921 33.744 104.004 33.768 ;
     RECT  103.921 33.768 104.028 33.84 ;
     RECT  103.921 33.84 104.004 33.864 ;
     RECT  103.921 33.864 104.028 33.936 ;
     RECT  103.921 33.936 104.004 33.96 ;
     RECT  103.921 33.96 104.028 34.032 ;
     RECT  103.921 34.032 104.004 34.056 ;
     RECT  103.921 34.056 104.028 34.128 ;
     RECT  103.921 34.128 104.004 34.152 ;
     RECT  103.921 34.152 104.028 34.224 ;
     RECT  103.921 34.224 104.004 34.248 ;
     RECT  103.921 34.248 104.028 34.32 ;
     RECT  103.921 34.32 104.004 34.344 ;
     RECT  103.921 34.344 104.028 34.416 ;
     RECT  103.921 34.416 104.004 34.44 ;
     RECT  103.921 34.44 104.028 34.512 ;
     RECT  103.921 34.512 104.004 34.536 ;
     RECT  103.921 34.536 104.028 34.608 ;
     RECT  103.921 34.608 104.004 34.632 ;
     RECT  103.921 34.632 104.028 34.704 ;
     RECT  103.921 34.704 104.004 34.728 ;
     RECT  103.921 34.728 104.028 34.8 ;
     RECT  103.921 34.8 104.004 34.824 ;
     RECT  103.921 34.824 104.028 34.896 ;
     RECT  103.921 34.896 104.004 34.92 ;
     RECT  103.921 34.92 104.028 34.992 ;
     RECT  103.921 34.992 104.004 35.016 ;
     RECT  103.921 35.016 104.028 35.088 ;
     RECT  103.921 35.088 104.004 35.112 ;
     RECT  103.921 35.112 104.028 35.184 ;
     RECT  103.921 35.184 104.004 35.208 ;
     RECT  103.921 35.208 104.028 35.28 ;
     RECT  103.921 35.28 104.004 35.304 ;
     RECT  103.921 35.304 104.028 35.376 ;
     RECT  103.921 35.376 104.004 35.4 ;
     RECT  103.921 35.4 104.028 35.472 ;
     RECT  103.921 35.472 104.004 35.496 ;
     RECT  103.921 35.496 104.028 35.568 ;
     RECT  103.921 35.568 104.004 35.592 ;
     RECT  103.921 35.592 104.028 35.664 ;
     RECT  103.921 35.664 104.004 35.688 ;
     RECT  103.921 35.688 104.028 35.76 ;
     RECT  103.921 35.76 104.004 35.784 ;
     RECT  103.921 35.784 104.028 35.856 ;
     RECT  103.921 35.856 104.004 35.88 ;
     RECT  103.921 35.88 104.028 35.952 ;
     RECT  103.921 35.952 104.004 35.976 ;
     RECT  103.921 35.976 104.028 36.048 ;
     RECT  103.921 36.048 104.004 36.072 ;
     RECT  103.921 36.072 104.028 36.144 ;
     RECT  103.921 36.144 104.004 36.168 ;
     RECT  103.921 36.168 104.028 36.24 ;
     RECT  103.921 36.24 104.004 36.264 ;
     RECT  103.921 36.264 104.028 36.336 ;
     RECT  103.921 36.336 104.004 36.36 ;
     RECT  103.921 36.36 104.028 36.432 ;
     RECT  103.921 36.432 104.004 36.456 ;
     RECT  103.921 36.456 104.028 36.528 ;
     RECT  103.921 36.528 104.004 36.552 ;
     RECT  103.921 36.552 104.028 36.624 ;
     RECT  103.921 36.624 104.004 36.648 ;
     RECT  103.921 36.648 104.028 36.72 ;
     RECT  103.921 36.72 104.004 36.744 ;
     RECT  103.921 36.744 104.028 36.816 ;
     RECT  103.921 36.816 104.004 36.84 ;
     RECT  103.921 36.84 104.028 36.912 ;
     RECT  103.921 36.912 104.004 36.936 ;
     RECT  103.921 36.936 104.028 37.008 ;
     RECT  103.921 37.008 104.004 37.032 ;
     RECT  103.921 37.032 104.028 37.104 ;
     RECT  103.921 37.104 104.004 37.128 ;
     RECT  103.921 37.128 104.028 37.2 ;
     RECT  103.921 37.2 104.004 37.224 ;
     RECT  103.921 37.224 104.028 37.296 ;
     RECT  103.921 37.296 104.004 37.32 ;
     RECT  103.921 37.32 104.028 37.392 ;
     RECT  103.921 37.392 104.004 37.416 ;
     RECT  103.921 37.416 104.028 37.488 ;
     RECT  103.921 37.488 104.004 37.512 ;
     RECT  103.921 37.512 104.028 37.584 ;
     RECT  103.921 37.584 104.004 37.608 ;
     RECT  103.921 37.608 104.028 37.68 ;
     RECT  103.921 37.68 104.004 37.704 ;
     RECT  103.921 37.704 104.028 37.776 ;
     RECT  103.921 37.776 104.004 37.8 ;
     RECT  103.921 37.8 104.028 37.872 ;
     RECT  103.921 37.872 104.004 37.896 ;
     RECT  103.921 37.896 104.028 37.968 ;
     RECT  103.921 37.968 104.004 37.992 ;
     RECT  103.921 37.992 104.028 38.064 ;
     RECT  103.921 38.064 104.004 38.088 ;
     RECT  103.921 38.088 104.028 38.16 ;
     RECT  103.921 38.16 104.004 38.184 ;
     RECT  103.921 38.184 104.028 38.256 ;
     RECT  103.921 38.256 104.004 38.28 ;
     RECT  103.921 38.28 104.028 39.12 ;
     RECT  103.921 39.12 104.004 39.144 ;
     RECT  103.921 39.144 104.028 39.216 ;
     RECT  103.921 39.216 104.004 39.24 ;
     RECT  103.921 39.24 104.028 39.312 ;
     RECT  103.921 39.312 104.004 39.336 ;
     RECT  103.921 39.336 104.028 39.408 ;
     RECT  103.921 39.408 104.004 39.432 ;
     RECT  103.921 39.432 104.028 39.504 ;
     RECT  103.921 39.504 104.004 39.528 ;
     RECT  103.921 39.528 104.028 39.6 ;
     RECT  103.921 39.6 104.004 39.624 ;
     RECT  103.921 39.624 104.028 39.696 ;
     RECT  103.921 39.696 104.004 39.72 ;
     RECT  103.921 39.72 104.028 39.792 ;
     RECT  103.921 39.792 104.004 39.816 ;
     RECT  103.921 39.816 104.028 39.888 ;
     RECT  103.921 39.888 104.004 39.912 ;
     RECT  103.921 39.912 104.028 39.984 ;
     RECT  103.921 39.984 104.004 40.008 ;
     RECT  103.921 40.008 104.028 40.08 ;
     RECT  103.921 40.08 104.004 40.104 ;
     RECT  103.921 40.104 104.028 40.176 ;
     RECT  103.921 40.176 104.004 40.2 ;
     RECT  103.921 40.2 104.028 40.272 ;
     RECT  103.921 40.272 104.004 40.296 ;
     RECT  103.921 40.296 104.028 40.368 ;
     RECT  103.921 40.368 104.004 40.392 ;
     RECT  103.921 40.392 104.028 40.464 ;
     RECT  103.921 40.464 104.004 40.488 ;
     RECT  103.921 40.488 104.028 40.56 ;
     RECT  103.921 40.56 104.004 40.584 ;
     RECT  103.921 40.584 104.028 40.656 ;
     RECT  103.921 40.656 104.004 40.68 ;
     RECT  103.921 40.68 104.028 40.752 ;
     RECT  103.921 40.752 104.004 40.776 ;
     RECT  103.921 40.776 104.028 40.848 ;
     RECT  103.921 40.848 104.004 40.872 ;
     RECT  103.921 40.872 104.028 40.944 ;
     RECT  103.921 40.944 104.004 40.968 ;
     RECT  103.921 40.968 104.028 41.04 ;
     RECT  103.921 41.04 104.004 41.064 ;
     RECT  103.921 41.064 104.028 41.136 ;
     RECT  103.921 41.136 104.004 41.16 ;
     RECT  103.921 41.16 104.028 41.232 ;
     RECT  103.921 41.232 104.004 41.256 ;
     RECT  103.921 41.256 104.028 41.328 ;
     RECT  103.921 41.328 104.004 41.352 ;
     RECT  103.921 41.352 104.028 41.424 ;
     RECT  103.921 41.424 104.004 41.448 ;
     RECT  103.921 41.448 104.028 41.52 ;
     RECT  103.921 41.52 104.004 41.544 ;
     RECT  103.921 41.544 104.028 41.616 ;
     RECT  103.921 41.616 104.004 41.64 ;
     RECT  103.921 41.64 104.028 41.712 ;
     RECT  103.921 41.712 104.004 41.736 ;
     RECT  103.921 41.736 104.028 41.808 ;
     RECT  103.921 41.808 104.004 41.832 ;
     RECT  103.921 41.832 104.028 41.904 ;
     RECT  103.921 41.904 104.004 41.928 ;
     RECT  103.921 41.928 104.028 42 ;
     RECT  103.921 42 104.004 42.024 ;
     RECT  103.921 42.024 104.028 42.096 ;
     RECT  103.921 42.096 104.004 42.12 ;
     RECT  103.921 42.12 104.028 42.192 ;
     RECT  103.921 42.192 104.004 42.216 ;
     RECT  103.921 42.216 104.028 42.288 ;
     RECT  103.921 42.288 104.004 42.312 ;
     RECT  103.921 42.312 104.028 42.384 ;
     RECT  103.921 42.384 104.004 42.408 ;
     RECT  103.921 42.408 104.028 42.48 ;
     RECT  103.921 42.48 104.004 42.504 ;
     RECT  103.921 42.504 104.028 42.576 ;
     RECT  103.921 42.576 104.004 42.6 ;
     RECT  103.921 42.6 104.028 42.672 ;
     RECT  103.921 42.672 104.004 42.696 ;
     RECT  103.921 42.696 104.028 42.768 ;
     RECT  103.921 42.768 104.004 42.792 ;
     RECT  103.921 42.792 104.028 42.864 ;
     RECT  103.921 42.864 104.004 42.888 ;
     RECT  103.921 42.888 104.028 42.96 ;
     RECT  103.921 42.96 104.004 42.984 ;
     RECT  103.921 42.984 104.028 43.056 ;
     RECT  103.921 43.056 104.004 43.08 ;
     RECT  103.921 43.08 104.028 43.152 ;
     RECT  103.921 43.152 104.004 43.176 ;
     RECT  103.921 43.176 104.028 43.248 ;
     RECT  103.921 43.248 104.004 43.272 ;
     RECT  103.921 43.272 104.028 43.344 ;
     RECT  103.921 43.344 104.004 43.368 ;
     RECT  103.921 43.368 104.028 43.44 ;
     RECT  103.921 43.44 104.004 43.464 ;
     RECT  103.921 43.464 104.028 43.536 ;
     RECT  103.921 43.536 104.004 43.56 ;
     RECT  103.921 43.56 104.028 43.632 ;
     RECT  103.921 43.632 104.004 43.656 ;
     RECT  103.921 43.656 104.028 43.728 ;
     RECT  103.921 43.728 104.004 43.752 ;
     RECT  103.921 43.752 104.028 43.824 ;
     RECT  103.921 43.824 104.004 43.848 ;
     RECT  103.921 43.848 104.028 43.92 ;
     RECT  103.921 43.92 104.004 43.944 ;
     RECT  103.921 43.944 104.028 44.016 ;
     RECT  103.921 44.016 104.004 44.04 ;
     RECT  103.921 44.04 104.028 44.112 ;
     RECT  103.921 44.112 104.004 44.136 ;
     RECT  103.921 44.136 104.028 44.208 ;
     RECT  103.921 44.208 104.004 44.232 ;
     RECT  103.921 44.232 104.028 44.304 ;
     RECT  103.921 44.304 104.004 44.328 ;
     RECT  103.921 44.328 104.028 44.4 ;
     RECT  103.921 44.4 104.004 44.424 ;
     RECT  103.921 44.424 104.028 44.496 ;
     RECT  103.921 44.496 104.004 44.52 ;
     RECT  103.921 44.52 104.028 44.592 ;
     RECT  103.921 44.592 104.004 44.616 ;
     RECT  103.921 44.616 104.028 44.688 ;
     RECT  103.921 44.688 104.004 44.712 ;
     RECT  103.921 44.712 104.028 44.784 ;
     RECT  103.921 44.784 104.004 44.808 ;
     RECT  103.921 44.808 104.028 44.88 ;
     RECT  103.921 44.88 104.004 44.904 ;
     RECT  103.921 44.904 104.028 44.976 ;
     RECT  103.921 44.976 104.004 45 ;
     RECT  103.921 45 104.028 45.072 ;
     RECT  103.921 45.072 104.004 45.096 ;
     RECT  103.921 45.096 104.028 45.168 ;
     RECT  103.921 45.168 104.004 45.192 ;
     RECT  103.921 45.192 104.028 45.264 ;
     RECT  103.921 45.264 104.004 45.288 ;
     RECT  103.921 45.288 104.028 45.36 ;
     RECT  103.921 45.36 104.004 45.384 ;
     RECT  103.921 45.384 104.028 45.456 ;
     RECT  103.921 45.456 104.004 45.48 ;
     RECT  103.921 45.48 104.028 45.552 ;
     RECT  103.921 45.552 104.004 45.576 ;
     RECT  103.921 45.576 104.028 45.648 ;
     RECT  103.921 45.648 104.004 45.672 ;
     RECT  103.921 45.672 104.028 45.744 ;
     RECT  103.921 45.744 104.004 45.768 ;
     RECT  103.921 45.768 104.028 45.84 ;
     RECT  103.921 45.84 104.004 45.864 ;
     RECT  103.921 45.864 104.028 45.936 ;
     RECT  103.921 45.936 104.004 45.96 ;
     RECT  103.921 45.96 104.028 46.032 ;
     RECT  103.921 46.032 104.004 46.056 ;
     RECT  103.921 46.056 104.028 46.128 ;
     RECT  103.921 46.128 104.004 46.152 ;
     RECT  103.921 46.152 104.028 46.224 ;
     RECT  103.921 46.224 104.004 46.248 ;
     RECT  103.921 46.248 104.028 46.32 ;
     RECT  103.921 46.32 104.004 46.344 ;
     RECT  103.921 46.344 104.028 46.416 ;
     RECT  103.921 46.416 104.004 46.44 ;
     RECT  103.921 46.44 104.028 46.512 ;
     RECT  103.921 46.512 104.004 46.536 ;
     RECT  103.921 46.536 104.028 46.608 ;
     RECT  103.921 46.608 104.004 46.632 ;
     RECT  103.921 46.632 104.028 46.704 ;
     RECT  103.921 46.704 104.004 46.728 ;
     RECT  103.921 46.728 104.028 46.8 ;
     RECT  103.921 46.8 104.004 46.824 ;
     RECT  103.921 46.824 104.028 46.896 ;
     RECT  103.921 46.896 104.004 46.92 ;
     RECT  103.921 46.92 104.028 46.992 ;
     RECT  103.921 46.992 104.004 47.016 ;
     RECT  103.921 47.016 104.028 47.088 ;
     RECT  103.921 47.088 104.004 47.112 ;
     RECT  103.921 47.112 104.028 47.184 ;
     RECT  103.921 47.184 104.004 47.208 ;
     RECT  103.921 47.208 104.028 47.28 ;
     RECT  103.921 47.28 104.004 47.304 ;
     RECT  103.921 47.304 104.028 47.376 ;
     RECT  103.921 47.376 104.004 47.4 ;
     RECT  103.921 47.4 104.028 47.472 ;
     RECT  103.921 47.472 104.004 47.496 ;
     RECT  103.921 47.496 104.028 47.568 ;
     RECT  103.921 47.568 104.004 47.592 ;
     RECT  103.921 47.592 104.028 47.664 ;
     RECT  103.921 47.664 104.004 47.688 ;
     RECT  103.921 47.688 104.028 47.76 ;
     RECT  103.921 47.76 104.004 47.784 ;
     RECT  103.921 47.784 104.028 47.856 ;
     RECT  103.921 47.856 104.004 47.88 ;
     RECT  103.921 47.88 104.028 47.952 ;
     RECT  103.921 47.952 104.004 47.976 ;
     RECT  103.921 47.976 104.028 48.048 ;
     RECT  103.921 48.048 104.004 48.072 ;
     RECT  103.921 48.072 104.028 48.144 ;
     RECT  103.921 48.144 104.004 48.168 ;
     RECT  103.921 48.168 104.028 48.24 ;
     RECT  103.921 48.24 104.004 48.264 ;
     RECT  103.921 48.264 104.028 48.336 ;
     RECT  103.921 48.336 104.004 48.36 ;
     RECT  103.921 48.36 104.028 48.432 ;
     RECT  103.921 48.432 104.004 48.456 ;
     RECT  103.921 48.456 104.028 48.528 ;
     RECT  103.921 48.528 104.004 48.552 ;
     RECT  103.921 48.552 104.028 48.624 ;
     RECT  103.921 48.624 104.004 48.648 ;
     RECT  103.921 48.648 104.028 48.72 ;
     RECT  103.921 48.72 104.004 48.744 ;
     RECT  103.921 48.744 104.028 48.816 ;
     RECT  103.921 48.816 104.004 48.84 ;
     RECT  103.921 48.84 104.028 48.912 ;
     RECT  103.921 48.912 104.004 48.936 ;
     RECT  103.921 48.936 104.028 49.008 ;
     RECT  103.921 49.008 104.004 49.032 ;
     RECT  103.921 49.032 104.028 49.104 ;
     RECT  103.921 49.104 104.004 49.128 ;
     RECT  103.921 49.128 104.028 49.2 ;
     RECT  103.921 49.2 104.004 49.224 ;
     RECT  103.921 49.224 104.028 49.296 ;
     RECT  103.921 49.296 104.004 49.32 ;
     RECT  103.921 49.32 104.028 49.392 ;
     RECT  103.921 49.392 104.004 49.416 ;
     RECT  103.921 49.416 104.028 49.488 ;
     RECT  103.921 49.488 104.004 49.512 ;
     RECT  103.921 49.512 104.028 49.584 ;
     RECT  103.921 49.584 104.004 49.608 ;
     RECT  103.921 49.608 104.028 49.68 ;
     RECT  103.921 49.68 104.004 49.704 ;
     RECT  103.921 49.704 104.028 49.776 ;
     RECT  103.921 49.776 104.004 49.8 ;
     RECT  103.921 49.8 104.028 49.872 ;
     RECT  103.921 49.872 104.004 49.896 ;
     RECT  103.921 49.896 104.028 49.968 ;
     RECT  103.921 49.968 104.004 49.992 ;
     RECT  103.921 49.992 104.028 50.064 ;
     RECT  103.921 50.064 104.004 50.088 ;
     RECT  103.921 50.088 104.028 50.16 ;
     RECT  103.921 50.16 104.004 50.184 ;
     RECT  103.921 50.184 104.028 50.256 ;
     RECT  103.921 50.256 104.004 50.28 ;
     RECT  103.921 50.28 104.028 50.352 ;
     RECT  103.921 50.352 104.004 50.376 ;
     RECT  103.921 50.376 104.028 50.448 ;
     RECT  103.921 50.448 104.004 50.472 ;
     RECT  103.921 50.472 104.028 50.544 ;
     RECT  103.921 50.544 104.004 50.568 ;
     RECT  103.921 50.568 104.028 50.64 ;
     RECT  103.921 50.64 104.004 50.664 ;
     RECT  103.921 50.664 104.028 50.736 ;
     RECT  103.921 50.736 104.004 50.76 ;
     RECT  103.921 50.76 104.028 50.832 ;
     RECT  103.921 50.832 104.004 50.856 ;
     RECT  103.921 50.856 104.028 50.928 ;
     RECT  103.921 50.928 104.004 50.952 ;
     RECT  103.921 50.952 104.028 51.024 ;
     RECT  103.921 51.024 104.004 51.048 ;
     RECT  103.921 51.048 104.028 51.12 ;
     RECT  103.921 51.12 104.004 51.144 ;
     RECT  103.921 51.144 104.028 51.216 ;
     RECT  103.921 51.216 104.004 51.24 ;
     RECT  103.921 51.24 104.028 51.312 ;
     RECT  103.921 51.312 104.004 51.336 ;
     RECT  103.921 51.336 104.028 51.408 ;
     RECT  103.921 51.408 104.004 51.432 ;
     RECT  103.921 51.432 104.028 51.504 ;
     RECT  103.921 51.504 104.004 51.528 ;
     RECT  103.921 51.528 104.028 51.6 ;
     RECT  103.921 51.6 104.004 51.624 ;
     RECT  103.921 51.624 104.028 51.696 ;
     RECT  103.921 51.696 104.004 51.72 ;
     RECT  103.921 51.72 104.028 51.792 ;
     RECT  103.921 51.792 104.004 51.816 ;
     RECT  103.921 51.816 104.028 51.888 ;
     RECT  103.921 51.888 104.004 51.912 ;
     RECT  103.921 51.912 104.028 51.984 ;
     RECT  103.921 51.984 104.004 52.008 ;
     RECT  103.921 52.008 104.028 52.08 ;
     RECT  103.921 52.08 104.004 52.104 ;
     RECT  103.921 52.104 104.028 52.176 ;
     RECT  103.921 52.176 104.004 52.2 ;
     RECT  103.921 52.2 104.028 52.272 ;
     RECT  103.921 52.272 104.004 52.296 ;
     RECT  103.921 52.296 104.028 52.368 ;
     RECT  103.921 52.368 104.004 52.392 ;
     RECT  103.921 52.392 104.028 52.464 ;
     RECT  103.921 52.464 104.004 52.488 ;
     RECT  103.921 52.488 104.028 52.56 ;
     RECT  103.921 52.56 104.004 52.584 ;
     RECT  103.921 52.584 104.028 52.656 ;
     RECT  103.921 52.656 104.004 52.68 ;
     RECT  103.921 52.68 104.028 52.752 ;
     RECT  103.921 52.752 104.004 52.776 ;
     RECT  103.921 52.776 104.028 52.848 ;
     RECT  103.921 52.848 104.004 52.872 ;
     RECT  103.921 52.872 104.028 52.944 ;
     RECT  103.921 52.944 104.004 52.968 ;
     RECT  103.921 52.968 104.028 53.04 ;
     RECT  103.921 53.04 104.004 53.064 ;
     RECT  103.921 53.064 104.028 53.136 ;
     RECT  103.921 53.136 104.004 53.16 ;
     RECT  103.921 53.16 104.028 53.232 ;
     RECT  103.921 53.232 104.004 53.256 ;
     RECT  103.921 53.256 104.028 53.328 ;
     RECT  103.921 53.328 104.004 53.352 ;
     RECT  103.921 53.352 104.028 53.424 ;
     RECT  103.921 53.424 104.004 53.448 ;
     RECT  103.921 53.448 104.028 53.52 ;
     RECT  103.921 53.52 104.004 53.544 ;
     RECT  103.921 53.544 104.028 53.616 ;
     RECT  103.921 53.616 104.004 53.64 ;
     RECT  103.921 53.64 104.028 53.712 ;
     RECT  103.921 53.712 104.004 53.736 ;
     RECT  103.921 53.736 104.028 53.808 ;
     RECT  103.921 53.808 104.004 53.832 ;
     RECT  103.921 53.832 104.028 53.904 ;
     RECT  103.921 53.904 104.004 53.928 ;
     RECT  103.921 53.928 104.028 54 ;
     RECT  103.921 54 104.004 54.024 ;
     RECT  103.921 54.024 104.028 54.096 ;
     RECT  103.921 54.096 104.004 54.12 ;
     RECT  103.921 54.12 104.028 54.192 ;
     RECT  103.921 54.192 104.004 54.216 ;
     RECT  103.921 54.216 104.028 54.288 ;
     RECT  103.921 54.288 104.004 54.312 ;
     RECT  103.921 54.312 104.028 54.384 ;
     RECT  103.921 54.384 104.004 54.408 ;
     RECT  103.921 54.408 104.028 54.48 ;
     RECT  103.921 54.48 104.004 54.504 ;
     RECT  103.921 54.504 104.028 54.576 ;
     RECT  103.921 54.576 104.004 54.6 ;
     RECT  103.921 54.6 104.028 54.672 ;
     RECT  103.921 54.672 104.004 54.696 ;
     RECT  103.921 54.696 104.028 54.768 ;
     RECT  103.921 54.768 104.004 54.792 ;
     RECT  103.921 54.792 104.028 54.864 ;
     RECT  103.921 54.864 104.004 54.888 ;
     RECT  103.921 54.888 104.028 54.96 ;
     RECT  103.921 54.96 104.004 54.984 ;
     RECT  103.921 54.984 104.028 55.056 ;
     RECT  103.921 55.056 104.004 55.08 ;
     RECT  103.921 55.08 104.028 55.152 ;
     RECT  103.921 55.152 104.004 55.176 ;
     RECT  103.921 55.176 104.028 55.248 ;
     RECT  103.921 55.248 104.004 55.272 ;
     RECT  103.921 55.272 104.028 55.344 ;
     RECT  103.921 55.344 104.004 55.368 ;
     RECT  103.921 55.368 104.028 55.44 ;
     RECT  103.921 55.44 104.004 55.464 ;
     RECT  103.921 55.464 104.028 55.536 ;
     RECT  103.921 55.536 104.004 55.56 ;
     RECT  103.921 55.56 104.028 55.632 ;
     RECT  103.921 55.632 104.004 55.656 ;
     RECT  103.921 55.656 104.028 55.728 ;
     RECT  103.921 55.728 104.004 55.752 ;
     RECT  103.921 55.752 104.028 55.824 ;
     RECT  103.921 55.824 104.004 55.848 ;
     RECT  103.921 55.848 104.028 55.92 ;
     RECT  103.921 55.92 104.004 55.944 ;
     RECT  103.921 55.944 104.028 56.016 ;
     RECT  103.921 56.016 104.004 56.04 ;
     RECT  103.921 56.04 104.028 56.112 ;
     RECT  103.921 56.112 104.004 56.136 ;
     RECT  103.921 56.136 104.028 56.208 ;
     RECT  103.921 56.208 104.004 56.232 ;
     RECT  103.921 56.232 104.028 56.304 ;
     RECT  103.921 56.304 104.004 56.328 ;
     RECT  103.921 56.328 104.028 56.4 ;
     RECT  103.921 56.4 104.004 56.424 ;
     RECT  103.921 56.424 104.028 56.496 ;
     RECT  103.921 56.496 104.004 56.52 ;
     RECT  103.921 56.52 104.028 56.592 ;
     RECT  103.921 56.592 104.004 56.616 ;
     RECT  103.921 56.616 104.028 56.688 ;
     RECT  103.921 56.688 104.004 56.712 ;
     RECT  103.921 56.712 104.028 56.784 ;
     RECT  103.921 56.784 104.004 56.808 ;
     RECT  103.921 56.808 104.028 56.88 ;
     RECT  103.921 56.88 104.004 56.904 ;
     RECT  103.921 56.904 104.028 56.976 ;
     RECT  103.921 56.976 104.004 57 ;
     RECT  103.921 57 104.028 57.072 ;
     RECT  103.921 57.072 104.004 57.096 ;
     RECT  103.921 57.096 104.028 57.168 ;
     RECT  103.921 57.168 104.004 57.192 ;
     RECT  103.921 57.192 104.028 57.264 ;
     RECT  103.921 57.264 104.004 57.288 ;
     RECT  103.921 57.288 104.028 57.36 ;
     RECT  103.921 57.36 104.004 57.384 ;
     RECT  103.921 57.384 104.028 57.456 ;
     RECT  103.921 57.456 104.004 57.48 ;
     RECT  103.921 57.48 104.028 58.32 ;
     RECT  103.921 58.32 104.004 58.344 ;
     RECT  103.921 58.344 104.028 58.416 ;
     RECT  103.921 58.416 104.004 58.44 ;
     RECT  103.921 58.44 104.028 58.512 ;
     RECT  103.921 58.512 104.004 58.536 ;
     RECT  103.921 58.536 104.028 58.608 ;
     RECT  103.921 58.608 104.004 58.632 ;
     RECT  103.921 58.632 104.028 58.704 ;
     RECT  103.921 58.704 104.004 58.728 ;
     RECT  103.921 58.728 104.028 58.8 ;
     RECT  103.921 58.8 104.004 58.824 ;
     RECT  103.921 58.824 104.028 58.896 ;
     RECT  103.921 58.896 104.004 58.92 ;
     RECT  103.921 58.92 104.028 58.992 ;
     RECT  103.921 58.992 104.004 59.016 ;
     RECT  103.921 59.016 104.028 59.088 ;
     RECT  103.921 59.088 104.004 59.112 ;
     RECT  103.921 59.112 104.028 59.184 ;
     RECT  103.921 59.184 104.004 59.208 ;
     RECT  103.921 59.208 104.028 59.28 ;
     RECT  103.921 59.28 104.004 59.304 ;
     RECT  103.921 59.304 104.028 59.376 ;
     RECT  103.921 59.376 104.004 59.4 ;
     RECT  103.921 59.4 104.028 59.472 ;
     RECT  103.921 59.472 104.004 59.496 ;
     RECT  103.921 59.496 104.028 59.568 ;
     RECT  103.921 59.568 104.004 59.592 ;
     RECT  103.921 59.592 104.028 59.664 ;
     RECT  103.921 59.664 104.004 59.688 ;
     RECT  103.921 59.688 104.028 59.76 ;
     RECT  103.921 59.76 104.004 59.784 ;
     RECT  103.921 59.784 104.028 59.856 ;
     RECT  103.921 59.856 104.004 59.88 ;
     RECT  103.921 59.88 104.028 59.952 ;
     RECT  103.921 59.952 104.004 59.976 ;
     RECT  103.921 59.976 104.028 60.048 ;
     RECT  103.921 60.048 104.004 60.072 ;
     RECT  103.921 60.072 104.028 60.144 ;
     RECT  103.921 60.144 104.004 60.168 ;
     RECT  103.921 60.168 104.028 60.24 ;
     RECT  103.921 60.24 104.004 60.264 ;
     RECT  103.921 60.264 104.028 60.336 ;
     RECT  103.921 60.336 104.004 60.36 ;
     RECT  103.921 60.36 104.028 60.432 ;
     RECT  103.921 60.432 104.004 60.456 ;
     RECT  103.921 60.456 104.028 60.528 ;
     RECT  103.921 60.528 104.004 60.552 ;
     RECT  103.921 60.552 104.028 60.624 ;
     RECT  103.921 60.624 104.004 60.648 ;
     RECT  103.921 60.648 104.028 60.72 ;
     RECT  103.921 60.72 104.004 60.744 ;
     RECT  103.921 60.744 104.028 60.816 ;
     RECT  103.921 60.816 104.004 60.84 ;
     RECT  103.921 60.84 104.028 60.912 ;
     RECT  103.921 60.912 104.004 60.936 ;
     RECT  103.921 60.936 104.028 61.008 ;
     RECT  103.921 61.008 104.004 61.032 ;
     RECT  103.921 61.032 104.028 61.104 ;
     RECT  103.921 61.104 104.004 61.128 ;
     RECT  103.921 61.128 104.028 61.2 ;
     RECT  103.921 61.2 104.004 61.224 ;
     RECT  103.921 61.224 104.028 61.296 ;
     RECT  103.921 61.296 104.004 61.32 ;
     RECT  103.921 61.32 104.028 61.392 ;
     RECT  103.921 61.392 104.004 61.416 ;
     RECT  103.921 61.416 104.028 61.488 ;
     RECT  103.921 61.488 104.004 61.512 ;
     RECT  103.921 61.512 104.028 61.584 ;
     RECT  103.921 61.584 104.004 61.608 ;
     RECT  103.921 61.608 104.028 61.68 ;
     RECT  103.921 61.68 104.004 61.704 ;
     RECT  103.921 61.704 104.028 61.776 ;
     RECT  103.921 61.776 104.004 61.8 ;
     RECT  103.921 61.8 104.028 61.872 ;
     RECT  103.921 61.872 104.004 61.896 ;
     RECT  103.921 61.896 104.028 61.968 ;
     RECT  103.921 61.968 104.004 61.992 ;
     RECT  103.921 61.992 104.028 62.064 ;
     RECT  103.921 62.064 104.004 62.088 ;
     RECT  103.921 62.088 104.028 62.16 ;
     RECT  103.921 62.16 104.004 62.184 ;
     RECT  103.921 62.184 104.028 62.256 ;
     RECT  103.921 62.256 104.004 62.28 ;
     RECT  103.921 62.28 104.028 62.352 ;
     RECT  103.921 62.352 104.004 62.376 ;
     RECT  103.921 62.376 104.028 62.448 ;
     RECT  103.921 62.448 104.004 62.472 ;
     RECT  103.921 62.472 104.028 62.544 ;
     RECT  103.921 62.544 104.004 62.568 ;
     RECT  103.921 62.568 104.028 62.64 ;
     RECT  103.921 62.64 104.004 62.664 ;
     RECT  103.921 62.664 104.028 62.736 ;
     RECT  103.921 62.736 104.004 62.76 ;
     RECT  103.921 62.76 104.028 62.832 ;
     RECT  103.921 62.832 104.004 62.856 ;
     RECT  103.921 62.856 104.028 62.928 ;
     RECT  103.921 62.928 104.004 62.952 ;
     RECT  103.921 62.952 104.028 63.024 ;
     RECT  103.921 63.024 104.004 63.048 ;
     RECT  103.921 63.048 104.028 63.12 ;
     RECT  103.921 63.12 104.004 63.144 ;
     RECT  103.921 63.144 104.028 63.216 ;
     RECT  103.921 63.216 104.004 63.24 ;
     RECT  103.921 63.24 104.028 63.312 ;
     RECT  103.921 63.312 104.004 63.336 ;
     RECT  103.921 63.336 104.028 63.408 ;
     RECT  103.921 63.408 104.004 63.432 ;
     RECT  103.921 63.432 104.028 63.504 ;
     RECT  103.921 63.504 104.004 63.528 ;
     RECT  103.921 63.528 104.028 63.6 ;
     RECT  103.921 63.6 104.004 63.624 ;
     RECT  103.921 63.624 104.028 63.696 ;
     RECT  103.921 63.696 104.004 63.72 ;
     RECT  103.921 63.72 104.028 63.792 ;
     RECT  103.921 63.792 104.004 63.816 ;
     RECT  103.921 63.816 104.028 63.888 ;
     RECT  103.921 63.888 104.004 63.912 ;
     RECT  103.921 63.912 104.028 63.984 ;
     RECT  103.921 63.984 104.004 64.008 ;
     RECT  103.921 64.008 104.028 64.08 ;
     RECT  103.921 64.08 104.004 64.104 ;
     RECT  103.921 64.104 104.028 64.176 ;
     RECT  103.921 64.176 104.004 64.2 ;
     RECT  103.921 64.2 104.028 64.272 ;
     RECT  103.921 64.272 104.004 64.296 ;
     RECT  103.921 64.296 104.028 64.368 ;
     RECT  103.921 64.368 104.004 64.392 ;
     RECT  103.921 64.392 104.028 64.464 ;
     RECT  103.921 64.464 104.004 64.488 ;
     RECT  103.921 64.488 104.028 64.56 ;
     RECT  103.921 64.56 104.004 64.584 ;
     RECT  103.921 64.584 104.028 64.656 ;
     RECT  103.921 64.656 104.004 64.68 ;
     RECT  103.921 64.68 104.028 64.752 ;
     RECT  103.921 64.752 104.004 64.776 ;
     RECT  103.921 64.776 104.028 64.848 ;
     RECT  103.921 64.848 104.004 64.872 ;
     RECT  103.921 64.872 104.028 64.944 ;
     RECT  103.921 64.944 104.004 64.968 ;
     RECT  103.921 64.968 104.028 65.04 ;
     RECT  103.921 65.04 104.004 65.064 ;
     RECT  103.921 65.064 104.028 65.136 ;
     RECT  103.921 65.136 104.004 65.16 ;
     RECT  103.921 65.16 104.028 65.232 ;
     RECT  103.921 65.232 104.004 65.256 ;
     RECT  103.921 65.256 104.028 65.328 ;
     RECT  103.921 65.328 104.004 65.352 ;
     RECT  103.921 65.352 104.028 65.424 ;
     RECT  103.921 65.424 104.004 65.448 ;
     RECT  103.921 65.448 104.028 65.52 ;
     RECT  103.921 65.52 104.004 65.544 ;
     RECT  103.921 65.544 104.028 65.616 ;
     RECT  103.921 65.616 104.004 65.64 ;
     RECT  103.921 65.64 104.028 65.712 ;
     RECT  103.921 65.712 104.004 65.736 ;
     RECT  103.921 65.736 104.028 65.808 ;
     RECT  103.921 65.808 104.004 65.832 ;
     RECT  103.921 65.832 104.028 65.904 ;
     RECT  103.921 65.904 104.004 65.928 ;
     RECT  103.921 65.928 104.028 66 ;
     RECT  103.921 66 104.004 66.024 ;
     RECT  103.921 66.024 104.028 66.096 ;
     RECT  103.921 66.096 104.004 66.12 ;
     RECT  103.921 66.12 104.028 66.192 ;
     RECT  103.921 66.192 104.004 66.216 ;
     RECT  103.921 66.216 104.028 66.288 ;
     RECT  103.921 66.288 104.004 66.312 ;
     RECT  103.921 66.312 104.028 66.384 ;
     RECT  103.921 66.384 104.004 66.408 ;
     RECT  103.921 66.408 104.028 66.48 ;
     RECT  103.921 66.48 104.004 66.504 ;
     RECT  103.921 66.504 104.028 66.576 ;
     RECT  103.921 66.576 104.004 66.6 ;
     RECT  103.921 66.6 104.028 66.672 ;
     RECT  103.921 66.672 104.004 66.696 ;
     RECT  103.921 66.696 104.028 66.768 ;
     RECT  103.921 66.768 104.004 66.792 ;
     RECT  103.921 66.792 104.028 66.864 ;
     RECT  103.921 66.864 104.004 66.888 ;
     RECT  103.921 66.888 104.028 66.96 ;
     RECT  103.921 66.96 104.004 66.984 ;
     RECT  103.921 66.984 104.028 67.056 ;
     RECT  103.921 67.056 104.004 67.08 ;
     RECT  103.921 67.08 104.028 67.152 ;
     RECT  103.921 67.152 104.004 67.176 ;
     RECT  103.921 67.176 104.028 67.248 ;
     RECT  103.921 67.248 104.004 67.272 ;
     RECT  103.921 67.272 104.028 67.344 ;
     RECT  103.921 67.344 104.004 67.368 ;
     RECT  103.921 67.368 104.028 67.44 ;
     RECT  103.921 67.44 104.004 67.464 ;
     RECT  103.921 67.464 104.028 67.536 ;
     RECT  103.921 67.536 104.004 67.56 ;
     RECT  103.921 67.56 104.028 67.632 ;
     RECT  103.921 67.632 104.004 67.656 ;
     RECT  103.921 67.656 104.028 67.728 ;
     RECT  103.921 67.728 104.004 67.752 ;
     RECT  103.921 67.752 104.028 67.824 ;
     RECT  103.921 67.824 104.004 67.848 ;
     RECT  103.921 67.848 104.028 67.92 ;
     RECT  103.921 67.92 104.004 67.944 ;
     RECT  103.921 67.944 104.028 68.016 ;
     RECT  103.921 68.016 104.004 68.04 ;
     RECT  103.921 68.04 104.028 68.112 ;
     RECT  103.921 68.112 104.004 68.136 ;
     RECT  103.921 68.136 104.028 68.208 ;
     RECT  103.921 68.208 104.004 68.232 ;
     RECT  103.921 68.232 104.028 68.304 ;
     RECT  103.921 68.304 104.004 68.328 ;
     RECT  103.921 68.328 104.028 68.4 ;
     RECT  103.921 68.4 104.004 68.424 ;
     RECT  103.921 68.424 104.028 68.496 ;
     RECT  103.921 68.496 104.004 68.52 ;
     RECT  103.921 68.52 104.028 68.592 ;
     RECT  103.921 68.592 104.004 68.616 ;
     RECT  103.921 68.616 104.028 68.688 ;
     RECT  103.921 68.688 104.004 68.712 ;
     RECT  103.921 68.712 104.028 68.784 ;
     RECT  103.921 68.784 104.004 68.808 ;
     RECT  103.921 68.808 104.028 68.88 ;
     RECT  103.921 68.88 104.004 68.904 ;
     RECT  103.921 68.904 104.028 68.976 ;
     RECT  103.921 68.976 104.004 69 ;
     RECT  103.921 69 104.028 69.072 ;
     RECT  103.921 69.072 104.004 69.096 ;
     RECT  103.921 69.096 104.028 69.168 ;
     RECT  103.921 69.168 104.004 69.192 ;
     RECT  103.921 69.192 104.028 69.264 ;
     RECT  103.921 69.264 104.004 69.288 ;
     RECT  103.921 69.288 104.028 69.36 ;
     RECT  103.921 69.36 104.004 69.384 ;
     RECT  103.921 69.384 104.028 69.456 ;
     RECT  103.921 69.456 104.004 69.48 ;
     RECT  103.921 69.48 104.028 69.552 ;
     RECT  103.921 69.552 104.004 69.576 ;
     RECT  103.921 69.576 104.028 69.648 ;
     RECT  103.921 69.648 104.004 69.672 ;
     RECT  103.921 69.672 104.028 69.744 ;
     RECT  103.921 69.744 104.004 69.768 ;
     RECT  103.921 69.768 104.028 69.84 ;
     RECT  103.921 69.84 104.004 69.864 ;
     RECT  103.921 69.864 104.028 69.936 ;
     RECT  103.921 69.936 104.004 69.96 ;
     RECT  103.921 69.96 104.028 70.032 ;
     RECT  103.921 70.032 104.004 70.056 ;
     RECT  103.921 70.056 104.028 70.128 ;
     RECT  103.921 70.128 104.004 70.152 ;
     RECT  103.921 70.152 104.028 70.224 ;
     RECT  103.921 70.224 104.004 70.248 ;
     RECT  103.921 70.248 104.028 70.32 ;
     RECT  103.921 70.32 104.004 70.344 ;
     RECT  103.921 70.344 104.028 70.416 ;
     RECT  103.921 70.416 104.004 70.44 ;
     RECT  103.921 70.44 104.028 70.512 ;
     RECT  103.921 70.512 104.004 70.536 ;
     RECT  103.921 70.536 104.028 70.608 ;
     RECT  103.921 70.608 104.004 70.632 ;
     RECT  103.921 70.632 104.028 70.704 ;
     RECT  103.921 70.704 104.004 70.728 ;
     RECT  103.921 70.728 104.028 70.8 ;
     RECT  103.921 70.8 104.004 70.824 ;
     RECT  103.921 70.824 104.028 70.896 ;
     RECT  103.921 70.896 104.004 70.92 ;
     RECT  103.921 70.92 104.028 70.992 ;
     RECT  103.921 70.992 104.004 71.016 ;
     RECT  103.921 71.016 104.028 71.088 ;
     RECT  103.921 71.088 104.004 71.112 ;
     RECT  103.921 71.112 104.028 71.184 ;
     RECT  103.921 71.184 104.004 71.208 ;
     RECT  103.921 71.208 104.028 71.28 ;
     RECT  103.921 71.28 104.004 71.304 ;
     RECT  103.921 71.304 104.028 71.376 ;
     RECT  103.921 71.376 104.004 71.4 ;
     RECT  103.921 71.4 104.028 71.472 ;
     RECT  103.921 71.472 104.004 71.496 ;
     RECT  103.921 71.496 104.028 71.568 ;
     RECT  103.921 71.568 104.004 71.592 ;
     RECT  103.921 71.592 104.028 71.664 ;
     RECT  103.921 71.664 104.004 71.688 ;
     RECT  103.921 71.688 104.028 71.76 ;
     RECT  103.921 71.76 104.004 71.784 ;
     RECT  103.921 71.784 104.028 71.856 ;
     RECT  103.921 71.856 104.004 71.88 ;
     RECT  103.921 71.88 104.028 71.952 ;
     RECT  103.921 71.952 104.004 71.976 ;
     RECT  103.921 71.976 104.028 72.048 ;
     RECT  103.921 72.048 104.004 72.072 ;
     RECT  103.921 72.072 104.028 72.144 ;
     RECT  103.921 72.144 104.004 72.168 ;
     RECT  103.921 72.168 104.028 72.24 ;
     RECT  103.921 72.24 104.004 72.264 ;
     RECT  103.921 72.264 104.028 72.336 ;
     RECT  103.921 72.336 104.004 72.36 ;
     RECT  103.921 72.36 104.028 72.432 ;
     RECT  103.921 72.432 104.004 72.456 ;
     RECT  103.921 72.456 104.028 72.528 ;
     RECT  103.921 72.528 104.004 72.552 ;
     RECT  103.921 72.552 104.028 72.624 ;
     RECT  103.921 72.624 104.004 72.648 ;
     RECT  103.921 72.648 104.028 72.72 ;
     RECT  103.921 72.72 104.004 72.744 ;
     RECT  103.921 72.744 104.028 72.816 ;
     RECT  103.921 72.816 104.004 72.84 ;
     RECT  103.921 72.84 104.028 72.912 ;
     RECT  103.921 72.912 104.004 72.936 ;
     RECT  103.921 72.936 104.028 73.008 ;
     RECT  103.921 73.008 104.004 73.032 ;
     RECT  103.921 73.032 104.028 73.104 ;
     RECT  103.921 73.104 104.004 73.128 ;
     RECT  103.921 73.128 104.028 73.2 ;
     RECT  103.921 73.2 104.004 73.224 ;
     RECT  103.921 73.224 104.028 73.296 ;
     RECT  103.921 73.296 104.004 73.32 ;
     RECT  103.921 73.32 104.028 73.392 ;
     RECT  103.921 73.392 104.004 73.416 ;
     RECT  103.921 73.416 104.028 73.488 ;
     RECT  103.921 73.488 104.004 73.512 ;
     RECT  103.921 73.512 104.028 73.584 ;
     RECT  103.921 73.584 104.004 73.608 ;
     RECT  103.921 73.608 104.028 73.68 ;
     RECT  103.921 73.68 104.004 73.704 ;
     RECT  103.921 73.704 104.028 73.776 ;
     RECT  103.921 73.776 104.004 73.8 ;
     RECT  103.921 73.8 104.028 73.872 ;
     RECT  103.921 73.872 104.004 73.896 ;
     RECT  103.921 73.896 104.028 73.968 ;
     RECT  103.921 73.968 104.004 73.992 ;
     RECT  103.921 73.992 104.028 74.064 ;
     RECT  103.921 74.064 104.004 74.088 ;
     RECT  103.921 74.088 104.028 74.16 ;
     RECT  103.921 74.16 104.004 74.184 ;
     RECT  103.921 74.184 104.028 74.256 ;
     RECT  103.921 74.256 104.004 74.28 ;
     RECT  103.921 74.28 104.028 74.352 ;
     RECT  103.921 74.352 104.004 74.376 ;
     RECT  103.921 74.376 104.028 74.448 ;
     RECT  103.921 74.448 104.004 74.472 ;
     RECT  103.921 74.472 104.028 74.544 ;
     RECT  103.921 74.544 104.004 74.568 ;
     RECT  103.921 74.568 104.028 74.64 ;
     RECT  103.921 74.64 104.004 74.664 ;
     RECT  103.921 74.664 104.028 74.736 ;
     RECT  103.921 74.736 104.004 74.76 ;
     RECT  103.921 74.76 104.028 74.832 ;
     RECT  103.921 74.832 104.004 74.856 ;
     RECT  103.921 74.856 104.028 74.928 ;
     RECT  103.921 74.928 104.004 74.952 ;
     RECT  103.921 74.952 104.028 75.024 ;
     RECT  103.921 75.024 104.004 75.048 ;
     RECT  103.921 75.048 104.028 75.12 ;
     RECT  103.921 75.12 104.004 75.144 ;
     RECT  103.921 75.144 104.028 75.216 ;
     RECT  103.921 75.216 104.004 75.24 ;
     RECT  103.921 75.24 104.028 75.312 ;
     RECT  103.921 75.312 104.004 75.336 ;
     RECT  103.921 75.336 104.028 75.408 ;
     RECT  103.921 75.408 104.004 75.432 ;
     RECT  103.921 75.432 104.028 75.504 ;
     RECT  103.921 75.504 104.004 75.528 ;
     RECT  103.921 75.528 104.028 75.6 ;
     RECT  103.921 75.6 104.004 75.624 ;
     RECT  103.921 75.624 104.028 75.696 ;
     RECT  103.921 75.696 104.004 75.72 ;
     RECT  103.921 75.72 104.028 75.792 ;
     RECT  103.921 75.792 104.004 75.816 ;
     RECT  103.921 75.816 104.028 75.888 ;
     RECT  103.921 75.888 104.004 75.912 ;
     RECT  103.921 75.912 104.028 75.984 ;
     RECT  103.921 75.984 104.004 76.008 ;
     RECT  103.921 76.008 104.028 76.08 ;
     RECT  103.921 76.08 104.004 76.104 ;
     RECT  103.921 76.104 104.028 76.176 ;
     RECT  103.921 76.176 104.004 76.2 ;
     RECT  103.921 76.2 104.028 76.272 ;
     RECT  103.921 76.272 104.004 76.296 ;
     RECT  103.921 76.296 104.028 76.368 ;
     RECT  103.921 76.368 104.004 76.392 ;
     RECT  103.921 76.392 104.028 76.464 ;
     RECT  103.921 76.464 104.004 76.488 ;
     RECT  103.921 76.488 104.028 76.56 ;
     RECT  103.921 76.56 104.004 76.584 ;
     RECT  103.921 76.584 104.028 76.656 ;
     RECT  103.921 76.656 104.004 76.68 ;
     RECT  103.921 76.68 104.028 77.52 ;
     RECT  103.921 77.52 104.004 77.544 ;
     RECT  103.921 77.544 104.028 77.616 ;
     RECT  103.921 77.616 104.004 77.64 ;
     RECT  103.921 77.64 104.028 77.712 ;
     RECT  103.921 77.712 104.004 77.736 ;
     RECT  103.921 77.736 104.028 77.808 ;
     RECT  103.921 77.808 104.004 77.832 ;
     RECT  103.921 77.832 104.028 77.904 ;
     RECT  103.921 77.904 104.004 77.928 ;
     RECT  103.921 77.928 104.028 78 ;
     RECT  103.921 78 104.004 78.024 ;
     RECT  103.921 78.024 104.028 78.096 ;
     RECT  103.921 78.096 104.004 78.12 ;
     RECT  103.921 78.12 104.028 78.192 ;
     RECT  103.921 78.192 104.004 78.216 ;
     RECT  103.921 78.216 104.028 78.288 ;
     RECT  103.921 78.288 104.004 78.312 ;
     RECT  103.921 78.312 104.028 78.384 ;
     RECT  103.921 78.384 104.004 78.408 ;
     RECT  103.921 78.408 104.028 78.48 ;
     RECT  103.921 78.48 104.004 78.504 ;
     RECT  103.921 78.504 104.028 78.576 ;
     RECT  103.921 78.576 104.004 78.6 ;
     RECT  103.921 78.6 104.028 78.672 ;
     RECT  103.921 78.672 104.004 78.696 ;
     RECT  103.921 78.696 104.028 78.768 ;
     RECT  103.921 78.768 104.004 78.792 ;
     RECT  103.921 78.792 104.028 78.864 ;
     RECT  103.921 78.864 104.004 78.888 ;
     RECT  103.921 78.888 104.028 78.96 ;
     RECT  103.921 78.96 104.004 78.984 ;
     RECT  103.921 78.984 104.028 79.056 ;
     RECT  103.921 79.056 104.004 79.08 ;
     RECT  103.921 79.08 104.028 79.152 ;
     RECT  103.921 79.152 104.004 79.176 ;
     RECT  103.921 79.176 104.028 79.248 ;
     RECT  103.921 79.248 104.004 79.272 ;
     RECT  103.921 79.272 104.028 79.344 ;
     RECT  103.921 79.344 104.004 79.368 ;
     RECT  103.921 79.368 104.028 79.44 ;
     RECT  103.921 79.44 104.004 79.464 ;
     RECT  103.921 79.464 104.028 79.536 ;
     RECT  103.921 79.536 104.004 79.56 ;
     RECT  103.921 79.56 104.028 79.632 ;
     RECT  103.921 79.632 104.004 79.656 ;
     RECT  103.921 79.656 104.028 79.728 ;
     RECT  103.921 79.728 104.004 79.752 ;
     RECT  103.921 79.752 104.028 79.824 ;
     RECT  103.921 79.824 104.004 79.848 ;
     RECT  104.028 48 104.033 48.024 ;
     RECT  104.028 23.808 104.069 23.832 ;
     RECT  104.028 41.088 104.069 41.112 ;
     RECT  104.028 43.776 104.069 43.8 ;
     RECT  104.028 54.048 104.069 54.072 ;
     RECT  104.028 56.064 104.069 56.088 ;
     RECT  104.028 57.312 104.069 57.336 ;
     RECT  104.028 59.328 104.069 59.352 ;
     RECT  104.028 62.016 104.069 62.064 ;
     RECT  104.028 62.088 104.069 62.16 ;
     RECT  104.028 62.184 104.069 62.256 ;
     RECT  104.028 62.28 104.069 62.328 ;
     RECT  104.028 63.648 104.069 63.672 ;
     RECT  104.028 67.008 104.069 67.032 ;
     RECT  104.028 68.352 104.069 68.4 ;
     RECT  104.028 68.424 104.069 68.496 ;
     RECT  104.028 68.52 104.069 68.592 ;
     RECT  104.028 68.616 104.069 68.688 ;
     RECT  104.028 68.712 104.069 68.784 ;
     RECT  104.028 68.808 104.069 68.88 ;
     RECT  104.028 68.904 104.069 68.976 ;
     RECT  104.028 69 104.069 69.048 ;
     RECT  104.028 72.288 104.069 72.312 ;
     RECT  104.028 73.344 104.069 73.368 ;
     RECT  104.028 77.664 104.069 77.712 ;
     RECT  104.028 77.736 104.069 77.808 ;
     RECT  104.028 77.832 104.069 77.904 ;
     RECT  104.028 77.928 104.069 78 ;
     RECT  104.028 78.024 104.069 78.096 ;
     RECT  104.028 78.12 104.069 78.192 ;
     RECT  104.028 78.216 104.069 78.264 ;
     RECT  104.028 79.296 104.069 79.32 ;
    LAYER M5 ;
     RECT  2.4 2.137 2.52 2.151 ;
     RECT  5.1 2.137 5.22 2.151 ;
     RECT  7.8 2.137 7.92 2.151 ;
     RECT  10.5 2.137 10.62 2.151 ;
     RECT  13.2 2.137 13.32 2.151 ;
     RECT  15.9 2.137 16.02 2.151 ;
     RECT  18.6 2.137 18.72 2.151 ;
     RECT  21.3 2.137 21.42 2.151 ;
     RECT  24 2.137 24.12 2.151 ;
     RECT  26.7 2.137 26.82 2.151 ;
     RECT  29.4 2.137 29.52 2.151 ;
     RECT  32.1 2.137 32.22 2.151 ;
     RECT  34.8 2.137 34.92 2.151 ;
     RECT  37.5 2.137 37.62 2.151 ;
     RECT  40.2 2.137 40.32 2.151 ;
     RECT  42.9 2.137 43.02 2.151 ;
     RECT  45.6 2.137 45.72 2.151 ;
     RECT  48.3 2.137 48.42 2.151 ;
     RECT  51 2.137 51.12 2.151 ;
     RECT  53.7 2.137 53.82 2.151 ;
     RECT  56.4 2.137 56.52 2.151 ;
     RECT  59.1 2.137 59.22 2.151 ;
     RECT  61.8 2.137 61.92 2.151 ;
     RECT  64.5 2.137 64.62 2.151 ;
     RECT  67.2 2.137 67.32 2.151 ;
     RECT  69.9 2.137 70.02 2.151 ;
     RECT  72.6 2.137 72.72 2.151 ;
     RECT  75.3 2.137 75.42 2.151 ;
     RECT  78 2.137 78.12 2.151 ;
     RECT  80.7 2.137 80.82 2.151 ;
     RECT  83.4 2.137 83.52 2.151 ;
     RECT  86.1 2.137 86.22 2.151 ;
     RECT  88.8 2.137 88.92 2.151 ;
     RECT  91.5 2.137 91.62 2.151 ;
     RECT  94.2 2.137 94.32 2.151 ;
     RECT  96.9 2.137 97.02 2.151 ;
     RECT  99.6 2.137 99.72 2.151 ;
     RECT  91.5 2.151 91.812 24.181 ;
     RECT  90.624 24.181 91.812 24.467 ;
     RECT  102.528 30.757 102.648 30.947 ;
     RECT  103.92 30.757 103.944 30.947 ;
     RECT  69.9 2.151 70.212 31.477 ;
     RECT  69.9 31.477 70.392 31.763 ;
     RECT  53.7 2.151 54.012 34.453 ;
     RECT  78 2.151 78.312 34.453 ;
     RECT  86.1 2.151 86.412 34.453 ;
     RECT  53.7 34.453 54.744 34.739 ;
     RECT  78 34.453 78.696 34.739 ;
     RECT  86.1 34.453 86.664 34.739 ;
     RECT  45.6 2.151 45.912 37.909 ;
     RECT  45.6 37.909 46.056 38.195 ;
     RECT  69.9 31.763 70.212 40.117 ;
     RECT  69.9 40.117 70.392 40.403 ;
     RECT  69.9 40.403 70.212 41.941 ;
     RECT  56.4 2.151 56.712 42.133 ;
     RECT  59.1 2.151 59.412 42.133 ;
     RECT  102.48 42.133 102.504 42.611 ;
     RECT  68.976 41.941 70.212 42.709 ;
     RECT  61.8 2.151 62.112 43.333 ;
     RECT  59.1 42.133 60.168 43.717 ;
     RECT  61.248 43.333 62.112 43.717 ;
     RECT  68.976 42.709 70.344 44.677 ;
     RECT  59.1 43.717 62.112 44.869 ;
     RECT  67.2 2.151 67.512 44.965 ;
     RECT  34.8 2.151 35.112 45.493 ;
     RECT  66.48 44.965 67.512 45.493 ;
     RECT  37.5 2.151 37.812 45.973 ;
     RECT  34.128 45.493 35.112 46.021 ;
     RECT  36.576 45.973 37.812 46.213 ;
     RECT  59.1 44.869 62.52 46.501 ;
     RECT  40.2 2.151 40.512 46.789 ;
     RECT  34.08 46.021 35.112 46.837 ;
     RECT  34.032 46.837 35.112 47.077 ;
     RECT  36.24 46.213 37.812 47.077 ;
     RECT  40.08 46.789 40.512 47.125 ;
     RECT  48.3 2.151 48.612 47.125 ;
     RECT  40.08 47.125 40.872 47.653 ;
     RECT  59.1 46.501 63.432 49.813 ;
     RECT  64.5 2.151 64.812 49.813 ;
     RECT  42.9 2.151 43.212 50.533 ;
     RECT  59.1 49.813 64.812 50.533 ;
     RECT  48.192 47.125 48.612 51.205 ;
     RECT  66.48 45.493 67.848 51.253 ;
     RECT  68.976 44.677 70.392 51.253 ;
     RECT  38.88 43.285 38.904 51.637 ;
     RECT  40.08 47.653 40.968 51.637 ;
     RECT  42.48 50.533 43.212 51.829 ;
     RECT  59.1 50.533 65.016 51.829 ;
     RECT  56.4 42.133 57.624 51.877 ;
     RECT  56.4 51.877 57.672 52.405 ;
     RECT  59.1 51.829 65.112 52.885 ;
     RECT  66.48 51.253 70.392 52.885 ;
     RECT  34.032 47.077 37.812 53.317 ;
     RECT  38.88 51.637 40.968 53.317 ;
     RECT  44.304 50.677 44.328 53.509 ;
     RECT  45.6 38.195 45.912 53.509 ;
     RECT  51 2.151 51.312 53.557 ;
     RECT  41.952 51.829 43.212 53.845 ;
     RECT  44.304 53.509 45.912 53.845 ;
     RECT  34.032 53.317 40.968 54.133 ;
     RECT  41.952 53.845 45.912 54.133 ;
     RECT  2.4 2.151 2.712 54.421 ;
     RECT  2.4 54.421 3.384 54.709 ;
     RECT  2.304 54.709 3.384 54.949 ;
     RECT  2.304 54.949 3.48 54.997 ;
     RECT  2.304 54.997 3.864 55.283 ;
     RECT  0.144 55.141 0.168 55.379 ;
     RECT  34.032 54.133 45.912 55.717 ;
     RECT  2.4 55.283 3.864 55.813 ;
     RECT  5.1 2.151 5.412 55.813 ;
     RECT  34.032 55.717 46.008 56.245 ;
     RECT  53.7 34.739 54.012 56.437 ;
     RECT  2.4 55.813 5.412 56.627 ;
     RECT  34.032 56.245 46.68 56.773 ;
     RECT  51 53.557 51.576 57.013 ;
     RECT  47.808 51.205 48.612 57.397 ;
     RECT  53.7 56.437 54.744 57.541 ;
     RECT  56.112 52.405 57.672 57.541 ;
     RECT  53.7 57.541 57.672 58.645 ;
     RECT  53.7 58.645 58.056 59.221 ;
     RECT  59.1 52.885 70.392 59.221 ;
     RECT  51 57.013 51.624 60.325 ;
     RECT  51 60.325 52.008 60.949 ;
     RECT  53.184 59.221 70.392 60.949 ;
     RECT  98.592 62.245 98.616 62.483 ;
     RECT  47.76 57.397 48.612 65.221 ;
     RECT  49.872 67.093 49.896 68.629 ;
     RECT  26.7 2.151 27.012 79.429 ;
     RECT  72.6 2.151 72.912 80.293 ;
     RECT  26.7 79.429 27.384 90.565 ;
     RECT  32.1 2.151 32.412 91.285 ;
     RECT  26.7 90.565 27.864 91.717 ;
     RECT  29.4 2.151 29.712 91.717 ;
     RECT  72.6 80.293 73.128 91.861 ;
     RECT  4.704 56.627 5.412 91.907 ;
     RECT  51 60.949 70.392 92.965 ;
     RECT  34.032 56.773 46.728 93.205 ;
     RECT  47.76 65.221 48.84 93.205 ;
     RECT  31.968 91.285 32.412 93.253 ;
     RECT  34.032 93.205 48.84 93.397 ;
     RECT  49.872 68.629 49.992 93.397 ;
     RECT  34.032 93.397 49.992 93.445 ;
     RECT  51 92.965 70.44 93.445 ;
     RECT  2.4 56.627 3.24 94.403 ;
     RECT  34.032 93.445 70.44 96.565 ;
     RECT  72.6 91.861 73.224 96.613 ;
     RECT  72.6 96.613 73.512 97.187 ;
     RECT  34.032 96.565 70.968 98.725 ;
     RECT  33.84 98.725 70.968 99.637 ;
     RECT  26.7 91.717 29.712 99.731 ;
     RECT  33.6 99.637 70.968 100.213 ;
     RECT  26.7 99.731 27.864 100.307 ;
     RECT  31.92 93.253 32.412 100.931 ;
     RECT  33.408 100.213 70.968 101.507 ;
     RECT  72.6 97.187 73.224 101.747 ;
     RECT  34.032 101.507 70.392 102.083 ;
     RECT  36.336 102.083 70.392 102.371 ;
     RECT  42.336 102.371 70.392 102.515 ;
     RECT  36.336 102.371 41.256 102.611 ;
     RECT  42.336 102.515 68.088 102.659 ;
     RECT  36.336 102.611 39.048 102.707 ;
     RECT  69.168 102.515 70.392 102.707 ;
     RECT  36.72 102.707 39.048 102.755 ;
     RECT  34.032 102.083 35.304 102.803 ;
     RECT  42.336 102.659 68.04 102.995 ;
     RECT  34.032 102.803 35.112 103.091 ;
     RECT  69.168 102.707 70.344 103.091 ;
     RECT  34.656 103.091 35.112 103.235 ;
     RECT  39.024 102.755 39.048 103.235 ;
     RECT  42.336 102.995 67.752 103.235 ;
     RECT  69.9 103.091 70.344 103.235 ;
     RECT  42.768 103.235 67.752 103.283 ;
     RECT  36.72 102.755 37.812 103.331 ;
     RECT  42.9 103.283 67.512 103.331 ;
     RECT  44.976 103.331 67.512 103.379 ;
     RECT  2.4 94.403 2.712 103.419 ;
     RECT  5.1 91.907 5.412 103.419 ;
     RECT  7.8 2.151 8.112 103.419 ;
     RECT  10.5 2.151 10.812 103.419 ;
     RECT  13.2 2.151 13.512 103.419 ;
     RECT  15.9 2.151 16.212 103.419 ;
     RECT  18.6 2.151 18.912 103.419 ;
     RECT  21.3 2.151 21.612 103.419 ;
     RECT  24 2.151 24.312 103.419 ;
     RECT  26.7 100.307 27.012 103.419 ;
     RECT  29.4 99.731 29.712 103.419 ;
     RECT  32.1 100.931 32.412 103.419 ;
     RECT  34.8 103.235 35.112 103.419 ;
     RECT  37.5 103.331 37.812 103.419 ;
     RECT  40.2 102.611 41.112 103.419 ;
     RECT  42.9 103.331 43.992 103.419 ;
     RECT  67.2 103.379 67.512 103.419 ;
     RECT  69.9 103.235 70.212 103.419 ;
     RECT  72.6 101.747 72.912 103.419 ;
     RECT  75.3 2.151 75.612 103.419 ;
     RECT  78 34.739 78.312 103.419 ;
     RECT  80.7 2.151 81.012 103.419 ;
     RECT  83.4 2.151 83.712 103.419 ;
     RECT  86.1 34.739 86.412 103.419 ;
     RECT  88.8 2.151 89.112 103.419 ;
     RECT  91.5 24.467 91.812 103.419 ;
     RECT  94.2 2.151 94.512 103.419 ;
     RECT  96.9 2.151 97.212 103.419 ;
     RECT  99.6 2.151 99.912 103.419 ;
     RECT  2.592 103.419 2.712 103.433 ;
     RECT  5.292 103.419 5.412 103.433 ;
     RECT  7.992 103.419 8.112 103.433 ;
     RECT  10.692 103.419 10.812 103.433 ;
     RECT  13.392 103.419 13.512 103.433 ;
     RECT  16.092 103.419 16.212 103.433 ;
     RECT  18.792 103.419 18.912 103.433 ;
     RECT  21.492 103.419 21.612 103.433 ;
     RECT  24.192 103.419 24.312 103.433 ;
     RECT  26.892 103.419 27.012 103.433 ;
     RECT  29.592 103.419 29.712 103.433 ;
     RECT  32.292 103.419 32.412 103.433 ;
     RECT  34.992 103.419 35.112 103.433 ;
     RECT  37.692 103.419 37.812 103.433 ;
     RECT  40.392 103.419 41.112 103.433 ;
     RECT  43.092 103.419 43.992 103.433 ;
     RECT  67.392 103.419 67.512 103.433 ;
     RECT  70.092 103.419 70.212 103.433 ;
     RECT  72.792 103.419 72.912 103.433 ;
     RECT  75.492 103.419 75.612 103.433 ;
     RECT  78.192 103.419 78.312 103.433 ;
     RECT  80.892 103.419 81.012 103.433 ;
     RECT  83.592 103.419 83.712 103.433 ;
     RECT  86.292 103.419 86.412 103.433 ;
     RECT  88.992 103.419 89.112 103.433 ;
     RECT  91.692 103.419 91.812 103.433 ;
     RECT  94.392 103.419 94.512 103.433 ;
     RECT  97.092 103.419 97.212 103.433 ;
     RECT  99.792 103.419 99.912 103.433 ;
     RECT  44.976 103.379 65.928 103.475 ;
     RECT  44.976 103.475 65.544 103.715 ;
     RECT  40.8 103.433 41.112 103.763 ;
     RECT  46.08 103.715 65.544 103.859 ;
     RECT  43.968 103.433 43.992 104.387 ;
     RECT  46.08 103.859 64.968 104.435 ;
     RECT  46.608 104.435 64.968 105.732 ;
     RECT  46.632 105.732 46.704 105.744 ;
     RECT  46.728 105.732 46.8 105.744 ;
     RECT  46.824 105.732 46.896 105.744 ;
     RECT  46.92 105.732 46.992 105.744 ;
     RECT  47.016 105.732 47.088 105.744 ;
     RECT  47.112 105.732 47.184 105.744 ;
     RECT  47.208 105.732 47.28 105.744 ;
     RECT  47.304 105.732 47.376 105.744 ;
     RECT  47.4 105.732 47.472 105.744 ;
     RECT  47.496 105.732 47.568 105.744 ;
     RECT  47.592 105.732 47.664 105.744 ;
     RECT  47.688 105.732 47.76 105.744 ;
     RECT  47.784 105.732 47.856 105.744 ;
     RECT  47.88 105.732 47.952 105.744 ;
     RECT  47.976 105.732 48.048 105.744 ;
     RECT  48.072 105.732 48.144 105.744 ;
     RECT  48.168 105.732 48.24 105.744 ;
     RECT  48.264 105.732 48.336 105.744 ;
     RECT  48.36 105.732 48.432 105.744 ;
     RECT  48.456 105.732 48.528 105.744 ;
     RECT  48.552 105.732 48.624 105.744 ;
     RECT  48.648 105.732 48.72 105.744 ;
     RECT  48.744 105.732 48.816 105.744 ;
     RECT  48.84 105.732 48.912 105.744 ;
     RECT  48.936 105.732 49.008 105.744 ;
     RECT  49.032 105.732 49.104 105.744 ;
     RECT  49.128 105.732 49.2 105.744 ;
     RECT  49.224 105.732 49.296 105.744 ;
     RECT  49.32 105.732 49.392 105.744 ;
     RECT  49.416 105.732 49.488 105.744 ;
     RECT  49.512 105.732 49.584 105.744 ;
     RECT  49.608 105.732 49.68 105.744 ;
     RECT  49.704 105.732 49.776 105.744 ;
     RECT  49.8 105.732 49.872 105.744 ;
     RECT  49.896 105.732 49.968 105.744 ;
     RECT  49.992 105.732 50.064 105.744 ;
     RECT  50.088 105.732 50.16 105.744 ;
     RECT  50.184 105.732 50.256 105.744 ;
     RECT  50.28 105.732 50.352 105.744 ;
     RECT  50.376 105.732 50.448 105.744 ;
     RECT  50.472 105.732 50.544 105.744 ;
     RECT  50.568 105.732 50.64 105.744 ;
     RECT  50.664 105.732 50.736 105.744 ;
     RECT  50.76 105.732 50.832 105.744 ;
     RECT  50.856 105.732 50.928 105.744 ;
     RECT  50.952 105.732 51.024 105.744 ;
     RECT  51.048 105.732 51.12 105.744 ;
     RECT  51.144 105.732 51.216 105.744 ;
     RECT  51.24 105.732 51.312 105.744 ;
     RECT  51.336 105.732 51.408 105.744 ;
     RECT  51.432 105.732 51.504 105.744 ;
     RECT  51.528 105.732 51.6 105.744 ;
     RECT  51.624 105.732 51.696 105.744 ;
     RECT  51.72 105.732 51.792 105.744 ;
     RECT  51.816 105.732 51.888 105.744 ;
     RECT  51.912 105.732 51.984 105.744 ;
     RECT  52.008 105.732 52.08 105.744 ;
     RECT  52.104 105.732 52.176 105.744 ;
     RECT  52.2 105.732 52.272 105.744 ;
     RECT  52.296 105.732 52.368 105.744 ;
     RECT  52.392 105.732 52.464 105.744 ;
     RECT  52.488 105.732 52.56 105.744 ;
     RECT  52.584 105.732 52.656 105.744 ;
     RECT  52.68 105.732 52.752 105.744 ;
     RECT  52.776 105.732 52.848 105.744 ;
     RECT  52.872 105.732 52.944 105.744 ;
     RECT  52.968 105.732 53.04 105.744 ;
     RECT  53.064 105.732 53.136 105.744 ;
     RECT  53.16 105.732 53.232 105.744 ;
     RECT  53.256 105.732 53.328 105.744 ;
     RECT  53.352 105.732 53.424 105.744 ;
     RECT  53.448 105.732 53.52 105.744 ;
     RECT  53.544 105.732 53.616 105.744 ;
     RECT  53.64 105.732 53.712 105.744 ;
     RECT  53.736 105.732 53.808 105.744 ;
     RECT  53.832 105.732 53.904 105.744 ;
     RECT  53.928 105.732 54 105.744 ;
     RECT  54.024 105.732 54.096 105.744 ;
     RECT  54.12 105.732 54.192 105.744 ;
     RECT  54.216 105.732 54.288 105.744 ;
     RECT  54.312 105.732 54.384 105.744 ;
     RECT  54.408 105.732 54.48 105.744 ;
     RECT  54.504 105.732 54.576 105.744 ;
     RECT  54.6 105.732 54.672 105.744 ;
     RECT  54.696 105.732 54.768 105.744 ;
     RECT  54.792 105.732 54.864 105.744 ;
     RECT  54.888 105.732 54.96 105.744 ;
     RECT  54.984 105.732 55.056 105.744 ;
     RECT  55.08 105.732 55.152 105.744 ;
     RECT  55.176 105.732 55.248 105.744 ;
     RECT  55.272 105.732 55.344 105.744 ;
     RECT  55.368 105.732 55.44 105.744 ;
     RECT  55.464 105.732 55.536 105.744 ;
     RECT  55.56 105.732 55.632 105.744 ;
     RECT  55.656 105.732 55.728 105.744 ;
     RECT  55.752 105.732 55.824 105.744 ;
     RECT  55.848 105.732 55.92 105.744 ;
     RECT  55.944 105.732 56.016 105.744 ;
     RECT  56.04 105.732 56.112 105.744 ;
     RECT  56.136 105.732 56.208 105.744 ;
     RECT  56.232 105.732 56.304 105.744 ;
     RECT  56.328 105.732 56.4 105.744 ;
     RECT  56.424 105.732 56.496 105.744 ;
     RECT  56.52 105.732 56.592 105.744 ;
     RECT  56.616 105.732 56.688 105.744 ;
     RECT  56.712 105.732 56.784 105.744 ;
     RECT  56.808 105.732 56.88 105.744 ;
     RECT  56.904 105.732 56.976 105.744 ;
     RECT  57 105.732 57.072 105.744 ;
     RECT  57.096 105.732 57.168 105.744 ;
     RECT  57.192 105.732 57.264 105.744 ;
     RECT  57.288 105.732 57.36 105.744 ;
     RECT  57.384 105.732 57.456 105.744 ;
     RECT  57.48 105.732 57.552 105.744 ;
     RECT  57.576 105.732 57.648 105.744 ;
     RECT  57.672 105.732 57.744 105.744 ;
     RECT  57.768 105.732 57.84 105.744 ;
     RECT  57.864 105.732 57.936 105.744 ;
     RECT  57.96 105.732 58.032 105.744 ;
     RECT  58.056 105.732 58.128 105.744 ;
     RECT  58.152 105.732 58.224 105.744 ;
     RECT  58.248 105.732 58.32 105.744 ;
     RECT  58.344 105.732 58.416 105.744 ;
     RECT  58.44 105.732 58.512 105.744 ;
     RECT  58.536 105.732 58.608 105.744 ;
     RECT  58.632 105.732 58.704 105.744 ;
     RECT  58.728 105.732 58.8 105.744 ;
     RECT  58.824 105.732 58.896 105.744 ;
     RECT  58.92 105.732 58.992 105.744 ;
     RECT  59.016 105.732 59.088 105.744 ;
     RECT  59.112 105.732 59.184 105.744 ;
     RECT  59.208 105.732 59.28 105.744 ;
     RECT  59.304 105.732 59.376 105.744 ;
     RECT  59.4 105.732 59.472 105.744 ;
     RECT  59.496 105.732 59.568 105.744 ;
     RECT  59.592 105.732 59.664 105.744 ;
     RECT  59.688 105.732 59.76 105.744 ;
     RECT  59.784 105.732 59.856 105.744 ;
     RECT  59.88 105.732 59.952 105.744 ;
     RECT  59.976 105.732 60.048 105.744 ;
     RECT  60.072 105.732 60.144 105.744 ;
     RECT  60.168 105.732 60.24 105.744 ;
     RECT  60.264 105.732 60.336 105.744 ;
     RECT  60.36 105.732 60.432 105.744 ;
     RECT  60.456 105.732 60.528 105.744 ;
     RECT  60.552 105.732 60.624 105.744 ;
     RECT  60.648 105.732 60.72 105.744 ;
     RECT  60.744 105.732 60.816 105.744 ;
     RECT  60.84 105.732 60.912 105.744 ;
     RECT  60.936 105.732 61.008 105.744 ;
     RECT  61.032 105.732 61.104 105.744 ;
     RECT  61.128 105.732 61.2 105.744 ;
     RECT  61.224 105.732 61.296 105.744 ;
     RECT  61.32 105.732 61.392 105.744 ;
     RECT  61.416 105.732 61.488 105.744 ;
     RECT  61.512 105.732 61.584 105.744 ;
     RECT  61.608 105.732 61.68 105.744 ;
     RECT  61.704 105.732 61.776 105.744 ;
     RECT  61.8 105.732 61.872 105.744 ;
     RECT  61.896 105.732 61.968 105.744 ;
     RECT  61.992 105.732 62.064 105.744 ;
     RECT  62.088 105.732 62.16 105.744 ;
     RECT  62.184 105.732 62.256 105.744 ;
     RECT  62.28 105.732 62.352 105.744 ;
     RECT  62.376 105.732 62.448 105.744 ;
     RECT  62.472 105.732 62.544 105.744 ;
     RECT  62.568 105.732 62.64 105.744 ;
     RECT  62.664 105.732 62.736 105.744 ;
     RECT  62.76 105.732 62.832 105.744 ;
     RECT  62.856 105.732 62.928 105.744 ;
     RECT  62.952 105.732 63.024 105.744 ;
     RECT  63.048 105.732 63.12 105.744 ;
     RECT  63.144 105.732 63.216 105.744 ;
     RECT  63.24 105.732 63.312 105.744 ;
     RECT  63.336 105.732 63.408 105.744 ;
     RECT  63.432 105.732 63.504 105.744 ;
     RECT  63.528 105.732 63.6 105.744 ;
     RECT  63.624 105.732 63.696 105.744 ;
     RECT  63.72 105.732 63.792 105.744 ;
     RECT  63.816 105.732 63.888 105.744 ;
     RECT  63.912 105.732 63.984 105.744 ;
     RECT  64.008 105.732 64.08 105.744 ;
     RECT  64.104 105.732 64.176 105.744 ;
     RECT  64.2 105.732 64.272 105.744 ;
     RECT  64.296 105.732 64.368 105.744 ;
     RECT  64.392 105.732 64.464 105.744 ;
     RECT  64.488 105.732 64.56 105.744 ;
     RECT  64.584 105.732 64.656 105.744 ;
     RECT  64.68 105.732 64.752 105.744 ;
     RECT  64.776 105.732 64.848 105.744 ;
     RECT  64.872 105.732 64.944 105.744 ;
     RECT  40.8 103.763 40.824 105.779 ;
     RECT  44.976 103.715 45 105.779 ;
     RECT  89.112 24.181 90.624 24.467 ;
     RECT  102.648 30.757 103.908 30.947 ;
     RECT  67.512 41.941 68.976 45.493 ;
     RECT  57.624 42.133 59.1 51.877 ;
     RECT  37.812 43.285 38.88 53.317 ;
     RECT  38.904 43.285 40.2 46.789 ;
     RECT  60.168 43.333 61.248 43.717 ;
     RECT  67.848 45.493 68.976 51.253 ;
     RECT  35.112 45.973 36.576 46.213 ;
     RECT  35.112 46.213 36.24 47.077 ;
     RECT  63.432 46.501 64.5 49.813 ;
     RECT  38.904 46.789 40.08 51.637 ;
     RECT  40.968 50.533 42.48 51.829 ;
     RECT  65.016 50.533 66.48 51.829 ;
     RECT  43.212 50.677 44.304 53.845 ;
     RECT  44.328 50.677 45.6 53.509 ;
     RECT  40.968 51.829 41.952 54.133 ;
     RECT  65.112 51.829 66.48 52.885 ;
     RECT  57.672 51.877 59.1 58.645 ;
     RECT  3.864 54.997 5.1 55.813 ;
     RECT  46.68 56.245 47.808 56.773 ;
     RECT  54.744 56.437 56.112 57.541 ;
     RECT  3.24 56.627 4.704 91.907 ;
     RECT  46.728 56.773 47.808 57.397 ;
     RECT  46.728 57.397 47.76 93.205 ;
     RECT  58.056 58.645 59.1 59.221 ;
     RECT  52.008 60.325 53.184 60.949 ;
     RECT  97.212 62.245 98.592 62.483 ;
     RECT  98.616 62.245 99.6 62.483 ;
     RECT  48.84 67.093 49.872 93.397 ;
     RECT  49.896 67.093 51 68.629 ;
     RECT  49.992 68.629 51 93.445 ;
     RECT  32.412 98.725 33.84 99.637 ;
     RECT  32.412 99.637 33.6 100.213 ;
     RECT  32.412 100.213 33.408 101.507 ;
     RECT  35.304 102.083 36.336 102.707 ;
     RECT  41.256 102.371 42.336 102.611 ;
     RECT  68.088 102.515 69.168 102.659 ;
     RECT  39.048 102.611 40.2 103.235 ;
     RECT  41.112 102.611 42.336 103.235 ;
     RECT  68.04 102.659 69.168 102.995 ;
     RECT  35.304 102.707 36.72 102.803 ;
     RECT  37.812 102.755 39.024 103.235 ;
     RECT  67.752 102.995 69.168 103.091 ;
     RECT  43.992 103.331 44.976 104.387 ;
     RECT  65.928 103.379 67.2 103.419 ;
     RECT  65.928 103.419 67.392 103.433 ;
     RECT  45 103.715 46.08 104.435 ;
  END
END qfd_rlyh0_600_NE_104x106
END LIBRARY
